Omron CX-Programmer project NewProject (CX-Programmer 9.41)

# PLC CJ1CJ2CS1ModbusSinglePort: CJ1M CPU11
I/O table (CPU CJ1M-CPU11): rack 0 slot 0 CJ1W-SCU41-V1

## Global symbols (name address type ; comment)
Clear_Error_Log W215.03 BOOL
Consecutive_Writes W217 INT
Current_Stack_Pointer W2 DWORD
EasyModbusPort1Command1 D32300 CHANNEL
EasyModbusPort1Command10 D32309 CHANNEL
EasyModbusPort1Command2 D32301 CHANNEL
EasyModbusPort1Command3 D32302 CHANNEL
EasyModbusPort1Command4 D32303 CHANNEL
EasyModbusPort1Command5 D32304 CHANNEL
EasyModbusPort1Command6 D32305 CHANNEL
EasyModbusPort1Command7 D32306 CHANNEL
EasyModbusPort1Command8 D32307 CHANNEL
EasyModbusPort1Command9 D32308 CHANNEL
EasyModbusPort1Response1 D32350 CHANNEL
EasyModbusPort1Response10 D32359 CHANNEL
EasyModbusPort1Response2 D32351 CHANNEL
EasyModbusPort1Response3 D32352 CHANNEL
EasyModbusPort1Response4 D32353 CHANNEL
EasyModbusPort1Response5 D32354 CHANNEL
EasyModbusPort1Response6 D32355 CHANNEL
EasyModbusPort1Response7 D32356 CHANNEL
EasyModbusPort1Response8 D32357 CHANNEL
EasyModbusPort1Response9 D32358 CHANNEL
Easy_Modbus_Execute A640.00 BOOL
Easy_Modbus_NG_Complete A640.02 BOOL
Easy_Modbus_OK_Complete A640.01 BOOL
EndOfListMarkerReadItem1 D5009 CHANNEL
EndOfListMarkerReadItem10 D5099 CHANNEL
EndOfListMarkerReadItem100 D5999 CHANNEL
EndOfListMarkerReadItem11 D5109 CHANNEL
EndOfListMarkerReadItem12 D5119 CHANNEL
EndOfListMarkerReadItem13 D5129 CHANNEL
EndOfListMarkerReadItem14 D5139 CHANNEL
EndOfListMarkerReadItem15 D5149 CHANNEL
EndOfListMarkerReadItem16 D5159 CHANNEL
EndOfListMarkerReadItem17 D5169 CHANNEL
EndOfListMarkerReadItem18 D5179 CHANNEL
EndOfListMarkerReadItem19 D5189 CHANNEL
EndOfListMarkerReadItem2 D5019 CHANNEL
EndOfListMarkerReadItem20 D5199 CHANNEL
EndOfListMarkerReadItem21 D5209 CHANNEL
EndOfListMarkerReadItem22 D5219 CHANNEL
EndOfListMarkerReadItem23 D5229 CHANNEL
EndOfListMarkerReadItem24 D5239 CHANNEL
EndOfListMarkerReadItem25 D5249 CHANNEL
EndOfListMarkerReadItem26 D5259 CHANNEL
EndOfListMarkerReadItem27 D5269 CHANNEL
EndOfListMarkerReadItem28 D5279 CHANNEL
EndOfListMarkerReadItem29 D5289 CHANNEL
EndOfListMarkerReadItem3 D5029 CHANNEL
EndOfListMarkerReadItem30 D5299 CHANNEL
EndOfListMarkerReadItem31 D5309 CHANNEL
EndOfListMarkerReadItem32 D5319 CHANNEL
EndOfListMarkerReadItem33 D5329 CHANNEL
EndOfListMarkerReadItem34 D5339 CHANNEL
EndOfListMarkerReadItem35 D5349 CHANNEL
EndOfListMarkerReadItem36 D5359 CHANNEL
EndOfListMarkerReadItem37 D5369 CHANNEL
EndOfListMarkerReadItem38 D5379 CHANNEL
EndOfListMarkerReadItem39 D5389 CHANNEL
EndOfListMarkerReadItem4 D5039 CHANNEL
EndOfListMarkerReadItem40 D5399 CHANNEL
EndOfListMarkerReadItem41 D5409 CHANNEL
EndOfListMarkerReadItem42 D5419 CHANNEL
EndOfListMarkerReadItem43 D5429 CHANNEL
EndOfListMarkerReadItem44 D5439 CHANNEL
EndOfListMarkerReadItem45 D5449 CHANNEL
EndOfListMarkerReadItem46 D5459 CHANNEL
EndOfListMarkerReadItem47 D5469 CHANNEL
EndOfListMarkerReadItem48 D5479 CHANNEL
EndOfListMarkerReadItem49 D5489 CHANNEL
EndOfListMarkerReadItem5 D5049 CHANNEL
EndOfListMarkerReadItem50 D5499 CHANNEL
EndOfListMarkerReadItem51 D5509 CHANNEL
EndOfListMarkerReadItem52 D5519 CHANNEL
EndOfListMarkerReadItem53 D5529 CHANNEL
EndOfListMarkerReadItem54 D5539 CHANNEL
EndOfListMarkerReadItem55 D5549 CHANNEL
EndOfListMarkerReadItem56 D5559 CHANNEL
EndOfListMarkerReadItem57 D5569 CHANNEL
EndOfListMarkerReadItem58 D5579 CHANNEL
EndOfListMarkerReadItem59 D5589 CHANNEL
EndOfListMarkerReadItem6 D5059 CHANNEL
EndOfListMarkerReadItem60 D5599 CHANNEL
EndOfListMarkerReadItem61 D5609 CHANNEL
EndOfListMarkerReadItem62 D5619 CHANNEL
EndOfListMarkerReadItem63 D5629 CHANNEL
EndOfListMarkerReadItem64 D5639 CHANNEL
EndOfListMarkerReadItem65 D5649 CHANNEL
EndOfListMarkerReadItem66 D5659 CHANNEL
EndOfListMarkerReadItem67 D5669 CHANNEL
EndOfListMarkerReadItem68 D5679 CHANNEL
EndOfListMarkerReadItem69 D5689 CHANNEL
EndOfListMarkerReadItem7 D5069 CHANNEL
EndOfListMarkerReadItem70 D5699 CHANNEL
EndOfListMarkerReadItem71 D5709 CHANNEL
EndOfListMarkerReadItem72 D5719 CHANNEL
EndOfListMarkerReadItem73 D5729 CHANNEL
EndOfListMarkerReadItem74 D5739 CHANNEL
EndOfListMarkerReadItem75 D5749 CHANNEL
EndOfListMarkerReadItem76 D5759 CHANNEL
EndOfListMarkerReadItem77 D5769 CHANNEL
EndOfListMarkerReadItem78 D5779 CHANNEL
EndOfListMarkerReadItem79 D5789 CHANNEL
EndOfListMarkerReadItem8 D5079 CHANNEL
EndOfListMarkerReadItem80 D5799 CHANNEL
EndOfListMarkerReadItem81 D5809 CHANNEL
EndOfListMarkerReadItem82 D5819 CHANNEL
EndOfListMarkerReadItem83 D5829 CHANNEL
EndOfListMarkerReadItem84 D5839 CHANNEL
EndOfListMarkerReadItem85 D5849 CHANNEL
EndOfListMarkerReadItem86 D5859 CHANNEL
EndOfListMarkerReadItem87 D5869 CHANNEL
EndOfListMarkerReadItem88 D5879 CHANNEL
EndOfListMarkerReadItem89 D5889 CHANNEL
EndOfListMarkerReadItem9 D5089 CHANNEL
EndOfListMarkerReadItem90 D5899 CHANNEL
EndOfListMarkerReadItem91 D5909 CHANNEL
EndOfListMarkerReadItem92 D5919 CHANNEL
EndOfListMarkerReadItem93 D5929 CHANNEL
EndOfListMarkerReadItem94 D5939 CHANNEL
EndOfListMarkerReadItem95 D5949 CHANNEL
EndOfListMarkerReadItem96 D5959 CHANNEL
EndOfListMarkerReadItem97 D5969 CHANNEL
EndOfListMarkerReadItem98 D5979 CHANNEL
EndOfListMarkerReadItem99 D5989 CHANNEL
EndOfListMarkerWriteItem1 D6009 CHANNEL
EndOfListMarkerWriteItem10 D6099 CHANNEL
EndOfListMarkerWriteItem100 D6999 CHANNEL
EndOfListMarkerWriteItem11 D6109 CHANNEL
EndOfListMarkerWriteItem12 D6119 CHANNEL
EndOfListMarkerWriteItem13 D6129 CHANNEL
EndOfListMarkerWriteItem14 D6139 CHANNEL
EndOfListMarkerWriteItem15 D6149 CHANNEL
EndOfListMarkerWriteItem16 D6159 CHANNEL
EndOfListMarkerWriteItem17 D6169 CHANNEL
EndOfListMarkerWriteItem18 D6179 CHANNEL
EndOfListMarkerWriteItem19 D6189 CHANNEL
EndOfListMarkerWriteItem2 D6019 CHANNEL
EndOfListMarkerWriteItem20 D6199 CHANNEL
EndOfListMarkerWriteItem21 D6209 CHANNEL
EndOfListMarkerWriteItem22 D6219 CHANNEL
EndOfListMarkerWriteItem23 D6229 CHANNEL
EndOfListMarkerWriteItem24 D6239 CHANNEL
EndOfListMarkerWriteItem25 D6249 CHANNEL
EndOfListMarkerWriteItem26 D6259 CHANNEL
EndOfListMarkerWriteItem27 D6269 CHANNEL
EndOfListMarkerWriteItem28 D6279 CHANNEL
EndOfListMarkerWriteItem29 D6289 CHANNEL
EndOfListMarkerWriteItem3 D6029 CHANNEL
EndOfListMarkerWriteItem30 D6299 CHANNEL
EndOfListMarkerWriteItem31 D6309 CHANNEL
EndOfListMarkerWriteItem32 D6319 CHANNEL
EndOfListMarkerWriteItem33 D6329 CHANNEL
EndOfListMarkerWriteItem34 D6339 CHANNEL
EndOfListMarkerWriteItem35 D6349 CHANNEL
EndOfListMarkerWriteItem36 D6359 CHANNEL
EndOfListMarkerWriteItem37 D6369 CHANNEL
EndOfListMarkerWriteItem38 D6379 CHANNEL
EndOfListMarkerWriteItem39 D6389 CHANNEL
EndOfListMarkerWriteItem4 D6039 CHANNEL
EndOfListMarkerWriteItem40 D6399 CHANNEL
EndOfListMarkerWriteItem41 D6409 CHANNEL
EndOfListMarkerWriteItem42 D6419 CHANNEL
EndOfListMarkerWriteItem43 D6429 CHANNEL
EndOfListMarkerWriteItem44 D6439 CHANNEL
EndOfListMarkerWriteItem45 D6449 CHANNEL
EndOfListMarkerWriteItem46 D6459 CHANNEL
EndOfListMarkerWriteItem47 D6469 CHANNEL
EndOfListMarkerWriteItem48 D6479 CHANNEL
EndOfListMarkerWriteItem49 D6489 CHANNEL
EndOfListMarkerWriteItem5 D6049 CHANNEL
EndOfListMarkerWriteItem50 D6499 CHANNEL
EndOfListMarkerWriteItem51 D6509 CHANNEL
EndOfListMarkerWriteItem52 D6519 CHANNEL
EndOfListMarkerWriteItem53 D6529 CHANNEL
EndOfListMarkerWriteItem54 D6539 CHANNEL
EndOfListMarkerWriteItem55 D6549 CHANNEL
EndOfListMarkerWriteItem56 D6559 CHANNEL
EndOfListMarkerWriteItem57 D6569 CHANNEL
EndOfListMarkerWriteItem58 D6579 CHANNEL
EndOfListMarkerWriteItem59 D6589 CHANNEL
EndOfListMarkerWriteItem6 D6059 CHANNEL
EndOfListMarkerWriteItem60 D6599 CHANNEL
EndOfListMarkerWriteItem61 D6609 CHANNEL
EndOfListMarkerWriteItem62 D6619 CHANNEL
EndOfListMarkerWriteItem63 D6629 CHANNEL
EndOfListMarkerWriteItem64 D6639 CHANNEL
EndOfListMarkerWriteItem65 D6649 CHANNEL
EndOfListMarkerWriteItem66 D6659 CHANNEL
EndOfListMarkerWriteItem67 D6669 CHANNEL
EndOfListMarkerWriteItem68 D6679 CHANNEL
EndOfListMarkerWriteItem69 D6689 CHANNEL
EndOfListMarkerWriteItem7 D6069 CHANNEL
EndOfListMarkerWriteItem70 D6699 CHANNEL
EndOfListMarkerWriteItem71 D6709 CHANNEL
EndOfListMarkerWriteItem72 D6719 CHANNEL
EndOfListMarkerWriteItem73 D6729 CHANNEL
EndOfListMarkerWriteItem74 D6739 CHANNEL
EndOfListMarkerWriteItem75 D6749 CHANNEL
EndOfListMarkerWriteItem76 D6759 CHANNEL
EndOfListMarkerWriteItem77 D6769 CHANNEL
EndOfListMarkerWriteItem78 D6779 CHANNEL
EndOfListMarkerWriteItem79 D6789 CHANNEL
EndOfListMarkerWriteItem8 D6079 CHANNEL
EndOfListMarkerWriteItem80 D6799 CHANNEL
EndOfListMarkerWriteItem81 D6809 CHANNEL
EndOfListMarkerWriteItem82 D6819 CHANNEL
EndOfListMarkerWriteItem83 D6829 CHANNEL
EndOfListMarkerWriteItem84 D6839 CHANNEL
EndOfListMarkerWriteItem85 D6849 CHANNEL
EndOfListMarkerWriteItem86 D6859 CHANNEL
EndOfListMarkerWriteItem87 D6869 CHANNEL
EndOfListMarkerWriteItem88 D6879 CHANNEL
EndOfListMarkerWriteItem89 D6889 CHANNEL
EndOfListMarkerWriteItem9 D6089 CHANNEL
EndOfListMarkerWriteItem90 D6899 CHANNEL
EndOfListMarkerWriteItem91 D6909 CHANNEL
EndOfListMarkerWriteItem92 D6919 CHANNEL
EndOfListMarkerWriteItem93 D6929 CHANNEL
EndOfListMarkerWriteItem94 D6939 CHANNEL
EndOfListMarkerWriteItem95 D6949 CHANNEL
EndOfListMarkerWriteItem96 D6959 CHANNEL
EndOfListMarkerWriteItem97 D6969 CHANNEL
EndOfListMarkerWriteItem98 D6979 CHANNEL
EndOfListMarkerWriteItem99 D6989 CHANNEL
FirstWordResponseDataReadItem1 D5004 CHANNEL
FirstWordResponseDataReadItem10 D5094 CHANNEL
FirstWordResponseDataReadItem100 D5994 CHANNEL
FirstWordResponseDataReadItem11 D5104 CHANNEL
FirstWordResponseDataReadItem12 D5114 CHANNEL
FirstWordResponseDataReadItem13 D5124 CHANNEL
FirstWordResponseDataReadItem14 D5134 CHANNEL
FirstWordResponseDataReadItem15 D5144 CHANNEL
FirstWordResponseDataReadItem16 D5154 CHANNEL
FirstWordResponseDataReadItem17 D5164 CHANNEL
FirstWordResponseDataReadItem18 D5174 CHANNEL
FirstWordResponseDataReadItem19 D5184 CHANNEL
FirstWordResponseDataReadItem2 D5014 CHANNEL
FirstWordResponseDataReadItem20 D5194 CHANNEL
FirstWordResponseDataReadItem21 D5204 CHANNEL
FirstWordResponseDataReadItem22 D5214 CHANNEL
FirstWordResponseDataReadItem23 D5224 CHANNEL
FirstWordResponseDataReadItem24 D5234 CHANNEL
FirstWordResponseDataReadItem25 D5244 CHANNEL
FirstWordResponseDataReadItem26 D5254 CHANNEL
FirstWordResponseDataReadItem27 D5264 CHANNEL
FirstWordResponseDataReadItem28 D5274 CHANNEL
FirstWordResponseDataReadItem29 D5284 CHANNEL
FirstWordResponseDataReadItem3 D5024 CHANNEL
FirstWordResponseDataReadItem30 D5294 CHANNEL
FirstWordResponseDataReadItem31 D5304 CHANNEL
FirstWordResponseDataReadItem32 D5314 CHANNEL
FirstWordResponseDataReadItem33 D5324 CHANNEL
FirstWordResponseDataReadItem34 D5334 CHANNEL
FirstWordResponseDataReadItem35 D5344 CHANNEL
FirstWordResponseDataReadItem36 D5354 CHANNEL
FirstWordResponseDataReadItem37 D5364 CHANNEL
FirstWordResponseDataReadItem38 D5374 CHANNEL
FirstWordResponseDataReadItem39 D5384 CHANNEL
FirstWordResponseDataReadItem4 D5034 CHANNEL
FirstWordResponseDataReadItem40 D5394 CHANNEL
FirstWordResponseDataReadItem41 D5404 CHANNEL
FirstWordResponseDataReadItem42 D5414 CHANNEL
FirstWordResponseDataReadItem43 D5424 CHANNEL
FirstWordResponseDataReadItem44 D5434 CHANNEL
FirstWordResponseDataReadItem45 D5444 CHANNEL
FirstWordResponseDataReadItem46 D5454 CHANNEL
FirstWordResponseDataReadItem47 D5464 CHANNEL
FirstWordResponseDataReadItem48 D5474 CHANNEL
FirstWordResponseDataReadItem49 D5484 CHANNEL
FirstWordResponseDataReadItem5 D5044 CHANNEL
FirstWordResponseDataReadItem50 D5494 CHANNEL
FirstWordResponseDataReadItem51 D5504 CHANNEL
FirstWordResponseDataReadItem52 D5514 CHANNEL
FirstWordResponseDataReadItem53 D5524 CHANNEL
FirstWordResponseDataReadItem54 D5534 CHANNEL
FirstWordResponseDataReadItem55 D5544 CHANNEL
FirstWordResponseDataReadItem56 D5554 CHANNEL
FirstWordResponseDataReadItem57 D5564 CHANNEL
FirstWordResponseDataReadItem58 D5574 CHANNEL
FirstWordResponseDataReadItem59 D5584 CHANNEL
FirstWordResponseDataReadItem6 D5054 CHANNEL
FirstWordResponseDataReadItem60 D5594 CHANNEL
FirstWordResponseDataReadItem61 D5604 CHANNEL
FirstWordResponseDataReadItem62 D5614 CHANNEL
FirstWordResponseDataReadItem63 D5624 CHANNEL
FirstWordResponseDataReadItem64 D5634 CHANNEL
FirstWordResponseDataReadItem65 D5644 CHANNEL
FirstWordResponseDataReadItem66 D5654 CHANNEL
FirstWordResponseDataReadItem67 D5664 CHANNEL
FirstWordResponseDataReadItem68 D5674 CHANNEL
FirstWordResponseDataReadItem69 D5684 CHANNEL
FirstWordResponseDataReadItem7 D5064 CHANNEL
FirstWordResponseDataReadItem70 D5694 CHANNEL
FirstWordResponseDataReadItem71 D5704 CHANNEL
FirstWordResponseDataReadItem72 D5714 CHANNEL
FirstWordResponseDataReadItem73 D5724 CHANNEL
FirstWordResponseDataReadItem74 D5734 CHANNEL
FirstWordResponseDataReadItem75 D5744 CHANNEL
FirstWordResponseDataReadItem76 D5754 CHANNEL
FirstWordResponseDataReadItem77 D5764 CHANNEL
FirstWordResponseDataReadItem78 D5774 CHANNEL
FirstWordResponseDataReadItem79 D5784 CHANNEL
FirstWordResponseDataReadItem8 D5074 CHANNEL
FirstWordResponseDataReadItem80 D5794 CHANNEL
FirstWordResponseDataReadItem81 D5804 CHANNEL
FirstWordResponseDataReadItem82 D5814 CHANNEL
FirstWordResponseDataReadItem83 D5824 CHANNEL
FirstWordResponseDataReadItem84 D5834 CHANNEL
FirstWordResponseDataReadItem85 D5844 CHANNEL
FirstWordResponseDataReadItem86 D5854 CHANNEL
FirstWordResponseDataReadItem87 D5864 CHANNEL
FirstWordResponseDataReadItem88 D5874 CHANNEL
FirstWordResponseDataReadItem89 D5884 CHANNEL
FirstWordResponseDataReadItem9 D5084 CHANNEL
FirstWordResponseDataReadItem90 D5894 CHANNEL
FirstWordResponseDataReadItem91 D5904 CHANNEL
FirstWordResponseDataReadItem92 D5914 CHANNEL
FirstWordResponseDataReadItem93 D5924 CHANNEL
FirstWordResponseDataReadItem94 D5934 CHANNEL
FirstWordResponseDataReadItem95 D5944 CHANNEL
FirstWordResponseDataReadItem96 D5954 CHANNEL
FirstWordResponseDataReadItem97 D5964 CHANNEL
FirstWordResponseDataReadItem98 D5974 CHANNEL
FirstWordResponseDataReadItem99 D5984 CHANNEL
FirstWordWriteDataMirrorWriteItem1 D6006 CHANNEL
FirstWordWriteDataMirrorWriteItem10 D6096 CHANNEL
FirstWordWriteDataMirrorWriteItem100 D6996 CHANNEL
FirstWordWriteDataMirrorWriteItem11 D6106 CHANNEL
FirstWordWriteDataMirrorWriteItem12 D6116 CHANNEL
FirstWordWriteDataMirrorWriteItem13 D6126 CHANNEL
FirstWordWriteDataMirrorWriteItem14 D6136 CHANNEL
FirstWordWriteDataMirrorWriteItem15 D6146 CHANNEL
FirstWordWriteDataMirrorWriteItem16 D6156 CHANNEL
FirstWordWriteDataMirrorWriteItem17 D6166 CHANNEL
FirstWordWriteDataMirrorWriteItem18 D6176 CHANNEL
FirstWordWriteDataMirrorWriteItem19 D6186 CHANNEL
FirstWordWriteDataMirrorWriteItem2 D6016 CHANNEL
FirstWordWriteDataMirrorWriteItem20 D6196 CHANNEL
FirstWordWriteDataMirrorWriteItem21 D6206 CHANNEL
FirstWordWriteDataMirrorWriteItem22 D6216 CHANNEL
FirstWordWriteDataMirrorWriteItem23 D6226 CHANNEL
FirstWordWriteDataMirrorWriteItem24 D6236 CHANNEL
FirstWordWriteDataMirrorWriteItem25 D6246 CHANNEL
FirstWordWriteDataMirrorWriteItem26 D6256 CHANNEL
FirstWordWriteDataMirrorWriteItem27 D6266 CHANNEL
FirstWordWriteDataMirrorWriteItem28 D6276 CHANNEL
FirstWordWriteDataMirrorWriteItem29 D6286 CHANNEL
FirstWordWriteDataMirrorWriteItem3 D6026 CHANNEL
FirstWordWriteDataMirrorWriteItem30 D6296 CHANNEL
FirstWordWriteDataMirrorWriteItem31 D6306 CHANNEL
FirstWordWriteDataMirrorWriteItem32 D6316 CHANNEL
FirstWordWriteDataMirrorWriteItem33 D6326 CHANNEL
FirstWordWriteDataMirrorWriteItem34 D6336 CHANNEL
FirstWordWriteDataMirrorWriteItem35 D6346 CHANNEL
FirstWordWriteDataMirrorWriteItem36 D6356 CHANNEL
FirstWordWriteDataMirrorWriteItem37 D6366 CHANNEL
FirstWordWriteDataMirrorWriteItem38 D6376 CHANNEL
FirstWordWriteDataMirrorWriteItem39 D6386 CHANNEL
FirstWordWriteDataMirrorWriteItem4 D6036 CHANNEL
FirstWordWriteDataMirrorWriteItem40 D6396 CHANNEL
FirstWordWriteDataMirrorWriteItem41 D6406 CHANNEL
FirstWordWriteDataMirrorWriteItem42 D6416 CHANNEL
FirstWordWriteDataMirrorWriteItem43 D6426 CHANNEL
FirstWordWriteDataMirrorWriteItem44 D6436 CHANNEL
FirstWordWriteDataMirrorWriteItem45 D6446 CHANNEL
FirstWordWriteDataMirrorWriteItem46 D6456 CHANNEL
FirstWordWriteDataMirrorWriteItem47 D6466 CHANNEL
FirstWordWriteDataMirrorWriteItem48 D6476 CHANNEL
FirstWordWriteDataMirrorWriteItem49 D6486 CHANNEL
FirstWordWriteDataMirrorWriteItem5 D6046 CHANNEL
FirstWordWriteDataMirrorWriteItem50 D6496 CHANNEL
FirstWordWriteDataMirrorWriteItem51 D6506 CHANNEL
FirstWordWriteDataMirrorWriteItem52 D6516 CHANNEL
FirstWordWriteDataMirrorWriteItem53 D6526 CHANNEL
FirstWordWriteDataMirrorWriteItem54 D6536 CHANNEL
FirstWordWriteDataMirrorWriteItem55 D6546 CHANNEL
FirstWordWriteDataMirrorWriteItem56 D6556 CHANNEL
FirstWordWriteDataMirrorWriteItem57 D6566 CHANNEL
FirstWordWriteDataMirrorWriteItem58 D6576 CHANNEL
FirstWordWriteDataMirrorWriteItem59 D6586 CHANNEL
FirstWordWriteDataMirrorWriteItem6 D6056 CHANNEL
FirstWordWriteDataMirrorWriteItem60 D6596 CHANNEL
FirstWordWriteDataMirrorWriteItem61 D6606 CHANNEL
FirstWordWriteDataMirrorWriteItem62 D6616 CHANNEL
FirstWordWriteDataMirrorWriteItem63 D6626 CHANNEL
FirstWordWriteDataMirrorWriteItem64 D6636 CHANNEL
FirstWordWriteDataMirrorWriteItem65 D6646 CHANNEL
FirstWordWriteDataMirrorWriteItem66 D6656 CHANNEL
FirstWordWriteDataMirrorWriteItem67 D6666 CHANNEL
FirstWordWriteDataMirrorWriteItem68 D6676 CHANNEL
FirstWordWriteDataMirrorWriteItem69 D6686 CHANNEL
FirstWordWriteDataMirrorWriteItem7 D6066 CHANNEL
FirstWordWriteDataMirrorWriteItem70 D6696 CHANNEL
FirstWordWriteDataMirrorWriteItem71 D6706 CHANNEL
FirstWordWriteDataMirrorWriteItem72 D6716 CHANNEL
FirstWordWriteDataMirrorWriteItem73 D6726 CHANNEL
FirstWordWriteDataMirrorWriteItem74 D6736 CHANNEL
FirstWordWriteDataMirrorWriteItem75 D6746 CHANNEL
FirstWordWriteDataMirrorWriteItem76 D6756 CHANNEL
FirstWordWriteDataMirrorWriteItem77 D6766 CHANNEL
FirstWordWriteDataMirrorWriteItem78 D6776 CHANNEL
FirstWordWriteDataMirrorWriteItem79 D6786 CHANNEL
FirstWordWriteDataMirrorWriteItem8 D6076 CHANNEL
FirstWordWriteDataMirrorWriteItem80 D6796 CHANNEL
FirstWordWriteDataMirrorWriteItem81 D6806 CHANNEL
FirstWordWriteDataMirrorWriteItem82 D6816 CHANNEL
FirstWordWriteDataMirrorWriteItem83 D6826 CHANNEL
FirstWordWriteDataMirrorWriteItem84 D6836 CHANNEL
FirstWordWriteDataMirrorWriteItem85 D6846 CHANNEL
FirstWordWriteDataMirrorWriteItem86 D6856 CHANNEL
FirstWordWriteDataMirrorWriteItem87 D6866 CHANNEL
FirstWordWriteDataMirrorWriteItem88 D6876 CHANNEL
FirstWordWriteDataMirrorWriteItem89 D6886 CHANNEL
FirstWordWriteDataMirrorWriteItem9 D6086 CHANNEL
FirstWordWriteDataMirrorWriteItem90 D6896 CHANNEL
FirstWordWriteDataMirrorWriteItem91 D6906 CHANNEL
FirstWordWriteDataMirrorWriteItem92 D6916 CHANNEL
FirstWordWriteDataMirrorWriteItem93 D6926 CHANNEL
FirstWordWriteDataMirrorWriteItem94 D6936 CHANNEL
FirstWordWriteDataMirrorWriteItem95 D6946 CHANNEL
FirstWordWriteDataMirrorWriteItem96 D6956 CHANNEL
FirstWordWriteDataMirrorWriteItem97 D6966 CHANNEL
FirstWordWriteDataMirrorWriteItem98 D6976 CHANNEL
FirstWordWriteDataMirrorWriteItem99 D6986 CHANNEL
FirstWordWriteDataWriteItem1 D6004 CHANNEL
FirstWordWriteDataWriteItem10 D6094 CHANNEL
FirstWordWriteDataWriteItem100 D6994 CHANNEL
FirstWordWriteDataWriteItem11 D6104 CHANNEL
FirstWordWriteDataWriteItem12 D6114 CHANNEL
FirstWordWriteDataWriteItem13 D6124 CHANNEL
FirstWordWriteDataWriteItem14 D6134 CHANNEL
FirstWordWriteDataWriteItem15 D6144 CHANNEL
FirstWordWriteDataWriteItem16 D6154 CHANNEL
FirstWordWriteDataWriteItem17 D6164 CHANNEL
FirstWordWriteDataWriteItem18 D6174 CHANNEL
FirstWordWriteDataWriteItem19 D6184 CHANNEL
FirstWordWriteDataWriteItem2 D6014 CHANNEL
FirstWordWriteDataWriteItem20 D6194 CHANNEL
FirstWordWriteDataWriteItem21 D6204 CHANNEL
FirstWordWriteDataWriteItem22 D6214 CHANNEL
FirstWordWriteDataWriteItem23 D6224 CHANNEL
FirstWordWriteDataWriteItem24 D6234 CHANNEL
FirstWordWriteDataWriteItem25 D6244 CHANNEL
FirstWordWriteDataWriteItem26 D6254 CHANNEL
FirstWordWriteDataWriteItem27 D6264 CHANNEL
FirstWordWriteDataWriteItem28 D6274 CHANNEL
FirstWordWriteDataWriteItem29 D6284 CHANNEL
FirstWordWriteDataWriteItem3 D6024 CHANNEL
FirstWordWriteDataWriteItem30 D6294 CHANNEL
FirstWordWriteDataWriteItem31 D6304 CHANNEL
FirstWordWriteDataWriteItem32 D6314 CHANNEL
FirstWordWriteDataWriteItem33 D6324 CHANNEL
FirstWordWriteDataWriteItem34 D6334 CHANNEL
FirstWordWriteDataWriteItem35 D6344 CHANNEL
FirstWordWriteDataWriteItem36 D6354 CHANNEL
FirstWordWriteDataWriteItem37 D6364 CHANNEL
FirstWordWriteDataWriteItem38 D6374 CHANNEL
FirstWordWriteDataWriteItem39 D6384 CHANNEL
FirstWordWriteDataWriteItem4 D6034 CHANNEL
FirstWordWriteDataWriteItem40 D6394 CHANNEL
FirstWordWriteDataWriteItem41 D6404 CHANNEL
FirstWordWriteDataWriteItem42 D6414 CHANNEL
FirstWordWriteDataWriteItem43 D6424 CHANNEL
FirstWordWriteDataWriteItem44 D6434 CHANNEL
FirstWordWriteDataWriteItem45 D6444 CHANNEL
FirstWordWriteDataWriteItem46 D6454 CHANNEL
FirstWordWriteDataWriteItem47 D6464 CHANNEL
FirstWordWriteDataWriteItem48 D6474 CHANNEL
FirstWordWriteDataWriteItem49 D6484 CHANNEL
FirstWordWriteDataWriteItem5 D6044 CHANNEL
FirstWordWriteDataWriteItem50 D6494 CHANNEL
FirstWordWriteDataWriteItem51 D6504 CHANNEL
FirstWordWriteDataWriteItem52 D6514 CHANNEL
FirstWordWriteDataWriteItem53 D6524 CHANNEL
FirstWordWriteDataWriteItem54 D6534 CHANNEL
FirstWordWriteDataWriteItem55 D6544 CHANNEL
FirstWordWriteDataWriteItem56 D6554 CHANNEL
FirstWordWriteDataWriteItem57 D6564 CHANNEL
FirstWordWriteDataWriteItem58 D6574 CHANNEL
FirstWordWriteDataWriteItem59 D6584 CHANNEL
FirstWordWriteDataWriteItem6 D6054 CHANNEL
FirstWordWriteDataWriteItem60 D6594 CHANNEL
FirstWordWriteDataWriteItem61 D6604 CHANNEL
FirstWordWriteDataWriteItem62 D6614 CHANNEL
FirstWordWriteDataWriteItem63 D6624 CHANNEL
FirstWordWriteDataWriteItem64 D6634 CHANNEL
FirstWordWriteDataWriteItem65 D6644 CHANNEL
FirstWordWriteDataWriteItem66 D6654 CHANNEL
FirstWordWriteDataWriteItem67 D6664 CHANNEL
FirstWordWriteDataWriteItem68 D6674 CHANNEL
FirstWordWriteDataWriteItem69 D6684 CHANNEL
FirstWordWriteDataWriteItem7 D6064 CHANNEL
FirstWordWriteDataWriteItem70 D6694 CHANNEL
FirstWordWriteDataWriteItem71 D6704 CHANNEL
FirstWordWriteDataWriteItem72 D6714 CHANNEL
FirstWordWriteDataWriteItem73 D6724 CHANNEL
FirstWordWriteDataWriteItem74 D6734 CHANNEL
FirstWordWriteDataWriteItem75 D6744 CHANNEL
FirstWordWriteDataWriteItem76 D6754 CHANNEL
FirstWordWriteDataWriteItem77 D6764 CHANNEL
FirstWordWriteDataWriteItem78 D6774 CHANNEL
FirstWordWriteDataWriteItem79 D6784 CHANNEL
FirstWordWriteDataWriteItem8 D6074 CHANNEL
FirstWordWriteDataWriteItem80 D6794 CHANNEL
FirstWordWriteDataWriteItem81 D6804 CHANNEL
FirstWordWriteDataWriteItem82 D6814 CHANNEL
FirstWordWriteDataWriteItem83 D6824 CHANNEL
FirstWordWriteDataWriteItem84 D6834 CHANNEL
FirstWordWriteDataWriteItem85 D6844 CHANNEL
FirstWordWriteDataWriteItem86 D6854 CHANNEL
FirstWordWriteDataWriteItem87 D6864 CHANNEL
FirstWordWriteDataWriteItem88 D6874 CHANNEL
FirstWordWriteDataWriteItem89 D6884 CHANNEL
FirstWordWriteDataWriteItem9 D6084 CHANNEL
FirstWordWriteDataWriteItem90 D6894 CHANNEL
FirstWordWriteDataWriteItem91 D6904 CHANNEL
FirstWordWriteDataWriteItem92 D6914 CHANNEL
FirstWordWriteDataWriteItem93 D6924 CHANNEL
FirstWordWriteDataWriteItem94 D6934 CHANNEL
FirstWordWriteDataWriteItem95 D6944 CHANNEL
FirstWordWriteDataWriteItem96 D6954 CHANNEL
FirstWordWriteDataWriteItem97 D6964 CHANNEL
FirstWordWriteDataWriteItem98 D6974 CHANNEL
FirstWordWriteDataWriteItem99 D6984 CHANNEL
LastModbusCommandReceived1 W240 CHANNEL
LastModbusCommandReceived10 W249 CHANNEL
LastModbusCommandReceived2 W241 CHANNEL
LastModbusCommandReceived3 W242 CHANNEL
LastModbusCommandReceived4 W243 CHANNEL
LastModbusCommandReceived5 W244 CHANNEL
LastModbusCommandReceived6 W245 CHANNEL
LastModbusCommandReceived7 W246 CHANNEL
LastModbusCommandReceived8 W247 CHANNEL
LastModbusCommandReceived9 W248 CHANNEL
LastModbusCommandSent1 W230 CHANNEL
LastModbusCommandSent10 W239 CHANNEL
LastModbusCommandSent2 W231 CHANNEL
LastModbusCommandSent3 W232 CHANNEL
LastModbusCommandSent4 W233 CHANNEL
LastModbusCommandSent5 W234 CHANNEL
LastModbusCommandSent6 W235 CHANNEL
LastModbusCommandSent7 W236 CHANNEL
LastModbusCommandSent8 W237 CHANNEL
LastModbusCommandSent9 W238 CHANNEL
LogAnEasyModbusError W215.00 BOOL
Logical_Port_Ready A202.07 BOOL
ModbusErrorDMAddress1 W221 CHANNEL
ModbusErrorDMAddress2 W223 CHANNEL
ModbusErrorDMAddress3 W225 CHANNEL
ModbusErrorDMAddress4 W227 CHANNEL
ModbusErrorDMAddress5 W229 CHANNEL
ModbusErrorNodeFunction1 W220 CHANNEL
ModbusErrorNodeFunction2 W222 CHANNEL
ModbusErrorNodeFunction3 W224 CHANNEL
ModbusErrorNodeFunction4 W226 CHANNEL
ModbusErrorNodeFunction5 W228 CHANNEL
ModbusFunctionCodeReadItem1 D5001 CHANNEL
ModbusFunctionCodeReadItem10 D5091 CHANNEL
ModbusFunctionCodeReadItem100 D5991 CHANNEL
ModbusFunctionCodeReadItem11 D5101 CHANNEL
ModbusFunctionCodeReadItem12 D5111 CHANNEL
ModbusFunctionCodeReadItem13 D5121 CHANNEL
ModbusFunctionCodeReadItem14 D5131 CHANNEL
ModbusFunctionCodeReadItem15 D5141 CHANNEL
ModbusFunctionCodeReadItem16 D5151 CHANNEL
ModbusFunctionCodeReadItem17 D5161 CHANNEL
ModbusFunctionCodeReadItem18 D5171 CHANNEL
ModbusFunctionCodeReadItem19 D5181 CHANNEL
ModbusFunctionCodeReadItem2 D5011 CHANNEL
ModbusFunctionCodeReadItem20 D5191 CHANNEL
ModbusFunctionCodeReadItem21 D5201 CHANNEL
ModbusFunctionCodeReadItem22 D5211 CHANNEL
ModbusFunctionCodeReadItem23 D5221 CHANNEL
ModbusFunctionCodeReadItem24 D5231 CHANNEL
ModbusFunctionCodeReadItem25 D5241 CHANNEL
ModbusFunctionCodeReadItem26 D5251 CHANNEL
ModbusFunctionCodeReadItem27 D5261 CHANNEL
ModbusFunctionCodeReadItem28 D5271 CHANNEL
ModbusFunctionCodeReadItem29 D5281 CHANNEL
ModbusFunctionCodeReadItem3 D5021 CHANNEL
ModbusFunctionCodeReadItem30 D5291 CHANNEL
ModbusFunctionCodeReadItem31 D5301 CHANNEL
ModbusFunctionCodeReadItem32 D5311 CHANNEL
ModbusFunctionCodeReadItem33 D5321 CHANNEL
ModbusFunctionCodeReadItem34 D5331 CHANNEL
ModbusFunctionCodeReadItem35 D5341 CHANNEL
ModbusFunctionCodeReadItem36 D5351 CHANNEL
ModbusFunctionCodeReadItem37 D5361 CHANNEL
ModbusFunctionCodeReadItem38 D5371 CHANNEL
ModbusFunctionCodeReadItem39 D5381 CHANNEL
ModbusFunctionCodeReadItem4 D5031 CHANNEL
ModbusFunctionCodeReadItem40 D5391 CHANNEL
ModbusFunctionCodeReadItem41 D5401 CHANNEL
ModbusFunctionCodeReadItem42 D5411 CHANNEL
ModbusFunctionCodeReadItem43 D5421 CHANNEL
ModbusFunctionCodeReadItem44 D5431 CHANNEL
ModbusFunctionCodeReadItem45 D5441 CHANNEL
ModbusFunctionCodeReadItem46 D5451 CHANNEL
ModbusFunctionCodeReadItem47 D5461 CHANNEL
ModbusFunctionCodeReadItem48 D5471 CHANNEL
ModbusFunctionCodeReadItem49 D5481 CHANNEL
ModbusFunctionCodeReadItem5 D5041 CHANNEL
ModbusFunctionCodeReadItem50 D5491 CHANNEL
ModbusFunctionCodeReadItem51 D5501 CHANNEL
ModbusFunctionCodeReadItem52 D5511 CHANNEL
ModbusFunctionCodeReadItem53 D5521 CHANNEL
ModbusFunctionCodeReadItem54 D5531 CHANNEL
ModbusFunctionCodeReadItem55 D5541 CHANNEL
ModbusFunctionCodeReadItem56 D5551 CHANNEL
ModbusFunctionCodeReadItem57 D5561 CHANNEL
ModbusFunctionCodeReadItem58 D5571 CHANNEL
ModbusFunctionCodeReadItem59 D5581 CHANNEL
ModbusFunctionCodeReadItem6 D5051 CHANNEL
ModbusFunctionCodeReadItem60 D5591 CHANNEL
ModbusFunctionCodeReadItem61 D5601 CHANNEL
ModbusFunctionCodeReadItem62 D5611 CHANNEL
ModbusFunctionCodeReadItem63 D5621 CHANNEL
ModbusFunctionCodeReadItem64 D5631 CHANNEL
ModbusFunctionCodeReadItem65 D5641 CHANNEL
ModbusFunctionCodeReadItem66 D5651 CHANNEL
ModbusFunctionCodeReadItem67 D5661 CHANNEL
ModbusFunctionCodeReadItem68 D5671 CHANNEL
ModbusFunctionCodeReadItem69 D5681 CHANNEL
ModbusFunctionCodeReadItem7 D5061 CHANNEL
ModbusFunctionCodeReadItem70 D5691 CHANNEL
ModbusFunctionCodeReadItem71 D5701 CHANNEL
ModbusFunctionCodeReadItem72 D5711 CHANNEL
ModbusFunctionCodeReadItem73 D5721 CHANNEL
ModbusFunctionCodeReadItem74 D5731 CHANNEL
ModbusFunctionCodeReadItem75 D5741 CHANNEL
ModbusFunctionCodeReadItem76 D5751 CHANNEL
ModbusFunctionCodeReadItem77 D5761 CHANNEL
ModbusFunctionCodeReadItem78 D5771 CHANNEL
ModbusFunctionCodeReadItem79 D5781 CHANNEL
ModbusFunctionCodeReadItem8 D5071 CHANNEL
ModbusFunctionCodeReadItem80 D5791 CHANNEL
ModbusFunctionCodeReadItem81 D5801 CHANNEL
ModbusFunctionCodeReadItem82 D5811 CHANNEL
ModbusFunctionCodeReadItem83 D5821 CHANNEL
ModbusFunctionCodeReadItem84 D5831 CHANNEL
ModbusFunctionCodeReadItem85 D5841 CHANNEL
ModbusFunctionCodeReadItem86 D5851 CHANNEL
ModbusFunctionCodeReadItem87 D5861 CHANNEL
ModbusFunctionCodeReadItem88 D5871 CHANNEL
ModbusFunctionCodeReadItem89 D5881 CHANNEL
ModbusFunctionCodeReadItem9 D5081 CHANNEL
ModbusFunctionCodeReadItem90 D5891 CHANNEL
ModbusFunctionCodeReadItem91 D5901 CHANNEL
ModbusFunctionCodeReadItem92 D5911 CHANNEL
ModbusFunctionCodeReadItem93 D5921 CHANNEL
ModbusFunctionCodeReadItem94 D5931 CHANNEL
ModbusFunctionCodeReadItem95 D5941 CHANNEL
ModbusFunctionCodeReadItem96 D5951 CHANNEL
ModbusFunctionCodeReadItem97 D5961 CHANNEL
ModbusFunctionCodeReadItem98 D5971 CHANNEL
ModbusFunctionCodeReadItem99 D5981 CHANNEL
ModbusFunctionCodeWriteItem1 D6001 CHANNEL
ModbusFunctionCodeWriteItem10 D6091 CHANNEL
ModbusFunctionCodeWriteItem100 D6991 CHANNEL
ModbusFunctionCodeWriteItem11 D6101 CHANNEL
ModbusFunctionCodeWriteItem12 D6111 CHANNEL
ModbusFunctionCodeWriteItem13 D6121 CHANNEL
ModbusFunctionCodeWriteItem14 D6131 CHANNEL
ModbusFunctionCodeWriteItem15 D6141 CHANNEL
ModbusFunctionCodeWriteItem16 D6151 CHANNEL
ModbusFunctionCodeWriteItem17 D6161 CHANNEL
ModbusFunctionCodeWriteItem18 D6171 CHANNEL
ModbusFunctionCodeWriteItem19 D6181 CHANNEL
ModbusFunctionCodeWriteItem2 D6011 CHANNEL
ModbusFunctionCodeWriteItem20 D6191 CHANNEL
ModbusFunctionCodeWriteItem21 D6201 CHANNEL
ModbusFunctionCodeWriteItem22 D6211 CHANNEL
ModbusFunctionCodeWriteItem23 D6221 CHANNEL
ModbusFunctionCodeWriteItem24 D6231 CHANNEL
ModbusFunctionCodeWriteItem25 D6241 CHANNEL
ModbusFunctionCodeWriteItem26 D6251 CHANNEL
ModbusFunctionCodeWriteItem27 D6261 CHANNEL
ModbusFunctionCodeWriteItem28 D6271 CHANNEL
ModbusFunctionCodeWriteItem29 D6281 CHANNEL
ModbusFunctionCodeWriteItem3 D6021 CHANNEL
ModbusFunctionCodeWriteItem30 D6291 CHANNEL
ModbusFunctionCodeWriteItem31 D6301 CHANNEL
ModbusFunctionCodeWriteItem32 D6311 CHANNEL
ModbusFunctionCodeWriteItem33 D6321 CHANNEL
ModbusFunctionCodeWriteItem34 D6331 CHANNEL
ModbusFunctionCodeWriteItem35 D6341 CHANNEL
ModbusFunctionCodeWriteItem36 D6351 CHANNEL
ModbusFunctionCodeWriteItem37 D6361 CHANNEL
ModbusFunctionCodeWriteItem38 D6371 CHANNEL
ModbusFunctionCodeWriteItem39 D6381 CHANNEL
ModbusFunctionCodeWriteItem4 D6031 CHANNEL
ModbusFunctionCodeWriteItem40 D6391 CHANNEL
ModbusFunctionCodeWriteItem41 D6401 CHANNEL
ModbusFunctionCodeWriteItem42 D6411 CHANNEL
ModbusFunctionCodeWriteItem43 D6421 CHANNEL
ModbusFunctionCodeWriteItem44 D6431 CHANNEL
ModbusFunctionCodeWriteItem45 D6441 CHANNEL
ModbusFunctionCodeWriteItem46 D6451 CHANNEL
ModbusFunctionCodeWriteItem47 D6461 CHANNEL
ModbusFunctionCodeWriteItem48 D6471 CHANNEL
ModbusFunctionCodeWriteItem49 D6481 CHANNEL
ModbusFunctionCodeWriteItem5 D6041 CHANNEL
ModbusFunctionCodeWriteItem50 D6491 CHANNEL
ModbusFunctionCodeWriteItem51 D6501 CHANNEL
ModbusFunctionCodeWriteItem52 D6511 CHANNEL
ModbusFunctionCodeWriteItem53 D6521 CHANNEL
ModbusFunctionCodeWriteItem54 D6531 CHANNEL
ModbusFunctionCodeWriteItem55 D6541 CHANNEL
ModbusFunctionCodeWriteItem56 D6551 CHANNEL
ModbusFunctionCodeWriteItem57 D6561 CHANNEL
ModbusFunctionCodeWriteItem58 D6571 CHANNEL
ModbusFunctionCodeWriteItem59 D6581 CHANNEL
ModbusFunctionCodeWriteItem6 D6051 CHANNEL
ModbusFunctionCodeWriteItem60 D6591 CHANNEL
ModbusFunctionCodeWriteItem61 D6601 CHANNEL
ModbusFunctionCodeWriteItem62 D6611 CHANNEL
ModbusFunctionCodeWriteItem63 D6621 CHANNEL
ModbusFunctionCodeWriteItem64 D6631 CHANNEL
ModbusFunctionCodeWriteItem65 D6641 CHANNEL
ModbusFunctionCodeWriteItem66 D6651 CHANNEL
ModbusFunctionCodeWriteItem67 D6661 CHANNEL
ModbusFunctionCodeWriteItem68 D6671 CHANNEL
ModbusFunctionCodeWriteItem69 D6681 CHANNEL
ModbusFunctionCodeWriteItem7 D6061 CHANNEL
ModbusFunctionCodeWriteItem70 D6691 CHANNEL
ModbusFunctionCodeWriteItem71 D6701 CHANNEL
ModbusFunctionCodeWriteItem72 D6711 CHANNEL
ModbusFunctionCodeWriteItem73 D6721 CHANNEL
ModbusFunctionCodeWriteItem74 D6731 CHANNEL
ModbusFunctionCodeWriteItem75 D6741 CHANNEL
ModbusFunctionCodeWriteItem76 D6751 CHANNEL
ModbusFunctionCodeWriteItem77 D6761 CHANNEL
ModbusFunctionCodeWriteItem78 D6771 CHANNEL
ModbusFunctionCodeWriteItem79 D6781 CHANNEL
ModbusFunctionCodeWriteItem8 D6071 CHANNEL
ModbusFunctionCodeWriteItem80 D6791 CHANNEL
ModbusFunctionCodeWriteItem81 D6801 CHANNEL
ModbusFunctionCodeWriteItem82 D6811 CHANNEL
ModbusFunctionCodeWriteItem83 D6821 CHANNEL
ModbusFunctionCodeWriteItem84 D6831 CHANNEL
ModbusFunctionCodeWriteItem85 D6841 CHANNEL
ModbusFunctionCodeWriteItem86 D6851 CHANNEL
ModbusFunctionCodeWriteItem87 D6861 CHANNEL
ModbusFunctionCodeWriteItem88 D6871 CHANNEL
ModbusFunctionCodeWriteItem89 D6881 CHANNEL
ModbusFunctionCodeWriteItem9 D6081 CHANNEL
ModbusFunctionCodeWriteItem90 D6891 CHANNEL
ModbusFunctionCodeWriteItem91 D6901 CHANNEL
ModbusFunctionCodeWriteItem92 D6911 CHANNEL
ModbusFunctionCodeWriteItem93 D6921 CHANNEL
ModbusFunctionCodeWriteItem94 D6931 CHANNEL
ModbusFunctionCodeWriteItem95 D6941 CHANNEL
ModbusFunctionCodeWriteItem96 D6951 CHANNEL
ModbusFunctionCodeWriteItem97 D6961 CHANNEL
ModbusFunctionCodeWriteItem98 D6971 CHANNEL
ModbusFunctionCodeWriteItem99 D6981 CHANNEL
ModbusNodeNumberReadItem1 D5000 CHANNEL
ModbusNodeNumberReadItem10 D5090 CHANNEL
ModbusNodeNumberReadItem100 D5990 CHANNEL
ModbusNodeNumberReadItem11 D5100 CHANNEL
ModbusNodeNumberReadItem12 D5110 CHANNEL
ModbusNodeNumberReadItem13 D5120 CHANNEL
ModbusNodeNumberReadItem14 D5130 CHANNEL
ModbusNodeNumberReadItem15 D5140 CHANNEL
ModbusNodeNumberReadItem16 D5150 CHANNEL
ModbusNodeNumberReadItem17 D5160 CHANNEL
ModbusNodeNumberReadItem18 D5170 CHANNEL
ModbusNodeNumberReadItem19 D5180 CHANNEL
ModbusNodeNumberReadItem2 D5010 CHANNEL
ModbusNodeNumberReadItem20 D5190 CHANNEL
ModbusNodeNumberReadItem21 D5200 CHANNEL
ModbusNodeNumberReadItem22 D5210 CHANNEL
ModbusNodeNumberReadItem23 D5220 CHANNEL
ModbusNodeNumberReadItem24 D5230 CHANNEL
ModbusNodeNumberReadItem25 D5240 CHANNEL
ModbusNodeNumberReadItem26 D5250 CHANNEL
ModbusNodeNumberReadItem27 D5260 CHANNEL
ModbusNodeNumberReadItem28 D5270 CHANNEL
ModbusNodeNumberReadItem29 D5280 CHANNEL
ModbusNodeNumberReadItem3 D5020 CHANNEL
ModbusNodeNumberReadItem30 D5290 CHANNEL
ModbusNodeNumberReadItem31 D5300 CHANNEL
ModbusNodeNumberReadItem32 D5310 CHANNEL
ModbusNodeNumberReadItem33 D5320 CHANNEL
ModbusNodeNumberReadItem34 D5330 CHANNEL
ModbusNodeNumberReadItem35 D5340 CHANNEL
ModbusNodeNumberReadItem36 D5350 CHANNEL
ModbusNodeNumberReadItem37 D5360 CHANNEL
ModbusNodeNumberReadItem38 D5370 CHANNEL
ModbusNodeNumberReadItem39 D5380 CHANNEL
ModbusNodeNumberReadItem4 D5030 CHANNEL
ModbusNodeNumberReadItem40 D5390 CHANNEL
ModbusNodeNumberReadItem41 D5400 CHANNEL
ModbusNodeNumberReadItem42 D5410 CHANNEL
ModbusNodeNumberReadItem43 D5420 CHANNEL
ModbusNodeNumberReadItem44 D5430 CHANNEL
ModbusNodeNumberReadItem45 D5440 CHANNEL
ModbusNodeNumberReadItem46 D5450 CHANNEL
ModbusNodeNumberReadItem47 D5460 CHANNEL
ModbusNodeNumberReadItem48 D5470 CHANNEL
ModbusNodeNumberReadItem49 D5480 CHANNEL
ModbusNodeNumberReadItem5 D5040 CHANNEL
ModbusNodeNumberReadItem50 D5490 CHANNEL
ModbusNodeNumberReadItem51 D5500 CHANNEL
ModbusNodeNumberReadItem52 D5510 CHANNEL
ModbusNodeNumberReadItem53 D5520 CHANNEL
ModbusNodeNumberReadItem54 D5530 CHANNEL
ModbusNodeNumberReadItem55 D5540 CHANNEL
ModbusNodeNumberReadItem56 D5550 CHANNEL
ModbusNodeNumberReadItem57 D5560 CHANNEL
ModbusNodeNumberReadItem58 D5570 CHANNEL
ModbusNodeNumberReadItem59 D5580 CHANNEL
ModbusNodeNumberReadItem6 D5050 CHANNEL
ModbusNodeNumberReadItem60 D5590 CHANNEL
ModbusNodeNumberReadItem61 D5600 CHANNEL
ModbusNodeNumberReadItem62 D5610 CHANNEL
ModbusNodeNumberReadItem63 D5620 CHANNEL
ModbusNodeNumberReadItem64 D5630 CHANNEL
ModbusNodeNumberReadItem65 D5640 CHANNEL
ModbusNodeNumberReadItem66 D5650 CHANNEL
ModbusNodeNumberReadItem67 D5660 CHANNEL
ModbusNodeNumberReadItem68 D5670 CHANNEL
ModbusNodeNumberReadItem69 D5680 CHANNEL
ModbusNodeNumberReadItem7 D5060 CHANNEL
ModbusNodeNumberReadItem70 D5690 CHANNEL
ModbusNodeNumberReadItem71 D5700 CHANNEL
ModbusNodeNumberReadItem72 D5710 CHANNEL
ModbusNodeNumberReadItem73 D5720 CHANNEL
ModbusNodeNumberReadItem74 D5730 CHANNEL
ModbusNodeNumberReadItem75 D5740 CHANNEL
ModbusNodeNumberReadItem76 D5750 CHANNEL
ModbusNodeNumberReadItem77 D5760 CHANNEL
ModbusNodeNumberReadItem78 D5770 CHANNEL
ModbusNodeNumberReadItem79 D5780 CHANNEL
ModbusNodeNumberReadItem8 D5070 CHANNEL
ModbusNodeNumberReadItem80 D5790 CHANNEL
ModbusNodeNumberReadItem81 D5800 CHANNEL
ModbusNodeNumberReadItem82 D5810 CHANNEL
ModbusNodeNumberReadItem83 D5820 CHANNEL
ModbusNodeNumberReadItem84 D5830 CHANNEL
ModbusNodeNumberReadItem85 D5840 CHANNEL
ModbusNodeNumberReadItem86 D5850 CHANNEL
ModbusNodeNumberReadItem87 D5860 CHANNEL
ModbusNodeNumberReadItem88 D5870 CHANNEL
ModbusNodeNumberReadItem89 D5880 CHANNEL
ModbusNodeNumberReadItem9 D5080 CHANNEL
ModbusNodeNumberReadItem90 D5890 CHANNEL
ModbusNodeNumberReadItem91 D5900 CHANNEL
ModbusNodeNumberReadItem92 D5910 CHANNEL
ModbusNodeNumberReadItem93 D5920 CHANNEL
ModbusNodeNumberReadItem94 D5930 CHANNEL
ModbusNodeNumberReadItem95 D5940 CHANNEL
ModbusNodeNumberReadItem96 D5950 CHANNEL
ModbusNodeNumberReadItem97 D5960 CHANNEL
ModbusNodeNumberReadItem98 D5970 CHANNEL
ModbusNodeNumberReadItem99 D5980 CHANNEL
ModbusNodeNumberWriteItem1 D6000 CHANNEL
ModbusNodeNumberWriteItem10 D6090 CHANNEL
ModbusNodeNumberWriteItem100 D6990 CHANNEL
ModbusNodeNumberWriteItem11 D6100 CHANNEL
ModbusNodeNumberWriteItem12 D6110 CHANNEL
ModbusNodeNumberWriteItem13 D6120 CHANNEL
ModbusNodeNumberWriteItem14 D6130 CHANNEL
ModbusNodeNumberWriteItem15 D6140 CHANNEL
ModbusNodeNumberWriteItem16 D6150 CHANNEL
ModbusNodeNumberWriteItem17 D6160 CHANNEL
ModbusNodeNumberWriteItem18 D6170 CHANNEL
ModbusNodeNumberWriteItem19 D6180 CHANNEL
ModbusNodeNumberWriteItem2 D6010 CHANNEL
ModbusNodeNumberWriteItem20 D6190 CHANNEL
ModbusNodeNumberWriteItem21 D6200 CHANNEL
ModbusNodeNumberWriteItem22 D6210 CHANNEL
ModbusNodeNumberWriteItem23 D6220 CHANNEL
ModbusNodeNumberWriteItem24 D6230 CHANNEL
ModbusNodeNumberWriteItem25 D6240 CHANNEL
ModbusNodeNumberWriteItem26 D6250 CHANNEL
ModbusNodeNumberWriteItem27 D6260 CHANNEL
ModbusNodeNumberWriteItem28 D6270 CHANNEL
ModbusNodeNumberWriteItem29 D6280 CHANNEL
ModbusNodeNumberWriteItem3 D6020 CHANNEL
ModbusNodeNumberWriteItem30 D6290 CHANNEL
ModbusNodeNumberWriteItem31 D6300 CHANNEL
ModbusNodeNumberWriteItem32 D6310 CHANNEL
ModbusNodeNumberWriteItem33 D6320 CHANNEL
ModbusNodeNumberWriteItem34 D6330 CHANNEL
ModbusNodeNumberWriteItem35 D6340 CHANNEL
ModbusNodeNumberWriteItem36 D6350 CHANNEL
ModbusNodeNumberWriteItem37 D6360 CHANNEL
ModbusNodeNumberWriteItem38 D6370 CHANNEL
ModbusNodeNumberWriteItem39 D6380 CHANNEL
ModbusNodeNumberWriteItem4 D6030 CHANNEL
ModbusNodeNumberWriteItem40 D6390 CHANNEL
ModbusNodeNumberWriteItem41 D6400 CHANNEL
ModbusNodeNumberWriteItem42 D6410 CHANNEL
ModbusNodeNumberWriteItem43 D6420 CHANNEL
ModbusNodeNumberWriteItem44 D6430 CHANNEL
ModbusNodeNumberWriteItem45 D6440 CHANNEL
ModbusNodeNumberWriteItem46 D6450 CHANNEL
ModbusNodeNumberWriteItem47 D6460 CHANNEL
ModbusNodeNumberWriteItem48 D6470 CHANNEL
ModbusNodeNumberWriteItem49 D6480 CHANNEL
ModbusNodeNumberWriteItem5 D6040 CHANNEL
ModbusNodeNumberWriteItem50 D6490 CHANNEL
ModbusNodeNumberWriteItem51 D6500 CHANNEL
ModbusNodeNumberWriteItem52 D6510 CHANNEL
ModbusNodeNumberWriteItem53 D6520 CHANNEL
ModbusNodeNumberWriteItem54 D6530 CHANNEL
ModbusNodeNumberWriteItem55 D6540 CHANNEL
ModbusNodeNumberWriteItem56 D6550 CHANNEL
ModbusNodeNumberWriteItem57 D6560 CHANNEL
ModbusNodeNumberWriteItem58 D6570 CHANNEL
ModbusNodeNumberWriteItem59 D6580 CHANNEL
ModbusNodeNumberWriteItem6 D6050 CHANNEL
ModbusNodeNumberWriteItem60 D6590 CHANNEL
ModbusNodeNumberWriteItem61 D6600 CHANNEL
ModbusNodeNumberWriteItem62 D6610 CHANNEL
ModbusNodeNumberWriteItem63 D6620 CHANNEL
ModbusNodeNumberWriteItem64 D6630 CHANNEL
ModbusNodeNumberWriteItem65 D6640 CHANNEL
ModbusNodeNumberWriteItem66 D6650 CHANNEL
ModbusNodeNumberWriteItem67 D6660 CHANNEL
ModbusNodeNumberWriteItem68 D6670 CHANNEL
ModbusNodeNumberWriteItem69 D6680 CHANNEL
ModbusNodeNumberWriteItem7 D6060 CHANNEL
ModbusNodeNumberWriteItem70 D6690 CHANNEL
ModbusNodeNumberWriteItem71 D6700 CHANNEL
ModbusNodeNumberWriteItem72 D6710 CHANNEL
ModbusNodeNumberWriteItem73 D6720 CHANNEL
ModbusNodeNumberWriteItem74 D6730 CHANNEL
ModbusNodeNumberWriteItem75 D6740 CHANNEL
ModbusNodeNumberWriteItem76 D6750 CHANNEL
ModbusNodeNumberWriteItem77 D6760 CHANNEL
ModbusNodeNumberWriteItem78 D6770 CHANNEL
ModbusNodeNumberWriteItem79 D6780 CHANNEL
ModbusNodeNumberWriteItem8 D6070 CHANNEL
ModbusNodeNumberWriteItem80 D6790 CHANNEL
ModbusNodeNumberWriteItem81 D6800 CHANNEL
ModbusNodeNumberWriteItem82 D6810 CHANNEL
ModbusNodeNumberWriteItem83 D6820 CHANNEL
ModbusNodeNumberWriteItem84 D6830 CHANNEL
ModbusNodeNumberWriteItem85 D6840 CHANNEL
ModbusNodeNumberWriteItem86 D6850 CHANNEL
ModbusNodeNumberWriteItem87 D6860 CHANNEL
ModbusNodeNumberWriteItem88 D6870 CHANNEL
ModbusNodeNumberWriteItem89 D6880 CHANNEL
ModbusNodeNumberWriteItem9 D6080 CHANNEL
ModbusNodeNumberWriteItem90 D6890 CHANNEL
ModbusNodeNumberWriteItem91 D6900 CHANNEL
ModbusNodeNumberWriteItem92 D6910 CHANNEL
ModbusNodeNumberWriteItem93 D6920 CHANNEL
ModbusNodeNumberWriteItem94 D6930 CHANNEL
ModbusNodeNumberWriteItem95 D6940 CHANNEL
ModbusNodeNumberWriteItem96 D6950 CHANNEL
ModbusNodeNumberWriteItem97 D6960 CHANNEL
ModbusNodeNumberWriteItem98 D6970 CHANNEL
ModbusNodeNumberWriteItem99 D6980 CHANNEL
NonResettingTimeoutCounter W209 CHANNEL
NotUsed1ReadItem1 D5006 CHANNEL
NotUsed1ReadItem10 D5096 CHANNEL
NotUsed1ReadItem100 D5996 CHANNEL
NotUsed1ReadItem11 D5106 CHANNEL
NotUsed1ReadItem12 D5116 CHANNEL
NotUsed1ReadItem13 D5126 CHANNEL
NotUsed1ReadItem14 D5136 CHANNEL
NotUsed1ReadItem15 D5146 CHANNEL
NotUsed1ReadItem16 D5156 CHANNEL
NotUsed1ReadItem17 D5166 CHANNEL
NotUsed1ReadItem18 D5176 CHANNEL
NotUsed1ReadItem19 D5186 CHANNEL
NotUsed1ReadItem2 D5016 CHANNEL
NotUsed1ReadItem20 D5196 CHANNEL
NotUsed1ReadItem21 D5206 CHANNEL
NotUsed1ReadItem22 D5216 CHANNEL
NotUsed1ReadItem23 D5226 CHANNEL
NotUsed1ReadItem24 D5236 CHANNEL
NotUsed1ReadItem25 D5246 CHANNEL
NotUsed1ReadItem26 D5256 CHANNEL
NotUsed1ReadItem27 D5266 CHANNEL
NotUsed1ReadItem28 D5276 CHANNEL
NotUsed1ReadItem29 D5286 CHANNEL
NotUsed1ReadItem3 D5026 CHANNEL
NotUsed1ReadItem30 D5296 CHANNEL
NotUsed1ReadItem31 D5306 CHANNEL
NotUsed1ReadItem32 D5316 CHANNEL
NotUsed1ReadItem33 D5326 CHANNEL
NotUsed1ReadItem34 D5336 CHANNEL
NotUsed1ReadItem35 D5346 CHANNEL
NotUsed1ReadItem36 D5356 CHANNEL
NotUsed1ReadItem37 D5366 CHANNEL
NotUsed1ReadItem38 D5376 CHANNEL
NotUsed1ReadItem39 D5386 CHANNEL
NotUsed1ReadItem4 D5036 CHANNEL
NotUsed1ReadItem40 D5396 CHANNEL
NotUsed1ReadItem41 D5406 CHANNEL
NotUsed1ReadItem42 D5416 CHANNEL
NotUsed1ReadItem43 D5426 CHANNEL
NotUsed1ReadItem44 D5436 CHANNEL
NotUsed1ReadItem45 D5446 CHANNEL
NotUsed1ReadItem46 D5456 CHANNEL
NotUsed1ReadItem47 D5466 CHANNEL
NotUsed1ReadItem48 D5476 CHANNEL
NotUsed1ReadItem49 D5486 CHANNEL
NotUsed1ReadItem5 D5046 CHANNEL
NotUsed1ReadItem50 D5496 CHANNEL
NotUsed1ReadItem51 D5506 CHANNEL
NotUsed1ReadItem52 D5516 CHANNEL
NotUsed1ReadItem53 D5526 CHANNEL
NotUsed1ReadItem54 D5536 CHANNEL
NotUsed1ReadItem55 D5546 CHANNEL
NotUsed1ReadItem56 D5556 CHANNEL
NotUsed1ReadItem57 D5566 CHANNEL
NotUsed1ReadItem58 D5576 CHANNEL
NotUsed1ReadItem59 D5586 CHANNEL
NotUsed1ReadItem6 D5056 CHANNEL
NotUsed1ReadItem60 D5596 CHANNEL
NotUsed1ReadItem61 D5606 CHANNEL
NotUsed1ReadItem62 D5616 CHANNEL
NotUsed1ReadItem63 D5626 CHANNEL
NotUsed1ReadItem64 D5636 CHANNEL
NotUsed1ReadItem65 D5646 CHANNEL
NotUsed1ReadItem66 D5656 CHANNEL
NotUsed1ReadItem67 D5666 CHANNEL
NotUsed1ReadItem68 D5676 CHANNEL
NotUsed1ReadItem69 D5686 CHANNEL
NotUsed1ReadItem7 D5066 CHANNEL
NotUsed1ReadItem70 D5696 CHANNEL
NotUsed1ReadItem71 D5706 CHANNEL
NotUsed1ReadItem72 D5716 CHANNEL
NotUsed1ReadItem73 D5726 CHANNEL
NotUsed1ReadItem74 D5736 CHANNEL
NotUsed1ReadItem75 D5746 CHANNEL
NotUsed1ReadItem76 D5756 CHANNEL
NotUsed1ReadItem77 D5766 CHANNEL
NotUsed1ReadItem78 D5776 CHANNEL
NotUsed1ReadItem79 D5786 CHANNEL
NotUsed1ReadItem8 D5076 CHANNEL
NotUsed1ReadItem80 D5796 CHANNEL
NotUsed1ReadItem81 D5806 CHANNEL
NotUsed1ReadItem82 D5816 CHANNEL
NotUsed1ReadItem83 D5826 CHANNEL
NotUsed1ReadItem84 D5836 CHANNEL
NotUsed1ReadItem85 D5846 CHANNEL
NotUsed1ReadItem86 D5856 CHANNEL
NotUsed1ReadItem87 D5866 CHANNEL
NotUsed1ReadItem88 D5876 CHANNEL
NotUsed1ReadItem89 D5886 CHANNEL
NotUsed1ReadItem9 D5086 CHANNEL
NotUsed1ReadItem90 D5896 CHANNEL
NotUsed1ReadItem91 D5906 CHANNEL
NotUsed1ReadItem92 D5916 CHANNEL
NotUsed1ReadItem93 D5926 CHANNEL
NotUsed1ReadItem94 D5936 CHANNEL
NotUsed1ReadItem95 D5946 CHANNEL
NotUsed1ReadItem96 D5956 CHANNEL
NotUsed1ReadItem97 D5966 CHANNEL
NotUsed1ReadItem98 D5976 CHANNEL
NotUsed1ReadItem99 D5986 CHANNEL
NotUsed2ReadItem1 D5007 CHANNEL
NotUsed2ReadItem10 D5097 CHANNEL
NotUsed2ReadItem100 D5997 CHANNEL
NotUsed2ReadItem11 D5107 CHANNEL
NotUsed2ReadItem12 D5117 CHANNEL
NotUsed2ReadItem13 D5127 CHANNEL
NotUsed2ReadItem14 D5137 CHANNEL
NotUsed2ReadItem15 D5147 CHANNEL
NotUsed2ReadItem16 D5157 CHANNEL
NotUsed2ReadItem17 D5167 CHANNEL
NotUsed2ReadItem18 D5177 CHANNEL
NotUsed2ReadItem19 D5187 CHANNEL
NotUsed2ReadItem2 D5017 CHANNEL
NotUsed2ReadItem20 D5197 CHANNEL
NotUsed2ReadItem21 D5207 CHANNEL
NotUsed2ReadItem22 D5217 CHANNEL
NotUsed2ReadItem23 D5227 CHANNEL
NotUsed2ReadItem24 D5237 CHANNEL
NotUsed2ReadItem25 D5247 CHANNEL
NotUsed2ReadItem26 D5257 CHANNEL
NotUsed2ReadItem27 D5267 CHANNEL
NotUsed2ReadItem28 D5277 CHANNEL
NotUsed2ReadItem29 D5287 CHANNEL
NotUsed2ReadItem3 D5027 CHANNEL
NotUsed2ReadItem30 D5297 CHANNEL
NotUsed2ReadItem31 D5307 CHANNEL
NotUsed2ReadItem32 D5317 CHANNEL
NotUsed2ReadItem33 D5327 CHANNEL
NotUsed2ReadItem34 D5337 CHANNEL
NotUsed2ReadItem35 D5347 CHANNEL
NotUsed2ReadItem36 D5357 CHANNEL
NotUsed2ReadItem37 D5367 CHANNEL
NotUsed2ReadItem38 D5377 CHANNEL
NotUsed2ReadItem39 D5387 CHANNEL
NotUsed2ReadItem4 D5037 CHANNEL
NotUsed2ReadItem40 D5397 CHANNEL
NotUsed2ReadItem41 D5407 CHANNEL
NotUsed2ReadItem42 D5417 CHANNEL
NotUsed2ReadItem43 D5427 CHANNEL
NotUsed2ReadItem44 D5437 CHANNEL
NotUsed2ReadItem45 D5447 CHANNEL
NotUsed2ReadItem46 D5457 CHANNEL
NotUsed2ReadItem47 D5467 CHANNEL
NotUsed2ReadItem48 D5477 CHANNEL
NotUsed2ReadItem49 D5487 CHANNEL
NotUsed2ReadItem5 D5047 CHANNEL
NotUsed2ReadItem50 D5497 CHANNEL
NotUsed2ReadItem51 D5507 CHANNEL
NotUsed2ReadItem52 D5517 CHANNEL
NotUsed2ReadItem53 D5527 CHANNEL
NotUsed2ReadItem54 D5537 CHANNEL
NotUsed2ReadItem55 D5547 CHANNEL
NotUsed2ReadItem56 D5557 CHANNEL
NotUsed2ReadItem57 D5567 CHANNEL
NotUsed2ReadItem58 D5577 CHANNEL
NotUsed2ReadItem59 D5587 CHANNEL
NotUsed2ReadItem6 D5057 CHANNEL
NotUsed2ReadItem60 D5597 CHANNEL
NotUsed2ReadItem61 D5607 CHANNEL
NotUsed2ReadItem62 D5617 CHANNEL
NotUsed2ReadItem63 D5627 CHANNEL
NotUsed2ReadItem64 D5637 CHANNEL
NotUsed2ReadItem65 D5647 CHANNEL
NotUsed2ReadItem66 D5657 CHANNEL
NotUsed2ReadItem67 D5667 CHANNEL
NotUsed2ReadItem68 D5677 CHANNEL
NotUsed2ReadItem69 D5687 CHANNEL
NotUsed2ReadItem7 D5067 CHANNEL
NotUsed2ReadItem70 D5697 CHANNEL
NotUsed2ReadItem71 D5707 CHANNEL
NotUsed2ReadItem72 D5717 CHANNEL
NotUsed2ReadItem73 D5727 CHANNEL
NotUsed2ReadItem74 D5737 CHANNEL
NotUsed2ReadItem75 D5747 CHANNEL
NotUsed2ReadItem76 D5757 CHANNEL
NotUsed2ReadItem77 D5767 CHANNEL
NotUsed2ReadItem78 D5777 CHANNEL
NotUsed2ReadItem79 D5787 CHANNEL
NotUsed2ReadItem8 D5077 CHANNEL
NotUsed2ReadItem80 D5797 CHANNEL
NotUsed2ReadItem81 D5807 CHANNEL
NotUsed2ReadItem82 D5817 CHANNEL
NotUsed2ReadItem83 D5827 CHANNEL
NotUsed2ReadItem84 D5837 CHANNEL
NotUsed2ReadItem85 D5847 CHANNEL
NotUsed2ReadItem86 D5857 CHANNEL
NotUsed2ReadItem87 D5867 CHANNEL
NotUsed2ReadItem88 D5877 CHANNEL
NotUsed2ReadItem89 D5887 CHANNEL
NotUsed2ReadItem9 D5087 CHANNEL
NotUsed2ReadItem90 D5897 CHANNEL
NotUsed2ReadItem91 D5907 CHANNEL
NotUsed2ReadItem92 D5917 CHANNEL
NotUsed2ReadItem93 D5927 CHANNEL
NotUsed2ReadItem94 D5937 CHANNEL
NotUsed2ReadItem95 D5947 CHANNEL
NotUsed2ReadItem96 D5957 CHANNEL
NotUsed2ReadItem97 D5967 CHANNEL
NotUsed2ReadItem98 D5977 CHANNEL
NotUsed2ReadItem99 D5987 CHANNEL
NumberOfItemsToReadReadItem1 D5003 CHANNEL
NumberOfItemsToReadReadItem10 D5093 CHANNEL
NumberOfItemsToReadReadItem100 D5993 CHANNEL
NumberOfItemsToReadReadItem11 D5103 CHANNEL
NumberOfItemsToReadReadItem12 D5113 CHANNEL
NumberOfItemsToReadReadItem13 D5123 CHANNEL
NumberOfItemsToReadReadItem14 D5133 CHANNEL
NumberOfItemsToReadReadItem15 D5143 CHANNEL
NumberOfItemsToReadReadItem16 D5153 CHANNEL
NumberOfItemsToReadReadItem17 D5163 CHANNEL
NumberOfItemsToReadReadItem18 D5173 CHANNEL
NumberOfItemsToReadReadItem19 D5183 CHANNEL
NumberOfItemsToReadReadItem2 D5013 CHANNEL
NumberOfItemsToReadReadItem20 D5193 CHANNEL
NumberOfItemsToReadReadItem21 D5203 CHANNEL
NumberOfItemsToReadReadItem22 D5213 CHANNEL
NumberOfItemsToReadReadItem23 D5223 CHANNEL
NumberOfItemsToReadReadItem24 D5233 CHANNEL
NumberOfItemsToReadReadItem25 D5243 CHANNEL
NumberOfItemsToReadReadItem26 D5253 CHANNEL
NumberOfItemsToReadReadItem27 D5263 CHANNEL
NumberOfItemsToReadReadItem28 D5273 CHANNEL
NumberOfItemsToReadReadItem29 D5283 CHANNEL
NumberOfItemsToReadReadItem3 D5023 CHANNEL
NumberOfItemsToReadReadItem30 D5293 CHANNEL
NumberOfItemsToReadReadItem31 D5303 CHANNEL
NumberOfItemsToReadReadItem32 D5313 CHANNEL
NumberOfItemsToReadReadItem33 D5323 CHANNEL
NumberOfItemsToReadReadItem34 D5333 CHANNEL
NumberOfItemsToReadReadItem35 D5343 CHANNEL
NumberOfItemsToReadReadItem36 D5353 CHANNEL
NumberOfItemsToReadReadItem37 D5363 CHANNEL
NumberOfItemsToReadReadItem38 D5373 CHANNEL
NumberOfItemsToReadReadItem39 D5383 CHANNEL
NumberOfItemsToReadReadItem4 D5033 CHANNEL
NumberOfItemsToReadReadItem40 D5393 CHANNEL
NumberOfItemsToReadReadItem41 D5403 CHANNEL
NumberOfItemsToReadReadItem42 D5413 CHANNEL
NumberOfItemsToReadReadItem43 D5423 CHANNEL
NumberOfItemsToReadReadItem44 D5433 CHANNEL
NumberOfItemsToReadReadItem45 D5443 CHANNEL
NumberOfItemsToReadReadItem46 D5453 CHANNEL
NumberOfItemsToReadReadItem47 D5463 CHANNEL
NumberOfItemsToReadReadItem48 D5473 CHANNEL
NumberOfItemsToReadReadItem49 D5483 CHANNEL
NumberOfItemsToReadReadItem5 D5043 CHANNEL
NumberOfItemsToReadReadItem50 D5493 CHANNEL
NumberOfItemsToReadReadItem51 D5503 CHANNEL
NumberOfItemsToReadReadItem52 D5513 CHANNEL
NumberOfItemsToReadReadItem53 D5523 CHANNEL
NumberOfItemsToReadReadItem54 D5533 CHANNEL
NumberOfItemsToReadReadItem55 D5543 CHANNEL
NumberOfItemsToReadReadItem56 D5553 CHANNEL
NumberOfItemsToReadReadItem57 D5563 CHANNEL
NumberOfItemsToReadReadItem58 D5573 CHANNEL
NumberOfItemsToReadReadItem59 D5583 CHANNEL
NumberOfItemsToReadReadItem6 D5053 CHANNEL
NumberOfItemsToReadReadItem60 D5593 CHANNEL
NumberOfItemsToReadReadItem61 D5603 CHANNEL
NumberOfItemsToReadReadItem62 D5613 CHANNEL
NumberOfItemsToReadReadItem63 D5623 CHANNEL
NumberOfItemsToReadReadItem64 D5633 CHANNEL
NumberOfItemsToReadReadItem65 D5643 CHANNEL
NumberOfItemsToReadReadItem66 D5653 CHANNEL
NumberOfItemsToReadReadItem67 D5663 CHANNEL
NumberOfItemsToReadReadItem68 D5673 CHANNEL
NumberOfItemsToReadReadItem69 D5683 CHANNEL
NumberOfItemsToReadReadItem7 D5063 CHANNEL
NumberOfItemsToReadReadItem70 D5693 CHANNEL
NumberOfItemsToReadReadItem71 D5703 CHANNEL
NumberOfItemsToReadReadItem72 D5713 CHANNEL
NumberOfItemsToReadReadItem73 D5723 CHANNEL
NumberOfItemsToReadReadItem74 D5733 CHANNEL
NumberOfItemsToReadReadItem75 D5743 CHANNEL
NumberOfItemsToReadReadItem76 D5753 CHANNEL
NumberOfItemsToReadReadItem77 D5763 CHANNEL
NumberOfItemsToReadReadItem78 D5773 CHANNEL
NumberOfItemsToReadReadItem79 D5783 CHANNEL
NumberOfItemsToReadReadItem8 D5073 CHANNEL
NumberOfItemsToReadReadItem80 D5793 CHANNEL
NumberOfItemsToReadReadItem81 D5803 CHANNEL
NumberOfItemsToReadReadItem82 D5813 CHANNEL
NumberOfItemsToReadReadItem83 D5823 CHANNEL
NumberOfItemsToReadReadItem84 D5833 CHANNEL
NumberOfItemsToReadReadItem85 D5843 CHANNEL
NumberOfItemsToReadReadItem86 D5853 CHANNEL
NumberOfItemsToReadReadItem87 D5863 CHANNEL
NumberOfItemsToReadReadItem88 D5873 CHANNEL
NumberOfItemsToReadReadItem89 D5883 CHANNEL
NumberOfItemsToReadReadItem9 D5083 CHANNEL
NumberOfItemsToReadReadItem90 D5893 CHANNEL
NumberOfItemsToReadReadItem91 D5903 CHANNEL
NumberOfItemsToReadReadItem92 D5913 CHANNEL
NumberOfItemsToReadReadItem93 D5923 CHANNEL
NumberOfItemsToReadReadItem94 D5933 CHANNEL
NumberOfItemsToReadReadItem95 D5943 CHANNEL
NumberOfItemsToReadReadItem96 D5953 CHANNEL
NumberOfItemsToReadReadItem97 D5963 CHANNEL
NumberOfItemsToReadReadItem98 D5973 CHANNEL
NumberOfItemsToReadReadItem99 D5983 CHANNEL
NumberOfItemsToWriteWriteItem1 D6003 CHANNEL
NumberOfItemsToWriteWriteItem10 D6093 CHANNEL
NumberOfItemsToWriteWriteItem100 D6993 CHANNEL
NumberOfItemsToWriteWriteItem11 D6103 CHANNEL
NumberOfItemsToWriteWriteItem12 D6113 CHANNEL
NumberOfItemsToWriteWriteItem13 D6123 CHANNEL
NumberOfItemsToWriteWriteItem14 D6133 CHANNEL
NumberOfItemsToWriteWriteItem15 D6143 CHANNEL
NumberOfItemsToWriteWriteItem16 D6153 CHANNEL
NumberOfItemsToWriteWriteItem17 D6163 CHANNEL
NumberOfItemsToWriteWriteItem18 D6173 CHANNEL
NumberOfItemsToWriteWriteItem19 D6183 CHANNEL
NumberOfItemsToWriteWriteItem2 D6013 CHANNEL
NumberOfItemsToWriteWriteItem20 D6193 CHANNEL
NumberOfItemsToWriteWriteItem21 D6203 CHANNEL
NumberOfItemsToWriteWriteItem22 D6213 CHANNEL
NumberOfItemsToWriteWriteItem23 D6223 CHANNEL
NumberOfItemsToWriteWriteItem24 D6233 CHANNEL
NumberOfItemsToWriteWriteItem25 D6243 CHANNEL
NumberOfItemsToWriteWriteItem26 D6253 CHANNEL
NumberOfItemsToWriteWriteItem27 D6263 CHANNEL
NumberOfItemsToWriteWriteItem28 D6273 CHANNEL
NumberOfItemsToWriteWriteItem29 D6283 CHANNEL
NumberOfItemsToWriteWriteItem3 D6023 CHANNEL
NumberOfItemsToWriteWriteItem30 D6293 CHANNEL
NumberOfItemsToWriteWriteItem31 D6303 CHANNEL
NumberOfItemsToWriteWriteItem32 D6313 CHANNEL
NumberOfItemsToWriteWriteItem33 D6323 CHANNEL
NumberOfItemsToWriteWriteItem34 D6333 CHANNEL
NumberOfItemsToWriteWriteItem35 D6343 CHANNEL
NumberOfItemsToWriteWriteItem36 D6353 CHANNEL
NumberOfItemsToWriteWriteItem37 D6363 CHANNEL
NumberOfItemsToWriteWriteItem38 D6373 CHANNEL
NumberOfItemsToWriteWriteItem39 D6383 CHANNEL
NumberOfItemsToWriteWriteItem4 D6033 CHANNEL
NumberOfItemsToWriteWriteItem40 D6393 CHANNEL
NumberOfItemsToWriteWriteItem41 D6403 CHANNEL
NumberOfItemsToWriteWriteItem42 D6413 CHANNEL
NumberOfItemsToWriteWriteItem43 D6423 CHANNEL
NumberOfItemsToWriteWriteItem44 D6433 CHANNEL
NumberOfItemsToWriteWriteItem45 D6443 CHANNEL
NumberOfItemsToWriteWriteItem46 D6453 CHANNEL
NumberOfItemsToWriteWriteItem47 D6463 CHANNEL
NumberOfItemsToWriteWriteItem48 D6473 CHANNEL
NumberOfItemsToWriteWriteItem49 D6483 CHANNEL
NumberOfItemsToWriteWriteItem5 D6043 CHANNEL
NumberOfItemsToWriteWriteItem50 D6493 CHANNEL
NumberOfItemsToWriteWriteItem51 D6503 CHANNEL
NumberOfItemsToWriteWriteItem52 D6513 CHANNEL
NumberOfItemsToWriteWriteItem53 D6523 CHANNEL
NumberOfItemsToWriteWriteItem54 D6533 CHANNEL
NumberOfItemsToWriteWriteItem55 D6543 CHANNEL
NumberOfItemsToWriteWriteItem56 D6553 CHANNEL
NumberOfItemsToWriteWriteItem57 D6563 CHANNEL
NumberOfItemsToWriteWriteItem58 D6573 CHANNEL
NumberOfItemsToWriteWriteItem59 D6583 CHANNEL
NumberOfItemsToWriteWriteItem6 D6053 CHANNEL
NumberOfItemsToWriteWriteItem60 D6593 CHANNEL
NumberOfItemsToWriteWriteItem61 D6603 CHANNEL
NumberOfItemsToWriteWriteItem62 D6613 CHANNEL
NumberOfItemsToWriteWriteItem63 D6623 CHANNEL
NumberOfItemsToWriteWriteItem64 D6633 CHANNEL
NumberOfItemsToWriteWriteItem65 D6643 CHANNEL
NumberOfItemsToWriteWriteItem66 D6653 CHANNEL
NumberOfItemsToWriteWriteItem67 D6663 CHANNEL
NumberOfItemsToWriteWriteItem68 D6673 CHANNEL
NumberOfItemsToWriteWriteItem69 D6683 CHANNEL
NumberOfItemsToWriteWriteItem7 D6063 CHANNEL
NumberOfItemsToWriteWriteItem70 D6693 CHANNEL
NumberOfItemsToWriteWriteItem71 D6703 CHANNEL
NumberOfItemsToWriteWriteItem72 D6713 CHANNEL
NumberOfItemsToWriteWriteItem73 D6723 CHANNEL
NumberOfItemsToWriteWriteItem74 D6733 CHANNEL
NumberOfItemsToWriteWriteItem75 D6743 CHANNEL
NumberOfItemsToWriteWriteItem76 D6753 CHANNEL
NumberOfItemsToWriteWriteItem77 D6763 CHANNEL
NumberOfItemsToWriteWriteItem78 D6773 CHANNEL
NumberOfItemsToWriteWriteItem79 D6783 CHANNEL
NumberOfItemsToWriteWriteItem8 D6073 CHANNEL
NumberOfItemsToWriteWriteItem80 D6793 CHANNEL
NumberOfItemsToWriteWriteItem81 D6803 CHANNEL
NumberOfItemsToWriteWriteItem82 D6813 CHANNEL
NumberOfItemsToWriteWriteItem83 D6823 CHANNEL
NumberOfItemsToWriteWriteItem84 D6833 CHANNEL
NumberOfItemsToWriteWriteItem85 D6843 CHANNEL
NumberOfItemsToWriteWriteItem86 D6853 CHANNEL
NumberOfItemsToWriteWriteItem87 D6863 CHANNEL
NumberOfItemsToWriteWriteItem88 D6873 CHANNEL
NumberOfItemsToWriteWriteItem89 D6883 CHANNEL
NumberOfItemsToWriteWriteItem9 D6083 CHANNEL
NumberOfItemsToWriteWriteItem90 D6893 CHANNEL
NumberOfItemsToWriteWriteItem91 D6903 CHANNEL
NumberOfItemsToWriteWriteItem92 D6913 CHANNEL
NumberOfItemsToWriteWriteItem93 D6923 CHANNEL
NumberOfItemsToWriteWriteItem94 D6933 CHANNEL
NumberOfItemsToWriteWriteItem95 D6943 CHANNEL
NumberOfItemsToWriteWriteItem96 D6953 CHANNEL
NumberOfItemsToWriteWriteItem97 D6963 CHANNEL
NumberOfItemsToWriteWriteItem98 D6973 CHANNEL
NumberOfItemsToWriteWriteItem99 D6983 CHANNEL
PMCR_Busy 1884.15 BOOL
PMCR_Complete_NG 1884.10 BOOL
PMCR_Complete_OK 1884.11 BOOL
Polling_Has_Occurred W215.02 BOOL
Port_1_Error A392.04 BOOL
Port_Needs_To_Be_Reset W205.02 BOOL  ; Waiting for Easy Modbus to finish current command
Port_Now_Resetting W205.03 BOOL
ReadValidOrInvalidReadItem1 D5008 CHANNEL
ReadValidOrInvalidReadItem10 D5098 CHANNEL
ReadValidOrInvalidReadItem100 D5998 CHANNEL
ReadValidOrInvalidReadItem11 D5108 CHANNEL
ReadValidOrInvalidReadItem12 D5118 CHANNEL
ReadValidOrInvalidReadItem13 D5128 CHANNEL
ReadValidOrInvalidReadItem14 D5138 CHANNEL
ReadValidOrInvalidReadItem15 D5148 CHANNEL
ReadValidOrInvalidReadItem16 D5158 CHANNEL
ReadValidOrInvalidReadItem17 D5168 CHANNEL
ReadValidOrInvalidReadItem18 D5178 CHANNEL
ReadValidOrInvalidReadItem19 D5188 CHANNEL
ReadValidOrInvalidReadItem2 D5018 CHANNEL
ReadValidOrInvalidReadItem20 D5198 CHANNEL
ReadValidOrInvalidReadItem21 D5208 CHANNEL
ReadValidOrInvalidReadItem22 D5218 CHANNEL
ReadValidOrInvalidReadItem23 D5228 CHANNEL
ReadValidOrInvalidReadItem24 D5238 CHANNEL
ReadValidOrInvalidReadItem25 D5248 CHANNEL
ReadValidOrInvalidReadItem26 D5258 CHANNEL
ReadValidOrInvalidReadItem27 D5268 CHANNEL
ReadValidOrInvalidReadItem28 D5278 CHANNEL
ReadValidOrInvalidReadItem29 D5288 CHANNEL
ReadValidOrInvalidReadItem3 D5028 CHANNEL
ReadValidOrInvalidReadItem30 D5298 CHANNEL
ReadValidOrInvalidReadItem31 D5308 CHANNEL
ReadValidOrInvalidReadItem32 D5318 CHANNEL
ReadValidOrInvalidReadItem33 D5328 CHANNEL
ReadValidOrInvalidReadItem34 D5338 CHANNEL
ReadValidOrInvalidReadItem35 D5348 CHANNEL
ReadValidOrInvalidReadItem36 D5358 CHANNEL
ReadValidOrInvalidReadItem37 D5368 CHANNEL
ReadValidOrInvalidReadItem38 D5378 CHANNEL
ReadValidOrInvalidReadItem39 D5388 CHANNEL
ReadValidOrInvalidReadItem4 D5038 CHANNEL
ReadValidOrInvalidReadItem40 D5398 CHANNEL
ReadValidOrInvalidReadItem41 D5408 CHANNEL
ReadValidOrInvalidReadItem42 D5418 CHANNEL
ReadValidOrInvalidReadItem43 D5428 CHANNEL
ReadValidOrInvalidReadItem44 D5438 CHANNEL
ReadValidOrInvalidReadItem45 D5448 CHANNEL
ReadValidOrInvalidReadItem46 D5458 CHANNEL
ReadValidOrInvalidReadItem47 D5468 CHANNEL
ReadValidOrInvalidReadItem48 D5478 CHANNEL
ReadValidOrInvalidReadItem49 D5488 CHANNEL
ReadValidOrInvalidReadItem5 D5048 CHANNEL
ReadValidOrInvalidReadItem50 D5498 CHANNEL
ReadValidOrInvalidReadItem51 D5508 CHANNEL
ReadValidOrInvalidReadItem52 D5518 CHANNEL
ReadValidOrInvalidReadItem53 D5528 CHANNEL
ReadValidOrInvalidReadItem54 D5538 CHANNEL
ReadValidOrInvalidReadItem55 D5548 CHANNEL
ReadValidOrInvalidReadItem56 D5558 CHANNEL
ReadValidOrInvalidReadItem57 D5568 CHANNEL
ReadValidOrInvalidReadItem58 D5578 CHANNEL
ReadValidOrInvalidReadItem59 D5588 CHANNEL
ReadValidOrInvalidReadItem6 D5058 CHANNEL
ReadValidOrInvalidReadItem60 D5598 CHANNEL
ReadValidOrInvalidReadItem61 D5608 CHANNEL
ReadValidOrInvalidReadItem62 D5618 CHANNEL
ReadValidOrInvalidReadItem63 D5628 CHANNEL
ReadValidOrInvalidReadItem64 D5638 CHANNEL
ReadValidOrInvalidReadItem65 D5648 CHANNEL
ReadValidOrInvalidReadItem66 D5658 CHANNEL
ReadValidOrInvalidReadItem67 D5668 CHANNEL
ReadValidOrInvalidReadItem68 D5678 CHANNEL
ReadValidOrInvalidReadItem69 D5688 CHANNEL
ReadValidOrInvalidReadItem7 D5068 CHANNEL
ReadValidOrInvalidReadItem70 D5698 CHANNEL
ReadValidOrInvalidReadItem71 D5708 CHANNEL
ReadValidOrInvalidReadItem72 D5718 CHANNEL
ReadValidOrInvalidReadItem73 D5728 CHANNEL
ReadValidOrInvalidReadItem74 D5738 CHANNEL
ReadValidOrInvalidReadItem75 D5748 CHANNEL
ReadValidOrInvalidReadItem76 D5758 CHANNEL
ReadValidOrInvalidReadItem77 D5768 CHANNEL
ReadValidOrInvalidReadItem78 D5778 CHANNEL
ReadValidOrInvalidReadItem79 D5788 CHANNEL
ReadValidOrInvalidReadItem8 D5078 CHANNEL
ReadValidOrInvalidReadItem80 D5798 CHANNEL
ReadValidOrInvalidReadItem81 D5808 CHANNEL
ReadValidOrInvalidReadItem82 D5818 CHANNEL
ReadValidOrInvalidReadItem83 D5828 CHANNEL
ReadValidOrInvalidReadItem84 D5838 CHANNEL
ReadValidOrInvalidReadItem85 D5848 CHANNEL
ReadValidOrInvalidReadItem86 D5858 CHANNEL
ReadValidOrInvalidReadItem87 D5868 CHANNEL
ReadValidOrInvalidReadItem88 D5878 CHANNEL
ReadValidOrInvalidReadItem89 D5888 CHANNEL
ReadValidOrInvalidReadItem9 D5088 CHANNEL
ReadValidOrInvalidReadItem90 D5898 CHANNEL
ReadValidOrInvalidReadItem91 D5908 CHANNEL
ReadValidOrInvalidReadItem92 D5918 CHANNEL
ReadValidOrInvalidReadItem93 D5928 CHANNEL
ReadValidOrInvalidReadItem94 D5938 CHANNEL
ReadValidOrInvalidReadItem95 D5948 CHANNEL
ReadValidOrInvalidReadItem96 D5958 CHANNEL
ReadValidOrInvalidReadItem97 D5968 CHANNEL
ReadValidOrInvalidReadItem98 D5978 CHANNEL
ReadValidOrInvalidReadItem99 D5988 CHANNEL
Retry_Send_Delay W205.01 BOOL
SecondWordResponseDataReadItem1 D5005 CHANNEL
SecondWordResponseDataReadItem10 D5095 CHANNEL
SecondWordResponseDataReadItem100 D5995 CHANNEL
SecondWordResponseDataReadItem11 D5105 CHANNEL
SecondWordResponseDataReadItem12 D5115 CHANNEL
SecondWordResponseDataReadItem13 D5125 CHANNEL
SecondWordResponseDataReadItem14 D5135 CHANNEL
SecondWordResponseDataReadItem15 D5145 CHANNEL
SecondWordResponseDataReadItem16 D5155 CHANNEL
SecondWordResponseDataReadItem17 D5165 CHANNEL
SecondWordResponseDataReadItem18 D5175 CHANNEL
SecondWordResponseDataReadItem19 D5185 CHANNEL
SecondWordResponseDataReadItem2 D5015 CHANNEL
SecondWordResponseDataReadItem20 D5195 CHANNEL
SecondWordResponseDataReadItem21 D5205 CHANNEL
SecondWordResponseDataReadItem22 D5215 CHANNEL
SecondWordResponseDataReadItem23 D5225 CHANNEL
SecondWordResponseDataReadItem24 D5235 CHANNEL
SecondWordResponseDataReadItem25 D5245 CHANNEL
SecondWordResponseDataReadItem26 D5255 CHANNEL
SecondWordResponseDataReadItem27 D5265 CHANNEL
SecondWordResponseDataReadItem28 D5275 CHANNEL
SecondWordResponseDataReadItem29 D5285 CHANNEL
SecondWordResponseDataReadItem3 D5025 CHANNEL
SecondWordResponseDataReadItem30 D5295 CHANNEL
SecondWordResponseDataReadItem31 D5305 CHANNEL
SecondWordResponseDataReadItem32 D5315 CHANNEL
SecondWordResponseDataReadItem33 D5325 CHANNEL
SecondWordResponseDataReadItem34 D5335 CHANNEL
SecondWordResponseDataReadItem35 D5345 CHANNEL
SecondWordResponseDataReadItem36 D5355 CHANNEL
SecondWordResponseDataReadItem37 D5365 CHANNEL
SecondWordResponseDataReadItem38 D5375 CHANNEL
SecondWordResponseDataReadItem39 D5385 CHANNEL
SecondWordResponseDataReadItem4 D5035 CHANNEL
SecondWordResponseDataReadItem40 D5395 CHANNEL
SecondWordResponseDataReadItem41 D5405 CHANNEL
SecondWordResponseDataReadItem42 D5415 CHANNEL
SecondWordResponseDataReadItem43 D5425 CHANNEL
SecondWordResponseDataReadItem44 D5435 CHANNEL
SecondWordResponseDataReadItem45 D5445 CHANNEL
SecondWordResponseDataReadItem46 D5455 CHANNEL
SecondWordResponseDataReadItem47 D5465 CHANNEL
SecondWordResponseDataReadItem48 D5475 CHANNEL
SecondWordResponseDataReadItem49 D5485 CHANNEL
SecondWordResponseDataReadItem5 D5045 CHANNEL
SecondWordResponseDataReadItem50 D5495 CHANNEL
SecondWordResponseDataReadItem51 D5505 CHANNEL
SecondWordResponseDataReadItem52 D5515 CHANNEL
SecondWordResponseDataReadItem53 D5525 CHANNEL
SecondWordResponseDataReadItem54 D5535 CHANNEL
SecondWordResponseDataReadItem55 D5545 CHANNEL
SecondWordResponseDataReadItem56 D5555 CHANNEL
SecondWordResponseDataReadItem57 D5565 CHANNEL
SecondWordResponseDataReadItem58 D5575 CHANNEL
SecondWordResponseDataReadItem59 D5585 CHANNEL
SecondWordResponseDataReadItem6 D5055 CHANNEL
SecondWordResponseDataReadItem60 D5595 CHANNEL
SecondWordResponseDataReadItem61 D5605 CHANNEL
SecondWordResponseDataReadItem62 D5615 CHANNEL
SecondWordResponseDataReadItem63 D5625 CHANNEL
SecondWordResponseDataReadItem64 D5635 CHANNEL
SecondWordResponseDataReadItem65 D5645 CHANNEL
SecondWordResponseDataReadItem66 D5655 CHANNEL
SecondWordResponseDataReadItem67 D5665 CHANNEL
SecondWordResponseDataReadItem68 D5675 CHANNEL
SecondWordResponseDataReadItem69 D5685 CHANNEL
SecondWordResponseDataReadItem7 D5065 CHANNEL
SecondWordResponseDataReadItem70 D5695 CHANNEL
SecondWordResponseDataReadItem71 D5705 CHANNEL
SecondWordResponseDataReadItem72 D5715 CHANNEL
SecondWordResponseDataReadItem73 D5725 CHANNEL
SecondWordResponseDataReadItem74 D5735 CHANNEL
SecondWordResponseDataReadItem75 D5745 CHANNEL
SecondWordResponseDataReadItem76 D5755 CHANNEL
SecondWordResponseDataReadItem77 D5765 CHANNEL
SecondWordResponseDataReadItem78 D5775 CHANNEL
SecondWordResponseDataReadItem79 D5785 CHANNEL
SecondWordResponseDataReadItem8 D5075 CHANNEL
SecondWordResponseDataReadItem80 D5795 CHANNEL
SecondWordResponseDataReadItem81 D5805 CHANNEL
SecondWordResponseDataReadItem82 D5815 CHANNEL
SecondWordResponseDataReadItem83 D5825 CHANNEL
SecondWordResponseDataReadItem84 D5835 CHANNEL
SecondWordResponseDataReadItem85 D5845 CHANNEL
SecondWordResponseDataReadItem86 D5855 CHANNEL
SecondWordResponseDataReadItem87 D5865 CHANNEL
SecondWordResponseDataReadItem88 D5875 CHANNEL
SecondWordResponseDataReadItem89 D5885 CHANNEL
SecondWordResponseDataReadItem9 D5085 CHANNEL
SecondWordResponseDataReadItem90 D5895 CHANNEL
SecondWordResponseDataReadItem91 D5905 CHANNEL
SecondWordResponseDataReadItem92 D5915 CHANNEL
SecondWordResponseDataReadItem93 D5925 CHANNEL
SecondWordResponseDataReadItem94 D5935 CHANNEL
SecondWordResponseDataReadItem95 D5945 CHANNEL
SecondWordResponseDataReadItem96 D5955 CHANNEL
SecondWordResponseDataReadItem97 D5965 CHANNEL
SecondWordResponseDataReadItem98 D5975 CHANNEL
SecondWordResponseDataReadItem99 D5985 CHANNEL
SecondWordWriteDataMirrorWriteItem1 D6007 CHANNEL
SecondWordWriteDataMirrorWriteItem10 D6097 CHANNEL
SecondWordWriteDataMirrorWriteItem100 D6997 CHANNEL
SecondWordWriteDataMirrorWriteItem11 D6107 CHANNEL
SecondWordWriteDataMirrorWriteItem12 D6117 CHANNEL
SecondWordWriteDataMirrorWriteItem13 D6127 CHANNEL
SecondWordWriteDataMirrorWriteItem14 D6137 CHANNEL
SecondWordWriteDataMirrorWriteItem15 D6147 CHANNEL
SecondWordWriteDataMirrorWriteItem16 D6157 CHANNEL
SecondWordWriteDataMirrorWriteItem17 D6167 CHANNEL
SecondWordWriteDataMirrorWriteItem18 D6177 CHANNEL
SecondWordWriteDataMirrorWriteItem19 D6187 CHANNEL
SecondWordWriteDataMirrorWriteItem2 D6017 CHANNEL
SecondWordWriteDataMirrorWriteItem20 D6197 CHANNEL
SecondWordWriteDataMirrorWriteItem21 D6207 CHANNEL
SecondWordWriteDataMirrorWriteItem22 D6217 CHANNEL
SecondWordWriteDataMirrorWriteItem23 D6227 CHANNEL
SecondWordWriteDataMirrorWriteItem24 D6237 CHANNEL
SecondWordWriteDataMirrorWriteItem25 D6247 CHANNEL
SecondWordWriteDataMirrorWriteItem26 D6257 CHANNEL
SecondWordWriteDataMirrorWriteItem27 D6267 CHANNEL
SecondWordWriteDataMirrorWriteItem28 D6277 CHANNEL
SecondWordWriteDataMirrorWriteItem29 D6287 CHANNEL
SecondWordWriteDataMirrorWriteItem3 D6027 CHANNEL
SecondWordWriteDataMirrorWriteItem30 D6297 CHANNEL
SecondWordWriteDataMirrorWriteItem31 D6307 CHANNEL
SecondWordWriteDataMirrorWriteItem32 D6317 CHANNEL
SecondWordWriteDataMirrorWriteItem33 D6327 CHANNEL
SecondWordWriteDataMirrorWriteItem34 D6337 CHANNEL
SecondWordWriteDataMirrorWriteItem35 D6347 CHANNEL
SecondWordWriteDataMirrorWriteItem36 D6357 CHANNEL
SecondWordWriteDataMirrorWriteItem37 D6367 CHANNEL
SecondWordWriteDataMirrorWriteItem38 D6377 CHANNEL
SecondWordWriteDataMirrorWriteItem39 D6387 CHANNEL
SecondWordWriteDataMirrorWriteItem4 D6037 CHANNEL
SecondWordWriteDataMirrorWriteItem40 D6397 CHANNEL
SecondWordWriteDataMirrorWriteItem41 D6407 CHANNEL
SecondWordWriteDataMirrorWriteItem42 D6417 CHANNEL
SecondWordWriteDataMirrorWriteItem43 D6427 CHANNEL
SecondWordWriteDataMirrorWriteItem44 D6437 CHANNEL
SecondWordWriteDataMirrorWriteItem45 D6447 CHANNEL
SecondWordWriteDataMirrorWriteItem46 D6457 CHANNEL
SecondWordWriteDataMirrorWriteItem47 D6467 CHANNEL
SecondWordWriteDataMirrorWriteItem48 D6477 CHANNEL
SecondWordWriteDataMirrorWriteItem49 D6487 CHANNEL
SecondWordWriteDataMirrorWriteItem5 D6047 CHANNEL
SecondWordWriteDataMirrorWriteItem50 D6497 CHANNEL
SecondWordWriteDataMirrorWriteItem51 D6507 CHANNEL
SecondWordWriteDataMirrorWriteItem52 D6517 CHANNEL
SecondWordWriteDataMirrorWriteItem53 D6527 CHANNEL
SecondWordWriteDataMirrorWriteItem54 D6537 CHANNEL
SecondWordWriteDataMirrorWriteItem55 D6547 CHANNEL
SecondWordWriteDataMirrorWriteItem56 D6557 CHANNEL
SecondWordWriteDataMirrorWriteItem57 D6567 CHANNEL
SecondWordWriteDataMirrorWriteItem58 D6577 CHANNEL
SecondWordWriteDataMirrorWriteItem59 D6587 CHANNEL
SecondWordWriteDataMirrorWriteItem6 D6057 CHANNEL
SecondWordWriteDataMirrorWriteItem60 D6597 CHANNEL
SecondWordWriteDataMirrorWriteItem61 D6607 CHANNEL
SecondWordWriteDataMirrorWriteItem62 D6617 CHANNEL
SecondWordWriteDataMirrorWriteItem63 D6627 CHANNEL
SecondWordWriteDataMirrorWriteItem64 D6637 CHANNEL
SecondWordWriteDataMirrorWriteItem65 D6647 CHANNEL
SecondWordWriteDataMirrorWriteItem66 D6657 CHANNEL
SecondWordWriteDataMirrorWriteItem67 D6667 CHANNEL
SecondWordWriteDataMirrorWriteItem68 D6677 CHANNEL
SecondWordWriteDataMirrorWriteItem69 D6687 CHANNEL
SecondWordWriteDataMirrorWriteItem7 D6067 CHANNEL
SecondWordWriteDataMirrorWriteItem70 D6697 CHANNEL
SecondWordWriteDataMirrorWriteItem71 D6707 CHANNEL
SecondWordWriteDataMirrorWriteItem72 D6717 CHANNEL
SecondWordWriteDataMirrorWriteItem73 D6727 CHANNEL
SecondWordWriteDataMirrorWriteItem74 D6737 CHANNEL
SecondWordWriteDataMirrorWriteItem75 D6747 CHANNEL
SecondWordWriteDataMirrorWriteItem76 D6757 CHANNEL
SecondWordWriteDataMirrorWriteItem77 D6767 CHANNEL
SecondWordWriteDataMirrorWriteItem78 D6777 CHANNEL
SecondWordWriteDataMirrorWriteItem79 D6787 CHANNEL
SecondWordWriteDataMirrorWriteItem8 D6077 CHANNEL
SecondWordWriteDataMirrorWriteItem80 D6797 CHANNEL
SecondWordWriteDataMirrorWriteItem81 D6807 CHANNEL
SecondWordWriteDataMirrorWriteItem82 D6817 CHANNEL
SecondWordWriteDataMirrorWriteItem83 D6827 CHANNEL
SecondWordWriteDataMirrorWriteItem84 D6837 CHANNEL
SecondWordWriteDataMirrorWriteItem85 D6847 CHANNEL
SecondWordWriteDataMirrorWriteItem86 D6857 CHANNEL
SecondWordWriteDataMirrorWriteItem87 D6867 CHANNEL
SecondWordWriteDataMirrorWriteItem88 D6877 CHANNEL
SecondWordWriteDataMirrorWriteItem89 D6887 CHANNEL
SecondWordWriteDataMirrorWriteItem9 D6087 CHANNEL
SecondWordWriteDataMirrorWriteItem90 D6897 CHANNEL
SecondWordWriteDataMirrorWriteItem91 D6907 CHANNEL
SecondWordWriteDataMirrorWriteItem92 D6917 CHANNEL
SecondWordWriteDataMirrorWriteItem93 D6927 CHANNEL
SecondWordWriteDataMirrorWriteItem94 D6937 CHANNEL
SecondWordWriteDataMirrorWriteItem95 D6947 CHANNEL
SecondWordWriteDataMirrorWriteItem96 D6957 CHANNEL
SecondWordWriteDataMirrorWriteItem97 D6967 CHANNEL
SecondWordWriteDataMirrorWriteItem98 D6977 CHANNEL
SecondWordWriteDataMirrorWriteItem99 D6987 CHANNEL
SecondWordWriteDataWriteItem1 D6005 CHANNEL
SecondWordWriteDataWriteItem10 D6095 CHANNEL
SecondWordWriteDataWriteItem100 D6995 CHANNEL
SecondWordWriteDataWriteItem11 D6105 CHANNEL
SecondWordWriteDataWriteItem12 D6115 CHANNEL
SecondWordWriteDataWriteItem13 D6125 CHANNEL
SecondWordWriteDataWriteItem14 D6135 CHANNEL
SecondWordWriteDataWriteItem15 D6145 CHANNEL
SecondWordWriteDataWriteItem16 D6155 CHANNEL
SecondWordWriteDataWriteItem17 D6165 CHANNEL
SecondWordWriteDataWriteItem18 D6175 CHANNEL
SecondWordWriteDataWriteItem19 D6185 CHANNEL
SecondWordWriteDataWriteItem2 D6015 CHANNEL
SecondWordWriteDataWriteItem20 D6195 CHANNEL
SecondWordWriteDataWriteItem21 D6205 CHANNEL
SecondWordWriteDataWriteItem22 D6215 CHANNEL
SecondWordWriteDataWriteItem23 D6225 CHANNEL
SecondWordWriteDataWriteItem24 D6235 CHANNEL
SecondWordWriteDataWriteItem25 D6245 CHANNEL
SecondWordWriteDataWriteItem26 D6255 CHANNEL
SecondWordWriteDataWriteItem27 D6265 CHANNEL
SecondWordWriteDataWriteItem28 D6275 CHANNEL
SecondWordWriteDataWriteItem29 D6285 CHANNEL
SecondWordWriteDataWriteItem3 D6025 CHANNEL
SecondWordWriteDataWriteItem30 D6295 CHANNEL
SecondWordWriteDataWriteItem31 D6305 CHANNEL
SecondWordWriteDataWriteItem32 D6315 CHANNEL
SecondWordWriteDataWriteItem33 D6325 CHANNEL
SecondWordWriteDataWriteItem34 D6335 CHANNEL
SecondWordWriteDataWriteItem35 D6345 CHANNEL
SecondWordWriteDataWriteItem36 D6355 CHANNEL
SecondWordWriteDataWriteItem37 D6365 CHANNEL
SecondWordWriteDataWriteItem38 D6375 CHANNEL
SecondWordWriteDataWriteItem39 D6385 CHANNEL
SecondWordWriteDataWriteItem4 D6035 CHANNEL
SecondWordWriteDataWriteItem40 D6395 CHANNEL
SecondWordWriteDataWriteItem41 D6405 CHANNEL
SecondWordWriteDataWriteItem42 D6415 CHANNEL
SecondWordWriteDataWriteItem43 D6425 CHANNEL
SecondWordWriteDataWriteItem44 D6435 CHANNEL
SecondWordWriteDataWriteItem45 D6445 CHANNEL
SecondWordWriteDataWriteItem46 D6455 CHANNEL
SecondWordWriteDataWriteItem47 D6465 CHANNEL
SecondWordWriteDataWriteItem48 D6475 CHANNEL
SecondWordWriteDataWriteItem49 D6485 CHANNEL
SecondWordWriteDataWriteItem5 D6045 CHANNEL
SecondWordWriteDataWriteItem50 D6495 CHANNEL
SecondWordWriteDataWriteItem51 D6505 CHANNEL
SecondWordWriteDataWriteItem52 D6515 CHANNEL
SecondWordWriteDataWriteItem53 D6525 CHANNEL
SecondWordWriteDataWriteItem54 D6535 CHANNEL
SecondWordWriteDataWriteItem55 D6545 CHANNEL
SecondWordWriteDataWriteItem56 D6555 CHANNEL
SecondWordWriteDataWriteItem57 D6565 CHANNEL
SecondWordWriteDataWriteItem58 D6575 CHANNEL
SecondWordWriteDataWriteItem59 D6585 CHANNEL
SecondWordWriteDataWriteItem6 D6055 CHANNEL
SecondWordWriteDataWriteItem60 D6595 CHANNEL
SecondWordWriteDataWriteItem61 D6605 CHANNEL
SecondWordWriteDataWriteItem62 D6615 CHANNEL
SecondWordWriteDataWriteItem63 D6625 CHANNEL
SecondWordWriteDataWriteItem64 D6635 CHANNEL
SecondWordWriteDataWriteItem65 D6645 CHANNEL
SecondWordWriteDataWriteItem66 D6655 CHANNEL
SecondWordWriteDataWriteItem67 D6665 CHANNEL
SecondWordWriteDataWriteItem68 D6675 CHANNEL
SecondWordWriteDataWriteItem69 D6685 CHANNEL
SecondWordWriteDataWriteItem7 D6065 CHANNEL
SecondWordWriteDataWriteItem70 D6695 CHANNEL
SecondWordWriteDataWriteItem71 D6705 CHANNEL
SecondWordWriteDataWriteItem72 D6715 CHANNEL
SecondWordWriteDataWriteItem73 D6725 CHANNEL
SecondWordWriteDataWriteItem74 D6735 CHANNEL
SecondWordWriteDataWriteItem75 D6745 CHANNEL
SecondWordWriteDataWriteItem76 D6755 CHANNEL
SecondWordWriteDataWriteItem77 D6765 CHANNEL
SecondWordWriteDataWriteItem78 D6775 CHANNEL
SecondWordWriteDataWriteItem79 D6785 CHANNEL
SecondWordWriteDataWriteItem8 D6075 CHANNEL
SecondWordWriteDataWriteItem80 D6795 CHANNEL
SecondWordWriteDataWriteItem81 D6805 CHANNEL
SecondWordWriteDataWriteItem82 D6815 CHANNEL
SecondWordWriteDataWriteItem83 D6825 CHANNEL
SecondWordWriteDataWriteItem84 D6835 CHANNEL
SecondWordWriteDataWriteItem85 D6845 CHANNEL
SecondWordWriteDataWriteItem86 D6855 CHANNEL
SecondWordWriteDataWriteItem87 D6865 CHANNEL
SecondWordWriteDataWriteItem88 D6875 CHANNEL
SecondWordWriteDataWriteItem89 D6885 CHANNEL
SecondWordWriteDataWriteItem9 D6085 CHANNEL
SecondWordWriteDataWriteItem90 D6895 CHANNEL
SecondWordWriteDataWriteItem91 D6905 CHANNEL
SecondWordWriteDataWriteItem92 D6915 CHANNEL
SecondWordWriteDataWriteItem93 D6925 CHANNEL
SecondWordWriteDataWriteItem94 D6935 CHANNEL
SecondWordWriteDataWriteItem95 D6945 CHANNEL
SecondWordWriteDataWriteItem96 D6955 CHANNEL
SecondWordWriteDataWriteItem97 D6965 CHANNEL
SecondWordWriteDataWriteItem98 D6975 CHANNEL
SecondWordWriteDataWriteItem99 D6985 CHANNEL
Send_PMCR W215.01 BOOL
SerialPortReset A526.00 BOOL
SerialPortResetCounter W207 INT
Stack_Empty W205.00 BOOL
Stack_Full_Diagnostic_Bit W215.04 BOOL
Stack_Start W0 DWORD
StartingModbusAddressReadItem1 D5002 CHANNEL
StartingModbusAddressReadItem10 D5092 CHANNEL
StartingModbusAddressReadItem100 D5992 CHANNEL
StartingModbusAddressReadItem11 D5102 CHANNEL
StartingModbusAddressReadItem12 D5112 CHANNEL
StartingModbusAddressReadItem13 D5122 CHANNEL
StartingModbusAddressReadItem14 D5132 CHANNEL
StartingModbusAddressReadItem15 D5142 CHANNEL
StartingModbusAddressReadItem16 D5152 CHANNEL
StartingModbusAddressReadItem17 D5162 CHANNEL
StartingModbusAddressReadItem18 D5172 CHANNEL
StartingModbusAddressReadItem19 D5182 CHANNEL
StartingModbusAddressReadItem2 D5012 CHANNEL
StartingModbusAddressReadItem20 D5192 CHANNEL
StartingModbusAddressReadItem21 D5202 CHANNEL
StartingModbusAddressReadItem22 D5212 CHANNEL
StartingModbusAddressReadItem23 D5222 CHANNEL
StartingModbusAddressReadItem24 D5232 CHANNEL
StartingModbusAddressReadItem25 D5242 CHANNEL
StartingModbusAddressReadItem26 D5252 CHANNEL
StartingModbusAddressReadItem27 D5262 CHANNEL
StartingModbusAddressReadItem28 D5272 CHANNEL
StartingModbusAddressReadItem29 D5282 CHANNEL
StartingModbusAddressReadItem3 D5022 CHANNEL
StartingModbusAddressReadItem30 D5292 CHANNEL
StartingModbusAddressReadItem31 D5302 CHANNEL
StartingModbusAddressReadItem32 D5312 CHANNEL
StartingModbusAddressReadItem33 D5322 CHANNEL
StartingModbusAddressReadItem34 D5332 CHANNEL
StartingModbusAddressReadItem35 D5342 CHANNEL
StartingModbusAddressReadItem36 D5352 CHANNEL
StartingModbusAddressReadItem37 D5362 CHANNEL
StartingModbusAddressReadItem38 D5372 CHANNEL
StartingModbusAddressReadItem39 D5382 CHANNEL
StartingModbusAddressReadItem4 D5032 CHANNEL
StartingModbusAddressReadItem40 D5392 CHANNEL
StartingModbusAddressReadItem41 D5402 CHANNEL
StartingModbusAddressReadItem42 D5412 CHANNEL
StartingModbusAddressReadItem43 D5422 CHANNEL
StartingModbusAddressReadItem44 D5432 CHANNEL
StartingModbusAddressReadItem45 D5442 CHANNEL
StartingModbusAddressReadItem46 D5452 CHANNEL
StartingModbusAddressReadItem47 D5462 CHANNEL
StartingModbusAddressReadItem48 D5472 CHANNEL
StartingModbusAddressReadItem49 D5482 CHANNEL
StartingModbusAddressReadItem5 D5042 CHANNEL
StartingModbusAddressReadItem50 D5492 CHANNEL
StartingModbusAddressReadItem51 D5502 CHANNEL
StartingModbusAddressReadItem52 D5512 CHANNEL
StartingModbusAddressReadItem53 D5522 CHANNEL
StartingModbusAddressReadItem54 D5532 CHANNEL
StartingModbusAddressReadItem55 D5542 CHANNEL
StartingModbusAddressReadItem56 D5552 CHANNEL
StartingModbusAddressReadItem57 D5562 CHANNEL
StartingModbusAddressReadItem58 D5572 CHANNEL
StartingModbusAddressReadItem59 D5582 CHANNEL
StartingModbusAddressReadItem6 D5052 CHANNEL
StartingModbusAddressReadItem60 D5592 CHANNEL
StartingModbusAddressReadItem61 D5602 CHANNEL
StartingModbusAddressReadItem62 D5612 CHANNEL
StartingModbusAddressReadItem63 D5622 CHANNEL
StartingModbusAddressReadItem64 D5632 CHANNEL
StartingModbusAddressReadItem65 D5642 CHANNEL
StartingModbusAddressReadItem66 D5652 CHANNEL
StartingModbusAddressReadItem67 D5662 CHANNEL
StartingModbusAddressReadItem68 D5672 CHANNEL
StartingModbusAddressReadItem69 D5682 CHANNEL
StartingModbusAddressReadItem7 D5062 CHANNEL
StartingModbusAddressReadItem70 D5692 CHANNEL
StartingModbusAddressReadItem71 D5702 CHANNEL
StartingModbusAddressReadItem72 D5712 CHANNEL
StartingModbusAddressReadItem73 D5722 CHANNEL
StartingModbusAddressReadItem74 D5732 CHANNEL
StartingModbusAddressReadItem75 D5742 CHANNEL
StartingModbusAddressReadItem76 D5752 CHANNEL
StartingModbusAddressReadItem77 D5762 CHANNEL
StartingModbusAddressReadItem78 D5772 CHANNEL
StartingModbusAddressReadItem79 D5782 CHANNEL
StartingModbusAddressReadItem8 D5072 CHANNEL
StartingModbusAddressReadItem80 D5792 CHANNEL
StartingModbusAddressReadItem81 D5802 CHANNEL
StartingModbusAddressReadItem82 D5812 CHANNEL
StartingModbusAddressReadItem83 D5822 CHANNEL
StartingModbusAddressReadItem84 D5832 CHANNEL
StartingModbusAddressReadItem85 D5842 CHANNEL
StartingModbusAddressReadItem86 D5852 CHANNEL
StartingModbusAddressReadItem87 D5862 CHANNEL
StartingModbusAddressReadItem88 D5872 CHANNEL
StartingModbusAddressReadItem89 D5882 CHANNEL
StartingModbusAddressReadItem9 D5082 CHANNEL
StartingModbusAddressReadItem90 D5892 CHANNEL
StartingModbusAddressReadItem91 D5902 CHANNEL
StartingModbusAddressReadItem92 D5912 CHANNEL
StartingModbusAddressReadItem93 D5922 CHANNEL
StartingModbusAddressReadItem94 D5932 CHANNEL
StartingModbusAddressReadItem95 D5942 CHANNEL
StartingModbusAddressReadItem96 D5952 CHANNEL
StartingModbusAddressReadItem97 D5962 CHANNEL
StartingModbusAddressReadItem98 D5972 CHANNEL
StartingModbusAddressReadItem99 D5982 CHANNEL
StartingModbusAddressWriteItem1 D6002 CHANNEL
StartingModbusAddressWriteItem10 D6092 CHANNEL
StartingModbusAddressWriteItem100 D6992 CHANNEL
StartingModbusAddressWriteItem11 D6102 CHANNEL
StartingModbusAddressWriteItem12 D6112 CHANNEL
StartingModbusAddressWriteItem13 D6122 CHANNEL
StartingModbusAddressWriteItem14 D6132 CHANNEL
StartingModbusAddressWriteItem15 D6142 CHANNEL
StartingModbusAddressWriteItem16 D6152 CHANNEL
StartingModbusAddressWriteItem17 D6162 CHANNEL
StartingModbusAddressWriteItem18 D6172 CHANNEL
StartingModbusAddressWriteItem19 D6182 CHANNEL
StartingModbusAddressWriteItem2 D6012 CHANNEL
StartingModbusAddressWriteItem20 D6192 CHANNEL
StartingModbusAddressWriteItem21 D6202 CHANNEL
StartingModbusAddressWriteItem22 D6212 CHANNEL
StartingModbusAddressWriteItem23 D6222 CHANNEL
StartingModbusAddressWriteItem24 D6232 CHANNEL
StartingModbusAddressWriteItem25 D6242 CHANNEL
StartingModbusAddressWriteItem26 D6252 CHANNEL
StartingModbusAddressWriteItem27 D6262 CHANNEL
StartingModbusAddressWriteItem28 D6272 CHANNEL
StartingModbusAddressWriteItem29 D6282 CHANNEL
StartingModbusAddressWriteItem3 D6022 CHANNEL
StartingModbusAddressWriteItem30 D6292 CHANNEL
StartingModbusAddressWriteItem31 D6302 CHANNEL
StartingModbusAddressWriteItem32 D6312 CHANNEL
StartingModbusAddressWriteItem33 D6322 CHANNEL
StartingModbusAddressWriteItem34 D6332 CHANNEL
StartingModbusAddressWriteItem35 D6342 CHANNEL
StartingModbusAddressWriteItem36 D6352 CHANNEL
StartingModbusAddressWriteItem37 D6362 CHANNEL
StartingModbusAddressWriteItem38 D6372 CHANNEL
StartingModbusAddressWriteItem39 D6382 CHANNEL
StartingModbusAddressWriteItem4 D6032 CHANNEL
StartingModbusAddressWriteItem40 D6392 CHANNEL
StartingModbusAddressWriteItem41 D6402 CHANNEL
StartingModbusAddressWriteItem42 D6412 CHANNEL
StartingModbusAddressWriteItem43 D6422 CHANNEL
StartingModbusAddressWriteItem44 D6432 CHANNEL
StartingModbusAddressWriteItem45 D6442 CHANNEL
StartingModbusAddressWriteItem46 D6452 CHANNEL
StartingModbusAddressWriteItem47 D6462 CHANNEL
StartingModbusAddressWriteItem48 D6472 CHANNEL
StartingModbusAddressWriteItem49 D6482 CHANNEL
StartingModbusAddressWriteItem5 D6042 CHANNEL
StartingModbusAddressWriteItem50 D6492 CHANNEL
StartingModbusAddressWriteItem51 D6502 CHANNEL
StartingModbusAddressWriteItem52 D6512 CHANNEL
StartingModbusAddressWriteItem53 D6522 CHANNEL
StartingModbusAddressWriteItem54 D6532 CHANNEL
StartingModbusAddressWriteItem55 D6542 CHANNEL
StartingModbusAddressWriteItem56 D6552 CHANNEL
StartingModbusAddressWriteItem57 D6562 CHANNEL
StartingModbusAddressWriteItem58 D6572 CHANNEL
StartingModbusAddressWriteItem59 D6582 CHANNEL
StartingModbusAddressWriteItem6 D6052 CHANNEL
StartingModbusAddressWriteItem60 D6592 CHANNEL
StartingModbusAddressWriteItem61 D6602 CHANNEL
StartingModbusAddressWriteItem62 D6612 CHANNEL
StartingModbusAddressWriteItem63 D6622 CHANNEL
StartingModbusAddressWriteItem64 D6632 CHANNEL
StartingModbusAddressWriteItem65 D6642 CHANNEL
StartingModbusAddressWriteItem66 D6652 CHANNEL
StartingModbusAddressWriteItem67 D6662 CHANNEL
StartingModbusAddressWriteItem68 D6672 CHANNEL
StartingModbusAddressWriteItem69 D6682 CHANNEL
StartingModbusAddressWriteItem7 D6062 CHANNEL
StartingModbusAddressWriteItem70 D6692 CHANNEL
StartingModbusAddressWriteItem71 D6702 CHANNEL
StartingModbusAddressWriteItem72 D6712 CHANNEL
StartingModbusAddressWriteItem73 D6722 CHANNEL
StartingModbusAddressWriteItem74 D6732 CHANNEL
StartingModbusAddressWriteItem75 D6742 CHANNEL
StartingModbusAddressWriteItem76 D6752 CHANNEL
StartingModbusAddressWriteItem77 D6762 CHANNEL
StartingModbusAddressWriteItem78 D6772 CHANNEL
StartingModbusAddressWriteItem79 D6782 CHANNEL
StartingModbusAddressWriteItem8 D6072 CHANNEL
StartingModbusAddressWriteItem80 D6792 CHANNEL
StartingModbusAddressWriteItem81 D6802 CHANNEL
StartingModbusAddressWriteItem82 D6812 CHANNEL
StartingModbusAddressWriteItem83 D6822 CHANNEL
StartingModbusAddressWriteItem84 D6832 CHANNEL
StartingModbusAddressWriteItem85 D6842 CHANNEL
StartingModbusAddressWriteItem86 D6852 CHANNEL
StartingModbusAddressWriteItem87 D6862 CHANNEL
StartingModbusAddressWriteItem88 D6872 CHANNEL
StartingModbusAddressWriteItem89 D6882 CHANNEL
StartingModbusAddressWriteItem9 D6082 CHANNEL
StartingModbusAddressWriteItem90 D6892 CHANNEL
StartingModbusAddressWriteItem91 D6902 CHANNEL
StartingModbusAddressWriteItem92 D6912 CHANNEL
StartingModbusAddressWriteItem93 D6922 CHANNEL
StartingModbusAddressWriteItem94 D6932 CHANNEL
StartingModbusAddressWriteItem95 D6942 CHANNEL
StartingModbusAddressWriteItem96 D6952 CHANNEL
StartingModbusAddressWriteItem97 D6962 CHANNEL
StartingModbusAddressWriteItem98 D6972 CHANNEL
StartingModbusAddressWriteItem99 D6982 CHANNEL
TemporaryCommDataBytes W212 CHANNEL
TemporaryFIFOArea W211 CHANNEL
TemporaryStartingDMErrorLocation W218 DWORD
Temporary_Pointer_For_Stack_Push W210 DWORD
TimeoutRetryCounter W208 CHANNEL
Top_Of_Stack W202 DWORD
WriteValidOrInvalidWriteItem1 D6008 CHANNEL
WriteValidOrInvalidWriteItem10 D6098 CHANNEL
WriteValidOrInvalidWriteItem100 D6998 CHANNEL
WriteValidOrInvalidWriteItem11 D6108 CHANNEL
WriteValidOrInvalidWriteItem12 D6118 CHANNEL
WriteValidOrInvalidWriteItem13 D6128 CHANNEL
WriteValidOrInvalidWriteItem14 D6138 CHANNEL
WriteValidOrInvalidWriteItem15 D6148 CHANNEL
WriteValidOrInvalidWriteItem16 D6158 CHANNEL
WriteValidOrInvalidWriteItem17 D6168 CHANNEL
WriteValidOrInvalidWriteItem18 D6178 CHANNEL
WriteValidOrInvalidWriteItem19 D6188 CHANNEL
WriteValidOrInvalidWriteItem2 D6018 CHANNEL
WriteValidOrInvalidWriteItem20 D6198 CHANNEL
WriteValidOrInvalidWriteItem21 D6208 CHANNEL
WriteValidOrInvalidWriteItem22 D6218 CHANNEL
WriteValidOrInvalidWriteItem23 D6228 CHANNEL
WriteValidOrInvalidWriteItem24 D6238 CHANNEL
WriteValidOrInvalidWriteItem25 D6248 CHANNEL
WriteValidOrInvalidWriteItem26 D6258 CHANNEL
WriteValidOrInvalidWriteItem27 D6268 CHANNEL
WriteValidOrInvalidWriteItem28 D6278 CHANNEL
WriteValidOrInvalidWriteItem29 D6288 CHANNEL
WriteValidOrInvalidWriteItem3 D6028 CHANNEL
WriteValidOrInvalidWriteItem30 D6298 CHANNEL
WriteValidOrInvalidWriteItem31 D6308 CHANNEL
WriteValidOrInvalidWriteItem32 D6318 CHANNEL
WriteValidOrInvalidWriteItem33 D6328 CHANNEL
WriteValidOrInvalidWriteItem34 D6338 CHANNEL
WriteValidOrInvalidWriteItem35 D6348 CHANNEL
WriteValidOrInvalidWriteItem36 D6358 CHANNEL
WriteValidOrInvalidWriteItem37 D6368 CHANNEL
WriteValidOrInvalidWriteItem38 D6378 CHANNEL
WriteValidOrInvalidWriteItem39 D6388 CHANNEL
WriteValidOrInvalidWriteItem4 D6038 CHANNEL
WriteValidOrInvalidWriteItem40 D6398 CHANNEL
WriteValidOrInvalidWriteItem41 D6408 CHANNEL
WriteValidOrInvalidWriteItem42 D6418 CHANNEL
WriteValidOrInvalidWriteItem43 D6428 CHANNEL
WriteValidOrInvalidWriteItem44 D6438 CHANNEL
WriteValidOrInvalidWriteItem45 D6448 CHANNEL
WriteValidOrInvalidWriteItem46 D6458 CHANNEL
WriteValidOrInvalidWriteItem47 D6468 CHANNEL
WriteValidOrInvalidWriteItem48 D6478 CHANNEL
WriteValidOrInvalidWriteItem49 D6488 CHANNEL
WriteValidOrInvalidWriteItem5 D6048 CHANNEL
WriteValidOrInvalidWriteItem50 D6498 CHANNEL
WriteValidOrInvalidWriteItem51 D6508 CHANNEL
WriteValidOrInvalidWriteItem52 D6518 CHANNEL
WriteValidOrInvalidWriteItem53 D6528 CHANNEL
WriteValidOrInvalidWriteItem54 D6538 CHANNEL
WriteValidOrInvalidWriteItem55 D6548 CHANNEL
WriteValidOrInvalidWriteItem56 D6558 CHANNEL
WriteValidOrInvalidWriteItem57 D6568 CHANNEL
WriteValidOrInvalidWriteItem58 D6578 CHANNEL
WriteValidOrInvalidWriteItem59 D6588 CHANNEL
WriteValidOrInvalidWriteItem6 D6058 CHANNEL
WriteValidOrInvalidWriteItem60 D6598 CHANNEL
WriteValidOrInvalidWriteItem61 D6608 CHANNEL
WriteValidOrInvalidWriteItem62 D6618 CHANNEL
WriteValidOrInvalidWriteItem63 D6628 CHANNEL
WriteValidOrInvalidWriteItem64 D6638 CHANNEL
WriteValidOrInvalidWriteItem65 D6648 CHANNEL
WriteValidOrInvalidWriteItem66 D6658 CHANNEL
WriteValidOrInvalidWriteItem67 D6668 CHANNEL
WriteValidOrInvalidWriteItem68 D6678 CHANNEL
WriteValidOrInvalidWriteItem69 D6688 CHANNEL
WriteValidOrInvalidWriteItem7 D6068 CHANNEL
WriteValidOrInvalidWriteItem70 D6698 CHANNEL
WriteValidOrInvalidWriteItem71 D6708 CHANNEL
WriteValidOrInvalidWriteItem72 D6718 CHANNEL
WriteValidOrInvalidWriteItem73 D6728 CHANNEL
WriteValidOrInvalidWriteItem74 D6738 CHANNEL
WriteValidOrInvalidWriteItem75 D6748 CHANNEL
WriteValidOrInvalidWriteItem76 D6758 CHANNEL
WriteValidOrInvalidWriteItem77 D6768 CHANNEL
WriteValidOrInvalidWriteItem78 D6778 CHANNEL
WriteValidOrInvalidWriteItem79 D6788 CHANNEL
WriteValidOrInvalidWriteItem8 D6078 CHANNEL
WriteValidOrInvalidWriteItem80 D6798 CHANNEL
WriteValidOrInvalidWriteItem81 D6808 CHANNEL
WriteValidOrInvalidWriteItem82 D6818 CHANNEL
WriteValidOrInvalidWriteItem83 D6828 CHANNEL
WriteValidOrInvalidWriteItem84 D6838 CHANNEL
WriteValidOrInvalidWriteItem85 D6848 CHANNEL
WriteValidOrInvalidWriteItem86 D6858 CHANNEL
WriteValidOrInvalidWriteItem87 D6868 CHANNEL
WriteValidOrInvalidWriteItem88 D6878 CHANNEL
WriteValidOrInvalidWriteItem89 D6888 CHANNEL
WriteValidOrInvalidWriteItem9 D6088 CHANNEL
WriteValidOrInvalidWriteItem90 D6898 CHANNEL
WriteValidOrInvalidWriteItem91 D6908 CHANNEL
WriteValidOrInvalidWriteItem92 D6918 CHANNEL
WriteValidOrInvalidWriteItem93 D6928 CHANNEL
WriteValidOrInvalidWriteItem94 D6938 CHANNEL
WriteValidOrInvalidWriteItem95 D6948 CHANNEL
WriteValidOrInvalidWriteItem96 D6958 CHANNEL
WriteValidOrInvalidWriteItem97 D6968 CHANNEL
WriteValidOrInvalidWriteItem98 D6978 CHANNEL
WriteValidOrInvalidWriteItem99 D6988 CHANNEL

## Program Port1 (cyclic task 10)

### Section Initilization

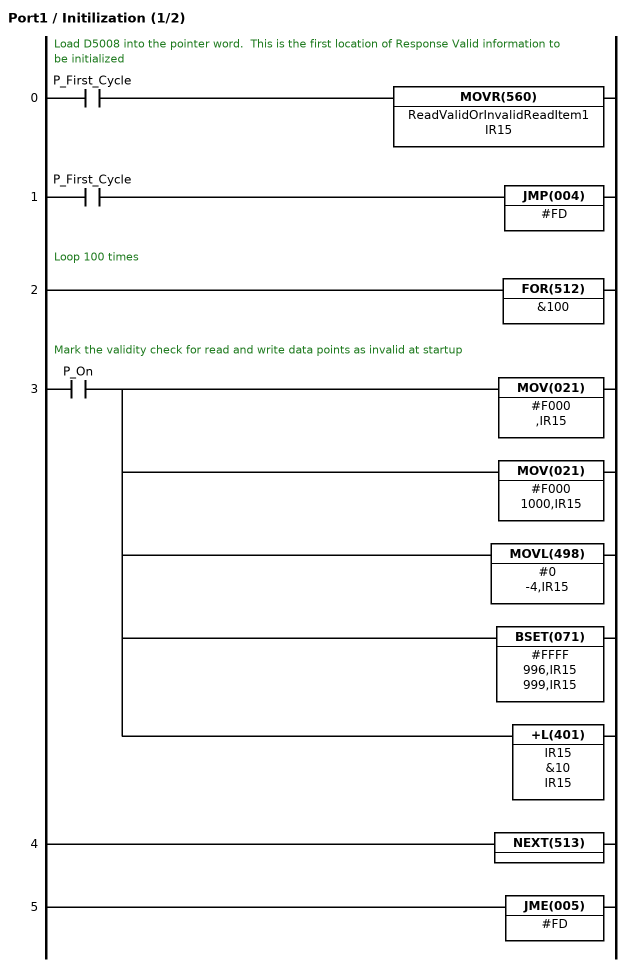
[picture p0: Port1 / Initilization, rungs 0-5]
; rung 0: Load D5008 into the pointer word.  This is the first location of Response Valid information to be initialized
LD P_First_Cycle
MOVR(560) ReadValidOrInvalidReadItem1 IR15
; rung 1
LD P_First_Cycle
JMP(004) #FD
; rung 2: Loop 100 times
FOR(512) &100
; rung 3: Mark the validity check for read and write data points as invalid at startup
LD P_On
MOV(021) #F000 ,IR15  // Mark each Read Validity check as invalid
MOV(021) #F000 1000,IR15  // Mark each Write Validity check as invalid
MOVL(498) #0 -4,IR15  // Clear the 'Read Data' so that it is not stale
BSET(071) #FFFF 996,IR15 999,IR15  // Set the Write Data and 'Last Write Data' to FFFF.  This allows Zero to be accepted as new data on startup.
+L(401) IR15 &10 IR15  // Pointer increment
; rung 4
NEXT(513)
; rung 5
JME(005) #FD

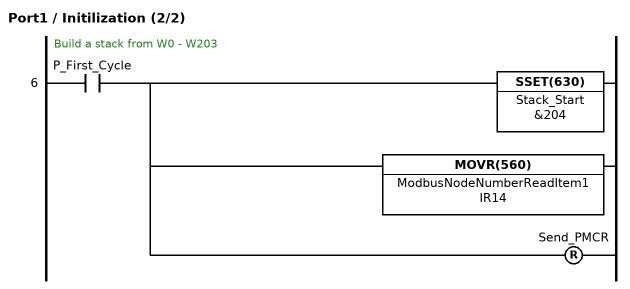
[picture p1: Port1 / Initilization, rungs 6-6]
; rung 6: Build a stack from W0 - W203
LD P_First_Cycle
SSET(630) Stack_Start &204
MOVR(560) ModbusNodeNumberReadItem1 IR14  // Load DM5000 into IR 14.  This is the pointer for walking through the list of items to poll
RSET Send_PMCR  // Turn off the Easy Modbus bit in case it was left on

### Section PortError

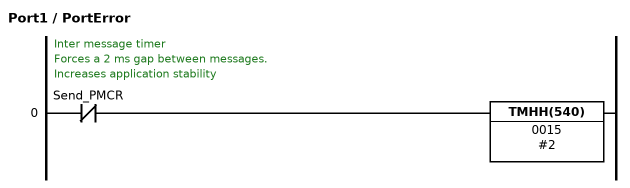
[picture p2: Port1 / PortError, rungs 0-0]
; rung 0: Inter message timer / Forces a 2 ms gap between messages. / Increases application stability
LDNOT Send_PMCR
TMHH(540) 0015 #2

### Section Stack_Population

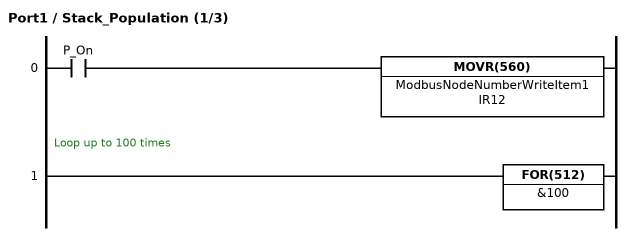
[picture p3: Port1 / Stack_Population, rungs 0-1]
; rung 0
LD P_On
MOVR(560) ModbusNodeNumberWriteItem1 IR12
; rung 1: Loop up to 100 times
FOR(512) &100

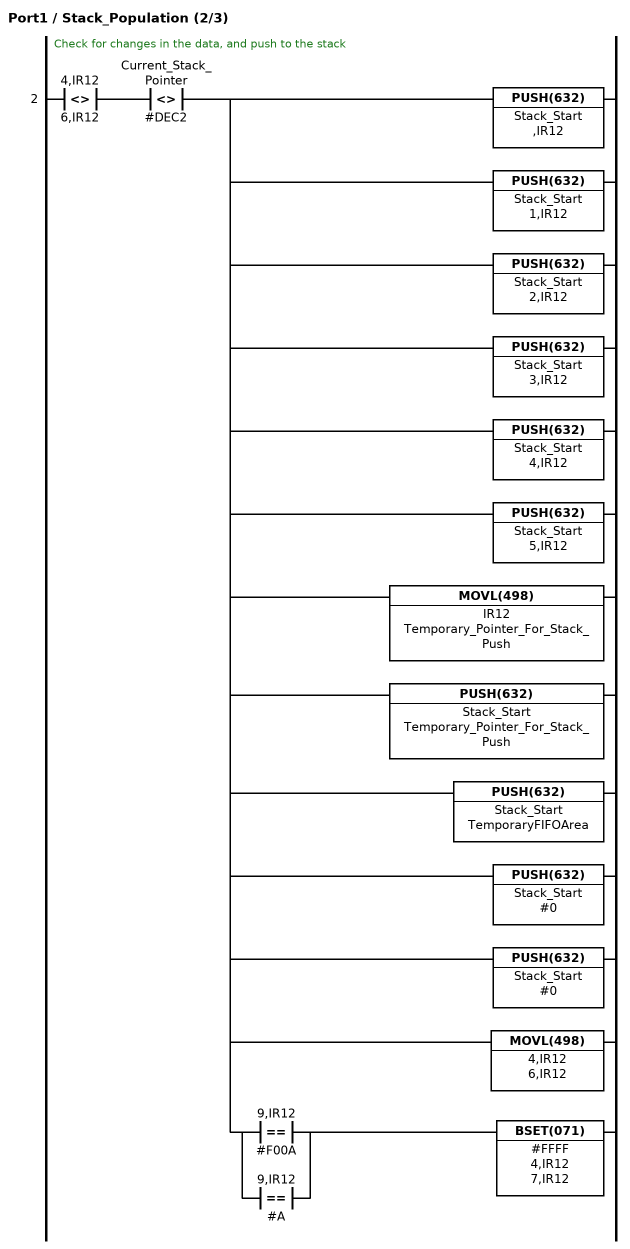
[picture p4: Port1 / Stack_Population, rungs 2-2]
; rung 2: Check for changes in the data, and push to the stack
LD<>L(306) 4,IR12 6,IR12
AND<>L(306) Current_Stack_Pointer #DEC2  // If the stack pointer is not at the top.  This prevents data loss if the stack is full
PUSH(632) Stack_Start ,IR12  // Push the Node Number
PUSH(632) Stack_Start 1,IR12  // Push the Function code
PUSH(632) Stack_Start 2,IR12  // Push the Start Address
PUSH(632) Stack_Start 3,IR12  // Push the Number of Points to Write
PUSH(632) Stack_Start 4,IR12  // Push the first word of data
PUSH(632) Stack_Start 5,IR12  // Push the second word of data
MOVL(498) IR12 Temporary_Pointer_For_Stack_Push  // Copy the pointer out to a temporary area so it can be pushed onto a stack
PUSH(632) Stack_Start Temporary_Pointer_For_Stack_Push  // Push the low address of the return address
PUSH(632) Stack_Start TemporaryFIFOArea  // Push the High address of the return address
PUSH(632) Stack_Start #0  // Pad with 0 for consistancy
PUSH(632) Stack_Start #0  // Pad with 0 for consistancy
MOVL(498) 4,IR12 6,IR12  // Copy this data to the 'last data written'
LD=(300) 9,IR12 #F00A  // End of List with auto clearing option
OR=(300) 9,IR12 #A  // Auto Clearing Option
ANDLD
BSET(071) #FFFF 4,IR12 7,IR12  // Write the data and 'last data written' to FFFF

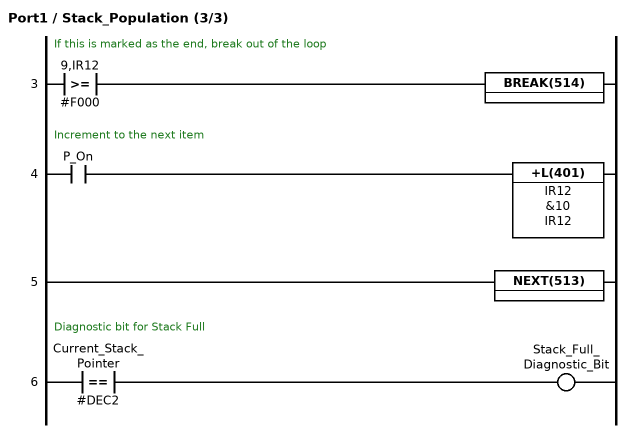
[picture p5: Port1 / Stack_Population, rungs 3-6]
; rung 3: If this is marked as the end, break out of the loop
LD>=(325) 9,IR12 #F000
BREAK(514)
; rung 4: Increment to the next item
LD P_On
+L(401) IR12 &10 IR12
; rung 5
NEXT(513)
; rung 6: Diagnostic bit for Stack Full
LD=L(301) Current_Stack_Pointer #DEC2  // If the stack pointer is not at the top.  This prevents data loss if the stack is full
OUT Stack_Full_Diagnostic_Bit

### Section Stack_Empty_Check

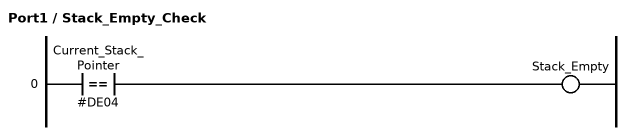
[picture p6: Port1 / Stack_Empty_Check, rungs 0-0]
; rung 0
LD=L(301) Current_Stack_Pointer #DE04  // If the stack pointer is at W4, then the stack is empty
OUT Stack_Empty

### Section Write

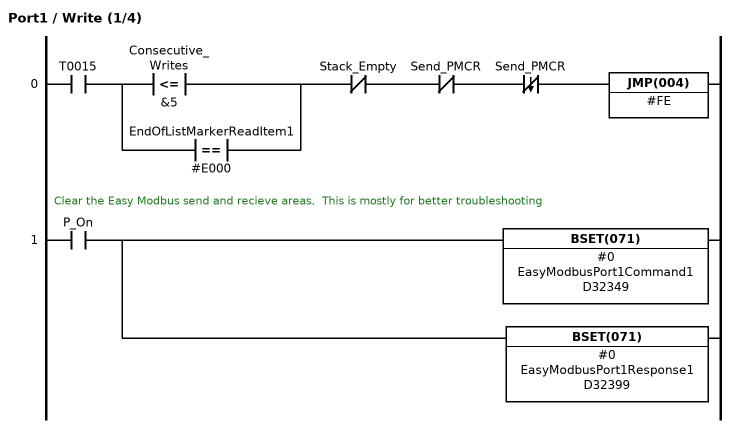
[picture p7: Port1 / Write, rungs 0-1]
; rung 0
LD T0015
LD<=(315) Consecutive_Writes &5  // If 5 or fewer consecutve writes have occurred
OR=(300) EndOfListMarkerReadItem1 #E000  // or if there are no read items in this application
ANDLD
ANDNOT Stack_Empty
ANDNOT Send_PMCR
%ANDNOT Send_PMCR
JMP(004) #FE
; rung 1: Clear the Easy Modbus send and recieve areas.  This is mostly for better troubleshooting
LD P_On
BSET(071) #0 EasyModbusPort1Command1 D32349
BSET(071) #0 EasyModbusPort1Response1 D32399

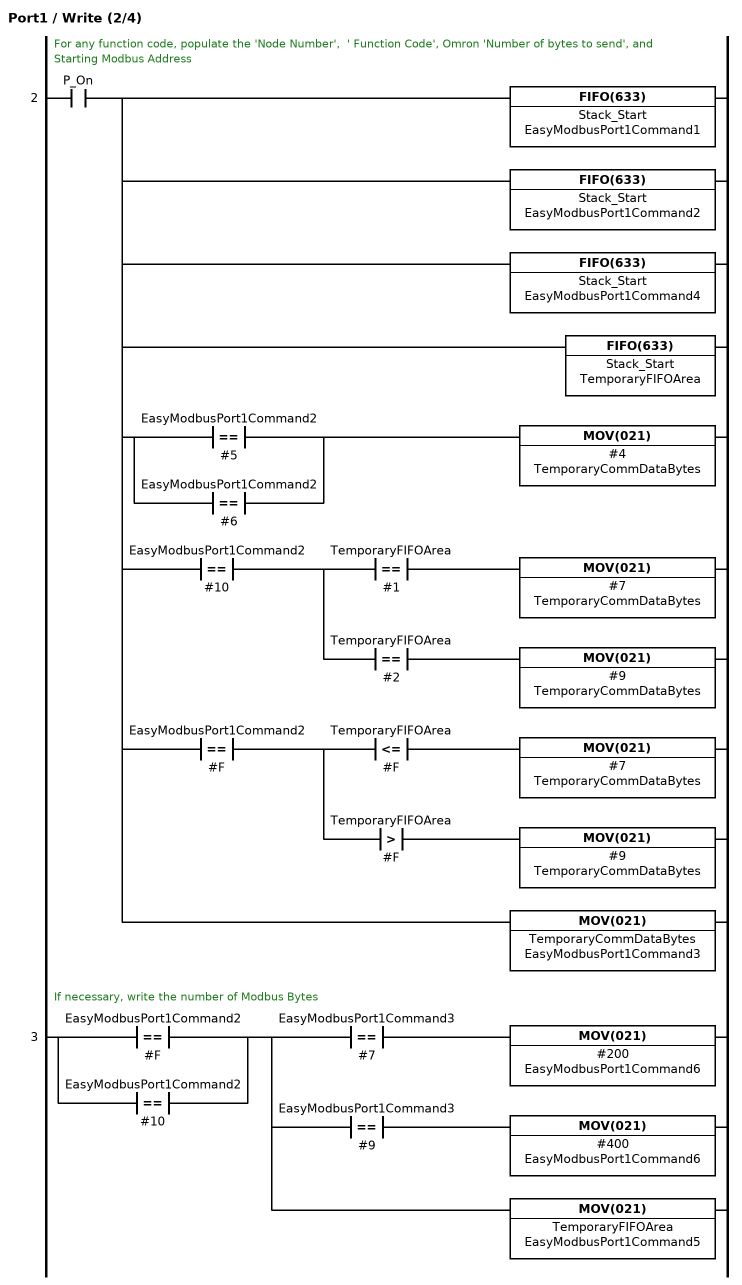
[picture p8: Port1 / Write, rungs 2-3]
; rung 2: For any function code, populate the 'Node Number',  ' Function Code', Omron 'Number of bytes to send', and Starting Modbus Address
LD P_On
OUT TR0
FIFO(633) Stack_Start EasyModbusPort1Command1  // FIFO the Node Number
FIFO(633) Stack_Start EasyModbusPort1Command2  // FIFO the Function Code
FIFO(633) Stack_Start EasyModbusPort1Command4  // FIFO the Starting Address
FIFO(633) Stack_Start TemporaryFIFOArea  // FIFO the Number of Items to Write
LD=(300) EasyModbusPort1Command2 #5  // If the function code is a 5
OR=(300) EasyModbusPort1Command2 #6  // or if the function code is a 6
ANDLD
MOV(021) #4 TemporaryCommDataBytes  // Move 2 BYTES of Data for the Omron Easy Modbus Function
LD TR0
AND=(300) EasyModbusPort1Command2 #10  // If the function code is a 10
OUT TR1
AND=(300) TemporaryFIFOArea #1
MOV(021) #7 TemporaryCommDataBytes
LD TR1
AND=(300) TemporaryFIFOArea #2
MOV(021) #9 TemporaryCommDataBytes
LD TR0
AND=(300) EasyModbusPort1Command2 #F  // If the function code is a 10
OUT TR1
AND<=(315) TemporaryFIFOArea #F  // If the number of COILS to be written is less than or equal to 16 (0F) then this would be 1 word of data
MOV(021) #7 TemporaryCommDataBytes
LD TR1
AND>(320) TemporaryFIFOArea #F  // If the number of COILS to be written is more than 16 (0F), then this is 2 words of data.  Up to 32 (20 HEX) coils are supported
MOV(021) #9 TemporaryCommDataBytes
LD TR0
MOV(021) TemporaryCommDataBytes EasyModbusPort1Command3  // Move the 'Omron Number of COMM Bytes'
; rung 3: If necessary, write the number of Modbus Bytes
LD=(300) EasyModbusPort1Command2 #F  // If the function code is 0F
OR=(300) EasyModbusPort1Command2 #10  // If the function code is 10
OUT TR0
AND=(300) EasyModbusPort1Command3 #7  // If the Omron Byte Count = 3, then this is 1 register
MOV(021) #200 EasyModbusPort1Command6  // Then 2 Bytes of Modbus data are to be sent
LD TR0
AND=(300) EasyModbusPort1Command3 #9  // If the Omron Byte Count = 3, then this is 1 register
MOV(021) #400 EasyModbusPort1Command6  // Then 4 Bytes of Modbus data are to be sent
LD TR0
MOV(021) TemporaryFIFOArea EasyModbusPort1Command5  // Write the number of Modbus Registers or Coils to Write

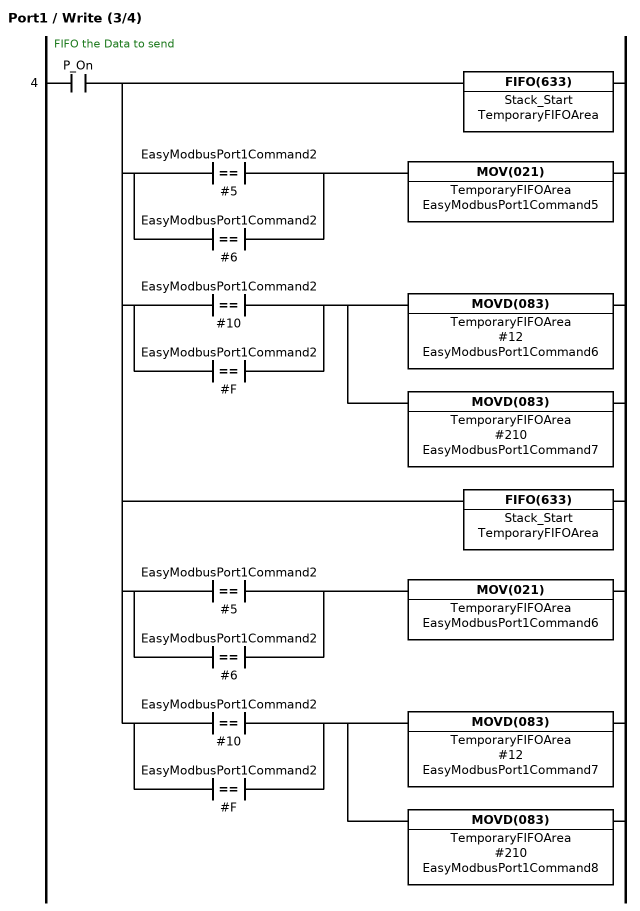
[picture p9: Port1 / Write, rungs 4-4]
; rung 4: FIFO the Data to send
LD P_On
OUT TR0
FIFO(633) Stack_Start TemporaryFIFOArea  // FIFO the First Data Word
LD=(300) EasyModbusPort1Command2 #5  // If the function code is a 5
OR=(300) EasyModbusPort1Command2 #6  // or if the function code is a 6
ANDLD
MOV(021) TemporaryFIFOArea EasyModbusPort1Command5  // Move the First Word of Data
LD TR0
LD=(300) EasyModbusPort1Command2 #10  // If the function code is a 10
OR=(300) EasyModbusPort1Command2 #F  // If the function code is a 10
ANDLD
MOVD(083) TemporaryFIFOArea #12 EasyModbusPort1Command6
MOVD(083) TemporaryFIFOArea #210 EasyModbusPort1Command7
LD TR0
FIFO(633) Stack_Start TemporaryFIFOArea  // FIFO the First Data Word
LD=(300) EasyModbusPort1Command2 #5  // If the function code is a 5
OR=(300) EasyModbusPort1Command2 #6  // or if the function code is a 6
ANDLD
MOV(021) TemporaryFIFOArea EasyModbusPort1Command6  // Move the First Word of Data
LD TR0
LD=(300) EasyModbusPort1Command2 #10  // If the function code is a 10
OR=(300) EasyModbusPort1Command2 #F  // If the function code is a 10
ANDLD
MOVD(083) TemporaryFIFOArea #12 EasyModbusPort1Command7
MOVD(083) TemporaryFIFOArea #210 EasyModbusPort1Command8

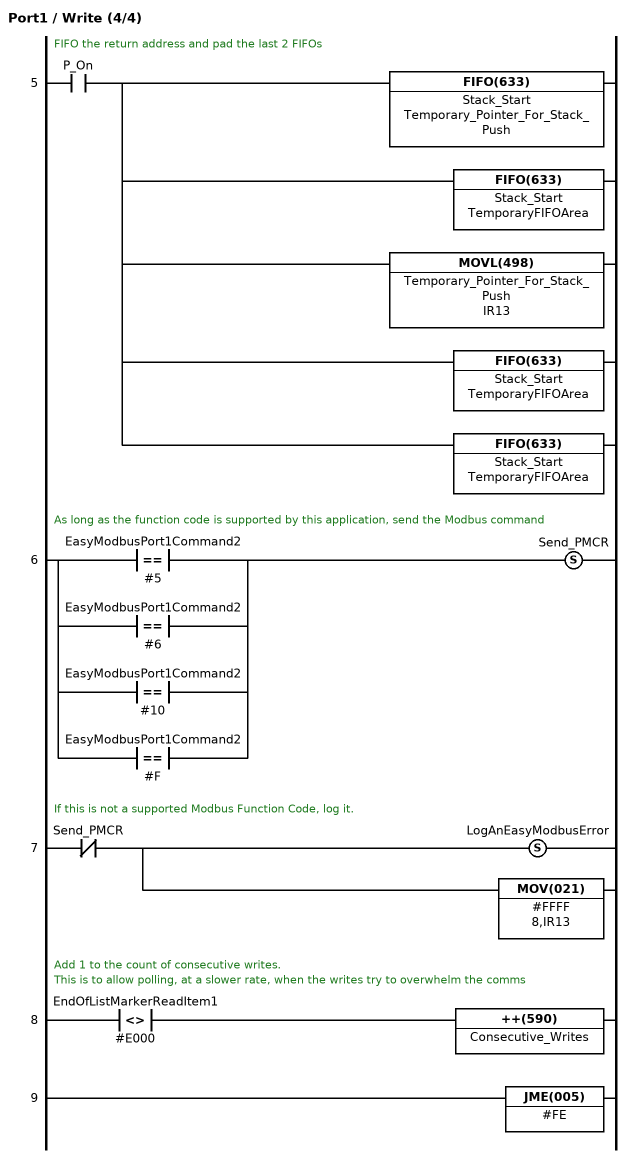
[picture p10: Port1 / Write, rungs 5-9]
; rung 5: FIFO the return address and pad the last 2 FIFOs
LD P_On
FIFO(633) Stack_Start Temporary_Pointer_For_Stack_Push
FIFO(633) Stack_Start TemporaryFIFOArea
MOVL(498) Temporary_Pointer_For_Stack_Push IR13  // Create the Return Address
FIFO(633) Stack_Start TemporaryFIFOArea  // FIFO for stack consistency
FIFO(633) Stack_Start TemporaryFIFOArea  // FIFO for stack consistency
; rung 6: As long as the function code is supported by this application, send the Modbus command
LD=(300) EasyModbusPort1Command2 #5  // If the function code is a 5
OR=(300) EasyModbusPort1Command2 #6  // or if the function code is a 6
OR=(300) EasyModbusPort1Command2 #10  // If the function code is a 10
OR=(300) EasyModbusPort1Command2 #F  // If the function code is a 10
SET Send_PMCR
; rung 7: If this is not a supported Modbus Function Code, log it.
LDNOT Send_PMCR
SET LogAnEasyModbusError
MOV(021) #FFFF 8,IR13  // Mark the Response OK with an FFFF for BAD DATA
; rung 8: Add 1 to the count of consecutive writes. / This is to allow polling, at a slower rate, when the writes try to overwhelm the comms
LD<>(305) EndOfListMarkerReadItem1 #E000  // If there are read items in this application
++(590) Consecutive_Writes
; rung 9
JME(005) #FE

### Section Polling

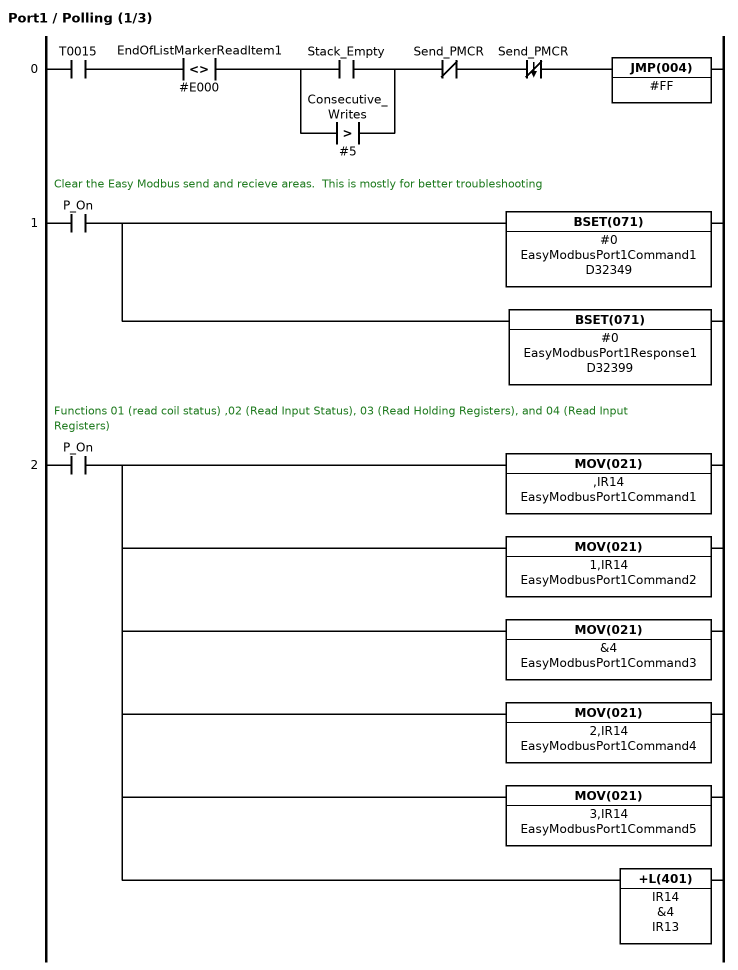
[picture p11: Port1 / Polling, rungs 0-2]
; rung 0
LD T0015
AND<>(305) EndOfListMarkerReadItem1 #E000  // If there are Read Items in this application
LD Stack_Empty  // If the stack is empty
OR>(320) Consecutive_Writes #5  // or waiting to perform a read after 5 consecutive writes
ANDLD
ANDNOT Send_PMCR
%ANDNOT Send_PMCR
JMP(004) #FF  // Run the code to send a request
; rung 1: Clear the Easy Modbus send and recieve areas.  This is mostly for better troubleshooting
LD P_On
BSET(071) #0 EasyModbusPort1Command1 D32349
BSET(071) #0 EasyModbusPort1Response1 D32399
; rung 2: Functions 01 (read coil status) ,02 (Read Input Status), 03 (Read Holding Registers), and 04 (Read Input Registers)
LD P_On
MOV(021) ,IR14 EasyModbusPort1Command1  // Move the node number
MOV(021) 1,IR14 EasyModbusPort1Command2  // Move the Function Code
MOV(021) &4 EasyModbusPort1Command3  // Set the number of BYTES of data FOR OMRON FUNCTION
MOV(021) 2,IR14 EasyModbusPort1Command4  // Move the starting address
MOV(021) 3,IR14 EasyModbusPort1Command5  // Move the number of pieces of data to read (either bits or words, depending on the Modbus function).
+L(401) IR14 &4 IR13  // Store the address where the response should be stored in IR13

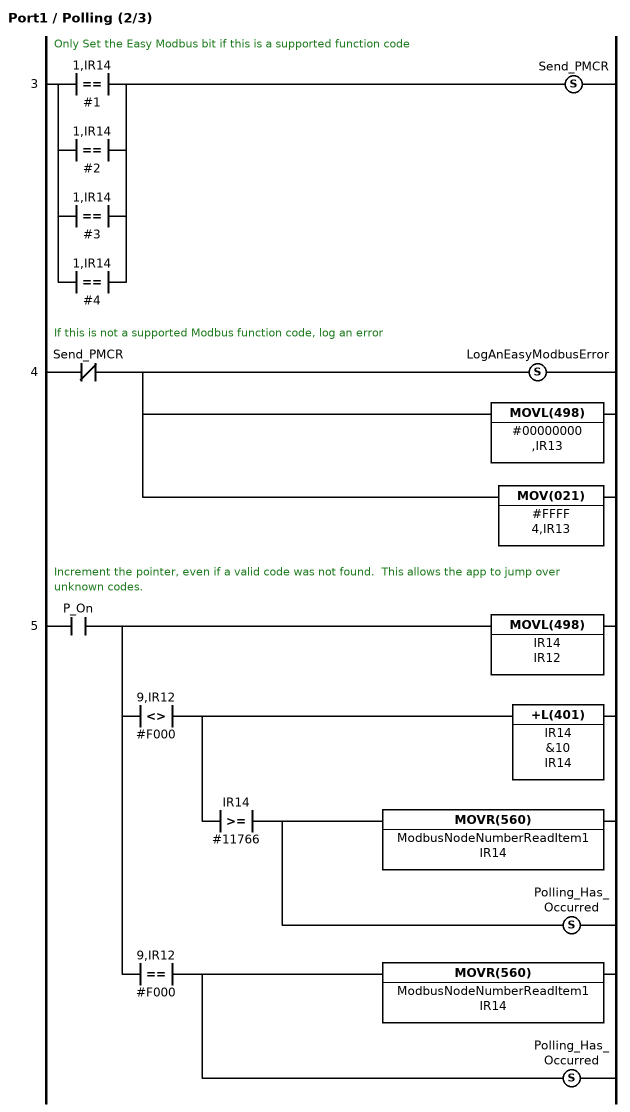
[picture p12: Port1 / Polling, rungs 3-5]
; rung 3: Only Set the Easy Modbus bit if this is a supported function code
LD=(300) 1,IR14 #1  // If the Modbus code to be sent is a 1 (Read Coil Status)
OR=(300) 1,IR14 #2  // If the Modbus code to be sent is a 2 (Read Input Status)
OR=(300) 1,IR14 #3  // If the Modbus code to be sent is a 3 (Read Holding Registers)
OR=(300) 1,IR14 #4  // If the Modbus code to be sent is a 04 (read Input Registers)
SET Send_PMCR
; rung 4: If this is not a supported Modbus function code, log an error
LDNOT Send_PMCR
SET LogAnEasyModbusError
MOVL(498) #00000000 ,IR13  // Write 0000 as the data
MOV(021) #FFFF 4,IR13  // Mark the Response OK with an FFFF for BAD DATA
; rung 5: Increment the pointer, even if a valid code was not found.  This allows the app to jump over unknown codes.
LD P_On
OUT TR0
MOVL(498) IR14 IR12  // Capture the value of the pointer to prevent flip / flop in the same scan
AND<>(305) 9,IR12 #F000  // If the end of polling has been reached
+L(401) IR14 &10 IR14  // Add 10 channels to the pointer
AND>=L(326) IR14 #11766  // Of if the pointer reaches D5990
MOVR(560) ModbusNodeNumberReadItem1 IR14  // Load DM5000 into IR 14.  This is the pointer for walking through the list of items to poll
SET Polling_Has_Occurred  // For Poll Cycle Timing
LD TR0
AND=(300) 9,IR12 #F000  // If the end of polling has been reached
MOVR(560) ModbusNodeNumberReadItem1 IR14  // Load DM5000 into IR 14.  This is the pointer for walking through the list of items to poll
SET Polling_Has_Occurred  // For Poll Cycle Timing

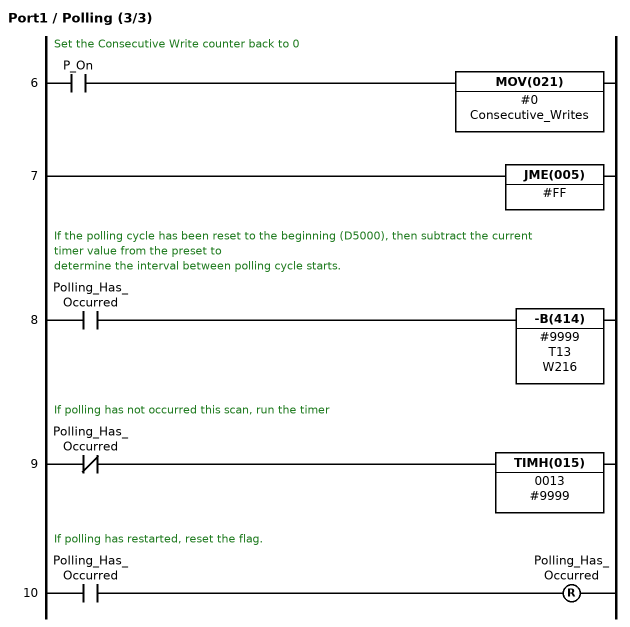
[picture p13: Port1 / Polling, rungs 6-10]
; rung 6: Set the Consecutive Write counter back to 0
LD P_On
MOV(021) #0 Consecutive_Writes
; rung 7
JME(005) #FF
; rung 8: If the polling cycle has been reset to the beginning (D5000), then subtract the current timer value from the preset to / determine the interval between polling cycle starts.
LD Polling_Has_Occurred
-B(414) #9999 T13 W216  // post the interval between starting polling cycles in W216 as xx.xx seconds
; rung 9: If polling has not occurred this scan, run the timer
LDNOT Polling_Has_Occurred
TIMH(015) 0013 #9999
; rung 10: If polling has restarted, reset the flag.
LD Polling_Has_Occurred
RSET Polling_Has_Occurred

### Section Responses

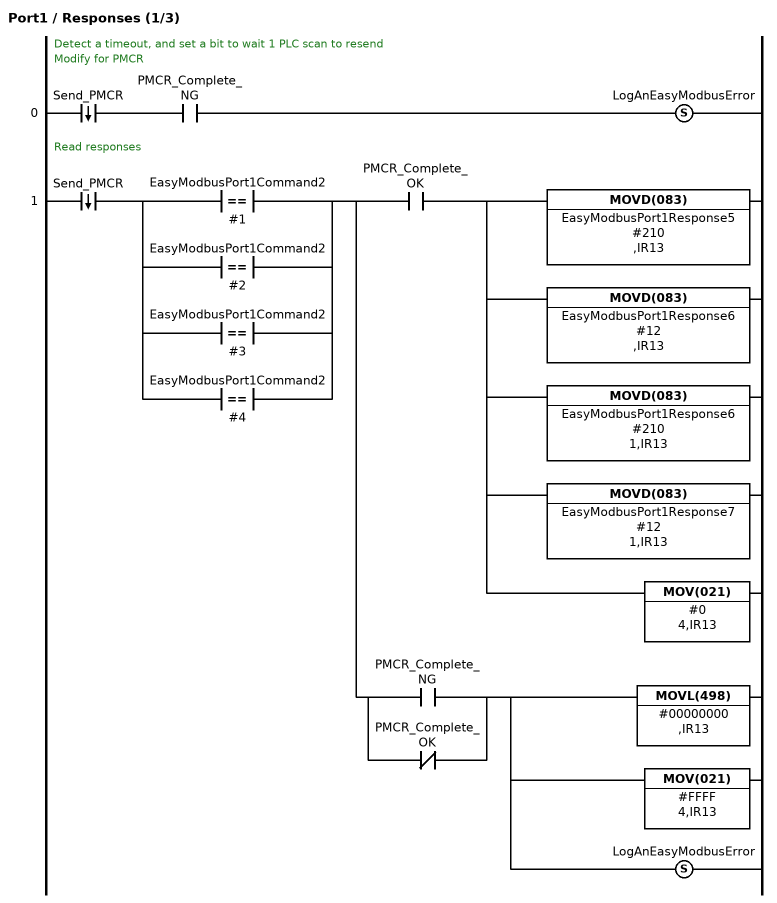
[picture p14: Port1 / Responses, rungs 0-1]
; rung 0: Detect a timeout, and set a bit to wait 1 PLC scan to resend / Modify for PMCR
%LD Send_PMCR
AND PMCR_Complete_NG
SET LogAnEasyModbusError  // Add this node and function code to the error list
; rung 1: Read responses
%LD Send_PMCR
LD=(300) EasyModbusPort1Command2 #1  // If the Modbus code that was sent was a 1 (Read Coil Status)
OR=(300) EasyModbusPort1Command2 #2  // If the Modbus code that was sent was a 2 (Read Input Status)
OR=(300) EasyModbusPort1Command2 #3  // If the Modbus code that was sent was a 3 (Read Holding Registers)
OR=(300) EasyModbusPort1Command2 #4  // If the Modbus code that was sent was a 04 (read Input Registers)
ANDLD
OUT TR0
AND PMCR_Complete_OK
MOVD(083) EasyModbusPort1Response5 #210 ,IR13
MOVD(083) EasyModbusPort1Response6 #12 ,IR13
MOVD(083) EasyModbusPort1Response6 #210 1,IR13
MOVD(083) EasyModbusPort1Response7 #12 1,IR13
MOV(021) #0 4,IR13  // Mark the Response OK with a 0 for OK DATA
LD TR0
LD PMCR_Complete_NG
ORNOT PMCR_Complete_OK  // Added for PMCR version in case PMCR did not start correctly
ANDLD
MOVL(498) #00000000 ,IR13  // Write 00000000 as the data across both response registeres
MOV(021) #FFFF 4,IR13  // Mark the Response OK with an FFFF for BAD DATA
SET LogAnEasyModbusError  // Add this node and function code to the error list

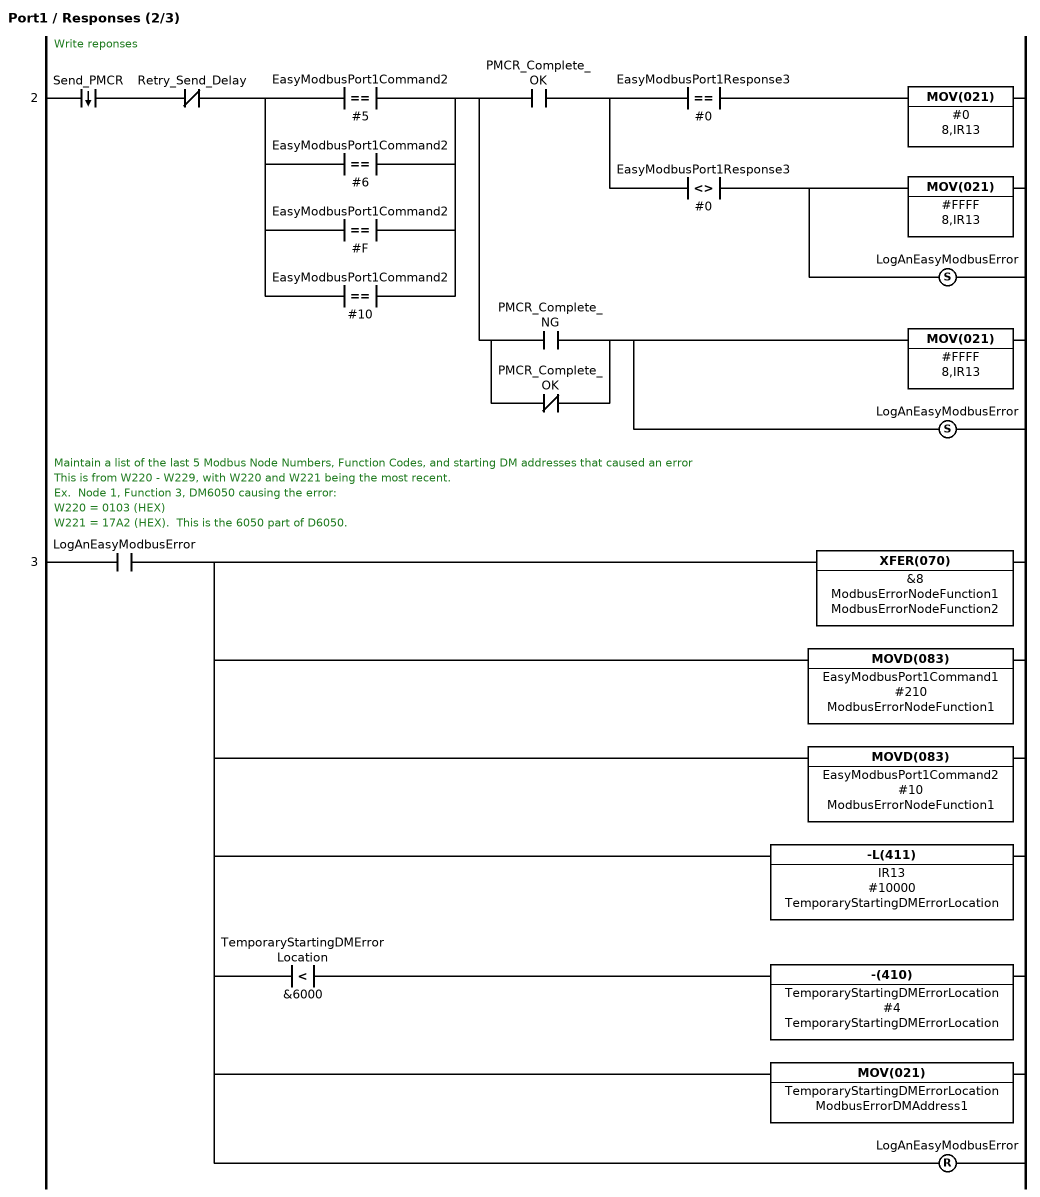
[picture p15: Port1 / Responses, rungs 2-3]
; rung 2: Write reponses
%LD Send_PMCR
ANDNOT Retry_Send_Delay
LD=(300) EasyModbusPort1Command2 #5  // If the Modbus code that was sent was a 5 (Read Coil Status)
OR=(300) EasyModbusPort1Command2 #6  // If the Modbus code that was sent was a 6 (Read Input Status)
OR=(300) EasyModbusPort1Command2 #F  // If the Modbus code that was sent was a F(Read Holding Registers)
OR=(300) EasyModbusPort1Command2 #10  // If the Modbus code that was sent was a 10
ANDLD
OUT TR0
AND PMCR_Complete_OK
OUT TR1
AND=(300) EasyModbusPort1Response3 #0  // And the Modbus  Error Code was 0
MOV(021) #0 8,IR13  // Mark the Response OK with a 0 for OK DATA
LD TR1
AND<>(305) EasyModbusPort1Response3 #0  // And the Modbus  Error Code was NOT 0
MOV(021) #FFFF 8,IR13  // Mark the Response OK with an FFFF for BAD DATA
SET LogAnEasyModbusError  // Add this node and function code to the error list
LD TR0
LD PMCR_Complete_NG
ORNOT PMCR_Complete_OK  // Added for PMCR version in case PMCR did not start correctly
ANDLD
MOV(021) #FFFF 8,IR13  // Mark the Response OK with an FFFF for BAD DATA
SET LogAnEasyModbusError  // Add this node and function code to the error list
; rung 3: Maintain a list of the last 5 Modbus Node Numbers, Function Codes, and starting DM addresses that caused an error / This is from W220 - W229, with W220 and W221 being the most recent. / Ex.  Node 1, Function 3, DM6050 causing the error: / W220 = 0103 (HEX) / W221 = 17A2 (HEX).  This is the 6050 part of D6050.
LD LogAnEasyModbusError
OUT TR0
XFER(070) &8 ModbusErrorNodeFunction1 ModbusErrorNodeFunction2  // Shift the last 9 records
MOVD(083) EasyModbusPort1Command1 #210 ModbusErrorNodeFunction1  // Capture the Modbus Node Number
MOVD(083) EasyModbusPort1Command2 #10 ModbusErrorNodeFunction1  // Capture the Modbus Function Code
-L(411) IR13 #10000 TemporaryStartingDMErrorLocation
AND<(310) TemporaryStartingDMErrorLocation &6000
-(410) TemporaryStartingDMErrorLocation #4 TemporaryStartingDMErrorLocation  // Subtract 4 to compensate for the offset difference between the receive area for a Write command vs a Read command
LD TR0
MOV(021) TemporaryStartingDMErrorLocation ModbusErrorDMAddress1
RSET LogAnEasyModbusError

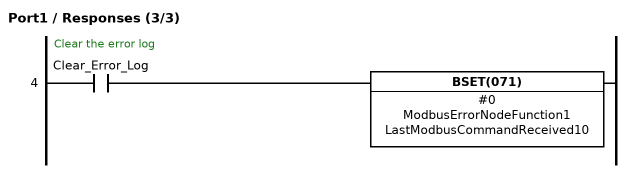
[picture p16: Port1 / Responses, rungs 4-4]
; rung 4: Clear the error log
LD Clear_Error_Log
BSET(071) #0 ModbusErrorNodeFunction1 LastModbusCommandReceived10

### Section PMCR

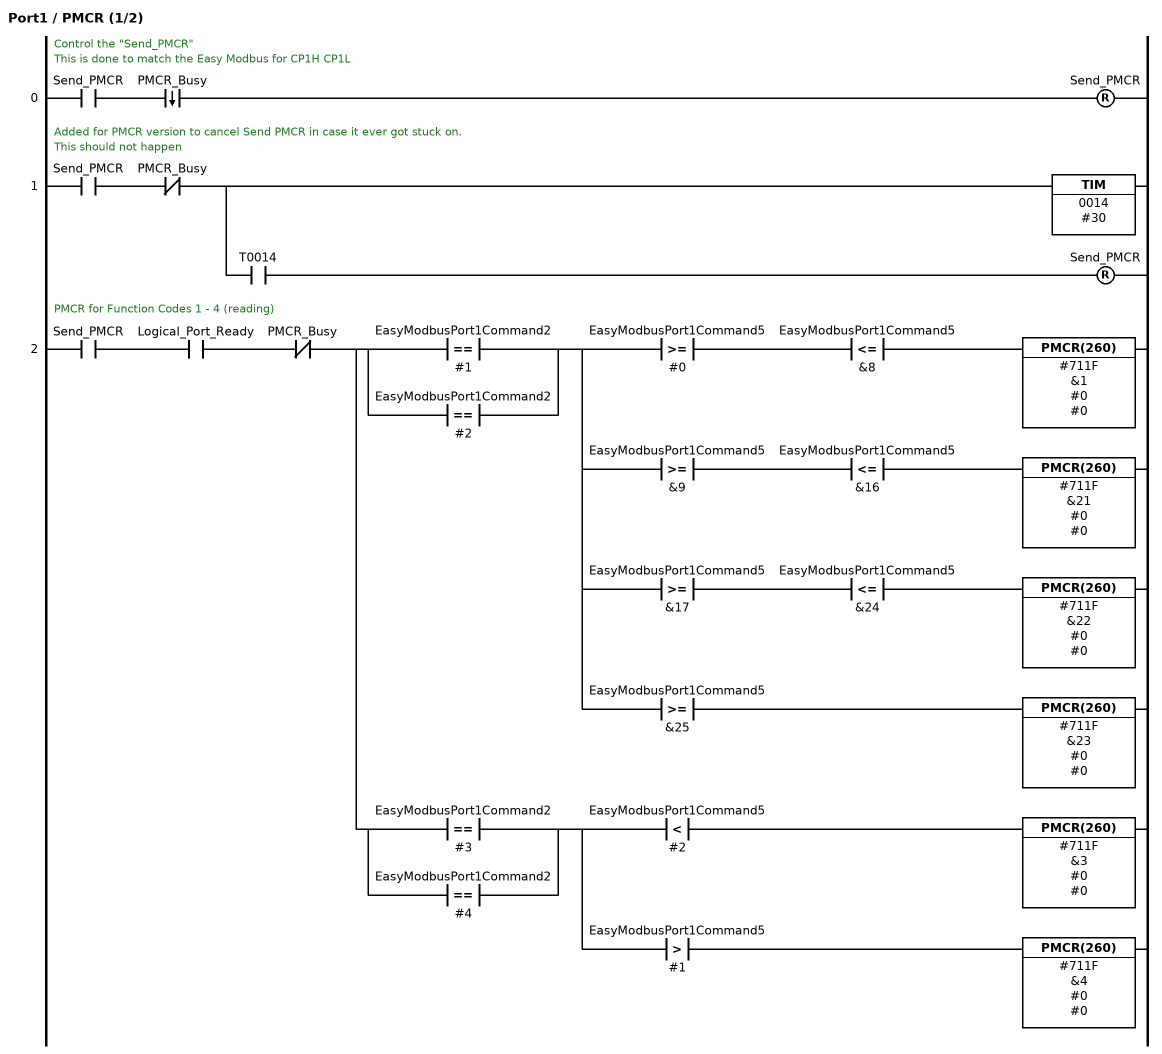
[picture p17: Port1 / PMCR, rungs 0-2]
; rung 0: Control the "Send_PMCR" / This is done to match the Easy Modbus for CP1H CP1L
LD Send_PMCR
%AND PMCR_Busy  // when the PMCR finishes
RSET Send_PMCR
; rung 1: Added for PMCR version to cancel Send PMCR in case it ever got stuck on. / This should not happen
LD Send_PMCR  // If the PMCR Send is on
ANDNOT PMCR_Busy  // but the port has not been busy for 3 seconds
TIM 0014 #30
AND T0014
RSET Send_PMCR  // reset the PMCR Busy
; rung 2: PMCR for Function Codes 1 - 4 (reading)
LD Send_PMCR
AND Logical_Port_Ready
ANDNOT PMCR_Busy
OUT TR0
LD=(300) EasyModbusPort1Command2 #1
OR=(300) EasyModbusPort1Command2 #2
ANDLD
OUT TR1
AND>=(325) EasyModbusPort1Command5 #0  // If equal to or greater than 0 (0 would actually return an error)
AND<=(315) EasyModbusPort1Command5 &8  // If less than or equal to 8
PMCR(260) #711F &1 #0 #0
LD TR1
AND>=(325) EasyModbusPort1Command5 &9  // If equal to or greater than 9
AND<=(315) EasyModbusPort1Command5 &16  // If less than or equal to 16
PMCR(260) #711F &21 #0 #0
LD TR1
AND>=(325) EasyModbusPort1Command5 &17  // If equal to or greater than 17
AND<=(315) EasyModbusPort1Command5 &24  // less than or equal to 24
PMCR(260) #711F &22 #0 #0
LD TR1
AND>=(325) EasyModbusPort1Command5 &25  // If equal to or greater than 25
PMCR(260) #711F &23 #0 #0
LD TR0
LD=(300) EasyModbusPort1Command2 #3
OR=(300) EasyModbusPort1Command2 #4
ANDLD
OUT TR0
AND<(310) EasyModbusPort1Command5 #2  // If less than 2 words are to be read (0 would cause PMCR error)
PMCR(260) #711F &3 #0 #0
LD TR0
AND>(320) EasyModbusPort1Command5 #1  // If more than 1 register is to be read (more than 2 would cause PMCR error)
PMCR(260) #711F &4 #0 #0

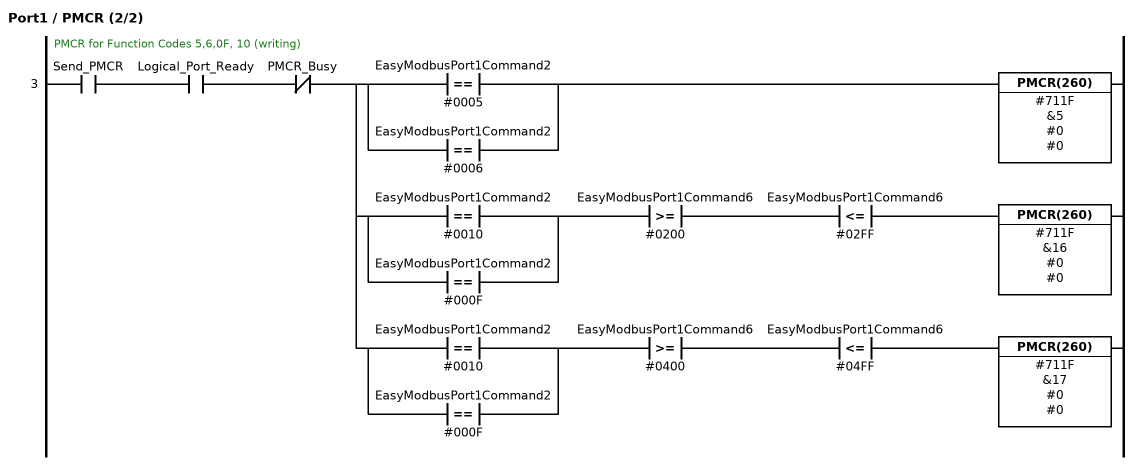
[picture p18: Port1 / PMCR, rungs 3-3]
; rung 3: PMCR for Function Codes 5,6,0F, 10 (writing)
LD Send_PMCR
AND Logical_Port_Ready
ANDNOT PMCR_Busy
OUT TR0
LD=(300) EasyModbusPort1Command2 #0005
OR=(300) EasyModbusPort1Command2 #0006
ANDLD
PMCR(260) #711F &5 #0 #0
LD TR0
LD=(300) EasyModbusPort1Command2 #0010
OR=(300) EasyModbusPort1Command2 #000F
ANDLD
AND>=(325) EasyModbusPort1Command6 #0200  // Checking for #02 in high byte
AND<=(315) EasyModbusPort1Command6 #02FF  // Checking for #02 in high byte
PMCR(260) #711F &16 #0 #0
LD TR0
LD=(300) EasyModbusPort1Command2 #0010
OR=(300) EasyModbusPort1Command2 #000F
ANDLD
AND>=(325) EasyModbusPort1Command6 #0400  // Checking for #04 in high byte
AND<=(315) EasyModbusPort1Command6 #04FF  // Checking for #04 in high byte
PMCR(260) #711F &17 #0 #0

### Section END
; rung 0
END(001)

# PLC CP1HCP1LModbusSinglePort: CP1L L

## Global symbols (name address type ; comment)
Clear_Error_Log W215.03 BOOL
Consecutive_Writes W217 INT
Current_Stack_Pointer W2 DWORD
EasyModbusPort1Command1 D32300 CHANNEL
EasyModbusPort1Command10 D32309 CHANNEL
EasyModbusPort1Command2 D32301 CHANNEL
EasyModbusPort1Command3 D32302 CHANNEL
EasyModbusPort1Command4 D32303 CHANNEL
EasyModbusPort1Command5 D32304 CHANNEL
EasyModbusPort1Command6 D32305 CHANNEL
EasyModbusPort1Command7 D32306 CHANNEL
EasyModbusPort1Command8 D32307 CHANNEL
EasyModbusPort1Command9 D32308 CHANNEL
EasyModbusPort1Response1 D32350 CHANNEL
EasyModbusPort1Response10 D32359 CHANNEL
EasyModbusPort1Response2 D32351 CHANNEL
EasyModbusPort1Response3 D32352 CHANNEL
EasyModbusPort1Response4 D32353 CHANNEL
EasyModbusPort1Response5 D32354 CHANNEL
EasyModbusPort1Response6 D32355 CHANNEL
EasyModbusPort1Response7 D32356 CHANNEL
EasyModbusPort1Response8 D32357 CHANNEL
EasyModbusPort1Response9 D32358 CHANNEL
Easy_Modbus_Execute A640.00 BOOL
Easy_Modbus_NG_Complete A640.02 BOOL
Easy_Modbus_OK_Complete A640.01 BOOL
EndOfListMarkerReadItem1 D5009 CHANNEL
EndOfListMarkerReadItem10 D5099 CHANNEL
EndOfListMarkerReadItem100 D5999 CHANNEL
EndOfListMarkerReadItem11 D5109 CHANNEL
EndOfListMarkerReadItem12 D5119 CHANNEL
EndOfListMarkerReadItem13 D5129 CHANNEL
EndOfListMarkerReadItem14 D5139 CHANNEL
EndOfListMarkerReadItem15 D5149 CHANNEL
EndOfListMarkerReadItem16 D5159 CHANNEL
EndOfListMarkerReadItem17 D5169 CHANNEL
EndOfListMarkerReadItem18 D5179 CHANNEL
EndOfListMarkerReadItem19 D5189 CHANNEL
EndOfListMarkerReadItem2 D5019 CHANNEL
EndOfListMarkerReadItem20 D5199 CHANNEL
EndOfListMarkerReadItem21 D5209 CHANNEL
EndOfListMarkerReadItem22 D5219 CHANNEL
EndOfListMarkerReadItem23 D5229 CHANNEL
EndOfListMarkerReadItem24 D5239 CHANNEL
EndOfListMarkerReadItem25 D5249 CHANNEL
EndOfListMarkerReadItem26 D5259 CHANNEL
EndOfListMarkerReadItem27 D5269 CHANNEL
EndOfListMarkerReadItem28 D5279 CHANNEL
EndOfListMarkerReadItem29 D5289 CHANNEL
EndOfListMarkerReadItem3 D5029 CHANNEL
EndOfListMarkerReadItem30 D5299 CHANNEL
EndOfListMarkerReadItem31 D5309 CHANNEL
EndOfListMarkerReadItem32 D5319 CHANNEL
EndOfListMarkerReadItem33 D5329 CHANNEL
EndOfListMarkerReadItem34 D5339 CHANNEL
EndOfListMarkerReadItem35 D5349 CHANNEL
EndOfListMarkerReadItem36 D5359 CHANNEL
EndOfListMarkerReadItem37 D5369 CHANNEL
EndOfListMarkerReadItem38 D5379 CHANNEL
EndOfListMarkerReadItem39 D5389 CHANNEL
EndOfListMarkerReadItem4 D5039 CHANNEL
EndOfListMarkerReadItem40 D5399 CHANNEL
EndOfListMarkerReadItem41 D5409 CHANNEL
EndOfListMarkerReadItem42 D5419 CHANNEL
EndOfListMarkerReadItem43 D5429 CHANNEL
EndOfListMarkerReadItem44 D5439 CHANNEL
EndOfListMarkerReadItem45 D5449 CHANNEL
EndOfListMarkerReadItem46 D5459 CHANNEL
EndOfListMarkerReadItem47 D5469 CHANNEL
EndOfListMarkerReadItem48 D5479 CHANNEL
EndOfListMarkerReadItem49 D5489 CHANNEL
EndOfListMarkerReadItem5 D5049 CHANNEL
EndOfListMarkerReadItem50 D5499 CHANNEL
EndOfListMarkerReadItem51 D5509 CHANNEL
EndOfListMarkerReadItem52 D5519 CHANNEL
EndOfListMarkerReadItem53 D5529 CHANNEL
EndOfListMarkerReadItem54 D5539 CHANNEL
EndOfListMarkerReadItem55 D5549 CHANNEL
EndOfListMarkerReadItem56 D5559 CHANNEL
EndOfListMarkerReadItem57 D5569 CHANNEL
EndOfListMarkerReadItem58 D5579 CHANNEL
EndOfListMarkerReadItem59 D5589 CHANNEL
EndOfListMarkerReadItem6 D5059 CHANNEL
EndOfListMarkerReadItem60 D5599 CHANNEL
EndOfListMarkerReadItem61 D5609 CHANNEL
EndOfListMarkerReadItem62 D5619 CHANNEL
EndOfListMarkerReadItem63 D5629 CHANNEL
EndOfListMarkerReadItem64 D5639 CHANNEL
EndOfListMarkerReadItem65 D5649 CHANNEL
EndOfListMarkerReadItem66 D5659 CHANNEL
EndOfListMarkerReadItem67 D5669 CHANNEL
EndOfListMarkerReadItem68 D5679 CHANNEL
EndOfListMarkerReadItem69 D5689 CHANNEL
EndOfListMarkerReadItem7 D5069 CHANNEL
EndOfListMarkerReadItem70 D5699 CHANNEL
EndOfListMarkerReadItem71 D5709 CHANNEL
EndOfListMarkerReadItem72 D5719 CHANNEL
EndOfListMarkerReadItem73 D5729 CHANNEL
EndOfListMarkerReadItem74 D5739 CHANNEL
EndOfListMarkerReadItem75 D5749 CHANNEL
EndOfListMarkerReadItem76 D5759 CHANNEL
EndOfListMarkerReadItem77 D5769 CHANNEL
EndOfListMarkerReadItem78 D5779 CHANNEL
EndOfListMarkerReadItem79 D5789 CHANNEL
EndOfListMarkerReadItem8 D5079 CHANNEL
EndOfListMarkerReadItem80 D5799 CHANNEL
EndOfListMarkerReadItem81 D5809 CHANNEL
EndOfListMarkerReadItem82 D5819 CHANNEL
EndOfListMarkerReadItem83 D5829 CHANNEL
EndOfListMarkerReadItem84 D5839 CHANNEL
EndOfListMarkerReadItem85 D5849 CHANNEL
EndOfListMarkerReadItem86 D5859 CHANNEL
EndOfListMarkerReadItem87 D5869 CHANNEL
EndOfListMarkerReadItem88 D5879 CHANNEL
EndOfListMarkerReadItem89 D5889 CHANNEL
EndOfListMarkerReadItem9 D5089 CHANNEL
EndOfListMarkerReadItem90 D5899 CHANNEL
EndOfListMarkerReadItem91 D5909 CHANNEL
EndOfListMarkerReadItem92 D5919 CHANNEL
EndOfListMarkerReadItem93 D5929 CHANNEL
EndOfListMarkerReadItem94 D5939 CHANNEL
EndOfListMarkerReadItem95 D5949 CHANNEL
EndOfListMarkerReadItem96 D5959 CHANNEL
EndOfListMarkerReadItem97 D5969 CHANNEL
EndOfListMarkerReadItem98 D5979 CHANNEL
EndOfListMarkerReadItem99 D5989 CHANNEL
EndOfListMarkerWriteItem1 D6009 CHANNEL
EndOfListMarkerWriteItem10 D6099 CHANNEL
EndOfListMarkerWriteItem100 D6999 CHANNEL
EndOfListMarkerWriteItem11 D6109 CHANNEL
EndOfListMarkerWriteItem12 D6119 CHANNEL
EndOfListMarkerWriteItem13 D6129 CHANNEL
EndOfListMarkerWriteItem14 D6139 CHANNEL
EndOfListMarkerWriteItem15 D6149 CHANNEL
EndOfListMarkerWriteItem16 D6159 CHANNEL
EndOfListMarkerWriteItem17 D6169 CHANNEL
EndOfListMarkerWriteItem18 D6179 CHANNEL
EndOfListMarkerWriteItem19 D6189 CHANNEL
EndOfListMarkerWriteItem2 D6019 CHANNEL
EndOfListMarkerWriteItem20 D6199 CHANNEL
EndOfListMarkerWriteItem21 D6209 CHANNEL
EndOfListMarkerWriteItem22 D6219 CHANNEL
EndOfListMarkerWriteItem23 D6229 CHANNEL
EndOfListMarkerWriteItem24 D6239 CHANNEL
EndOfListMarkerWriteItem25 D6249 CHANNEL
EndOfListMarkerWriteItem26 D6259 CHANNEL
EndOfListMarkerWriteItem27 D6269 CHANNEL
EndOfListMarkerWriteItem28 D6279 CHANNEL
EndOfListMarkerWriteItem29 D6289 CHANNEL
EndOfListMarkerWriteItem3 D6029 CHANNEL
EndOfListMarkerWriteItem30 D6299 CHANNEL
EndOfListMarkerWriteItem31 D6309 CHANNEL
EndOfListMarkerWriteItem32 D6319 CHANNEL
EndOfListMarkerWriteItem33 D6329 CHANNEL
EndOfListMarkerWriteItem34 D6339 CHANNEL
EndOfListMarkerWriteItem35 D6349 CHANNEL
EndOfListMarkerWriteItem36 D6359 CHANNEL
EndOfListMarkerWriteItem37 D6369 CHANNEL
EndOfListMarkerWriteItem38 D6379 CHANNEL
EndOfListMarkerWriteItem39 D6389 CHANNEL
EndOfListMarkerWriteItem4 D6039 CHANNEL
EndOfListMarkerWriteItem40 D6399 CHANNEL
EndOfListMarkerWriteItem41 D6409 CHANNEL
EndOfListMarkerWriteItem42 D6419 CHANNEL
EndOfListMarkerWriteItem43 D6429 CHANNEL
EndOfListMarkerWriteItem44 D6439 CHANNEL
EndOfListMarkerWriteItem45 D6449 CHANNEL
EndOfListMarkerWriteItem46 D6459 CHANNEL
EndOfListMarkerWriteItem47 D6469 CHANNEL
EndOfListMarkerWriteItem48 D6479 CHANNEL
EndOfListMarkerWriteItem49 D6489 CHANNEL
EndOfListMarkerWriteItem5 D6049 CHANNEL
EndOfListMarkerWriteItem50 D6499 CHANNEL
EndOfListMarkerWriteItem51 D6509 CHANNEL
EndOfListMarkerWriteItem52 D6519 CHANNEL
EndOfListMarkerWriteItem53 D6529 CHANNEL
EndOfListMarkerWriteItem54 D6539 CHANNEL
EndOfListMarkerWriteItem55 D6549 CHANNEL
EndOfListMarkerWriteItem56 D6559 CHANNEL
EndOfListMarkerWriteItem57 D6569 CHANNEL
EndOfListMarkerWriteItem58 D6579 CHANNEL
EndOfListMarkerWriteItem59 D6589 CHANNEL
EndOfListMarkerWriteItem6 D6059 CHANNEL
EndOfListMarkerWriteItem60 D6599 CHANNEL
EndOfListMarkerWriteItem61 D6609 CHANNEL
EndOfListMarkerWriteItem62 D6619 CHANNEL
EndOfListMarkerWriteItem63 D6629 CHANNEL
EndOfListMarkerWriteItem64 D6639 CHANNEL
EndOfListMarkerWriteItem65 D6649 CHANNEL
EndOfListMarkerWriteItem66 D6659 CHANNEL
EndOfListMarkerWriteItem67 D6669 CHANNEL
EndOfListMarkerWriteItem68 D6679 CHANNEL
EndOfListMarkerWriteItem69 D6689 CHANNEL
EndOfListMarkerWriteItem7 D6069 CHANNEL
EndOfListMarkerWriteItem70 D6699 CHANNEL
EndOfListMarkerWriteItem71 D6709 CHANNEL
EndOfListMarkerWriteItem72 D6719 CHANNEL
EndOfListMarkerWriteItem73 D6729 CHANNEL
EndOfListMarkerWriteItem74 D6739 CHANNEL
EndOfListMarkerWriteItem75 D6749 CHANNEL
EndOfListMarkerWriteItem76 D6759 CHANNEL
EndOfListMarkerWriteItem77 D6769 CHANNEL
EndOfListMarkerWriteItem78 D6779 CHANNEL
EndOfListMarkerWriteItem79 D6789 CHANNEL
EndOfListMarkerWriteItem8 D6079 CHANNEL
EndOfListMarkerWriteItem80 D6799 CHANNEL
EndOfListMarkerWriteItem81 D6809 CHANNEL
EndOfListMarkerWriteItem82 D6819 CHANNEL
EndOfListMarkerWriteItem83 D6829 CHANNEL
EndOfListMarkerWriteItem84 D6839 CHANNEL
EndOfListMarkerWriteItem85 D6849 CHANNEL
EndOfListMarkerWriteItem86 D6859 CHANNEL
EndOfListMarkerWriteItem87 D6869 CHANNEL
EndOfListMarkerWriteItem88 D6879 CHANNEL
EndOfListMarkerWriteItem89 D6889 CHANNEL
EndOfListMarkerWriteItem9 D6089 CHANNEL
EndOfListMarkerWriteItem90 D6899 CHANNEL
EndOfListMarkerWriteItem91 D6909 CHANNEL
EndOfListMarkerWriteItem92 D6919 CHANNEL
EndOfListMarkerWriteItem93 D6929 CHANNEL
EndOfListMarkerWriteItem94 D6939 CHANNEL
EndOfListMarkerWriteItem95 D6949 CHANNEL
EndOfListMarkerWriteItem96 D6959 CHANNEL
EndOfListMarkerWriteItem97 D6969 CHANNEL
EndOfListMarkerWriteItem98 D6979 CHANNEL
EndOfListMarkerWriteItem99 D6989 CHANNEL
FirstWordResponseDataReadItem1 D5004 CHANNEL
FirstWordResponseDataReadItem10 D5094 CHANNEL
FirstWordResponseDataReadItem100 D5994 CHANNEL
FirstWordResponseDataReadItem11 D5104 CHANNEL
FirstWordResponseDataReadItem12 D5114 CHANNEL
FirstWordResponseDataReadItem13 D5124 CHANNEL
FirstWordResponseDataReadItem14 D5134 CHANNEL
FirstWordResponseDataReadItem15 D5144 CHANNEL
FirstWordResponseDataReadItem16 D5154 CHANNEL
FirstWordResponseDataReadItem17 D5164 CHANNEL
FirstWordResponseDataReadItem18 D5174 CHANNEL
FirstWordResponseDataReadItem19 D5184 CHANNEL
FirstWordResponseDataReadItem2 D5014 CHANNEL
FirstWordResponseDataReadItem20 D5194 CHANNEL
FirstWordResponseDataReadItem21 D5204 CHANNEL
FirstWordResponseDataReadItem22 D5214 CHANNEL
FirstWordResponseDataReadItem23 D5224 CHANNEL
FirstWordResponseDataReadItem24 D5234 CHANNEL
FirstWordResponseDataReadItem25 D5244 CHANNEL
FirstWordResponseDataReadItem26 D5254 CHANNEL
FirstWordResponseDataReadItem27 D5264 CHANNEL
FirstWordResponseDataReadItem28 D5274 CHANNEL
FirstWordResponseDataReadItem29 D5284 CHANNEL
FirstWordResponseDataReadItem3 D5024 CHANNEL
FirstWordResponseDataReadItem30 D5294 CHANNEL
FirstWordResponseDataReadItem31 D5304 CHANNEL
FirstWordResponseDataReadItem32 D5314 CHANNEL
FirstWordResponseDataReadItem33 D5324 CHANNEL
FirstWordResponseDataReadItem34 D5334 CHANNEL
FirstWordResponseDataReadItem35 D5344 CHANNEL
FirstWordResponseDataReadItem36 D5354 CHANNEL
FirstWordResponseDataReadItem37 D5364 CHANNEL
FirstWordResponseDataReadItem38 D5374 CHANNEL
FirstWordResponseDataReadItem39 D5384 CHANNEL
FirstWordResponseDataReadItem4 D5034 CHANNEL
FirstWordResponseDataReadItem40 D5394 CHANNEL
FirstWordResponseDataReadItem41 D5404 CHANNEL
FirstWordResponseDataReadItem42 D5414 CHANNEL
FirstWordResponseDataReadItem43 D5424 CHANNEL
FirstWordResponseDataReadItem44 D5434 CHANNEL
FirstWordResponseDataReadItem45 D5444 CHANNEL
FirstWordResponseDataReadItem46 D5454 CHANNEL
FirstWordResponseDataReadItem47 D5464 CHANNEL
FirstWordResponseDataReadItem48 D5474 CHANNEL
FirstWordResponseDataReadItem49 D5484 CHANNEL
FirstWordResponseDataReadItem5 D5044 CHANNEL
FirstWordResponseDataReadItem50 D5494 CHANNEL
FirstWordResponseDataReadItem51 D5504 CHANNEL
FirstWordResponseDataReadItem52 D5514 CHANNEL
FirstWordResponseDataReadItem53 D5524 CHANNEL
FirstWordResponseDataReadItem54 D5534 CHANNEL
FirstWordResponseDataReadItem55 D5544 CHANNEL
FirstWordResponseDataReadItem56 D5554 CHANNEL
FirstWordResponseDataReadItem57 D5564 CHANNEL
FirstWordResponseDataReadItem58 D5574 CHANNEL
FirstWordResponseDataReadItem59 D5584 CHANNEL
FirstWordResponseDataReadItem6 D5054 CHANNEL
FirstWordResponseDataReadItem60 D5594 CHANNEL
FirstWordResponseDataReadItem61 D5604 CHANNEL
FirstWordResponseDataReadItem62 D5614 CHANNEL
FirstWordResponseDataReadItem63 D5624 CHANNEL
FirstWordResponseDataReadItem64 D5634 CHANNEL
FirstWordResponseDataReadItem65 D5644 CHANNEL
FirstWordResponseDataReadItem66 D5654 CHANNEL
FirstWordResponseDataReadItem67 D5664 CHANNEL
FirstWordResponseDataReadItem68 D5674 CHANNEL
FirstWordResponseDataReadItem69 D5684 CHANNEL
FirstWordResponseDataReadItem7 D5064 CHANNEL
FirstWordResponseDataReadItem70 D5694 CHANNEL
FirstWordResponseDataReadItem71 D5704 CHANNEL
FirstWordResponseDataReadItem72 D5714 CHANNEL
FirstWordResponseDataReadItem73 D5724 CHANNEL
FirstWordResponseDataReadItem74 D5734 CHANNEL
FirstWordResponseDataReadItem75 D5744 CHANNEL
FirstWordResponseDataReadItem76 D5754 CHANNEL
FirstWordResponseDataReadItem77 D5764 CHANNEL
FirstWordResponseDataReadItem78 D5774 CHANNEL
FirstWordResponseDataReadItem79 D5784 CHANNEL
FirstWordResponseDataReadItem8 D5074 CHANNEL
FirstWordResponseDataReadItem80 D5794 CHANNEL
FirstWordResponseDataReadItem81 D5804 CHANNEL
FirstWordResponseDataReadItem82 D5814 CHANNEL
FirstWordResponseDataReadItem83 D5824 CHANNEL
FirstWordResponseDataReadItem84 D5834 CHANNEL
FirstWordResponseDataReadItem85 D5844 CHANNEL
FirstWordResponseDataReadItem86 D5854 CHANNEL
FirstWordResponseDataReadItem87 D5864 CHANNEL
FirstWordResponseDataReadItem88 D5874 CHANNEL
FirstWordResponseDataReadItem89 D5884 CHANNEL
FirstWordResponseDataReadItem9 D5084 CHANNEL
FirstWordResponseDataReadItem90 D5894 CHANNEL
FirstWordResponseDataReadItem91 D5904 CHANNEL
FirstWordResponseDataReadItem92 D5914 CHANNEL
FirstWordResponseDataReadItem93 D5924 CHANNEL
FirstWordResponseDataReadItem94 D5934 CHANNEL
FirstWordResponseDataReadItem95 D5944 CHANNEL
FirstWordResponseDataReadItem96 D5954 CHANNEL
FirstWordResponseDataReadItem97 D5964 CHANNEL
FirstWordResponseDataReadItem98 D5974 CHANNEL
FirstWordResponseDataReadItem99 D5984 CHANNEL
FirstWordWriteDataMirrorWriteItem1 D6006 CHANNEL
FirstWordWriteDataMirrorWriteItem10 D6096 CHANNEL
FirstWordWriteDataMirrorWriteItem100 D6996 CHANNEL
FirstWordWriteDataMirrorWriteItem11 D6106 CHANNEL
FirstWordWriteDataMirrorWriteItem12 D6116 CHANNEL
FirstWordWriteDataMirrorWriteItem13 D6126 CHANNEL
FirstWordWriteDataMirrorWriteItem14 D6136 CHANNEL
FirstWordWriteDataMirrorWriteItem15 D6146 CHANNEL
FirstWordWriteDataMirrorWriteItem16 D6156 CHANNEL
FirstWordWriteDataMirrorWriteItem17 D6166 CHANNEL
FirstWordWriteDataMirrorWriteItem18 D6176 CHANNEL
FirstWordWriteDataMirrorWriteItem19 D6186 CHANNEL
FirstWordWriteDataMirrorWriteItem2 D6016 CHANNEL
FirstWordWriteDataMirrorWriteItem20 D6196 CHANNEL
FirstWordWriteDataMirrorWriteItem21 D6206 CHANNEL
FirstWordWriteDataMirrorWriteItem22 D6216 CHANNEL
FirstWordWriteDataMirrorWriteItem23 D6226 CHANNEL
FirstWordWriteDataMirrorWriteItem24 D6236 CHANNEL
FirstWordWriteDataMirrorWriteItem25 D6246 CHANNEL
FirstWordWriteDataMirrorWriteItem26 D6256 CHANNEL
FirstWordWriteDataMirrorWriteItem27 D6266 CHANNEL
FirstWordWriteDataMirrorWriteItem28 D6276 CHANNEL
FirstWordWriteDataMirrorWriteItem29 D6286 CHANNEL
FirstWordWriteDataMirrorWriteItem3 D6026 CHANNEL
FirstWordWriteDataMirrorWriteItem30 D6296 CHANNEL
FirstWordWriteDataMirrorWriteItem31 D6306 CHANNEL
FirstWordWriteDataMirrorWriteItem32 D6316 CHANNEL
FirstWordWriteDataMirrorWriteItem33 D6326 CHANNEL
FirstWordWriteDataMirrorWriteItem34 D6336 CHANNEL
FirstWordWriteDataMirrorWriteItem35 D6346 CHANNEL
FirstWordWriteDataMirrorWriteItem36 D6356 CHANNEL
FirstWordWriteDataMirrorWriteItem37 D6366 CHANNEL
FirstWordWriteDataMirrorWriteItem38 D6376 CHANNEL
FirstWordWriteDataMirrorWriteItem39 D6386 CHANNEL
FirstWordWriteDataMirrorWriteItem4 D6036 CHANNEL
FirstWordWriteDataMirrorWriteItem40 D6396 CHANNEL
FirstWordWriteDataMirrorWriteItem41 D6406 CHANNEL
FirstWordWriteDataMirrorWriteItem42 D6416 CHANNEL
FirstWordWriteDataMirrorWriteItem43 D6426 CHANNEL
FirstWordWriteDataMirrorWriteItem44 D6436 CHANNEL
FirstWordWriteDataMirrorWriteItem45 D6446 CHANNEL
FirstWordWriteDataMirrorWriteItem46 D6456 CHANNEL
FirstWordWriteDataMirrorWriteItem47 D6466 CHANNEL
FirstWordWriteDataMirrorWriteItem48 D6476 CHANNEL
FirstWordWriteDataMirrorWriteItem49 D6486 CHANNEL
FirstWordWriteDataMirrorWriteItem5 D6046 CHANNEL
FirstWordWriteDataMirrorWriteItem50 D6496 CHANNEL
FirstWordWriteDataMirrorWriteItem51 D6506 CHANNEL
FirstWordWriteDataMirrorWriteItem52 D6516 CHANNEL
FirstWordWriteDataMirrorWriteItem53 D6526 CHANNEL
FirstWordWriteDataMirrorWriteItem54 D6536 CHANNEL
FirstWordWriteDataMirrorWriteItem55 D6546 CHANNEL
FirstWordWriteDataMirrorWriteItem56 D6556 CHANNEL
FirstWordWriteDataMirrorWriteItem57 D6566 CHANNEL
FirstWordWriteDataMirrorWriteItem58 D6576 CHANNEL
FirstWordWriteDataMirrorWriteItem59 D6586 CHANNEL
FirstWordWriteDataMirrorWriteItem6 D6056 CHANNEL
FirstWordWriteDataMirrorWriteItem60 D6596 CHANNEL
FirstWordWriteDataMirrorWriteItem61 D6606 CHANNEL
FirstWordWriteDataMirrorWriteItem62 D6616 CHANNEL
FirstWordWriteDataMirrorWriteItem63 D6626 CHANNEL
FirstWordWriteDataMirrorWriteItem64 D6636 CHANNEL
FirstWordWriteDataMirrorWriteItem65 D6646 CHANNEL
FirstWordWriteDataMirrorWriteItem66 D6656 CHANNEL
FirstWordWriteDataMirrorWriteItem67 D6666 CHANNEL
FirstWordWriteDataMirrorWriteItem68 D6676 CHANNEL
FirstWordWriteDataMirrorWriteItem69 D6686 CHANNEL
FirstWordWriteDataMirrorWriteItem7 D6066 CHANNEL
FirstWordWriteDataMirrorWriteItem70 D6696 CHANNEL
FirstWordWriteDataMirrorWriteItem71 D6706 CHANNEL
FirstWordWriteDataMirrorWriteItem72 D6716 CHANNEL
FirstWordWriteDataMirrorWriteItem73 D6726 CHANNEL
FirstWordWriteDataMirrorWriteItem74 D6736 CHANNEL
FirstWordWriteDataMirrorWriteItem75 D6746 CHANNEL
FirstWordWriteDataMirrorWriteItem76 D6756 CHANNEL
FirstWordWriteDataMirrorWriteItem77 D6766 CHANNEL
FirstWordWriteDataMirrorWriteItem78 D6776 CHANNEL
FirstWordWriteDataMirrorWriteItem79 D6786 CHANNEL
FirstWordWriteDataMirrorWriteItem8 D6076 CHANNEL
FirstWordWriteDataMirrorWriteItem80 D6796 CHANNEL
FirstWordWriteDataMirrorWriteItem81 D6806 CHANNEL
FirstWordWriteDataMirrorWriteItem82 D6816 CHANNEL
FirstWordWriteDataMirrorWriteItem83 D6826 CHANNEL
FirstWordWriteDataMirrorWriteItem84 D6836 CHANNEL
FirstWordWriteDataMirrorWriteItem85 D6846 CHANNEL
FirstWordWriteDataMirrorWriteItem86 D6856 CHANNEL
FirstWordWriteDataMirrorWriteItem87 D6866 CHANNEL
FirstWordWriteDataMirrorWriteItem88 D6876 CHANNEL
FirstWordWriteDataMirrorWriteItem89 D6886 CHANNEL
FirstWordWriteDataMirrorWriteItem9 D6086 CHANNEL
FirstWordWriteDataMirrorWriteItem90 D6896 CHANNEL
FirstWordWriteDataMirrorWriteItem91 D6906 CHANNEL
FirstWordWriteDataMirrorWriteItem92 D6916 CHANNEL
FirstWordWriteDataMirrorWriteItem93 D6926 CHANNEL
FirstWordWriteDataMirrorWriteItem94 D6936 CHANNEL
FirstWordWriteDataMirrorWriteItem95 D6946 CHANNEL
FirstWordWriteDataMirrorWriteItem96 D6956 CHANNEL
FirstWordWriteDataMirrorWriteItem97 D6966 CHANNEL
FirstWordWriteDataMirrorWriteItem98 D6976 CHANNEL
FirstWordWriteDataMirrorWriteItem99 D6986 CHANNEL
FirstWordWriteDataWriteItem1 D6004 CHANNEL
FirstWordWriteDataWriteItem10 D6094 CHANNEL
FirstWordWriteDataWriteItem100 D6994 CHANNEL
FirstWordWriteDataWriteItem11 D6104 CHANNEL
FirstWordWriteDataWriteItem12 D6114 CHANNEL
FirstWordWriteDataWriteItem13 D6124 CHANNEL
FirstWordWriteDataWriteItem14 D6134 CHANNEL
FirstWordWriteDataWriteItem15 D6144 CHANNEL
FirstWordWriteDataWriteItem16 D6154 CHANNEL
FirstWordWriteDataWriteItem17 D6164 CHANNEL
FirstWordWriteDataWriteItem18 D6174 CHANNEL
FirstWordWriteDataWriteItem19 D6184 CHANNEL
FirstWordWriteDataWriteItem2 D6014 CHANNEL
FirstWordWriteDataWriteItem20 D6194 CHANNEL
FirstWordWriteDataWriteItem21 D6204 CHANNEL
FirstWordWriteDataWriteItem22 D6214 CHANNEL
FirstWordWriteDataWriteItem23 D6224 CHANNEL
FirstWordWriteDataWriteItem24 D6234 CHANNEL
FirstWordWriteDataWriteItem25 D6244 CHANNEL
FirstWordWriteDataWriteItem26 D6254 CHANNEL
FirstWordWriteDataWriteItem27 D6264 CHANNEL
FirstWordWriteDataWriteItem28 D6274 CHANNEL
FirstWordWriteDataWriteItem29 D6284 CHANNEL
FirstWordWriteDataWriteItem3 D6024 CHANNEL
FirstWordWriteDataWriteItem30 D6294 CHANNEL
FirstWordWriteDataWriteItem31 D6304 CHANNEL
FirstWordWriteDataWriteItem32 D6314 CHANNEL
FirstWordWriteDataWriteItem33 D6324 CHANNEL
FirstWordWriteDataWriteItem34 D6334 CHANNEL
FirstWordWriteDataWriteItem35 D6344 CHANNEL
FirstWordWriteDataWriteItem36 D6354 CHANNEL
FirstWordWriteDataWriteItem37 D6364 CHANNEL
FirstWordWriteDataWriteItem38 D6374 CHANNEL
FirstWordWriteDataWriteItem39 D6384 CHANNEL
FirstWordWriteDataWriteItem4 D6034 CHANNEL
FirstWordWriteDataWriteItem40 D6394 CHANNEL
FirstWordWriteDataWriteItem41 D6404 CHANNEL
FirstWordWriteDataWriteItem42 D6414 CHANNEL
FirstWordWriteDataWriteItem43 D6424 CHANNEL
FirstWordWriteDataWriteItem44 D6434 CHANNEL
FirstWordWriteDataWriteItem45 D6444 CHANNEL
FirstWordWriteDataWriteItem46 D6454 CHANNEL
FirstWordWriteDataWriteItem47 D6464 CHANNEL
FirstWordWriteDataWriteItem48 D6474 CHANNEL
FirstWordWriteDataWriteItem49 D6484 CHANNEL
FirstWordWriteDataWriteItem5 D6044 CHANNEL
FirstWordWriteDataWriteItem50 D6494 CHANNEL
FirstWordWriteDataWriteItem51 D6504 CHANNEL
FirstWordWriteDataWriteItem52 D6514 CHANNEL
FirstWordWriteDataWriteItem53 D6524 CHANNEL
FirstWordWriteDataWriteItem54 D6534 CHANNEL
FirstWordWriteDataWriteItem55 D6544 CHANNEL
FirstWordWriteDataWriteItem56 D6554 CHANNEL
FirstWordWriteDataWriteItem57 D6564 CHANNEL
FirstWordWriteDataWriteItem58 D6574 CHANNEL
FirstWordWriteDataWriteItem59 D6584 CHANNEL
FirstWordWriteDataWriteItem6 D6054 CHANNEL
FirstWordWriteDataWriteItem60 D6594 CHANNEL
FirstWordWriteDataWriteItem61 D6604 CHANNEL
FirstWordWriteDataWriteItem62 D6614 CHANNEL
FirstWordWriteDataWriteItem63 D6624 CHANNEL
FirstWordWriteDataWriteItem64 D6634 CHANNEL
FirstWordWriteDataWriteItem65 D6644 CHANNEL
FirstWordWriteDataWriteItem66 D6654 CHANNEL
FirstWordWriteDataWriteItem67 D6664 CHANNEL
FirstWordWriteDataWriteItem68 D6674 CHANNEL
FirstWordWriteDataWriteItem69 D6684 CHANNEL
FirstWordWriteDataWriteItem7 D6064 CHANNEL
FirstWordWriteDataWriteItem70 D6694 CHANNEL
FirstWordWriteDataWriteItem71 D6704 CHANNEL
FirstWordWriteDataWriteItem72 D6714 CHANNEL
FirstWordWriteDataWriteItem73 D6724 CHANNEL
FirstWordWriteDataWriteItem74 D6734 CHANNEL
FirstWordWriteDataWriteItem75 D6744 CHANNEL
FirstWordWriteDataWriteItem76 D6754 CHANNEL
FirstWordWriteDataWriteItem77 D6764 CHANNEL
FirstWordWriteDataWriteItem78 D6774 CHANNEL
FirstWordWriteDataWriteItem79 D6784 CHANNEL
FirstWordWriteDataWriteItem8 D6074 CHANNEL
FirstWordWriteDataWriteItem80 D6794 CHANNEL
FirstWordWriteDataWriteItem81 D6804 CHANNEL
FirstWordWriteDataWriteItem82 D6814 CHANNEL
FirstWordWriteDataWriteItem83 D6824 CHANNEL
FirstWordWriteDataWriteItem84 D6834 CHANNEL
FirstWordWriteDataWriteItem85 D6844 CHANNEL
FirstWordWriteDataWriteItem86 D6854 CHANNEL
FirstWordWriteDataWriteItem87 D6864 CHANNEL
FirstWordWriteDataWriteItem88 D6874 CHANNEL
FirstWordWriteDataWriteItem89 D6884 CHANNEL
FirstWordWriteDataWriteItem9 D6084 CHANNEL
FirstWordWriteDataWriteItem90 D6894 CHANNEL
FirstWordWriteDataWriteItem91 D6904 CHANNEL
FirstWordWriteDataWriteItem92 D6914 CHANNEL
FirstWordWriteDataWriteItem93 D6924 CHANNEL
FirstWordWriteDataWriteItem94 D6934 CHANNEL
FirstWordWriteDataWriteItem95 D6944 CHANNEL
FirstWordWriteDataWriteItem96 D6954 CHANNEL
FirstWordWriteDataWriteItem97 D6964 CHANNEL
FirstWordWriteDataWriteItem98 D6974 CHANNEL
FirstWordWriteDataWriteItem99 D6984 CHANNEL
LastModbusCommandReceived1 W240 CHANNEL
LastModbusCommandReceived10 W249 CHANNEL
LastModbusCommandReceived2 W241 CHANNEL
LastModbusCommandReceived3 W242 CHANNEL
LastModbusCommandReceived4 W243 CHANNEL
LastModbusCommandReceived5 W244 CHANNEL
LastModbusCommandReceived6 W245 CHANNEL
LastModbusCommandReceived7 W246 CHANNEL
LastModbusCommandReceived8 W247 CHANNEL
LastModbusCommandReceived9 W248 CHANNEL
LastModbusCommandSent1 W230 CHANNEL
LastModbusCommandSent10 W239 CHANNEL
LastModbusCommandSent2 W231 CHANNEL
LastModbusCommandSent3 W232 CHANNEL
LastModbusCommandSent4 W233 CHANNEL
LastModbusCommandSent5 W234 CHANNEL
LastModbusCommandSent6 W235 CHANNEL
LastModbusCommandSent7 W236 CHANNEL
LastModbusCommandSent8 W237 CHANNEL
LastModbusCommandSent9 W238 CHANNEL
LogAnEasyModbusError W215.00 BOOL
ModbusErrorDMAddress1 W221 CHANNEL
ModbusErrorDMAddress2 W223 CHANNEL
ModbusErrorDMAddress3 W225 CHANNEL
ModbusErrorDMAddress4 W227 CHANNEL
ModbusErrorDMAddress5 W229 CHANNEL
ModbusErrorNodeFunction1 W220 CHANNEL
ModbusErrorNodeFunction2 W222 CHANNEL
ModbusErrorNodeFunction3 W224 CHANNEL
ModbusErrorNodeFunction4 W226 CHANNEL
ModbusErrorNodeFunction5 W228 CHANNEL
ModbusFunctionCodeReadItem1 D5001 CHANNEL
ModbusFunctionCodeReadItem10 D5091 CHANNEL
ModbusFunctionCodeReadItem100 D5991 CHANNEL
ModbusFunctionCodeReadItem11 D5101 CHANNEL
ModbusFunctionCodeReadItem12 D5111 CHANNEL
ModbusFunctionCodeReadItem13 D5121 CHANNEL
ModbusFunctionCodeReadItem14 D5131 CHANNEL
ModbusFunctionCodeReadItem15 D5141 CHANNEL
ModbusFunctionCodeReadItem16 D5151 CHANNEL
ModbusFunctionCodeReadItem17 D5161 CHANNEL
ModbusFunctionCodeReadItem18 D5171 CHANNEL
ModbusFunctionCodeReadItem19 D5181 CHANNEL
ModbusFunctionCodeReadItem2 D5011 CHANNEL
ModbusFunctionCodeReadItem20 D5191 CHANNEL
ModbusFunctionCodeReadItem21 D5201 CHANNEL
ModbusFunctionCodeReadItem22 D5211 CHANNEL
ModbusFunctionCodeReadItem23 D5221 CHANNEL
ModbusFunctionCodeReadItem24 D5231 CHANNEL
ModbusFunctionCodeReadItem25 D5241 CHANNEL
ModbusFunctionCodeReadItem26 D5251 CHANNEL
ModbusFunctionCodeReadItem27 D5261 CHANNEL
ModbusFunctionCodeReadItem28 D5271 CHANNEL
ModbusFunctionCodeReadItem29 D5281 CHANNEL
ModbusFunctionCodeReadItem3 D5021 CHANNEL
ModbusFunctionCodeReadItem30 D5291 CHANNEL
ModbusFunctionCodeReadItem31 D5301 CHANNEL
ModbusFunctionCodeReadItem32 D5311 CHANNEL
ModbusFunctionCodeReadItem33 D5321 CHANNEL
ModbusFunctionCodeReadItem34 D5331 CHANNEL
ModbusFunctionCodeReadItem35 D5341 CHANNEL
ModbusFunctionCodeReadItem36 D5351 CHANNEL
ModbusFunctionCodeReadItem37 D5361 CHANNEL
ModbusFunctionCodeReadItem38 D5371 CHANNEL
ModbusFunctionCodeReadItem39 D5381 CHANNEL
ModbusFunctionCodeReadItem4 D5031 CHANNEL
ModbusFunctionCodeReadItem40 D5391 CHANNEL
ModbusFunctionCodeReadItem41 D5401 CHANNEL
ModbusFunctionCodeReadItem42 D5411 CHANNEL
ModbusFunctionCodeReadItem43 D5421 CHANNEL
ModbusFunctionCodeReadItem44 D5431 CHANNEL
ModbusFunctionCodeReadItem45 D5441 CHANNEL
ModbusFunctionCodeReadItem46 D5451 CHANNEL
ModbusFunctionCodeReadItem47 D5461 CHANNEL
ModbusFunctionCodeReadItem48 D5471 CHANNEL
ModbusFunctionCodeReadItem49 D5481 CHANNEL
ModbusFunctionCodeReadItem5 D5041 CHANNEL
ModbusFunctionCodeReadItem50 D5491 CHANNEL
ModbusFunctionCodeReadItem51 D5501 CHANNEL
ModbusFunctionCodeReadItem52 D5511 CHANNEL
ModbusFunctionCodeReadItem53 D5521 CHANNEL
ModbusFunctionCodeReadItem54 D5531 CHANNEL
ModbusFunctionCodeReadItem55 D5541 CHANNEL
ModbusFunctionCodeReadItem56 D5551 CHANNEL
ModbusFunctionCodeReadItem57 D5561 CHANNEL
ModbusFunctionCodeReadItem58 D5571 CHANNEL
ModbusFunctionCodeReadItem59 D5581 CHANNEL
ModbusFunctionCodeReadItem6 D5051 CHANNEL
ModbusFunctionCodeReadItem60 D5591 CHANNEL
ModbusFunctionCodeReadItem61 D5601 CHANNEL
ModbusFunctionCodeReadItem62 D5611 CHANNEL
ModbusFunctionCodeReadItem63 D5621 CHANNEL
ModbusFunctionCodeReadItem64 D5631 CHANNEL
ModbusFunctionCodeReadItem65 D5641 CHANNEL
ModbusFunctionCodeReadItem66 D5651 CHANNEL
ModbusFunctionCodeReadItem67 D5661 CHANNEL
ModbusFunctionCodeReadItem68 D5671 CHANNEL
ModbusFunctionCodeReadItem69 D5681 CHANNEL
ModbusFunctionCodeReadItem7 D5061 CHANNEL
ModbusFunctionCodeReadItem70 D5691 CHANNEL
ModbusFunctionCodeReadItem71 D5701 CHANNEL
ModbusFunctionCodeReadItem72 D5711 CHANNEL
ModbusFunctionCodeReadItem73 D5721 CHANNEL
ModbusFunctionCodeReadItem74 D5731 CHANNEL
ModbusFunctionCodeReadItem75 D5741 CHANNEL
ModbusFunctionCodeReadItem76 D5751 CHANNEL
ModbusFunctionCodeReadItem77 D5761 CHANNEL
ModbusFunctionCodeReadItem78 D5771 CHANNEL
ModbusFunctionCodeReadItem79 D5781 CHANNEL
ModbusFunctionCodeReadItem8 D5071 CHANNEL
ModbusFunctionCodeReadItem80 D5791 CHANNEL
ModbusFunctionCodeReadItem81 D5801 CHANNEL
ModbusFunctionCodeReadItem82 D5811 CHANNEL
ModbusFunctionCodeReadItem83 D5821 CHANNEL
ModbusFunctionCodeReadItem84 D5831 CHANNEL
ModbusFunctionCodeReadItem85 D5841 CHANNEL
ModbusFunctionCodeReadItem86 D5851 CHANNEL
ModbusFunctionCodeReadItem87 D5861 CHANNEL
ModbusFunctionCodeReadItem88 D5871 CHANNEL
ModbusFunctionCodeReadItem89 D5881 CHANNEL
ModbusFunctionCodeReadItem9 D5081 CHANNEL
ModbusFunctionCodeReadItem90 D5891 CHANNEL
ModbusFunctionCodeReadItem91 D5901 CHANNEL
ModbusFunctionCodeReadItem92 D5911 CHANNEL
ModbusFunctionCodeReadItem93 D5921 CHANNEL
ModbusFunctionCodeReadItem94 D5931 CHANNEL
ModbusFunctionCodeReadItem95 D5941 CHANNEL
ModbusFunctionCodeReadItem96 D5951 CHANNEL
ModbusFunctionCodeReadItem97 D5961 CHANNEL
ModbusFunctionCodeReadItem98 D5971 CHANNEL
ModbusFunctionCodeReadItem99 D5981 CHANNEL
ModbusFunctionCodeWriteItem1 D6001 CHANNEL
ModbusFunctionCodeWriteItem10 D6091 CHANNEL
ModbusFunctionCodeWriteItem100 D6991 CHANNEL
ModbusFunctionCodeWriteItem11 D6101 CHANNEL
ModbusFunctionCodeWriteItem12 D6111 CHANNEL
ModbusFunctionCodeWriteItem13 D6121 CHANNEL
ModbusFunctionCodeWriteItem14 D6131 CHANNEL
ModbusFunctionCodeWriteItem15 D6141 CHANNEL
ModbusFunctionCodeWriteItem16 D6151 CHANNEL
ModbusFunctionCodeWriteItem17 D6161 CHANNEL
ModbusFunctionCodeWriteItem18 D6171 CHANNEL
ModbusFunctionCodeWriteItem19 D6181 CHANNEL
ModbusFunctionCodeWriteItem2 D6011 CHANNEL
ModbusFunctionCodeWriteItem20 D6191 CHANNEL
ModbusFunctionCodeWriteItem21 D6201 CHANNEL
ModbusFunctionCodeWriteItem22 D6211 CHANNEL
ModbusFunctionCodeWriteItem23 D6221 CHANNEL
ModbusFunctionCodeWriteItem24 D6231 CHANNEL
ModbusFunctionCodeWriteItem25 D6241 CHANNEL
ModbusFunctionCodeWriteItem26 D6251 CHANNEL
ModbusFunctionCodeWriteItem27 D6261 CHANNEL
ModbusFunctionCodeWriteItem28 D6271 CHANNEL
ModbusFunctionCodeWriteItem29 D6281 CHANNEL
ModbusFunctionCodeWriteItem3 D6021 CHANNEL
ModbusFunctionCodeWriteItem30 D6291 CHANNEL
ModbusFunctionCodeWriteItem31 D6301 CHANNEL
ModbusFunctionCodeWriteItem32 D6311 CHANNEL
ModbusFunctionCodeWriteItem33 D6321 CHANNEL
ModbusFunctionCodeWriteItem34 D6331 CHANNEL
ModbusFunctionCodeWriteItem35 D6341 CHANNEL
ModbusFunctionCodeWriteItem36 D6351 CHANNEL
ModbusFunctionCodeWriteItem37 D6361 CHANNEL
ModbusFunctionCodeWriteItem38 D6371 CHANNEL
ModbusFunctionCodeWriteItem39 D6381 CHANNEL
ModbusFunctionCodeWriteItem4 D6031 CHANNEL
ModbusFunctionCodeWriteItem40 D6391 CHANNEL
ModbusFunctionCodeWriteItem41 D6401 CHANNEL
ModbusFunctionCodeWriteItem42 D6411 CHANNEL
ModbusFunctionCodeWriteItem43 D6421 CHANNEL
ModbusFunctionCodeWriteItem44 D6431 CHANNEL
ModbusFunctionCodeWriteItem45 D6441 CHANNEL
ModbusFunctionCodeWriteItem46 D6451 CHANNEL
ModbusFunctionCodeWriteItem47 D6461 CHANNEL
ModbusFunctionCodeWriteItem48 D6471 CHANNEL
ModbusFunctionCodeWriteItem49 D6481 CHANNEL
ModbusFunctionCodeWriteItem5 D6041 CHANNEL
ModbusFunctionCodeWriteItem50 D6491 CHANNEL
ModbusFunctionCodeWriteItem51 D6501 CHANNEL
ModbusFunctionCodeWriteItem52 D6511 CHANNEL
ModbusFunctionCodeWriteItem53 D6521 CHANNEL
ModbusFunctionCodeWriteItem54 D6531 CHANNEL
ModbusFunctionCodeWriteItem55 D6541 CHANNEL
ModbusFunctionCodeWriteItem56 D6551 CHANNEL
ModbusFunctionCodeWriteItem57 D6561 CHANNEL
ModbusFunctionCodeWriteItem58 D6571 CHANNEL
ModbusFunctionCodeWriteItem59 D6581 CHANNEL
ModbusFunctionCodeWriteItem6 D6051 CHANNEL
ModbusFunctionCodeWriteItem60 D6591 CHANNEL
ModbusFunctionCodeWriteItem61 D6601 CHANNEL
ModbusFunctionCodeWriteItem62 D6611 CHANNEL
ModbusFunctionCodeWriteItem63 D6621 CHANNEL
ModbusFunctionCodeWriteItem64 D6631 CHANNEL
ModbusFunctionCodeWriteItem65 D6641 CHANNEL
ModbusFunctionCodeWriteItem66 D6651 CHANNEL
ModbusFunctionCodeWriteItem67 D6661 CHANNEL
ModbusFunctionCodeWriteItem68 D6671 CHANNEL
ModbusFunctionCodeWriteItem69 D6681 CHANNEL
ModbusFunctionCodeWriteItem7 D6061 CHANNEL
ModbusFunctionCodeWriteItem70 D6691 CHANNEL
ModbusFunctionCodeWriteItem71 D6701 CHANNEL
ModbusFunctionCodeWriteItem72 D6711 CHANNEL
ModbusFunctionCodeWriteItem73 D6721 CHANNEL
ModbusFunctionCodeWriteItem74 D6731 CHANNEL
ModbusFunctionCodeWriteItem75 D6741 CHANNEL
ModbusFunctionCodeWriteItem76 D6751 CHANNEL
ModbusFunctionCodeWriteItem77 D6761 CHANNEL
ModbusFunctionCodeWriteItem78 D6771 CHANNEL
ModbusFunctionCodeWriteItem79 D6781 CHANNEL
ModbusFunctionCodeWriteItem8 D6071 CHANNEL
ModbusFunctionCodeWriteItem80 D6791 CHANNEL
ModbusFunctionCodeWriteItem81 D6801 CHANNEL
ModbusFunctionCodeWriteItem82 D6811 CHANNEL
ModbusFunctionCodeWriteItem83 D6821 CHANNEL
ModbusFunctionCodeWriteItem84 D6831 CHANNEL
ModbusFunctionCodeWriteItem85 D6841 CHANNEL
ModbusFunctionCodeWriteItem86 D6851 CHANNEL
ModbusFunctionCodeWriteItem87 D6861 CHANNEL
ModbusFunctionCodeWriteItem88 D6871 CHANNEL
ModbusFunctionCodeWriteItem89 D6881 CHANNEL
ModbusFunctionCodeWriteItem9 D6081 CHANNEL
ModbusFunctionCodeWriteItem90 D6891 CHANNEL
ModbusFunctionCodeWriteItem91 D6901 CHANNEL
ModbusFunctionCodeWriteItem92 D6911 CHANNEL
ModbusFunctionCodeWriteItem93 D6921 CHANNEL
ModbusFunctionCodeWriteItem94 D6931 CHANNEL
ModbusFunctionCodeWriteItem95 D6941 CHANNEL
ModbusFunctionCodeWriteItem96 D6951 CHANNEL
ModbusFunctionCodeWriteItem97 D6961 CHANNEL
ModbusFunctionCodeWriteItem98 D6971 CHANNEL
ModbusFunctionCodeWriteItem99 D6981 CHANNEL
ModbusNodeNumberReadItem1 D5000 CHANNEL
ModbusNodeNumberReadItem10 D5090 CHANNEL
ModbusNodeNumberReadItem100 D5990 CHANNEL
ModbusNodeNumberReadItem11 D5100 CHANNEL
ModbusNodeNumberReadItem12 D5110 CHANNEL
ModbusNodeNumberReadItem13 D5120 CHANNEL
ModbusNodeNumberReadItem14 D5130 CHANNEL
ModbusNodeNumberReadItem15 D5140 CHANNEL
ModbusNodeNumberReadItem16 D5150 CHANNEL
ModbusNodeNumberReadItem17 D5160 CHANNEL
ModbusNodeNumberReadItem18 D5170 CHANNEL
ModbusNodeNumberReadItem19 D5180 CHANNEL
ModbusNodeNumberReadItem2 D5010 CHANNEL
ModbusNodeNumberReadItem20 D5190 CHANNEL
ModbusNodeNumberReadItem21 D5200 CHANNEL
ModbusNodeNumberReadItem22 D5210 CHANNEL
ModbusNodeNumberReadItem23 D5220 CHANNEL
ModbusNodeNumberReadItem24 D5230 CHANNEL
ModbusNodeNumberReadItem25 D5240 CHANNEL
ModbusNodeNumberReadItem26 D5250 CHANNEL
ModbusNodeNumberReadItem27 D5260 CHANNEL
ModbusNodeNumberReadItem28 D5270 CHANNEL
ModbusNodeNumberReadItem29 D5280 CHANNEL
ModbusNodeNumberReadItem3 D5020 CHANNEL
ModbusNodeNumberReadItem30 D5290 CHANNEL
ModbusNodeNumberReadItem31 D5300 CHANNEL
ModbusNodeNumberReadItem32 D5310 CHANNEL
ModbusNodeNumberReadItem33 D5320 CHANNEL
ModbusNodeNumberReadItem34 D5330 CHANNEL
ModbusNodeNumberReadItem35 D5340 CHANNEL
ModbusNodeNumberReadItem36 D5350 CHANNEL
ModbusNodeNumberReadItem37 D5360 CHANNEL
ModbusNodeNumberReadItem38 D5370 CHANNEL
ModbusNodeNumberReadItem39 D5380 CHANNEL
ModbusNodeNumberReadItem4 D5030 CHANNEL
ModbusNodeNumberReadItem40 D5390 CHANNEL
ModbusNodeNumberReadItem41 D5400 CHANNEL
ModbusNodeNumberReadItem42 D5410 CHANNEL
ModbusNodeNumberReadItem43 D5420 CHANNEL
ModbusNodeNumberReadItem44 D5430 CHANNEL
ModbusNodeNumberReadItem45 D5440 CHANNEL
ModbusNodeNumberReadItem46 D5450 CHANNEL
ModbusNodeNumberReadItem47 D5460 CHANNEL
ModbusNodeNumberReadItem48 D5470 CHANNEL
ModbusNodeNumberReadItem49 D5480 CHANNEL
ModbusNodeNumberReadItem5 D5040 CHANNEL
ModbusNodeNumberReadItem50 D5490 CHANNEL
ModbusNodeNumberReadItem51 D5500 CHANNEL
ModbusNodeNumberReadItem52 D5510 CHANNEL
ModbusNodeNumberReadItem53 D5520 CHANNEL
ModbusNodeNumberReadItem54 D5530 CHANNEL
ModbusNodeNumberReadItem55 D5540 CHANNEL
ModbusNodeNumberReadItem56 D5550 CHANNEL
ModbusNodeNumberReadItem57 D5560 CHANNEL
ModbusNodeNumberReadItem58 D5570 CHANNEL
ModbusNodeNumberReadItem59 D5580 CHANNEL
ModbusNodeNumberReadItem6 D5050 CHANNEL
ModbusNodeNumberReadItem60 D5590 CHANNEL
ModbusNodeNumberReadItem61 D5600 CHANNEL
ModbusNodeNumberReadItem62 D5610 CHANNEL
ModbusNodeNumberReadItem63 D5620 CHANNEL
ModbusNodeNumberReadItem64 D5630 CHANNEL
ModbusNodeNumberReadItem65 D5640 CHANNEL
ModbusNodeNumberReadItem66 D5650 CHANNEL
ModbusNodeNumberReadItem67 D5660 CHANNEL
ModbusNodeNumberReadItem68 D5670 CHANNEL
ModbusNodeNumberReadItem69 D5680 CHANNEL
ModbusNodeNumberReadItem7 D5060 CHANNEL
ModbusNodeNumberReadItem70 D5690 CHANNEL
ModbusNodeNumberReadItem71 D5700 CHANNEL
ModbusNodeNumberReadItem72 D5710 CHANNEL
ModbusNodeNumberReadItem73 D5720 CHANNEL
ModbusNodeNumberReadItem74 D5730 CHANNEL
ModbusNodeNumberReadItem75 D5740 CHANNEL
ModbusNodeNumberReadItem76 D5750 CHANNEL
ModbusNodeNumberReadItem77 D5760 CHANNEL
ModbusNodeNumberReadItem78 D5770 CHANNEL
ModbusNodeNumberReadItem79 D5780 CHANNEL
ModbusNodeNumberReadItem8 D5070 CHANNEL
ModbusNodeNumberReadItem80 D5790 CHANNEL
ModbusNodeNumberReadItem81 D5800 CHANNEL
ModbusNodeNumberReadItem82 D5810 CHANNEL
ModbusNodeNumberReadItem83 D5820 CHANNEL
ModbusNodeNumberReadItem84 D5830 CHANNEL
ModbusNodeNumberReadItem85 D5840 CHANNEL
ModbusNodeNumberReadItem86 D5850 CHANNEL
ModbusNodeNumberReadItem87 D5860 CHANNEL
ModbusNodeNumberReadItem88 D5870 CHANNEL
ModbusNodeNumberReadItem89 D5880 CHANNEL
ModbusNodeNumberReadItem9 D5080 CHANNEL
ModbusNodeNumberReadItem90 D5890 CHANNEL
ModbusNodeNumberReadItem91 D5900 CHANNEL
ModbusNodeNumberReadItem92 D5910 CHANNEL
ModbusNodeNumberReadItem93 D5920 CHANNEL
ModbusNodeNumberReadItem94 D5930 CHANNEL
ModbusNodeNumberReadItem95 D5940 CHANNEL
ModbusNodeNumberReadItem96 D5950 CHANNEL
ModbusNodeNumberReadItem97 D5960 CHANNEL
ModbusNodeNumberReadItem98 D5970 CHANNEL
ModbusNodeNumberReadItem99 D5980 CHANNEL
ModbusNodeNumberWriteItem1 D6000 CHANNEL
ModbusNodeNumberWriteItem10 D6090 CHANNEL
ModbusNodeNumberWriteItem100 D6990 CHANNEL
ModbusNodeNumberWriteItem11 D6100 CHANNEL
ModbusNodeNumberWriteItem12 D6110 CHANNEL
ModbusNodeNumberWriteItem13 D6120 CHANNEL
ModbusNodeNumberWriteItem14 D6130 CHANNEL
ModbusNodeNumberWriteItem15 D6140 CHANNEL
ModbusNodeNumberWriteItem16 D6150 CHANNEL
ModbusNodeNumberWriteItem17 D6160 CHANNEL
ModbusNodeNumberWriteItem18 D6170 CHANNEL
ModbusNodeNumberWriteItem19 D6180 CHANNEL
ModbusNodeNumberWriteItem2 D6010 CHANNEL
ModbusNodeNumberWriteItem20 D6190 CHANNEL
ModbusNodeNumberWriteItem21 D6200 CHANNEL
ModbusNodeNumberWriteItem22 D6210 CHANNEL
ModbusNodeNumberWriteItem23 D6220 CHANNEL
ModbusNodeNumberWriteItem24 D6230 CHANNEL
ModbusNodeNumberWriteItem25 D6240 CHANNEL
ModbusNodeNumberWriteItem26 D6250 CHANNEL
ModbusNodeNumberWriteItem27 D6260 CHANNEL
ModbusNodeNumberWriteItem28 D6270 CHANNEL
ModbusNodeNumberWriteItem29 D6280 CHANNEL
ModbusNodeNumberWriteItem3 D6020 CHANNEL
ModbusNodeNumberWriteItem30 D6290 CHANNEL
ModbusNodeNumberWriteItem31 D6300 CHANNEL
ModbusNodeNumberWriteItem32 D6310 CHANNEL
ModbusNodeNumberWriteItem33 D6320 CHANNEL
ModbusNodeNumberWriteItem34 D6330 CHANNEL
ModbusNodeNumberWriteItem35 D6340 CHANNEL
ModbusNodeNumberWriteItem36 D6350 CHANNEL
ModbusNodeNumberWriteItem37 D6360 CHANNEL
ModbusNodeNumberWriteItem38 D6370 CHANNEL
ModbusNodeNumberWriteItem39 D6380 CHANNEL
ModbusNodeNumberWriteItem4 D6030 CHANNEL
ModbusNodeNumberWriteItem40 D6390 CHANNEL
ModbusNodeNumberWriteItem41 D6400 CHANNEL
ModbusNodeNumberWriteItem42 D6410 CHANNEL
ModbusNodeNumberWriteItem43 D6420 CHANNEL
ModbusNodeNumberWriteItem44 D6430 CHANNEL
ModbusNodeNumberWriteItem45 D6440 CHANNEL
ModbusNodeNumberWriteItem46 D6450 CHANNEL
ModbusNodeNumberWriteItem47 D6460 CHANNEL
ModbusNodeNumberWriteItem48 D6470 CHANNEL
ModbusNodeNumberWriteItem49 D6480 CHANNEL
ModbusNodeNumberWriteItem5 D6040 CHANNEL
ModbusNodeNumberWriteItem50 D6490 CHANNEL
ModbusNodeNumberWriteItem51 D6500 CHANNEL
ModbusNodeNumberWriteItem52 D6510 CHANNEL
ModbusNodeNumberWriteItem53 D6520 CHANNEL
ModbusNodeNumberWriteItem54 D6530 CHANNEL
ModbusNodeNumberWriteItem55 D6540 CHANNEL
ModbusNodeNumberWriteItem56 D6550 CHANNEL
ModbusNodeNumberWriteItem57 D6560 CHANNEL
ModbusNodeNumberWriteItem58 D6570 CHANNEL
ModbusNodeNumberWriteItem59 D6580 CHANNEL
ModbusNodeNumberWriteItem6 D6050 CHANNEL
ModbusNodeNumberWriteItem60 D6590 CHANNEL
ModbusNodeNumberWriteItem61 D6600 CHANNEL
ModbusNodeNumberWriteItem62 D6610 CHANNEL
ModbusNodeNumberWriteItem63 D6620 CHANNEL
ModbusNodeNumberWriteItem64 D6630 CHANNEL
ModbusNodeNumberWriteItem65 D6640 CHANNEL
ModbusNodeNumberWriteItem66 D6650 CHANNEL
ModbusNodeNumberWriteItem67 D6660 CHANNEL
ModbusNodeNumberWriteItem68 D6670 CHANNEL
ModbusNodeNumberWriteItem69 D6680 CHANNEL
ModbusNodeNumberWriteItem7 D6060 CHANNEL
ModbusNodeNumberWriteItem70 D6690 CHANNEL
ModbusNodeNumberWriteItem71 D6700 CHANNEL
ModbusNodeNumberWriteItem72 D6710 CHANNEL
ModbusNodeNumberWriteItem73 D6720 CHANNEL
ModbusNodeNumberWriteItem74 D6730 CHANNEL
ModbusNodeNumberWriteItem75 D6740 CHANNEL
ModbusNodeNumberWriteItem76 D6750 CHANNEL
ModbusNodeNumberWriteItem77 D6760 CHANNEL
ModbusNodeNumberWriteItem78 D6770 CHANNEL
ModbusNodeNumberWriteItem79 D6780 CHANNEL
ModbusNodeNumberWriteItem8 D6070 CHANNEL
ModbusNodeNumberWriteItem80 D6790 CHANNEL
ModbusNodeNumberWriteItem81 D6800 CHANNEL
ModbusNodeNumberWriteItem82 D6810 CHANNEL
ModbusNodeNumberWriteItem83 D6820 CHANNEL
ModbusNodeNumberWriteItem84 D6830 CHANNEL
ModbusNodeNumberWriteItem85 D6840 CHANNEL
ModbusNodeNumberWriteItem86 D6850 CHANNEL
ModbusNodeNumberWriteItem87 D6860 CHANNEL
ModbusNodeNumberWriteItem88 D6870 CHANNEL
ModbusNodeNumberWriteItem89 D6880 CHANNEL
ModbusNodeNumberWriteItem9 D6080 CHANNEL
ModbusNodeNumberWriteItem90 D6890 CHANNEL
ModbusNodeNumberWriteItem91 D6900 CHANNEL
ModbusNodeNumberWriteItem92 D6910 CHANNEL
ModbusNodeNumberWriteItem93 D6920 CHANNEL
ModbusNodeNumberWriteItem94 D6930 CHANNEL
ModbusNodeNumberWriteItem95 D6940 CHANNEL
ModbusNodeNumberWriteItem96 D6950 CHANNEL
ModbusNodeNumberWriteItem97 D6960 CHANNEL
ModbusNodeNumberWriteItem98 D6970 CHANNEL
ModbusNodeNumberWriteItem99 D6980 CHANNEL
NonResettingTimeoutCounter W209 CHANNEL
NotUsed1ReadItem1 D5006 CHANNEL
NotUsed1ReadItem10 D5096 CHANNEL
NotUsed1ReadItem100 D5996 CHANNEL
NotUsed1ReadItem11 D5106 CHANNEL
NotUsed1ReadItem12 D5116 CHANNEL
NotUsed1ReadItem13 D5126 CHANNEL
NotUsed1ReadItem14 D5136 CHANNEL
NotUsed1ReadItem15 D5146 CHANNEL
NotUsed1ReadItem16 D5156 CHANNEL
NotUsed1ReadItem17 D5166 CHANNEL
NotUsed1ReadItem18 D5176 CHANNEL
NotUsed1ReadItem19 D5186 CHANNEL
NotUsed1ReadItem2 D5016 CHANNEL
NotUsed1ReadItem20 D5196 CHANNEL
NotUsed1ReadItem21 D5206 CHANNEL
NotUsed1ReadItem22 D5216 CHANNEL
NotUsed1ReadItem23 D5226 CHANNEL
NotUsed1ReadItem24 D5236 CHANNEL
NotUsed1ReadItem25 D5246 CHANNEL
NotUsed1ReadItem26 D5256 CHANNEL
NotUsed1ReadItem27 D5266 CHANNEL
NotUsed1ReadItem28 D5276 CHANNEL
NotUsed1ReadItem29 D5286 CHANNEL
NotUsed1ReadItem3 D5026 CHANNEL
NotUsed1ReadItem30 D5296 CHANNEL
NotUsed1ReadItem31 D5306 CHANNEL
NotUsed1ReadItem32 D5316 CHANNEL
NotUsed1ReadItem33 D5326 CHANNEL
NotUsed1ReadItem34 D5336 CHANNEL
NotUsed1ReadItem35 D5346 CHANNEL
NotUsed1ReadItem36 D5356 CHANNEL
NotUsed1ReadItem37 D5366 CHANNEL
NotUsed1ReadItem38 D5376 CHANNEL
NotUsed1ReadItem39 D5386 CHANNEL
NotUsed1ReadItem4 D5036 CHANNEL
NotUsed1ReadItem40 D5396 CHANNEL
NotUsed1ReadItem41 D5406 CHANNEL
NotUsed1ReadItem42 D5416 CHANNEL
NotUsed1ReadItem43 D5426 CHANNEL
NotUsed1ReadItem44 D5436 CHANNEL
NotUsed1ReadItem45 D5446 CHANNEL
NotUsed1ReadItem46 D5456 CHANNEL
NotUsed1ReadItem47 D5466 CHANNEL
NotUsed1ReadItem48 D5476 CHANNEL
NotUsed1ReadItem49 D5486 CHANNEL
NotUsed1ReadItem5 D5046 CHANNEL
NotUsed1ReadItem50 D5496 CHANNEL
NotUsed1ReadItem51 D5506 CHANNEL
NotUsed1ReadItem52 D5516 CHANNEL
NotUsed1ReadItem53 D5526 CHANNEL
NotUsed1ReadItem54 D5536 CHANNEL
NotUsed1ReadItem55 D5546 CHANNEL
NotUsed1ReadItem56 D5556 CHANNEL
NotUsed1ReadItem57 D5566 CHANNEL
NotUsed1ReadItem58 D5576 CHANNEL
NotUsed1ReadItem59 D5586 CHANNEL
NotUsed1ReadItem6 D5056 CHANNEL
NotUsed1ReadItem60 D5596 CHANNEL
NotUsed1ReadItem61 D5606 CHANNEL
NotUsed1ReadItem62 D5616 CHANNEL
NotUsed1ReadItem63 D5626 CHANNEL
NotUsed1ReadItem64 D5636 CHANNEL
NotUsed1ReadItem65 D5646 CHANNEL
NotUsed1ReadItem66 D5656 CHANNEL
NotUsed1ReadItem67 D5666 CHANNEL
NotUsed1ReadItem68 D5676 CHANNEL
NotUsed1ReadItem69 D5686 CHANNEL
NotUsed1ReadItem7 D5066 CHANNEL
NotUsed1ReadItem70 D5696 CHANNEL
NotUsed1ReadItem71 D5706 CHANNEL
NotUsed1ReadItem72 D5716 CHANNEL
NotUsed1ReadItem73 D5726 CHANNEL
NotUsed1ReadItem74 D5736 CHANNEL
NotUsed1ReadItem75 D5746 CHANNEL
NotUsed1ReadItem76 D5756 CHANNEL
NotUsed1ReadItem77 D5766 CHANNEL
NotUsed1ReadItem78 D5776 CHANNEL
NotUsed1ReadItem79 D5786 CHANNEL
NotUsed1ReadItem8 D5076 CHANNEL
NotUsed1ReadItem80 D5796 CHANNEL
NotUsed1ReadItem81 D5806 CHANNEL
NotUsed1ReadItem82 D5816 CHANNEL
NotUsed1ReadItem83 D5826 CHANNEL
NotUsed1ReadItem84 D5836 CHANNEL
NotUsed1ReadItem85 D5846 CHANNEL
NotUsed1ReadItem86 D5856 CHANNEL
NotUsed1ReadItem87 D5866 CHANNEL
NotUsed1ReadItem88 D5876 CHANNEL
NotUsed1ReadItem89 D5886 CHANNEL
NotUsed1ReadItem9 D5086 CHANNEL
NotUsed1ReadItem90 D5896 CHANNEL
NotUsed1ReadItem91 D5906 CHANNEL
NotUsed1ReadItem92 D5916 CHANNEL
NotUsed1ReadItem93 D5926 CHANNEL
NotUsed1ReadItem94 D5936 CHANNEL
NotUsed1ReadItem95 D5946 CHANNEL
NotUsed1ReadItem96 D5956 CHANNEL
NotUsed1ReadItem97 D5966 CHANNEL
NotUsed1ReadItem98 D5976 CHANNEL
NotUsed1ReadItem99 D5986 CHANNEL
NotUsed2ReadItem1 D5007 CHANNEL
NotUsed2ReadItem10 D5097 CHANNEL
NotUsed2ReadItem100 D5997 CHANNEL
NotUsed2ReadItem11 D5107 CHANNEL
NotUsed2ReadItem12 D5117 CHANNEL
NotUsed2ReadItem13 D5127 CHANNEL
NotUsed2ReadItem14 D5137 CHANNEL
NotUsed2ReadItem15 D5147 CHANNEL
NotUsed2ReadItem16 D5157 CHANNEL
NotUsed2ReadItem17 D5167 CHANNEL
NotUsed2ReadItem18 D5177 CHANNEL
NotUsed2ReadItem19 D5187 CHANNEL
NotUsed2ReadItem2 D5017 CHANNEL
NotUsed2ReadItem20 D5197 CHANNEL
NotUsed2ReadItem21 D5207 CHANNEL
NotUsed2ReadItem22 D5217 CHANNEL
NotUsed2ReadItem23 D5227 CHANNEL
NotUsed2ReadItem24 D5237 CHANNEL
NotUsed2ReadItem25 D5247 CHANNEL
NotUsed2ReadItem26 D5257 CHANNEL
NotUsed2ReadItem27 D5267 CHANNEL
NotUsed2ReadItem28 D5277 CHANNEL
NotUsed2ReadItem29 D5287 CHANNEL
NotUsed2ReadItem3 D5027 CHANNEL
NotUsed2ReadItem30 D5297 CHANNEL
NotUsed2ReadItem31 D5307 CHANNEL
NotUsed2ReadItem32 D5317 CHANNEL
NotUsed2ReadItem33 D5327 CHANNEL
NotUsed2ReadItem34 D5337 CHANNEL
NotUsed2ReadItem35 D5347 CHANNEL
NotUsed2ReadItem36 D5357 CHANNEL
NotUsed2ReadItem37 D5367 CHANNEL
NotUsed2ReadItem38 D5377 CHANNEL
NotUsed2ReadItem39 D5387 CHANNEL
NotUsed2ReadItem4 D5037 CHANNEL
NotUsed2ReadItem40 D5397 CHANNEL
NotUsed2ReadItem41 D5407 CHANNEL
NotUsed2ReadItem42 D5417 CHANNEL
NotUsed2ReadItem43 D5427 CHANNEL
NotUsed2ReadItem44 D5437 CHANNEL
NotUsed2ReadItem45 D5447 CHANNEL
NotUsed2ReadItem46 D5457 CHANNEL
NotUsed2ReadItem47 D5467 CHANNEL
NotUsed2ReadItem48 D5477 CHANNEL
NotUsed2ReadItem49 D5487 CHANNEL
NotUsed2ReadItem5 D5047 CHANNEL
NotUsed2ReadItem50 D5497 CHANNEL
NotUsed2ReadItem51 D5507 CHANNEL
NotUsed2ReadItem52 D5517 CHANNEL
NotUsed2ReadItem53 D5527 CHANNEL
NotUsed2ReadItem54 D5537 CHANNEL
NotUsed2ReadItem55 D5547 CHANNEL
NotUsed2ReadItem56 D5557 CHANNEL
NotUsed2ReadItem57 D5567 CHANNEL
NotUsed2ReadItem58 D5577 CHANNEL
NotUsed2ReadItem59 D5587 CHANNEL
NotUsed2ReadItem6 D5057 CHANNEL
NotUsed2ReadItem60 D5597 CHANNEL
NotUsed2ReadItem61 D5607 CHANNEL
NotUsed2ReadItem62 D5617 CHANNEL
NotUsed2ReadItem63 D5627 CHANNEL
NotUsed2ReadItem64 D5637 CHANNEL
NotUsed2ReadItem65 D5647 CHANNEL
NotUsed2ReadItem66 D5657 CHANNEL
NotUsed2ReadItem67 D5667 CHANNEL
NotUsed2ReadItem68 D5677 CHANNEL
NotUsed2ReadItem69 D5687 CHANNEL
NotUsed2ReadItem7 D5067 CHANNEL
NotUsed2ReadItem70 D5697 CHANNEL
NotUsed2ReadItem71 D5707 CHANNEL
NotUsed2ReadItem72 D5717 CHANNEL
NotUsed2ReadItem73 D5727 CHANNEL
NotUsed2ReadItem74 D5737 CHANNEL
NotUsed2ReadItem75 D5747 CHANNEL
NotUsed2ReadItem76 D5757 CHANNEL
NotUsed2ReadItem77 D5767 CHANNEL
NotUsed2ReadItem78 D5777 CHANNEL
NotUsed2ReadItem79 D5787 CHANNEL
NotUsed2ReadItem8 D5077 CHANNEL
NotUsed2ReadItem80 D5797 CHANNEL
NotUsed2ReadItem81 D5807 CHANNEL
NotUsed2ReadItem82 D5817 CHANNEL
NotUsed2ReadItem83 D5827 CHANNEL
NotUsed2ReadItem84 D5837 CHANNEL
NotUsed2ReadItem85 D5847 CHANNEL
NotUsed2ReadItem86 D5857 CHANNEL
NotUsed2ReadItem87 D5867 CHANNEL
NotUsed2ReadItem88 D5877 CHANNEL
NotUsed2ReadItem89 D5887 CHANNEL
NotUsed2ReadItem9 D5087 CHANNEL
NotUsed2ReadItem90 D5897 CHANNEL
NotUsed2ReadItem91 D5907 CHANNEL
NotUsed2ReadItem92 D5917 CHANNEL
NotUsed2ReadItem93 D5927 CHANNEL
NotUsed2ReadItem94 D5937 CHANNEL
NotUsed2ReadItem95 D5947 CHANNEL
NotUsed2ReadItem96 D5957 CHANNEL
NotUsed2ReadItem97 D5967 CHANNEL
NotUsed2ReadItem98 D5977 CHANNEL
NotUsed2ReadItem99 D5987 CHANNEL
NumberOfItemsToReadReadItem1 D5003 CHANNEL
NumberOfItemsToReadReadItem10 D5093 CHANNEL
NumberOfItemsToReadReadItem100 D5993 CHANNEL
NumberOfItemsToReadReadItem11 D5103 CHANNEL
NumberOfItemsToReadReadItem12 D5113 CHANNEL
NumberOfItemsToReadReadItem13 D5123 CHANNEL
NumberOfItemsToReadReadItem14 D5133 CHANNEL
NumberOfItemsToReadReadItem15 D5143 CHANNEL
NumberOfItemsToReadReadItem16 D5153 CHANNEL
NumberOfItemsToReadReadItem17 D5163 CHANNEL
NumberOfItemsToReadReadItem18 D5173 CHANNEL
NumberOfItemsToReadReadItem19 D5183 CHANNEL
NumberOfItemsToReadReadItem2 D5013 CHANNEL
NumberOfItemsToReadReadItem20 D5193 CHANNEL
NumberOfItemsToReadReadItem21 D5203 CHANNEL
NumberOfItemsToReadReadItem22 D5213 CHANNEL
NumberOfItemsToReadReadItem23 D5223 CHANNEL
NumberOfItemsToReadReadItem24 D5233 CHANNEL
NumberOfItemsToReadReadItem25 D5243 CHANNEL
NumberOfItemsToReadReadItem26 D5253 CHANNEL
NumberOfItemsToReadReadItem27 D5263 CHANNEL
NumberOfItemsToReadReadItem28 D5273 CHANNEL
NumberOfItemsToReadReadItem29 D5283 CHANNEL
NumberOfItemsToReadReadItem3 D5023 CHANNEL
NumberOfItemsToReadReadItem30 D5293 CHANNEL
NumberOfItemsToReadReadItem31 D5303 CHANNEL
NumberOfItemsToReadReadItem32 D5313 CHANNEL
NumberOfItemsToReadReadItem33 D5323 CHANNEL
NumberOfItemsToReadReadItem34 D5333 CHANNEL
NumberOfItemsToReadReadItem35 D5343 CHANNEL
NumberOfItemsToReadReadItem36 D5353 CHANNEL
NumberOfItemsToReadReadItem37 D5363 CHANNEL
NumberOfItemsToReadReadItem38 D5373 CHANNEL
NumberOfItemsToReadReadItem39 D5383 CHANNEL
NumberOfItemsToReadReadItem4 D5033 CHANNEL
NumberOfItemsToReadReadItem40 D5393 CHANNEL
NumberOfItemsToReadReadItem41 D5403 CHANNEL
NumberOfItemsToReadReadItem42 D5413 CHANNEL
NumberOfItemsToReadReadItem43 D5423 CHANNEL
NumberOfItemsToReadReadItem44 D5433 CHANNEL
NumberOfItemsToReadReadItem45 D5443 CHANNEL
NumberOfItemsToReadReadItem46 D5453 CHANNEL
NumberOfItemsToReadReadItem47 D5463 CHANNEL
NumberOfItemsToReadReadItem48 D5473 CHANNEL
NumberOfItemsToReadReadItem49 D5483 CHANNEL
NumberOfItemsToReadReadItem5 D5043 CHANNEL
NumberOfItemsToReadReadItem50 D5493 CHANNEL
NumberOfItemsToReadReadItem51 D5503 CHANNEL
NumberOfItemsToReadReadItem52 D5513 CHANNEL
NumberOfItemsToReadReadItem53 D5523 CHANNEL
NumberOfItemsToReadReadItem54 D5533 CHANNEL
NumberOfItemsToReadReadItem55 D5543 CHANNEL
NumberOfItemsToReadReadItem56 D5553 CHANNEL
NumberOfItemsToReadReadItem57 D5563 CHANNEL
NumberOfItemsToReadReadItem58 D5573 CHANNEL
NumberOfItemsToReadReadItem59 D5583 CHANNEL
NumberOfItemsToReadReadItem6 D5053 CHANNEL
NumberOfItemsToReadReadItem60 D5593 CHANNEL
NumberOfItemsToReadReadItem61 D5603 CHANNEL
NumberOfItemsToReadReadItem62 D5613 CHANNEL
NumberOfItemsToReadReadItem63 D5623 CHANNEL
NumberOfItemsToReadReadItem64 D5633 CHANNEL
NumberOfItemsToReadReadItem65 D5643 CHANNEL
NumberOfItemsToReadReadItem66 D5653 CHANNEL
NumberOfItemsToReadReadItem67 D5663 CHANNEL
NumberOfItemsToReadReadItem68 D5673 CHANNEL
NumberOfItemsToReadReadItem69 D5683 CHANNEL
NumberOfItemsToReadReadItem7 D5063 CHANNEL
NumberOfItemsToReadReadItem70 D5693 CHANNEL
NumberOfItemsToReadReadItem71 D5703 CHANNEL
NumberOfItemsToReadReadItem72 D5713 CHANNEL
NumberOfItemsToReadReadItem73 D5723 CHANNEL
NumberOfItemsToReadReadItem74 D5733 CHANNEL
NumberOfItemsToReadReadItem75 D5743 CHANNEL
NumberOfItemsToReadReadItem76 D5753 CHANNEL
NumberOfItemsToReadReadItem77 D5763 CHANNEL
NumberOfItemsToReadReadItem78 D5773 CHANNEL
NumberOfItemsToReadReadItem79 D5783 CHANNEL
NumberOfItemsToReadReadItem8 D5073 CHANNEL
NumberOfItemsToReadReadItem80 D5793 CHANNEL
NumberOfItemsToReadReadItem81 D5803 CHANNEL
NumberOfItemsToReadReadItem82 D5813 CHANNEL
NumberOfItemsToReadReadItem83 D5823 CHANNEL
NumberOfItemsToReadReadItem84 D5833 CHANNEL
NumberOfItemsToReadReadItem85 D5843 CHANNEL
NumberOfItemsToReadReadItem86 D5853 CHANNEL
NumberOfItemsToReadReadItem87 D5863 CHANNEL
NumberOfItemsToReadReadItem88 D5873 CHANNEL
NumberOfItemsToReadReadItem89 D5883 CHANNEL
NumberOfItemsToReadReadItem9 D5083 CHANNEL
NumberOfItemsToReadReadItem90 D5893 CHANNEL
NumberOfItemsToReadReadItem91 D5903 CHANNEL
NumberOfItemsToReadReadItem92 D5913 CHANNEL
NumberOfItemsToReadReadItem93 D5923 CHANNEL
NumberOfItemsToReadReadItem94 D5933 CHANNEL
NumberOfItemsToReadReadItem95 D5943 CHANNEL
NumberOfItemsToReadReadItem96 D5953 CHANNEL
NumberOfItemsToReadReadItem97 D5963 CHANNEL
NumberOfItemsToReadReadItem98 D5973 CHANNEL
NumberOfItemsToReadReadItem99 D5983 CHANNEL
NumberOfItemsToWriteWriteItem1 D6003 CHANNEL
NumberOfItemsToWriteWriteItem10 D6093 CHANNEL
NumberOfItemsToWriteWriteItem100 D6993 CHANNEL
NumberOfItemsToWriteWriteItem11 D6103 CHANNEL
NumberOfItemsToWriteWriteItem12 D6113 CHANNEL
NumberOfItemsToWriteWriteItem13 D6123 CHANNEL
NumberOfItemsToWriteWriteItem14 D6133 CHANNEL
NumberOfItemsToWriteWriteItem15 D6143 CHANNEL
NumberOfItemsToWriteWriteItem16 D6153 CHANNEL
NumberOfItemsToWriteWriteItem17 D6163 CHANNEL
NumberOfItemsToWriteWriteItem18 D6173 CHANNEL
NumberOfItemsToWriteWriteItem19 D6183 CHANNEL
NumberOfItemsToWriteWriteItem2 D6013 CHANNEL
NumberOfItemsToWriteWriteItem20 D6193 CHANNEL
NumberOfItemsToWriteWriteItem21 D6203 CHANNEL
NumberOfItemsToWriteWriteItem22 D6213 CHANNEL
NumberOfItemsToWriteWriteItem23 D6223 CHANNEL
NumberOfItemsToWriteWriteItem24 D6233 CHANNEL
NumberOfItemsToWriteWriteItem25 D6243 CHANNEL
NumberOfItemsToWriteWriteItem26 D6253 CHANNEL
NumberOfItemsToWriteWriteItem27 D6263 CHANNEL
NumberOfItemsToWriteWriteItem28 D6273 CHANNEL
NumberOfItemsToWriteWriteItem29 D6283 CHANNEL
NumberOfItemsToWriteWriteItem3 D6023 CHANNEL
NumberOfItemsToWriteWriteItem30 D6293 CHANNEL
NumberOfItemsToWriteWriteItem31 D6303 CHANNEL
NumberOfItemsToWriteWriteItem32 D6313 CHANNEL
NumberOfItemsToWriteWriteItem33 D6323 CHANNEL
NumberOfItemsToWriteWriteItem34 D6333 CHANNEL
NumberOfItemsToWriteWriteItem35 D6343 CHANNEL
NumberOfItemsToWriteWriteItem36 D6353 CHANNEL
NumberOfItemsToWriteWriteItem37 D6363 CHANNEL
NumberOfItemsToWriteWriteItem38 D6373 CHANNEL
NumberOfItemsToWriteWriteItem39 D6383 CHANNEL
NumberOfItemsToWriteWriteItem4 D6033 CHANNEL
NumberOfItemsToWriteWriteItem40 D6393 CHANNEL
NumberOfItemsToWriteWriteItem41 D6403 CHANNEL
NumberOfItemsToWriteWriteItem42 D6413 CHANNEL
NumberOfItemsToWriteWriteItem43 D6423 CHANNEL
NumberOfItemsToWriteWriteItem44 D6433 CHANNEL
NumberOfItemsToWriteWriteItem45 D6443 CHANNEL
NumberOfItemsToWriteWriteItem46 D6453 CHANNEL
NumberOfItemsToWriteWriteItem47 D6463 CHANNEL
NumberOfItemsToWriteWriteItem48 D6473 CHANNEL
NumberOfItemsToWriteWriteItem49 D6483 CHANNEL
NumberOfItemsToWriteWriteItem5 D6043 CHANNEL
NumberOfItemsToWriteWriteItem50 D6493 CHANNEL
NumberOfItemsToWriteWriteItem51 D6503 CHANNEL
NumberOfItemsToWriteWriteItem52 D6513 CHANNEL
NumberOfItemsToWriteWriteItem53 D6523 CHANNEL
NumberOfItemsToWriteWriteItem54 D6533 CHANNEL
NumberOfItemsToWriteWriteItem55 D6543 CHANNEL
NumberOfItemsToWriteWriteItem56 D6553 CHANNEL
NumberOfItemsToWriteWriteItem57 D6563 CHANNEL
NumberOfItemsToWriteWriteItem58 D6573 CHANNEL
NumberOfItemsToWriteWriteItem59 D6583 CHANNEL
NumberOfItemsToWriteWriteItem6 D6053 CHANNEL
NumberOfItemsToWriteWriteItem60 D6593 CHANNEL
NumberOfItemsToWriteWriteItem61 D6603 CHANNEL
NumberOfItemsToWriteWriteItem62 D6613 CHANNEL
NumberOfItemsToWriteWriteItem63 D6623 CHANNEL
NumberOfItemsToWriteWriteItem64 D6633 CHANNEL
NumberOfItemsToWriteWriteItem65 D6643 CHANNEL
NumberOfItemsToWriteWriteItem66 D6653 CHANNEL
NumberOfItemsToWriteWriteItem67 D6663 CHANNEL
NumberOfItemsToWriteWriteItem68 D6673 CHANNEL
NumberOfItemsToWriteWriteItem69 D6683 CHANNEL
NumberOfItemsToWriteWriteItem7 D6063 CHANNEL
NumberOfItemsToWriteWriteItem70 D6693 CHANNEL
NumberOfItemsToWriteWriteItem71 D6703 CHANNEL
NumberOfItemsToWriteWriteItem72 D6713 CHANNEL
NumberOfItemsToWriteWriteItem73 D6723 CHANNEL
NumberOfItemsToWriteWriteItem74 D6733 CHANNEL
NumberOfItemsToWriteWriteItem75 D6743 CHANNEL
NumberOfItemsToWriteWriteItem76 D6753 CHANNEL
NumberOfItemsToWriteWriteItem77 D6763 CHANNEL
NumberOfItemsToWriteWriteItem78 D6773 CHANNEL
NumberOfItemsToWriteWriteItem79 D6783 CHANNEL
NumberOfItemsToWriteWriteItem8 D6073 CHANNEL
NumberOfItemsToWriteWriteItem80 D6793 CHANNEL
NumberOfItemsToWriteWriteItem81 D6803 CHANNEL
NumberOfItemsToWriteWriteItem82 D6813 CHANNEL
NumberOfItemsToWriteWriteItem83 D6823 CHANNEL
NumberOfItemsToWriteWriteItem84 D6833 CHANNEL
NumberOfItemsToWriteWriteItem85 D6843 CHANNEL
NumberOfItemsToWriteWriteItem86 D6853 CHANNEL
NumberOfItemsToWriteWriteItem87 D6863 CHANNEL
NumberOfItemsToWriteWriteItem88 D6873 CHANNEL
NumberOfItemsToWriteWriteItem89 D6883 CHANNEL
NumberOfItemsToWriteWriteItem9 D6083 CHANNEL
NumberOfItemsToWriteWriteItem90 D6893 CHANNEL
NumberOfItemsToWriteWriteItem91 D6903 CHANNEL
NumberOfItemsToWriteWriteItem92 D6913 CHANNEL
NumberOfItemsToWriteWriteItem93 D6923 CHANNEL
NumberOfItemsToWriteWriteItem94 D6933 CHANNEL
NumberOfItemsToWriteWriteItem95 D6943 CHANNEL
NumberOfItemsToWriteWriteItem96 D6953 CHANNEL
NumberOfItemsToWriteWriteItem97 D6963 CHANNEL
NumberOfItemsToWriteWriteItem98 D6973 CHANNEL
NumberOfItemsToWriteWriteItem99 D6983 CHANNEL
Polling_Has_Occurred W215.02 BOOL
Port_1_Error A392.04 BOOL
Port_Needs_To_Be_Reset W205.02 BOOL  ; Waiting for Easy Modbus to finish current command
Port_Now_Resetting W205.03 BOOL
ReadValidOrInvalidReadItem1 D5008 CHANNEL
ReadValidOrInvalidReadItem10 D5098 CHANNEL
ReadValidOrInvalidReadItem100 D5998 CHANNEL
ReadValidOrInvalidReadItem11 D5108 CHANNEL
ReadValidOrInvalidReadItem12 D5118 CHANNEL
ReadValidOrInvalidReadItem13 D5128 CHANNEL
ReadValidOrInvalidReadItem14 D5138 CHANNEL
ReadValidOrInvalidReadItem15 D5148 CHANNEL
ReadValidOrInvalidReadItem16 D5158 CHANNEL
ReadValidOrInvalidReadItem17 D5168 CHANNEL
ReadValidOrInvalidReadItem18 D5178 CHANNEL
ReadValidOrInvalidReadItem19 D5188 CHANNEL
ReadValidOrInvalidReadItem2 D5018 CHANNEL
ReadValidOrInvalidReadItem20 D5198 CHANNEL
ReadValidOrInvalidReadItem21 D5208 CHANNEL
ReadValidOrInvalidReadItem22 D5218 CHANNEL
ReadValidOrInvalidReadItem23 D5228 CHANNEL
ReadValidOrInvalidReadItem24 D5238 CHANNEL
ReadValidOrInvalidReadItem25 D5248 CHANNEL
ReadValidOrInvalidReadItem26 D5258 CHANNEL
ReadValidOrInvalidReadItem27 D5268 CHANNEL
ReadValidOrInvalidReadItem28 D5278 CHANNEL
ReadValidOrInvalidReadItem29 D5288 CHANNEL
ReadValidOrInvalidReadItem3 D5028 CHANNEL
ReadValidOrInvalidReadItem30 D5298 CHANNEL
ReadValidOrInvalidReadItem31 D5308 CHANNEL
ReadValidOrInvalidReadItem32 D5318 CHANNEL
ReadValidOrInvalidReadItem33 D5328 CHANNEL
ReadValidOrInvalidReadItem34 D5338 CHANNEL
ReadValidOrInvalidReadItem35 D5348 CHANNEL
ReadValidOrInvalidReadItem36 D5358 CHANNEL
ReadValidOrInvalidReadItem37 D5368 CHANNEL
ReadValidOrInvalidReadItem38 D5378 CHANNEL
ReadValidOrInvalidReadItem39 D5388 CHANNEL
ReadValidOrInvalidReadItem4 D5038 CHANNEL
ReadValidOrInvalidReadItem40 D5398 CHANNEL
ReadValidOrInvalidReadItem41 D5408 CHANNEL
ReadValidOrInvalidReadItem42 D5418 CHANNEL
ReadValidOrInvalidReadItem43 D5428 CHANNEL
ReadValidOrInvalidReadItem44 D5438 CHANNEL
ReadValidOrInvalidReadItem45 D5448 CHANNEL
ReadValidOrInvalidReadItem46 D5458 CHANNEL
ReadValidOrInvalidReadItem47 D5468 CHANNEL
ReadValidOrInvalidReadItem48 D5478 CHANNEL
ReadValidOrInvalidReadItem49 D5488 CHANNEL
ReadValidOrInvalidReadItem5 D5048 CHANNEL
ReadValidOrInvalidReadItem50 D5498 CHANNEL
ReadValidOrInvalidReadItem51 D5508 CHANNEL
ReadValidOrInvalidReadItem52 D5518 CHANNEL
ReadValidOrInvalidReadItem53 D5528 CHANNEL
ReadValidOrInvalidReadItem54 D5538 CHANNEL
ReadValidOrInvalidReadItem55 D5548 CHANNEL
ReadValidOrInvalidReadItem56 D5558 CHANNEL
ReadValidOrInvalidReadItem57 D5568 CHANNEL
ReadValidOrInvalidReadItem58 D5578 CHANNEL
ReadValidOrInvalidReadItem59 D5588 CHANNEL
ReadValidOrInvalidReadItem6 D5058 CHANNEL
ReadValidOrInvalidReadItem60 D5598 CHANNEL
ReadValidOrInvalidReadItem61 D5608 CHANNEL
ReadValidOrInvalidReadItem62 D5618 CHANNEL
ReadValidOrInvalidReadItem63 D5628 CHANNEL
ReadValidOrInvalidReadItem64 D5638 CHANNEL
ReadValidOrInvalidReadItem65 D5648 CHANNEL
ReadValidOrInvalidReadItem66 D5658 CHANNEL
ReadValidOrInvalidReadItem67 D5668 CHANNEL
ReadValidOrInvalidReadItem68 D5678 CHANNEL
ReadValidOrInvalidReadItem69 D5688 CHANNEL
ReadValidOrInvalidReadItem7 D5068 CHANNEL
ReadValidOrInvalidReadItem70 D5698 CHANNEL
ReadValidOrInvalidReadItem71 D5708 CHANNEL
ReadValidOrInvalidReadItem72 D5718 CHANNEL
ReadValidOrInvalidReadItem73 D5728 CHANNEL
ReadValidOrInvalidReadItem74 D5738 CHANNEL
ReadValidOrInvalidReadItem75 D5748 CHANNEL
ReadValidOrInvalidReadItem76 D5758 CHANNEL
ReadValidOrInvalidReadItem77 D5768 CHANNEL
ReadValidOrInvalidReadItem78 D5778 CHANNEL
ReadValidOrInvalidReadItem79 D5788 CHANNEL
ReadValidOrInvalidReadItem8 D5078 CHANNEL
ReadValidOrInvalidReadItem80 D5798 CHANNEL
ReadValidOrInvalidReadItem81 D5808 CHANNEL
ReadValidOrInvalidReadItem82 D5818 CHANNEL
ReadValidOrInvalidReadItem83 D5828 CHANNEL
ReadValidOrInvalidReadItem84 D5838 CHANNEL
ReadValidOrInvalidReadItem85 D5848 CHANNEL
ReadValidOrInvalidReadItem86 D5858 CHANNEL
ReadValidOrInvalidReadItem87 D5868 CHANNEL
ReadValidOrInvalidReadItem88 D5878 CHANNEL
ReadValidOrInvalidReadItem89 D5888 CHANNEL
ReadValidOrInvalidReadItem9 D5088 CHANNEL
ReadValidOrInvalidReadItem90 D5898 CHANNEL
ReadValidOrInvalidReadItem91 D5908 CHANNEL
ReadValidOrInvalidReadItem92 D5918 CHANNEL
ReadValidOrInvalidReadItem93 D5928 CHANNEL
ReadValidOrInvalidReadItem94 D5938 CHANNEL
ReadValidOrInvalidReadItem95 D5948 CHANNEL
ReadValidOrInvalidReadItem96 D5958 CHANNEL
ReadValidOrInvalidReadItem97 D5968 CHANNEL
ReadValidOrInvalidReadItem98 D5978 CHANNEL
ReadValidOrInvalidReadItem99 D5988 CHANNEL
Retry_Send_Delay W205.01 BOOL
SecondWordResponseDataReadItem1 D5005 CHANNEL
SecondWordResponseDataReadItem10 D5095 CHANNEL
SecondWordResponseDataReadItem100 D5995 CHANNEL
SecondWordResponseDataReadItem11 D5105 CHANNEL
SecondWordResponseDataReadItem12 D5115 CHANNEL
SecondWordResponseDataReadItem13 D5125 CHANNEL
SecondWordResponseDataReadItem14 D5135 CHANNEL
SecondWordResponseDataReadItem15 D5145 CHANNEL
SecondWordResponseDataReadItem16 D5155 CHANNEL
SecondWordResponseDataReadItem17 D5165 CHANNEL
SecondWordResponseDataReadItem18 D5175 CHANNEL
SecondWordResponseDataReadItem19 D5185 CHANNEL
SecondWordResponseDataReadItem2 D5015 CHANNEL
SecondWordResponseDataReadItem20 D5195 CHANNEL
SecondWordResponseDataReadItem21 D5205 CHANNEL
SecondWordResponseDataReadItem22 D5215 CHANNEL
SecondWordResponseDataReadItem23 D5225 CHANNEL
SecondWordResponseDataReadItem24 D5235 CHANNEL
SecondWordResponseDataReadItem25 D5245 CHANNEL
SecondWordResponseDataReadItem26 D5255 CHANNEL
SecondWordResponseDataReadItem27 D5265 CHANNEL
SecondWordResponseDataReadItem28 D5275 CHANNEL
SecondWordResponseDataReadItem29 D5285 CHANNEL
SecondWordResponseDataReadItem3 D5025 CHANNEL
SecondWordResponseDataReadItem30 D5295 CHANNEL
SecondWordResponseDataReadItem31 D5305 CHANNEL
SecondWordResponseDataReadItem32 D5315 CHANNEL
SecondWordResponseDataReadItem33 D5325 CHANNEL
SecondWordResponseDataReadItem34 D5335 CHANNEL
SecondWordResponseDataReadItem35 D5345 CHANNEL
SecondWordResponseDataReadItem36 D5355 CHANNEL
SecondWordResponseDataReadItem37 D5365 CHANNEL
SecondWordResponseDataReadItem38 D5375 CHANNEL
SecondWordResponseDataReadItem39 D5385 CHANNEL
SecondWordResponseDataReadItem4 D5035 CHANNEL
SecondWordResponseDataReadItem40 D5395 CHANNEL
SecondWordResponseDataReadItem41 D5405 CHANNEL
SecondWordResponseDataReadItem42 D5415 CHANNEL
SecondWordResponseDataReadItem43 D5425 CHANNEL
SecondWordResponseDataReadItem44 D5435 CHANNEL
SecondWordResponseDataReadItem45 D5445 CHANNEL
SecondWordResponseDataReadItem46 D5455 CHANNEL
SecondWordResponseDataReadItem47 D5465 CHANNEL
SecondWordResponseDataReadItem48 D5475 CHANNEL
SecondWordResponseDataReadItem49 D5485 CHANNEL
SecondWordResponseDataReadItem5 D5045 CHANNEL
SecondWordResponseDataReadItem50 D5495 CHANNEL
SecondWordResponseDataReadItem51 D5505 CHANNEL
SecondWordResponseDataReadItem52 D5515 CHANNEL
SecondWordResponseDataReadItem53 D5525 CHANNEL
SecondWordResponseDataReadItem54 D5535 CHANNEL
SecondWordResponseDataReadItem55 D5545 CHANNEL
SecondWordResponseDataReadItem56 D5555 CHANNEL
SecondWordResponseDataReadItem57 D5565 CHANNEL
SecondWordResponseDataReadItem58 D5575 CHANNEL
SecondWordResponseDataReadItem59 D5585 CHANNEL
SecondWordResponseDataReadItem6 D5055 CHANNEL
SecondWordResponseDataReadItem60 D5595 CHANNEL
SecondWordResponseDataReadItem61 D5605 CHANNEL
SecondWordResponseDataReadItem62 D5615 CHANNEL
SecondWordResponseDataReadItem63 D5625 CHANNEL
SecondWordResponseDataReadItem64 D5635 CHANNEL
SecondWordResponseDataReadItem65 D5645 CHANNEL
SecondWordResponseDataReadItem66 D5655 CHANNEL
SecondWordResponseDataReadItem67 D5665 CHANNEL
SecondWordResponseDataReadItem68 D5675 CHANNEL
SecondWordResponseDataReadItem69 D5685 CHANNEL
SecondWordResponseDataReadItem7 D5065 CHANNEL
SecondWordResponseDataReadItem70 D5695 CHANNEL
SecondWordResponseDataReadItem71 D5705 CHANNEL
SecondWordResponseDataReadItem72 D5715 CHANNEL
SecondWordResponseDataReadItem73 D5725 CHANNEL
SecondWordResponseDataReadItem74 D5735 CHANNEL
SecondWordResponseDataReadItem75 D5745 CHANNEL
SecondWordResponseDataReadItem76 D5755 CHANNEL
SecondWordResponseDataReadItem77 D5765 CHANNEL
SecondWordResponseDataReadItem78 D5775 CHANNEL
SecondWordResponseDataReadItem79 D5785 CHANNEL
SecondWordResponseDataReadItem8 D5075 CHANNEL
SecondWordResponseDataReadItem80 D5795 CHANNEL
SecondWordResponseDataReadItem81 D5805 CHANNEL
SecondWordResponseDataReadItem82 D5815 CHANNEL
SecondWordResponseDataReadItem83 D5825 CHANNEL
SecondWordResponseDataReadItem84 D5835 CHANNEL
SecondWordResponseDataReadItem85 D5845 CHANNEL
SecondWordResponseDataReadItem86 D5855 CHANNEL
SecondWordResponseDataReadItem87 D5865 CHANNEL
SecondWordResponseDataReadItem88 D5875 CHANNEL
SecondWordResponseDataReadItem89 D5885 CHANNEL
SecondWordResponseDataReadItem9 D5085 CHANNEL
SecondWordResponseDataReadItem90 D5895 CHANNEL
SecondWordResponseDataReadItem91 D5905 CHANNEL
SecondWordResponseDataReadItem92 D5915 CHANNEL
SecondWordResponseDataReadItem93 D5925 CHANNEL
SecondWordResponseDataReadItem94 D5935 CHANNEL
SecondWordResponseDataReadItem95 D5945 CHANNEL
SecondWordResponseDataReadItem96 D5955 CHANNEL
SecondWordResponseDataReadItem97 D5965 CHANNEL
SecondWordResponseDataReadItem98 D5975 CHANNEL
SecondWordResponseDataReadItem99 D5985 CHANNEL
SecondWordWriteDataMirrorWriteItem1 D6007 CHANNEL
SecondWordWriteDataMirrorWriteItem10 D6097 CHANNEL
SecondWordWriteDataMirrorWriteItem100 D6997 CHANNEL
SecondWordWriteDataMirrorWriteItem11 D6107 CHANNEL
SecondWordWriteDataMirrorWriteItem12 D6117 CHANNEL
SecondWordWriteDataMirrorWriteItem13 D6127 CHANNEL
SecondWordWriteDataMirrorWriteItem14 D6137 CHANNEL
SecondWordWriteDataMirrorWriteItem15 D6147 CHANNEL
SecondWordWriteDataMirrorWriteItem16 D6157 CHANNEL
SecondWordWriteDataMirrorWriteItem17 D6167 CHANNEL
SecondWordWriteDataMirrorWriteItem18 D6177 CHANNEL
SecondWordWriteDataMirrorWriteItem19 D6187 CHANNEL
SecondWordWriteDataMirrorWriteItem2 D6017 CHANNEL
SecondWordWriteDataMirrorWriteItem20 D6197 CHANNEL
SecondWordWriteDataMirrorWriteItem21 D6207 CHANNEL
SecondWordWriteDataMirrorWriteItem22 D6217 CHANNEL
SecondWordWriteDataMirrorWriteItem23 D6227 CHANNEL
SecondWordWriteDataMirrorWriteItem24 D6237 CHANNEL
SecondWordWriteDataMirrorWriteItem25 D6247 CHANNEL
SecondWordWriteDataMirrorWriteItem26 D6257 CHANNEL
SecondWordWriteDataMirrorWriteItem27 D6267 CHANNEL
SecondWordWriteDataMirrorWriteItem28 D6277 CHANNEL
SecondWordWriteDataMirrorWriteItem29 D6287 CHANNEL
SecondWordWriteDataMirrorWriteItem3 D6027 CHANNEL
SecondWordWriteDataMirrorWriteItem30 D6297 CHANNEL
SecondWordWriteDataMirrorWriteItem31 D6307 CHANNEL
SecondWordWriteDataMirrorWriteItem32 D6317 CHANNEL
SecondWordWriteDataMirrorWriteItem33 D6327 CHANNEL
SecondWordWriteDataMirrorWriteItem34 D6337 CHANNEL
SecondWordWriteDataMirrorWriteItem35 D6347 CHANNEL
SecondWordWriteDataMirrorWriteItem36 D6357 CHANNEL
SecondWordWriteDataMirrorWriteItem37 D6367 CHANNEL
SecondWordWriteDataMirrorWriteItem38 D6377 CHANNEL
SecondWordWriteDataMirrorWriteItem39 D6387 CHANNEL
SecondWordWriteDataMirrorWriteItem4 D6037 CHANNEL
SecondWordWriteDataMirrorWriteItem40 D6397 CHANNEL
SecondWordWriteDataMirrorWriteItem41 D6407 CHANNEL
SecondWordWriteDataMirrorWriteItem42 D6417 CHANNEL
SecondWordWriteDataMirrorWriteItem43 D6427 CHANNEL
SecondWordWriteDataMirrorWriteItem44 D6437 CHANNEL
SecondWordWriteDataMirrorWriteItem45 D6447 CHANNEL
SecondWordWriteDataMirrorWriteItem46 D6457 CHANNEL
SecondWordWriteDataMirrorWriteItem47 D6467 CHANNEL
SecondWordWriteDataMirrorWriteItem48 D6477 CHANNEL
SecondWordWriteDataMirrorWriteItem49 D6487 CHANNEL
SecondWordWriteDataMirrorWriteItem5 D6047 CHANNEL
SecondWordWriteDataMirrorWriteItem50 D6497 CHANNEL
SecondWordWriteDataMirrorWriteItem51 D6507 CHANNEL
SecondWordWriteDataMirrorWriteItem52 D6517 CHANNEL
SecondWordWriteDataMirrorWriteItem53 D6527 CHANNEL
SecondWordWriteDataMirrorWriteItem54 D6537 CHANNEL
SecondWordWriteDataMirrorWriteItem55 D6547 CHANNEL
SecondWordWriteDataMirrorWriteItem56 D6557 CHANNEL
SecondWordWriteDataMirrorWriteItem57 D6567 CHANNEL
SecondWordWriteDataMirrorWriteItem58 D6577 CHANNEL
SecondWordWriteDataMirrorWriteItem59 D6587 CHANNEL
SecondWordWriteDataMirrorWriteItem6 D6057 CHANNEL
SecondWordWriteDataMirrorWriteItem60 D6597 CHANNEL
SecondWordWriteDataMirrorWriteItem61 D6607 CHANNEL
SecondWordWriteDataMirrorWriteItem62 D6617 CHANNEL
SecondWordWriteDataMirrorWriteItem63 D6627 CHANNEL
SecondWordWriteDataMirrorWriteItem64 D6637 CHANNEL
SecondWordWriteDataMirrorWriteItem65 D6647 CHANNEL
SecondWordWriteDataMirrorWriteItem66 D6657 CHANNEL
SecondWordWriteDataMirrorWriteItem67 D6667 CHANNEL
SecondWordWriteDataMirrorWriteItem68 D6677 CHANNEL
SecondWordWriteDataMirrorWriteItem69 D6687 CHANNEL
SecondWordWriteDataMirrorWriteItem7 D6067 CHANNEL
SecondWordWriteDataMirrorWriteItem70 D6697 CHANNEL
SecondWordWriteDataMirrorWriteItem71 D6707 CHANNEL
SecondWordWriteDataMirrorWriteItem72 D6717 CHANNEL
SecondWordWriteDataMirrorWriteItem73 D6727 CHANNEL
SecondWordWriteDataMirrorWriteItem74 D6737 CHANNEL
SecondWordWriteDataMirrorWriteItem75 D6747 CHANNEL
SecondWordWriteDataMirrorWriteItem76 D6757 CHANNEL
SecondWordWriteDataMirrorWriteItem77 D6767 CHANNEL
SecondWordWriteDataMirrorWriteItem78 D6777 CHANNEL
SecondWordWriteDataMirrorWriteItem79 D6787 CHANNEL
SecondWordWriteDataMirrorWriteItem8 D6077 CHANNEL
SecondWordWriteDataMirrorWriteItem80 D6797 CHANNEL
SecondWordWriteDataMirrorWriteItem81 D6807 CHANNEL
SecondWordWriteDataMirrorWriteItem82 D6817 CHANNEL
SecondWordWriteDataMirrorWriteItem83 D6827 CHANNEL
SecondWordWriteDataMirrorWriteItem84 D6837 CHANNEL
SecondWordWriteDataMirrorWriteItem85 D6847 CHANNEL
SecondWordWriteDataMirrorWriteItem86 D6857 CHANNEL
SecondWordWriteDataMirrorWriteItem87 D6867 CHANNEL
SecondWordWriteDataMirrorWriteItem88 D6877 CHANNEL
SecondWordWriteDataMirrorWriteItem89 D6887 CHANNEL
SecondWordWriteDataMirrorWriteItem9 D6087 CHANNEL
SecondWordWriteDataMirrorWriteItem90 D6897 CHANNEL
SecondWordWriteDataMirrorWriteItem91 D6907 CHANNEL
SecondWordWriteDataMirrorWriteItem92 D6917 CHANNEL
SecondWordWriteDataMirrorWriteItem93 D6927 CHANNEL
SecondWordWriteDataMirrorWriteItem94 D6937 CHANNEL
SecondWordWriteDataMirrorWriteItem95 D6947 CHANNEL
SecondWordWriteDataMirrorWriteItem96 D6957 CHANNEL
SecondWordWriteDataMirrorWriteItem97 D6967 CHANNEL
SecondWordWriteDataMirrorWriteItem98 D6977 CHANNEL
SecondWordWriteDataMirrorWriteItem99 D6987 CHANNEL
SecondWordWriteDataWriteItem1 D6005 CHANNEL
SecondWordWriteDataWriteItem10 D6095 CHANNEL
SecondWordWriteDataWriteItem100 D6995 CHANNEL
SecondWordWriteDataWriteItem11 D6105 CHANNEL
SecondWordWriteDataWriteItem12 D6115 CHANNEL
SecondWordWriteDataWriteItem13 D6125 CHANNEL
SecondWordWriteDataWriteItem14 D6135 CHANNEL
SecondWordWriteDataWriteItem15 D6145 CHANNEL
SecondWordWriteDataWriteItem16 D6155 CHANNEL
SecondWordWriteDataWriteItem17 D6165 CHANNEL
SecondWordWriteDataWriteItem18 D6175 CHANNEL
SecondWordWriteDataWriteItem19 D6185 CHANNEL
SecondWordWriteDataWriteItem2 D6015 CHANNEL
SecondWordWriteDataWriteItem20 D6195 CHANNEL
SecondWordWriteDataWriteItem21 D6205 CHANNEL
SecondWordWriteDataWriteItem22 D6215 CHANNEL
SecondWordWriteDataWriteItem23 D6225 CHANNEL
SecondWordWriteDataWriteItem24 D6235 CHANNEL
SecondWordWriteDataWriteItem25 D6245 CHANNEL
SecondWordWriteDataWriteItem26 D6255 CHANNEL
SecondWordWriteDataWriteItem27 D6265 CHANNEL
SecondWordWriteDataWriteItem28 D6275 CHANNEL
SecondWordWriteDataWriteItem29 D6285 CHANNEL
SecondWordWriteDataWriteItem3 D6025 CHANNEL
SecondWordWriteDataWriteItem30 D6295 CHANNEL
SecondWordWriteDataWriteItem31 D6305 CHANNEL
SecondWordWriteDataWriteItem32 D6315 CHANNEL
SecondWordWriteDataWriteItem33 D6325 CHANNEL
SecondWordWriteDataWriteItem34 D6335 CHANNEL
SecondWordWriteDataWriteItem35 D6345 CHANNEL
SecondWordWriteDataWriteItem36 D6355 CHANNEL
SecondWordWriteDataWriteItem37 D6365 CHANNEL
SecondWordWriteDataWriteItem38 D6375 CHANNEL
SecondWordWriteDataWriteItem39 D6385 CHANNEL
SecondWordWriteDataWriteItem4 D6035 CHANNEL
SecondWordWriteDataWriteItem40 D6395 CHANNEL
SecondWordWriteDataWriteItem41 D6405 CHANNEL
SecondWordWriteDataWriteItem42 D6415 CHANNEL
SecondWordWriteDataWriteItem43 D6425 CHANNEL
SecondWordWriteDataWriteItem44 D6435 CHANNEL
SecondWordWriteDataWriteItem45 D6445 CHANNEL
SecondWordWriteDataWriteItem46 D6455 CHANNEL
SecondWordWriteDataWriteItem47 D6465 CHANNEL
SecondWordWriteDataWriteItem48 D6475 CHANNEL
SecondWordWriteDataWriteItem49 D6485 CHANNEL
SecondWordWriteDataWriteItem5 D6045 CHANNEL
SecondWordWriteDataWriteItem50 D6495 CHANNEL
SecondWordWriteDataWriteItem51 D6505 CHANNEL
SecondWordWriteDataWriteItem52 D6515 CHANNEL
SecondWordWriteDataWriteItem53 D6525 CHANNEL
SecondWordWriteDataWriteItem54 D6535 CHANNEL
SecondWordWriteDataWriteItem55 D6545 CHANNEL
SecondWordWriteDataWriteItem56 D6555 CHANNEL
SecondWordWriteDataWriteItem57 D6565 CHANNEL
SecondWordWriteDataWriteItem58 D6575 CHANNEL
SecondWordWriteDataWriteItem59 D6585 CHANNEL
SecondWordWriteDataWriteItem6 D6055 CHANNEL
SecondWordWriteDataWriteItem60 D6595 CHANNEL
SecondWordWriteDataWriteItem61 D6605 CHANNEL
SecondWordWriteDataWriteItem62 D6615 CHANNEL
SecondWordWriteDataWriteItem63 D6625 CHANNEL
SecondWordWriteDataWriteItem64 D6635 CHANNEL
SecondWordWriteDataWriteItem65 D6645 CHANNEL
SecondWordWriteDataWriteItem66 D6655 CHANNEL
SecondWordWriteDataWriteItem67 D6665 CHANNEL
SecondWordWriteDataWriteItem68 D6675 CHANNEL
SecondWordWriteDataWriteItem69 D6685 CHANNEL
SecondWordWriteDataWriteItem7 D6065 CHANNEL
SecondWordWriteDataWriteItem70 D6695 CHANNEL
SecondWordWriteDataWriteItem71 D6705 CHANNEL
SecondWordWriteDataWriteItem72 D6715 CHANNEL
SecondWordWriteDataWriteItem73 D6725 CHANNEL
SecondWordWriteDataWriteItem74 D6735 CHANNEL
SecondWordWriteDataWriteItem75 D6745 CHANNEL
SecondWordWriteDataWriteItem76 D6755 CHANNEL
SecondWordWriteDataWriteItem77 D6765 CHANNEL
SecondWordWriteDataWriteItem78 D6775 CHANNEL
SecondWordWriteDataWriteItem79 D6785 CHANNEL
SecondWordWriteDataWriteItem8 D6075 CHANNEL
SecondWordWriteDataWriteItem80 D6795 CHANNEL
SecondWordWriteDataWriteItem81 D6805 CHANNEL
SecondWordWriteDataWriteItem82 D6815 CHANNEL
SecondWordWriteDataWriteItem83 D6825 CHANNEL
SecondWordWriteDataWriteItem84 D6835 CHANNEL
SecondWordWriteDataWriteItem85 D6845 CHANNEL
SecondWordWriteDataWriteItem86 D6855 CHANNEL
SecondWordWriteDataWriteItem87 D6865 CHANNEL
SecondWordWriteDataWriteItem88 D6875 CHANNEL
SecondWordWriteDataWriteItem89 D6885 CHANNEL
SecondWordWriteDataWriteItem9 D6085 CHANNEL
SecondWordWriteDataWriteItem90 D6895 CHANNEL
SecondWordWriteDataWriteItem91 D6905 CHANNEL
SecondWordWriteDataWriteItem92 D6915 CHANNEL
SecondWordWriteDataWriteItem93 D6925 CHANNEL
SecondWordWriteDataWriteItem94 D6935 CHANNEL
SecondWordWriteDataWriteItem95 D6945 CHANNEL
SecondWordWriteDataWriteItem96 D6955 CHANNEL
SecondWordWriteDataWriteItem97 D6965 CHANNEL
SecondWordWriteDataWriteItem98 D6975 CHANNEL
SecondWordWriteDataWriteItem99 D6985 CHANNEL
SerialPortReset A526.00 BOOL
SerialPortResetCounter W207 INT
Stack_Empty W205.00 BOOL
Stack_Full_Diagnostic_Bit W215.04 BOOL
Stack_Start W0 DWORD
StartingModbusAddressReadItem1 D5002 CHANNEL
StartingModbusAddressReadItem10 D5092 CHANNEL
StartingModbusAddressReadItem100 D5992 CHANNEL
StartingModbusAddressReadItem11 D5102 CHANNEL
StartingModbusAddressReadItem12 D5112 CHANNEL
StartingModbusAddressReadItem13 D5122 CHANNEL
StartingModbusAddressReadItem14 D5132 CHANNEL
StartingModbusAddressReadItem15 D5142 CHANNEL
StartingModbusAddressReadItem16 D5152 CHANNEL
StartingModbusAddressReadItem17 D5162 CHANNEL
StartingModbusAddressReadItem18 D5172 CHANNEL
StartingModbusAddressReadItem19 D5182 CHANNEL
StartingModbusAddressReadItem2 D5012 CHANNEL
StartingModbusAddressReadItem20 D5192 CHANNEL
StartingModbusAddressReadItem21 D5202 CHANNEL
StartingModbusAddressReadItem22 D5212 CHANNEL
StartingModbusAddressReadItem23 D5222 CHANNEL
StartingModbusAddressReadItem24 D5232 CHANNEL
StartingModbusAddressReadItem25 D5242 CHANNEL
StartingModbusAddressReadItem26 D5252 CHANNEL
StartingModbusAddressReadItem27 D5262 CHANNEL
StartingModbusAddressReadItem28 D5272 CHANNEL
StartingModbusAddressReadItem29 D5282 CHANNEL
StartingModbusAddressReadItem3 D5022 CHANNEL
StartingModbusAddressReadItem30 D5292 CHANNEL
StartingModbusAddressReadItem31 D5302 CHANNEL
StartingModbusAddressReadItem32 D5312 CHANNEL
StartingModbusAddressReadItem33 D5322 CHANNEL
StartingModbusAddressReadItem34 D5332 CHANNEL
StartingModbusAddressReadItem35 D5342 CHANNEL
StartingModbusAddressReadItem36 D5352 CHANNEL
StartingModbusAddressReadItem37 D5362 CHANNEL
StartingModbusAddressReadItem38 D5372 CHANNEL
StartingModbusAddressReadItem39 D5382 CHANNEL
StartingModbusAddressReadItem4 D5032 CHANNEL
StartingModbusAddressReadItem40 D5392 CHANNEL
StartingModbusAddressReadItem41 D5402 CHANNEL
StartingModbusAddressReadItem42 D5412 CHANNEL
StartingModbusAddressReadItem43 D5422 CHANNEL
StartingModbusAddressReadItem44 D5432 CHANNEL
StartingModbusAddressReadItem45 D5442 CHANNEL
StartingModbusAddressReadItem46 D5452 CHANNEL
StartingModbusAddressReadItem47 D5462 CHANNEL
StartingModbusAddressReadItem48 D5472 CHANNEL
StartingModbusAddressReadItem49 D5482 CHANNEL
StartingModbusAddressReadItem5 D5042 CHANNEL
StartingModbusAddressReadItem50 D5492 CHANNEL
StartingModbusAddressReadItem51 D5502 CHANNEL
StartingModbusAddressReadItem52 D5512 CHANNEL
StartingModbusAddressReadItem53 D5522 CHANNEL
StartingModbusAddressReadItem54 D5532 CHANNEL
StartingModbusAddressReadItem55 D5542 CHANNEL
StartingModbusAddressReadItem56 D5552 CHANNEL
StartingModbusAddressReadItem57 D5562 CHANNEL
StartingModbusAddressReadItem58 D5572 CHANNEL
StartingModbusAddressReadItem59 D5582 CHANNEL
StartingModbusAddressReadItem6 D5052 CHANNEL
StartingModbusAddressReadItem60 D5592 CHANNEL
StartingModbusAddressReadItem61 D5602 CHANNEL
StartingModbusAddressReadItem62 D5612 CHANNEL
StartingModbusAddressReadItem63 D5622 CHANNEL
StartingModbusAddressReadItem64 D5632 CHANNEL
StartingModbusAddressReadItem65 D5642 CHANNEL
StartingModbusAddressReadItem66 D5652 CHANNEL
StartingModbusAddressReadItem67 D5662 CHANNEL
StartingModbusAddressReadItem68 D5672 CHANNEL
StartingModbusAddressReadItem69 D5682 CHANNEL
StartingModbusAddressReadItem7 D5062 CHANNEL
StartingModbusAddressReadItem70 D5692 CHANNEL
StartingModbusAddressReadItem71 D5702 CHANNEL
StartingModbusAddressReadItem72 D5712 CHANNEL
StartingModbusAddressReadItem73 D5722 CHANNEL
StartingModbusAddressReadItem74 D5732 CHANNEL
StartingModbusAddressReadItem75 D5742 CHANNEL
StartingModbusAddressReadItem76 D5752 CHANNEL
StartingModbusAddressReadItem77 D5762 CHANNEL
StartingModbusAddressReadItem78 D5772 CHANNEL
StartingModbusAddressReadItem79 D5782 CHANNEL
StartingModbusAddressReadItem8 D5072 CHANNEL
StartingModbusAddressReadItem80 D5792 CHANNEL
StartingModbusAddressReadItem81 D5802 CHANNEL
StartingModbusAddressReadItem82 D5812 CHANNEL
StartingModbusAddressReadItem83 D5822 CHANNEL
StartingModbusAddressReadItem84 D5832 CHANNEL
StartingModbusAddressReadItem85 D5842 CHANNEL
StartingModbusAddressReadItem86 D5852 CHANNEL
StartingModbusAddressReadItem87 D5862 CHANNEL
StartingModbusAddressReadItem88 D5872 CHANNEL
StartingModbusAddressReadItem89 D5882 CHANNEL
StartingModbusAddressReadItem9 D5082 CHANNEL
StartingModbusAddressReadItem90 D5892 CHANNEL
StartingModbusAddressReadItem91 D5902 CHANNEL
StartingModbusAddressReadItem92 D5912 CHANNEL
StartingModbusAddressReadItem93 D5922 CHANNEL
StartingModbusAddressReadItem94 D5932 CHANNEL
StartingModbusAddressReadItem95 D5942 CHANNEL
StartingModbusAddressReadItem96 D5952 CHANNEL
StartingModbusAddressReadItem97 D5962 CHANNEL
StartingModbusAddressReadItem98 D5972 CHANNEL
StartingModbusAddressReadItem99 D5982 CHANNEL
StartingModbusAddressWriteItem1 D6002 CHANNEL
StartingModbusAddressWriteItem10 D6092 CHANNEL
StartingModbusAddressWriteItem100 D6992 CHANNEL
StartingModbusAddressWriteItem11 D6102 CHANNEL
StartingModbusAddressWriteItem12 D6112 CHANNEL
StartingModbusAddressWriteItem13 D6122 CHANNEL
StartingModbusAddressWriteItem14 D6132 CHANNEL
StartingModbusAddressWriteItem15 D6142 CHANNEL
StartingModbusAddressWriteItem16 D6152 CHANNEL
StartingModbusAddressWriteItem17 D6162 CHANNEL
StartingModbusAddressWriteItem18 D6172 CHANNEL
StartingModbusAddressWriteItem19 D6182 CHANNEL
StartingModbusAddressWriteItem2 D6012 CHANNEL
StartingModbusAddressWriteItem20 D6192 CHANNEL
StartingModbusAddressWriteItem21 D6202 CHANNEL
StartingModbusAddressWriteItem22 D6212 CHANNEL
StartingModbusAddressWriteItem23 D6222 CHANNEL
StartingModbusAddressWriteItem24 D6232 CHANNEL
StartingModbusAddressWriteItem25 D6242 CHANNEL
StartingModbusAddressWriteItem26 D6252 CHANNEL
StartingModbusAddressWriteItem27 D6262 CHANNEL
StartingModbusAddressWriteItem28 D6272 CHANNEL
StartingModbusAddressWriteItem29 D6282 CHANNEL
StartingModbusAddressWriteItem3 D6022 CHANNEL
StartingModbusAddressWriteItem30 D6292 CHANNEL
StartingModbusAddressWriteItem31 D6302 CHANNEL
StartingModbusAddressWriteItem32 D6312 CHANNEL
StartingModbusAddressWriteItem33 D6322 CHANNEL
StartingModbusAddressWriteItem34 D6332 CHANNEL
StartingModbusAddressWriteItem35 D6342 CHANNEL
StartingModbusAddressWriteItem36 D6352 CHANNEL
StartingModbusAddressWriteItem37 D6362 CHANNEL
StartingModbusAddressWriteItem38 D6372 CHANNEL
StartingModbusAddressWriteItem39 D6382 CHANNEL
StartingModbusAddressWriteItem4 D6032 CHANNEL
StartingModbusAddressWriteItem40 D6392 CHANNEL
StartingModbusAddressWriteItem41 D6402 CHANNEL
StartingModbusAddressWriteItem42 D6412 CHANNEL
StartingModbusAddressWriteItem43 D6422 CHANNEL
StartingModbusAddressWriteItem44 D6432 CHANNEL
StartingModbusAddressWriteItem45 D6442 CHANNEL
StartingModbusAddressWriteItem46 D6452 CHANNEL
StartingModbusAddressWriteItem47 D6462 CHANNEL
StartingModbusAddressWriteItem48 D6472 CHANNEL
StartingModbusAddressWriteItem49 D6482 CHANNEL
StartingModbusAddressWriteItem5 D6042 CHANNEL
StartingModbusAddressWriteItem50 D6492 CHANNEL
StartingModbusAddressWriteItem51 D6502 CHANNEL
StartingModbusAddressWriteItem52 D6512 CHANNEL
StartingModbusAddressWriteItem53 D6522 CHANNEL
StartingModbusAddressWriteItem54 D6532 CHANNEL
StartingModbusAddressWriteItem55 D6542 CHANNEL
StartingModbusAddressWriteItem56 D6552 CHANNEL
StartingModbusAddressWriteItem57 D6562 CHANNEL
StartingModbusAddressWriteItem58 D6572 CHANNEL
StartingModbusAddressWriteItem59 D6582 CHANNEL
StartingModbusAddressWriteItem6 D6052 CHANNEL
StartingModbusAddressWriteItem60 D6592 CHANNEL
StartingModbusAddressWriteItem61 D6602 CHANNEL
StartingModbusAddressWriteItem62 D6612 CHANNEL
StartingModbusAddressWriteItem63 D6622 CHANNEL
StartingModbusAddressWriteItem64 D6632 CHANNEL
StartingModbusAddressWriteItem65 D6642 CHANNEL
StartingModbusAddressWriteItem66 D6652 CHANNEL
StartingModbusAddressWriteItem67 D6662 CHANNEL
StartingModbusAddressWriteItem68 D6672 CHANNEL
StartingModbusAddressWriteItem69 D6682 CHANNEL
StartingModbusAddressWriteItem7 D6062 CHANNEL
StartingModbusAddressWriteItem70 D6692 CHANNEL
StartingModbusAddressWriteItem71 D6702 CHANNEL
StartingModbusAddressWriteItem72 D6712 CHANNEL
StartingModbusAddressWriteItem73 D6722 CHANNEL
StartingModbusAddressWriteItem74 D6732 CHANNEL
StartingModbusAddressWriteItem75 D6742 CHANNEL
StartingModbusAddressWriteItem76 D6752 CHANNEL
StartingModbusAddressWriteItem77 D6762 CHANNEL
StartingModbusAddressWriteItem78 D6772 CHANNEL
StartingModbusAddressWriteItem79 D6782 CHANNEL
StartingModbusAddressWriteItem8 D6072 CHANNEL
StartingModbusAddressWriteItem80 D6792 CHANNEL
StartingModbusAddressWriteItem81 D6802 CHANNEL
StartingModbusAddressWriteItem82 D6812 CHANNEL
StartingModbusAddressWriteItem83 D6822 CHANNEL
StartingModbusAddressWriteItem84 D6832 CHANNEL
StartingModbusAddressWriteItem85 D6842 CHANNEL
StartingModbusAddressWriteItem86 D6852 CHANNEL
StartingModbusAddressWriteItem87 D6862 CHANNEL
StartingModbusAddressWriteItem88 D6872 CHANNEL
StartingModbusAddressWriteItem89 D6882 CHANNEL
StartingModbusAddressWriteItem9 D6082 CHANNEL
StartingModbusAddressWriteItem90 D6892 CHANNEL
StartingModbusAddressWriteItem91 D6902 CHANNEL
StartingModbusAddressWriteItem92 D6912 CHANNEL
StartingModbusAddressWriteItem93 D6922 CHANNEL
StartingModbusAddressWriteItem94 D6932 CHANNEL
StartingModbusAddressWriteItem95 D6942 CHANNEL
StartingModbusAddressWriteItem96 D6952 CHANNEL
StartingModbusAddressWriteItem97 D6962 CHANNEL
StartingModbusAddressWriteItem98 D6972 CHANNEL
StartingModbusAddressWriteItem99 D6982 CHANNEL
TemporaryCommDataBytes W212 CHANNEL
TemporaryFIFOArea W211 CHANNEL
TemporaryStartingDMErrorLocation W218 DWORD
Temporary_Pointer_For_Stack_Push W210 DWORD
TimeoutRetryCounter W208 CHANNEL
Top_Of_Stack W202 DWORD
WriteValidOrInvalidWriteItem1 D6008 CHANNEL
WriteValidOrInvalidWriteItem10 D6098 CHANNEL
WriteValidOrInvalidWriteItem100 D6998 CHANNEL
WriteValidOrInvalidWriteItem11 D6108 CHANNEL
WriteValidOrInvalidWriteItem12 D6118 CHANNEL
WriteValidOrInvalidWriteItem13 D6128 CHANNEL
WriteValidOrInvalidWriteItem14 D6138 CHANNEL
WriteValidOrInvalidWriteItem15 D6148 CHANNEL
WriteValidOrInvalidWriteItem16 D6158 CHANNEL
WriteValidOrInvalidWriteItem17 D6168 CHANNEL
WriteValidOrInvalidWriteItem18 D6178 CHANNEL
WriteValidOrInvalidWriteItem19 D6188 CHANNEL
WriteValidOrInvalidWriteItem2 D6018 CHANNEL
WriteValidOrInvalidWriteItem20 D6198 CHANNEL
WriteValidOrInvalidWriteItem21 D6208 CHANNEL
WriteValidOrInvalidWriteItem22 D6218 CHANNEL
WriteValidOrInvalidWriteItem23 D6228 CHANNEL
WriteValidOrInvalidWriteItem24 D6238 CHANNEL
WriteValidOrInvalidWriteItem25 D6248 CHANNEL
WriteValidOrInvalidWriteItem26 D6258 CHANNEL
WriteValidOrInvalidWriteItem27 D6268 CHANNEL
WriteValidOrInvalidWriteItem28 D6278 CHANNEL
WriteValidOrInvalidWriteItem29 D6288 CHANNEL
WriteValidOrInvalidWriteItem3 D6028 CHANNEL
WriteValidOrInvalidWriteItem30 D6298 CHANNEL
WriteValidOrInvalidWriteItem31 D6308 CHANNEL
WriteValidOrInvalidWriteItem32 D6318 CHANNEL
WriteValidOrInvalidWriteItem33 D6328 CHANNEL
WriteValidOrInvalidWriteItem34 D6338 CHANNEL
WriteValidOrInvalidWriteItem35 D6348 CHANNEL
WriteValidOrInvalidWriteItem36 D6358 CHANNEL
WriteValidOrInvalidWriteItem37 D6368 CHANNEL
WriteValidOrInvalidWriteItem38 D6378 CHANNEL
WriteValidOrInvalidWriteItem39 D6388 CHANNEL
WriteValidOrInvalidWriteItem4 D6038 CHANNEL
WriteValidOrInvalidWriteItem40 D6398 CHANNEL
WriteValidOrInvalidWriteItem41 D6408 CHANNEL
WriteValidOrInvalidWriteItem42 D6418 CHANNEL
WriteValidOrInvalidWriteItem43 D6428 CHANNEL
WriteValidOrInvalidWriteItem44 D6438 CHANNEL
WriteValidOrInvalidWriteItem45 D6448 CHANNEL
WriteValidOrInvalidWriteItem46 D6458 CHANNEL
WriteValidOrInvalidWriteItem47 D6468 CHANNEL
WriteValidOrInvalidWriteItem48 D6478 CHANNEL
WriteValidOrInvalidWriteItem49 D6488 CHANNEL
WriteValidOrInvalidWriteItem5 D6048 CHANNEL
WriteValidOrInvalidWriteItem50 D6498 CHANNEL
WriteValidOrInvalidWriteItem51 D6508 CHANNEL
WriteValidOrInvalidWriteItem52 D6518 CHANNEL
WriteValidOrInvalidWriteItem53 D6528 CHANNEL
WriteValidOrInvalidWriteItem54 D6538 CHANNEL
WriteValidOrInvalidWriteItem55 D6548 CHANNEL
WriteValidOrInvalidWriteItem56 D6558 CHANNEL
WriteValidOrInvalidWriteItem57 D6568 CHANNEL
WriteValidOrInvalidWriteItem58 D6578 CHANNEL
WriteValidOrInvalidWriteItem59 D6588 CHANNEL
WriteValidOrInvalidWriteItem6 D6058 CHANNEL
WriteValidOrInvalidWriteItem60 D6598 CHANNEL
WriteValidOrInvalidWriteItem61 D6608 CHANNEL
WriteValidOrInvalidWriteItem62 D6618 CHANNEL
WriteValidOrInvalidWriteItem63 D6628 CHANNEL
WriteValidOrInvalidWriteItem64 D6638 CHANNEL
WriteValidOrInvalidWriteItem65 D6648 CHANNEL
WriteValidOrInvalidWriteItem66 D6658 CHANNEL
WriteValidOrInvalidWriteItem67 D6668 CHANNEL
WriteValidOrInvalidWriteItem68 D6678 CHANNEL
WriteValidOrInvalidWriteItem69 D6688 CHANNEL
WriteValidOrInvalidWriteItem7 D6068 CHANNEL
WriteValidOrInvalidWriteItem70 D6698 CHANNEL
WriteValidOrInvalidWriteItem71 D6708 CHANNEL
WriteValidOrInvalidWriteItem72 D6718 CHANNEL
WriteValidOrInvalidWriteItem73 D6728 CHANNEL
WriteValidOrInvalidWriteItem74 D6738 CHANNEL
WriteValidOrInvalidWriteItem75 D6748 CHANNEL
WriteValidOrInvalidWriteItem76 D6758 CHANNEL
WriteValidOrInvalidWriteItem77 D6768 CHANNEL
WriteValidOrInvalidWriteItem78 D6778 CHANNEL
WriteValidOrInvalidWriteItem79 D6788 CHANNEL
WriteValidOrInvalidWriteItem8 D6078 CHANNEL
WriteValidOrInvalidWriteItem80 D6798 CHANNEL
WriteValidOrInvalidWriteItem81 D6808 CHANNEL
WriteValidOrInvalidWriteItem82 D6818 CHANNEL
WriteValidOrInvalidWriteItem83 D6828 CHANNEL
WriteValidOrInvalidWriteItem84 D6838 CHANNEL
WriteValidOrInvalidWriteItem85 D6848 CHANNEL
WriteValidOrInvalidWriteItem86 D6858 CHANNEL
WriteValidOrInvalidWriteItem87 D6868 CHANNEL
WriteValidOrInvalidWriteItem88 D6878 CHANNEL
WriteValidOrInvalidWriteItem89 D6888 CHANNEL
WriteValidOrInvalidWriteItem9 D6088 CHANNEL
WriteValidOrInvalidWriteItem90 D6898 CHANNEL
WriteValidOrInvalidWriteItem91 D6908 CHANNEL
WriteValidOrInvalidWriteItem92 D6918 CHANNEL
WriteValidOrInvalidWriteItem93 D6928 CHANNEL
WriteValidOrInvalidWriteItem94 D6938 CHANNEL
WriteValidOrInvalidWriteItem95 D6948 CHANNEL
WriteValidOrInvalidWriteItem96 D6958 CHANNEL
WriteValidOrInvalidWriteItem97 D6968 CHANNEL
WriteValidOrInvalidWriteItem98 D6978 CHANNEL
WriteValidOrInvalidWriteItem99 D6988 CHANNEL

## Program NewProgram1 (cyclic task 10)

### Section Initilization

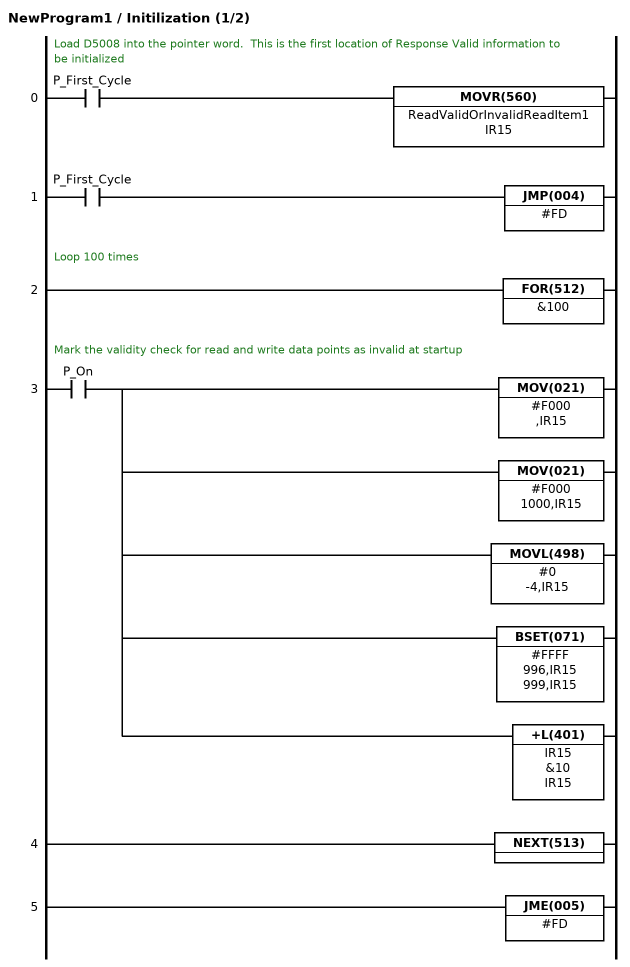
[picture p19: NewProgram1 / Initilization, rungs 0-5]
; rung 0: Load D5008 into the pointer word.  This is the first location of Response Valid information to be initialized
LD P_First_Cycle
MOVR(560) ReadValidOrInvalidReadItem1 IR15
; rung 1
LD P_First_Cycle
JMP(004) #FD
; rung 2: Loop 100 times
FOR(512) &100
; rung 3: Mark the validity check for read and write data points as invalid at startup
LD P_On
MOV(021) #F000 ,IR15  // Mark each Read Validity check as invalid
MOV(021) #F000 1000,IR15  // Mark each Write Validity check as invalid
MOVL(498) #0 -4,IR15  // Clear the 'Read Data' so that it is not stale
BSET(071) #FFFF 996,IR15 999,IR15  // Set the Write Data and 'Last Write Data' to FFFF.  This allows Zero to be accepted as new data on startup.
+L(401) IR15 &10 IR15  // Pointer increment
; rung 4
NEXT(513)
; rung 5
JME(005) #FD

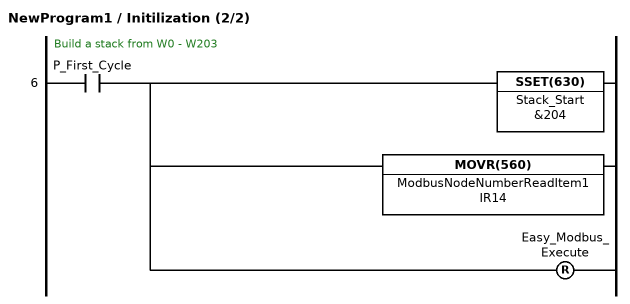
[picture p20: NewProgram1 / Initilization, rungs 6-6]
; rung 6: Build a stack from W0 - W203
LD P_First_Cycle
SSET(630) Stack_Start &204
MOVR(560) ModbusNodeNumberReadItem1 IR14  // Load DM5000 into IR 14.  This is the pointer for walking through the list of items to poll
RSET Easy_Modbus_Execute  // Turn off the Easy Modbus bit in case it was left on

### Section PortError

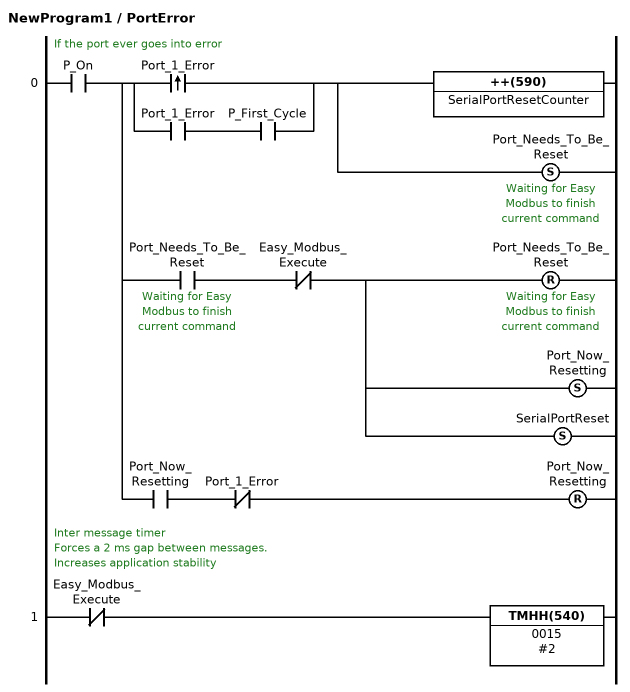
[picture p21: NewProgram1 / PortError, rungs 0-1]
; rung 0: If the port ever goes into error
LD P_On
OUT TR0
@LD Port_1_Error  // When an error occurs on the serial port
LD Port_1_Error  // Or there is an error when the PLC starts up
AND P_First_Cycle
ORLD
ANDLD
++(590) SerialPortResetCounter
SET Port_Needs_To_Be_Reset  ; Waiting for Easy Modbus to finish current command  // Hold Everything back
LD TR0
AND Port_Needs_To_Be_Reset  ; Waiting for Easy Modbus to finish current command
ANDNOT Easy_Modbus_Execute
RSET Port_Needs_To_Be_Reset  ; Waiting for Easy Modbus to finish current command
SET Port_Now_Resetting
SET SerialPortReset
LD TR0
AND Port_Now_Resetting  // If the port is resetting
ANDNOT Port_1_Error  // and there is no longer an error
RSET Port_Now_Resetting  // Then the reset process is complete
; rung 1: Inter message timer / Forces a 2 ms gap between messages. / Increases application stability
LDNOT Easy_Modbus_Execute
TMHH(540) 0015 #2

### Section Stack_Population

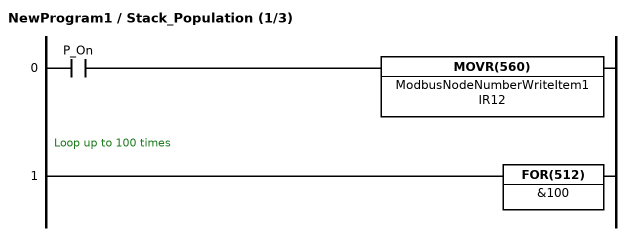
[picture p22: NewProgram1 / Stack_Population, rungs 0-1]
; rung 0
LD P_On
MOVR(560) ModbusNodeNumberWriteItem1 IR12
; rung 1: Loop up to 100 times
FOR(512) &100

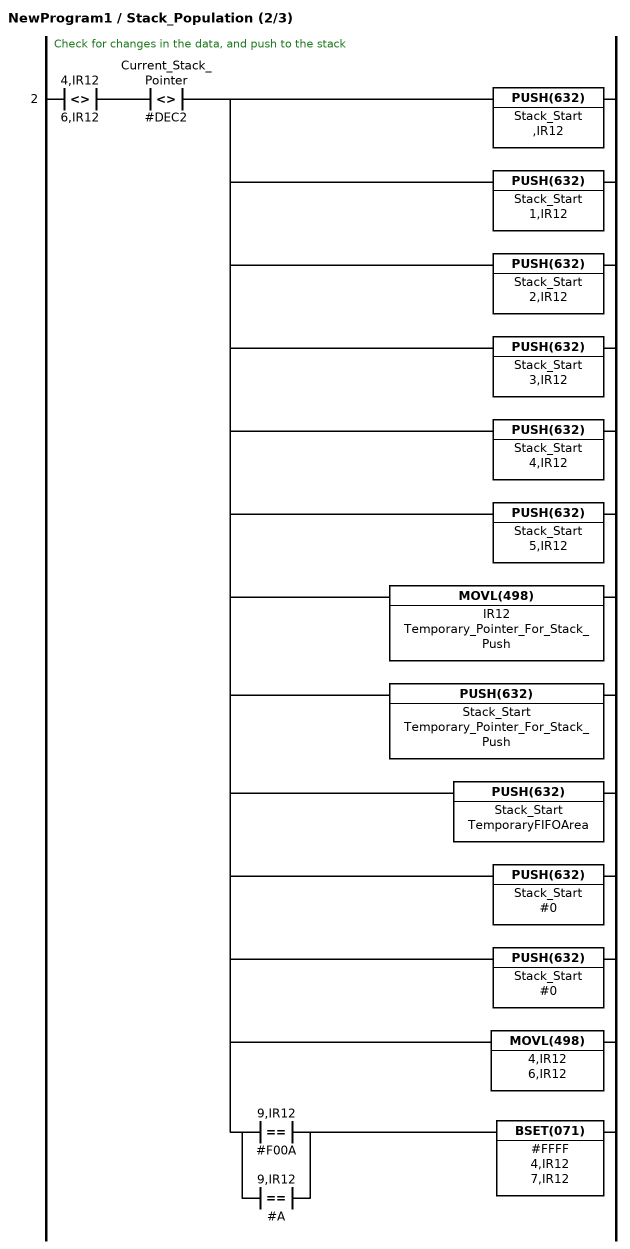
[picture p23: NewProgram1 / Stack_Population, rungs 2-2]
; rung 2: Check for changes in the data, and push to the stack
LD<>L(306) 4,IR12 6,IR12
AND<>L(306) Current_Stack_Pointer #DEC2  // If the stack pointer is not at the top.  This prevents data loss if the stack is full
PUSH(632) Stack_Start ,IR12  // Push the Node Number
PUSH(632) Stack_Start 1,IR12  // Push the Function code
PUSH(632) Stack_Start 2,IR12  // Push the Start Address
PUSH(632) Stack_Start 3,IR12  // Push the Number of Points to Write
PUSH(632) Stack_Start 4,IR12  // Push the first word of data
PUSH(632) Stack_Start 5,IR12  // Push the second word of data
MOVL(498) IR12 Temporary_Pointer_For_Stack_Push  // Copy the pointer out to a temporary area so it can be pushed onto a stack
PUSH(632) Stack_Start Temporary_Pointer_For_Stack_Push  // Push the low address of the return address
PUSH(632) Stack_Start TemporaryFIFOArea  // Push the High address of the return address
PUSH(632) Stack_Start #0  // Pad with 0 for consistancy
PUSH(632) Stack_Start #0  // Pad with 0 for consistancy
MOVL(498) 4,IR12 6,IR12  // Copy this data to the 'last data written'
LD=(300) 9,IR12 #F00A  // End of List with auto clearing option
OR=(300) 9,IR12 #A  // Auto Clearing Option
ANDLD
BSET(071) #FFFF 4,IR12 7,IR12  // Write the data and 'last data written' to FFFF

; rung 3: If this is marked as the end, break out of the loop
LD>=(325) 9,IR12 #F000
BREAK(514)
; rung 4: Increment to the next item
LD P_On
+L(401) IR12 &10 IR12
; rung 5
NEXT(513)
; rung 6: Diagnostic bit for Stack Full
LD=L(301) Current_Stack_Pointer #DEC2  // If the stack pointer is not at the top.  This prevents data loss if the stack is full
OUT Stack_Full_Diagnostic_Bit

### Section Stack_Empty_Check

; rung 0
LD=L(301) Current_Stack_Pointer #DE04  // If the stack pointer is at W4, then the stack is empty
OUT Stack_Empty

### Section Write

; rung 0
LD T0015
LD<=(315) Consecutive_Writes &5  // If 5 or fewer consecutve writes have occurred
OR=(300) EndOfListMarkerReadItem1 #E000  // or if there are no read items in this application
ANDLD
ANDNOT Stack_Empty
ANDNOT Easy_Modbus_Execute
%ANDNOT Easy_Modbus_Execute
ANDNOT Retry_Send_Delay  // And there is not a retry waiting to be sent
ANDNOT Port_Needs_To_Be_Reset  ; Waiting for Easy Modbus to finish current command  // If Port 1 is not recovering from an error
ANDNOT Port_Now_Resetting  // if the port is not resetting
JMP(004) #FE
; rung 1: Clear the Easy Modbus send and recieve areas.  This is mostly for better troubleshooting
LD P_On
BSET(071) #0 EasyModbusPort1Command1 D32349
BSET(071) #0 EasyModbusPort1Response1 D32399

; rung 2: For any function code, populate the 'Node Number',  ' Function Code', Omron 'Number of bytes to send', and Starting Modbus Address
LD P_On
OUT TR0
FIFO(633) Stack_Start EasyModbusPort1Command1  // FIFO the Node Number
FIFO(633) Stack_Start EasyModbusPort1Command2  // FIFO the Function Code
FIFO(633) Stack_Start EasyModbusPort1Command4  // FIFO the Starting Address
FIFO(633) Stack_Start TemporaryFIFOArea  // FIFO the Number of Items to Write
LD=(300) EasyModbusPort1Command2 #5  // If the function code is a 5
OR=(300) EasyModbusPort1Command2 #6  // or if the function code is a 6
ANDLD
MOV(021) #4 TemporaryCommDataBytes  // Move 2 BYTES of Data for the Omron Easy Modbus Function
LD TR0
AND=(300) EasyModbusPort1Command2 #10  // If the function code is a 10
OUT TR1
AND=(300) TemporaryFIFOArea #1
MOV(021) #7 TemporaryCommDataBytes
LD TR1
AND=(300) TemporaryFIFOArea #2
MOV(021) #9 TemporaryCommDataBytes
LD TR0
AND=(300) EasyModbusPort1Command2 #F  // If the function code is a 10
OUT TR1
AND<=(315) TemporaryFIFOArea #F  // If the number of COILS to be written is less than or equal to 16 (0F) then this would be 1 word of data
MOV(021) #7 TemporaryCommDataBytes
LD TR1
AND>(320) TemporaryFIFOArea #F  // If the number of COILS to be written is more than 16 (0F), then this is 2 words of data.  Up to 32 (20 HEX) coils are supported
MOV(021) #9 TemporaryCommDataBytes
LD TR0
MOV(021) TemporaryCommDataBytes EasyModbusPort1Command3  // Move the 'Omron Number of COMM Bytes'
; rung 3: If necessary, write the number of Modbus Bytes
LD=(300) EasyModbusPort1Command2 #F  // If the function code is 0F
OR=(300) EasyModbusPort1Command2 #10  // If the function code is 10
OUT TR0
AND=(300) EasyModbusPort1Command3 #7  // If the Omron Byte Count = 3, then this is 1 register
MOV(021) #200 EasyModbusPort1Command6  // Then 2 Bytes of Modbus data are to be sent
LD TR0
AND=(300) EasyModbusPort1Command3 #9  // If the Omron Byte Count = 3, then this is 1 register
MOV(021) #400 EasyModbusPort1Command6  // Then 4 Bytes of Modbus data are to be sent
LD TR0
MOV(021) TemporaryFIFOArea EasyModbusPort1Command5  // Write the number of Modbus Registers or Coils to Write

; rung 4: FIFO the Data to send
LD P_On
OUT TR0
FIFO(633) Stack_Start TemporaryFIFOArea  // FIFO the First Data Word
LD=(300) EasyModbusPort1Command2 #5  // If the function code is a 5
OR=(300) EasyModbusPort1Command2 #6  // or if the function code is a 6
ANDLD
MOV(021) TemporaryFIFOArea EasyModbusPort1Command5  // Move the First Word of Data
LD TR0
LD=(300) EasyModbusPort1Command2 #10  // If the function code is a 10
OR=(300) EasyModbusPort1Command2 #F  // If the function code is a 10
ANDLD
MOVD(083) TemporaryFIFOArea #12 EasyModbusPort1Command6
MOVD(083) TemporaryFIFOArea #210 EasyModbusPort1Command7
LD TR0
FIFO(633) Stack_Start TemporaryFIFOArea  // FIFO the First Data Word
LD=(300) EasyModbusPort1Command2 #5  // If the function code is a 5
OR=(300) EasyModbusPort1Command2 #6  // or if the function code is a 6
ANDLD
MOV(021) TemporaryFIFOArea EasyModbusPort1Command6  // Move the First Word of Data
LD TR0
LD=(300) EasyModbusPort1Command2 #10  // If the function code is a 10
OR=(300) EasyModbusPort1Command2 #F  // If the function code is a 10
ANDLD
MOVD(083) TemporaryFIFOArea #12 EasyModbusPort1Command7
MOVD(083) TemporaryFIFOArea #210 EasyModbusPort1Command8

; rung 5: FIFO the return address and pad the last 2 FIFOs
LD P_On
FIFO(633) Stack_Start Temporary_Pointer_For_Stack_Push
FIFO(633) Stack_Start TemporaryFIFOArea
MOVL(498) Temporary_Pointer_For_Stack_Push IR13  // Create the Return Address
FIFO(633) Stack_Start TemporaryFIFOArea  // FIFO for stack consistency
FIFO(633) Stack_Start TemporaryFIFOArea  // FIFO for stack consistency
; rung 6: As long as the function code is supported by this application, send the Modbus command
LD=(300) EasyModbusPort1Command2 #5  // If the function code is a 5
OR=(300) EasyModbusPort1Command2 #6  // or if the function code is a 6
OR=(300) EasyModbusPort1Command2 #10  // If the function code is a 10
OR=(300) EasyModbusPort1Command2 #F  // If the function code is a 10
SET Easy_Modbus_Execute
; rung 7: If this is not a supported Modbus Function Code, log it.
LDNOT Easy_Modbus_Execute
SET LogAnEasyModbusError
MOV(021) #FFFF 8,IR13  // Mark the Response OK with an FFFF for BAD DATA
; rung 8: Add 1 to the count of consecutive writes. / This is to allow polling, at a slower rate, when the writes try to overwhelm the comms
LD<>(305) EndOfListMarkerReadItem1 #E000  // If there are read items in this application
++(590) Consecutive_Writes

; rung 9
JME(005) #FE

### Section Polling

; rung 0
LD T0015
AND<>(305) EndOfListMarkerReadItem1 #E000  // If there are Read Items in this application
LD Stack_Empty  // If the stack is empty
OR>(320) Consecutive_Writes #5  // or waiting to perform a read after 5 consecutive writes
ANDLD
ANDNOT Easy_Modbus_Execute
%ANDNOT Easy_Modbus_Execute
ANDNOT Retry_Send_Delay  // And there is not a retry waiting to be sent
ANDNOT Port_Needs_To_Be_Reset  ; Waiting for Easy Modbus to finish current command  // If Port 1 is not recovering from an error
ANDNOT Port_Now_Resetting  // if the port is not resetting
JMP(004) #FF  // Run the code to send a request
; rung 1: Clear the Easy Modbus send and recieve areas.  This is mostly for better troubleshooting
LD P_On
BSET(071) #0 EasyModbusPort1Command1 D32349
BSET(071) #0 EasyModbusPort1Response1 D32399
; rung 2: Functions 01 (read coil status) ,02 (Read Input Status), 03 (Read Holding Registers), and 04 (Read Input Registers)
LD P_On
MOV(021) ,IR14 EasyModbusPort1Command1  // Move the node number
MOV(021) 1,IR14 EasyModbusPort1Command2  // Move the Function Code
MOV(021) &4 EasyModbusPort1Command3  // Set the number of BYTES of data FOR OMRON FUNCTION
MOV(021) 2,IR14 EasyModbusPort1Command4  // Move the starting address
MOV(021) 3,IR14 EasyModbusPort1Command5  // Move the number of pieces of data to read (either bits or words, depending on the Modbus function).
+L(401) IR14 &4 IR13  // Store the address where the response should be stored in IR13

; rung 3: Only Set the Easy Modbus bit if this is a supported function code
LD=(300) 1,IR14 #1  // If the Modbus code to be sent is a 1 (Read Coil Status)
OR=(300) 1,IR14 #2  // If the Modbus code to be sent is a 2 (Read Input Status)
OR=(300) 1,IR14 #3  // If the Modbus code to be sent is a 3 (Read Holding Registers)
OR=(300) 1,IR14 #4  // If the Modbus code to be sent is a 04 (read Input Registers)
SET Easy_Modbus_Execute
; rung 4: If this is not a supported Modbus function code, log an error
LDNOT Easy_Modbus_Execute
SET LogAnEasyModbusError
MOVL(498) #0 ,IR13  // Write 0000 as the data
MOV(021) #FFFF 4,IR13  // Mark the Response OK with an FFFF for BAD DATA
; rung 5: Increment the pointer, even if a valid code was not found.  This allows the app to jump over unknown codes.
LD P_On
OUT TR0
MOVL(498) IR14 IR12  // Capture the value of the pointer to prevent flip / flop in the same scan
AND<>(305) 9,IR12 #F000  // If the end of polling has been reached
+L(401) IR14 &10 IR14  // Add 10 channels to the pointer
AND>=L(326) IR14 #11766  // Of if the pointer reaches D5990
MOVR(560) ModbusNodeNumberReadItem1 IR14  // Load DM5000 into IR 14.  This is the pointer for walking through the list of items to poll
SET Polling_Has_Occurred  // For Poll Cycle Timing
LD TR0
AND=(300) 9,IR12 #F000  // If the end of polling has been reached
MOVR(560) ModbusNodeNumberReadItem1 IR14  // Load DM5000 into IR 14.  This is the pointer for walking through the list of items to poll
SET Polling_Has_Occurred  // For Poll Cycle Timing

; rung 6: Set the Consecutive Write counter back to 0
LD P_On
MOV(021) #0 Consecutive_Writes
; rung 7
JME(005) #FF
; rung 8: If the polling cycle has been reset to the beginning (D5000), then subtract the current timer value from the preset to / determine the interval between polling cycle starts.
LD Polling_Has_Occurred
-B(414) #9999 T13 W216  // post the interval between starting polling cycles in W216 as xx.xx seconds
; rung 9: If polling has not occurred this scan, run the timer
LDNOT Polling_Has_Occurred
TIMH(015) 0013 #9999
; rung 10: If polling has restarted, reset the flag.
LD Polling_Has_Occurred
RSET Polling_Has_Occurred

### Section Responses

; rung 0: Resend the same command after a 1 scan delay
LDNOT Easy_Modbus_Execute
AND Retry_Send_Delay
ANDNOT Port_Needs_To_Be_Reset  ; Waiting for Easy Modbus to finish current command  // If Port 1 is not recovering from an error
ANDNOT Port_Now_Resetting  // if the port is not resetting
SET Easy_Modbus_Execute
RSET Retry_Send_Delay
; rung 1: Detect a timeout, and set a bit to wait 1 PLC scan to resend
%LD Easy_Modbus_Execute
OUT TR0
AND=(300) EasyModbusPort1Response3 #80  // IF the response was a timeout
OUT TR1
++(590) NonResettingTimeoutCounter
++(590) TimeoutRetryCounter
AND<(310) TimeoutRetryCounter #3
SET Retry_Send_Delay  // Retry
LD TR1
AND>=(325) TimeoutRetryCounter #3
MOV(021) #0 TimeoutRetryCounter  // Reset the timeout retry counter
SET LogAnEasyModbusError  // Add this node and function code to the error list
LD TR0
AND<>(305) EasyModbusPort1Response3 #80  // IF the response was not timeout
MOV(021) #0 TimeoutRetryCounter  // Reset the timeout retry counter

; rung 2: Read responses
%LD Easy_Modbus_Execute
ANDNOT Retry_Send_Delay
LD=(300) EasyModbusPort1Command2 #1  // If the Modbus code that was sent was a 1 (Read Coil Status)
OR=(300) EasyModbusPort1Command2 #2  // If the Modbus code that was sent was a 2 (Read Input Status)
OR=(300) EasyModbusPort1Command2 #3  // If the Modbus code that was sent was a 3 (Read Holding Registers)
OR=(300) EasyModbusPort1Command2 #4  // If the Modbus code that was sent was a 04 (read Input Registers)
ANDLD
OUT TR0
AND Easy_Modbus_OK_Complete
OUT TR1
AND=(300) EasyModbusPort1Response3 #0  // And the Modbus  Error Code was 0
MOVD(083) EasyModbusPort1Response5 #210 ,IR13
MOVD(083) EasyModbusPort1Response6 #12 ,IR13
MOVD(083) EasyModbusPort1Response6 #210 1,IR13
MOVD(083) EasyModbusPort1Response7 #12 1,IR13
MOV(021) #0 4,IR13  // Mark the Response OK with a 0 for OK DATA
LD TR1
AND<>(305) EasyModbusPort1Response3 #0  // And the Modbus  Error Code was NOT 0
MOVL(498) #0 ,IR13  // Write 00000000 as the data across both response registeres
MOV(021) #FFFF 4,IR13  // Mark the Response OK with an FFFF for BAD DATA
SET LogAnEasyModbusError  // Add this node and function code to the error list
LD TR0
AND Easy_Modbus_NG_Complete
MOVL(498) #0 ,IR13  // Write 00000000 as the data across both response registeres
MOV(021) #FFFF 4,IR13  // Mark the Response OK with an FFFF for BAD DATA
SET LogAnEasyModbusError  // Add this node and function code to the error list

; rung 3: Write reponses
%LD Easy_Modbus_Execute
ANDNOT Retry_Send_Delay
LD=(300) EasyModbusPort1Command2 #5  // If the Modbus code that was sent was a 5 (Read Coil Status)
OR=(300) EasyModbusPort1Command2 #6  // If the Modbus code that was sent was a 6 (Read Input Status)
OR=(300) EasyModbusPort1Command2 #F  // If the Modbus code that was sent was a F(Read Holding Registers)
OR=(300) EasyModbusPort1Command2 #10  // If the Modbus code that was sent was a 10
ANDLD
OUT TR0
AND Easy_Modbus_OK_Complete
OUT TR1
AND=(300) EasyModbusPort1Response3 #0  // And the Modbus  Error Code was 0
MOV(021) #0 8,IR13  // Mark the Response OK with a 0 for OK DATA
LD TR1
AND<>(305) EasyModbusPort1Response3 #0  // And the Modbus  Error Code was NOT 0
MOV(021) #FFFF 8,IR13  // Mark the Response OK with an FFFF for BAD DATA
SET LogAnEasyModbusError  // Add this node and function code to the error list
LD TR0
AND Easy_Modbus_NG_Complete
MOV(021) #FFFF 8,IR13  // Mark the Response OK with an FFFF for BAD DATA
SET LogAnEasyModbusError  // Add this node and function code to the error list

; rung 4: Maintain a list of the last 5 Modbus Node Numbers, Function Codes, and starting DM addresses that caused an error / This is from W220 - W229, with W220 and W221 being the most recent. / Ex.  Node 1, Function 3, DM6050 causing the error: / W220 = 0103 (HEX) / W221 = 17A2 (HEX).  This is the 6050 part of D6050.
LD LogAnEasyModbusError
OUT TR0
XFER(070) &8 ModbusErrorNodeFunction1 ModbusErrorNodeFunction2  // Shift the last 9 records
MOVD(083) EasyModbusPort1Command1 #210 ModbusErrorNodeFunction1  // Capture the Modbus Node Number
MOVD(083) EasyModbusPort1Command2 #10 ModbusErrorNodeFunction1  // Capture the Modbus Function Code
-L(411) IR13 #10000 TemporaryStartingDMErrorLocation
AND<(310) TemporaryStartingDMErrorLocation &6000
-(410) TemporaryStartingDMErrorLocation #4 TemporaryStartingDMErrorLocation  // Subtract 4 to compensate for the offset difference between the receive area for a Write command vs a Read command
LD TR0
MOV(021) TemporaryStartingDMErrorLocation ModbusErrorDMAddress1
XFER(070) &10 EasyModbusPort1Command1 LastModbusCommandSent1  // Capture the last Modbus command that was sent
XFER(070) &10 EasyModbusPort1Response1 LastModbusCommandReceived1  // Capture the last Modbus command that was Recieved
RSET LogAnEasyModbusError
; rung 5: Clear the error log
LD Clear_Error_Log
BSET(071) #0 ModbusErrorNodeFunction1 LastModbusCommandReceived10

### Section END
; rung 0
END(001)

# PLC CJ1CJ2CS1ModbusDualPorts: CJ2H CPU64-EIP
I/O table (CPU CJ2H-CPU64-EIP): rack 0 slot 0 CJ1W-SCU21-V1; rack 0 slot 11 CJ2B-EIP21

## Global symbols (name address type ; comment)
Clear_Error_Log W215.03 BOOL
Consecutive_Writes W217 INT
Current_Stack_Pointer W2 DWORD
EasyModbusPort1Command1 D32300 CHANNEL
EasyModbusPort1Command10 D32309 CHANNEL
EasyModbusPort1Command2 D32301 CHANNEL
EasyModbusPort1Command3 D32302 CHANNEL
EasyModbusPort1Command4 D32303 CHANNEL
EasyModbusPort1Command5 D32304 CHANNEL
EasyModbusPort1Command6 D32305 CHANNEL
EasyModbusPort1Command7 D32306 CHANNEL
EasyModbusPort1Command8 D32307 CHANNEL
EasyModbusPort1Command9 D32308 CHANNEL
EasyModbusPort1Response1 D32350 CHANNEL
EasyModbusPort1Response10 D32359 CHANNEL
EasyModbusPort1Response2 D32351 CHANNEL
EasyModbusPort1Response3 D32352 CHANNEL
EasyModbusPort1Response4 D32353 CHANNEL
EasyModbusPort1Response5 D32354 CHANNEL
EasyModbusPort1Response6 D32355 CHANNEL
EasyModbusPort1Response7 D32356 CHANNEL
EasyModbusPort1Response8 D32357 CHANNEL
EasyModbusPort1Response9 D32358 CHANNEL
Easy_Modbus_Execute A640.00 BOOL
Easy_Modbus_NG_Complete A640.02 BOOL
Easy_Modbus_OK_Complete A640.01 BOOL
EndOfListMarkerReadItem1 D5009 CHANNEL
EndOfListMarkerReadItem10 D5099 CHANNEL
EndOfListMarkerReadItem100 D5999 CHANNEL
EndOfListMarkerReadItem11 D5109 CHANNEL
EndOfListMarkerReadItem12 D5119 CHANNEL
EndOfListMarkerReadItem13 D5129 CHANNEL
EndOfListMarkerReadItem14 D5139 CHANNEL
EndOfListMarkerReadItem15 D5149 CHANNEL
EndOfListMarkerReadItem16 D5159 CHANNEL
EndOfListMarkerReadItem17 D5169 CHANNEL
EndOfListMarkerReadItem18 D5179 CHANNEL
EndOfListMarkerReadItem19 D5189 CHANNEL
EndOfListMarkerReadItem2 D5019 CHANNEL
EndOfListMarkerReadItem20 D5199 CHANNEL
EndOfListMarkerReadItem21 D5209 CHANNEL
EndOfListMarkerReadItem22 D5219 CHANNEL
EndOfListMarkerReadItem23 D5229 CHANNEL
EndOfListMarkerReadItem24 D5239 CHANNEL
EndOfListMarkerReadItem25 D5249 CHANNEL
EndOfListMarkerReadItem26 D5259 CHANNEL
EndOfListMarkerReadItem27 D5269 CHANNEL
EndOfListMarkerReadItem28 D5279 CHANNEL
EndOfListMarkerReadItem29 D5289 CHANNEL
EndOfListMarkerReadItem3 D5029 CHANNEL
EndOfListMarkerReadItem30 D5299 CHANNEL
EndOfListMarkerReadItem31 D5309 CHANNEL
EndOfListMarkerReadItem32 D5319 CHANNEL
EndOfListMarkerReadItem33 D5329 CHANNEL
EndOfListMarkerReadItem34 D5339 CHANNEL
EndOfListMarkerReadItem35 D5349 CHANNEL
EndOfListMarkerReadItem36 D5359 CHANNEL
EndOfListMarkerReadItem37 D5369 CHANNEL
EndOfListMarkerReadItem38 D5379 CHANNEL
EndOfListMarkerReadItem39 D5389 CHANNEL
EndOfListMarkerReadItem4 D5039 CHANNEL
EndOfListMarkerReadItem40 D5399 CHANNEL
EndOfListMarkerReadItem41 D5409 CHANNEL
EndOfListMarkerReadItem42 D5419 CHANNEL
EndOfListMarkerReadItem43 D5429 CHANNEL
EndOfListMarkerReadItem44 D5439 CHANNEL
EndOfListMarkerReadItem45 D5449 CHANNEL
EndOfListMarkerReadItem46 D5459 CHANNEL
EndOfListMarkerReadItem47 D5469 CHANNEL
EndOfListMarkerReadItem48 D5479 CHANNEL
EndOfListMarkerReadItem49 D5489 CHANNEL
EndOfListMarkerReadItem5 D5049 CHANNEL
EndOfListMarkerReadItem50 D5499 CHANNEL
EndOfListMarkerReadItem51 D5509 CHANNEL
EndOfListMarkerReadItem52 D5519 CHANNEL
EndOfListMarkerReadItem53 D5529 CHANNEL
EndOfListMarkerReadItem54 D5539 CHANNEL
EndOfListMarkerReadItem55 D5549 CHANNEL
EndOfListMarkerReadItem56 D5559 CHANNEL
EndOfListMarkerReadItem57 D5569 CHANNEL
EndOfListMarkerReadItem58 D5579 CHANNEL
EndOfListMarkerReadItem59 D5589 CHANNEL
EndOfListMarkerReadItem6 D5059 CHANNEL
EndOfListMarkerReadItem60 D5599 CHANNEL
EndOfListMarkerReadItem61 D5609 CHANNEL
EndOfListMarkerReadItem62 D5619 CHANNEL
EndOfListMarkerReadItem63 D5629 CHANNEL
EndOfListMarkerReadItem64 D5639 CHANNEL
EndOfListMarkerReadItem65 D5649 CHANNEL
EndOfListMarkerReadItem66 D5659 CHANNEL
EndOfListMarkerReadItem67 D5669 CHANNEL
EndOfListMarkerReadItem68 D5679 CHANNEL
EndOfListMarkerReadItem69 D5689 CHANNEL
EndOfListMarkerReadItem7 D5069 CHANNEL
EndOfListMarkerReadItem70 D5699 CHANNEL
EndOfListMarkerReadItem71 D5709 CHANNEL
EndOfListMarkerReadItem72 D5719 CHANNEL
EndOfListMarkerReadItem73 D5729 CHANNEL
EndOfListMarkerReadItem74 D5739 CHANNEL
EndOfListMarkerReadItem75 D5749 CHANNEL
EndOfListMarkerReadItem76 D5759 CHANNEL
EndOfListMarkerReadItem77 D5769 CHANNEL
EndOfListMarkerReadItem78 D5779 CHANNEL
EndOfListMarkerReadItem79 D5789 CHANNEL
EndOfListMarkerReadItem8 D5079 CHANNEL
EndOfListMarkerReadItem80 D5799 CHANNEL
EndOfListMarkerReadItem81 D5809 CHANNEL
EndOfListMarkerReadItem82 D5819 CHANNEL
EndOfListMarkerReadItem83 D5829 CHANNEL
EndOfListMarkerReadItem84 D5839 CHANNEL
EndOfListMarkerReadItem85 D5849 CHANNEL
EndOfListMarkerReadItem86 D5859 CHANNEL
EndOfListMarkerReadItem87 D5869 CHANNEL
EndOfListMarkerReadItem88 D5879 CHANNEL
EndOfListMarkerReadItem89 D5889 CHANNEL
EndOfListMarkerReadItem9 D5089 CHANNEL
EndOfListMarkerReadItem90 D5899 CHANNEL
EndOfListMarkerReadItem91 D5909 CHANNEL
EndOfListMarkerReadItem92 D5919 CHANNEL
EndOfListMarkerReadItem93 D5929 CHANNEL
EndOfListMarkerReadItem94 D5939 CHANNEL
EndOfListMarkerReadItem95 D5949 CHANNEL
EndOfListMarkerReadItem96 D5959 CHANNEL
EndOfListMarkerReadItem97 D5969 CHANNEL
EndOfListMarkerReadItem98 D5979 CHANNEL
EndOfListMarkerReadItem99 D5989 CHANNEL
EndOfListMarkerWriteItem1 D6009 CHANNEL
EndOfListMarkerWriteItem10 D6099 CHANNEL
EndOfListMarkerWriteItem100 D6999 CHANNEL
EndOfListMarkerWriteItem11 D6109 CHANNEL
EndOfListMarkerWriteItem12 D6119 CHANNEL
EndOfListMarkerWriteItem13 D6129 CHANNEL
EndOfListMarkerWriteItem14 D6139 CHANNEL
EndOfListMarkerWriteItem15 D6149 CHANNEL
EndOfListMarkerWriteItem16 D6159 CHANNEL
EndOfListMarkerWriteItem17 D6169 CHANNEL
EndOfListMarkerWriteItem18 D6179 CHANNEL
EndOfListMarkerWriteItem19 D6189 CHANNEL
EndOfListMarkerWriteItem2 D6019 CHANNEL
EndOfListMarkerWriteItem20 D6199 CHANNEL
EndOfListMarkerWriteItem21 D6209 CHANNEL
EndOfListMarkerWriteItem22 D6219 CHANNEL
EndOfListMarkerWriteItem23 D6229 CHANNEL
EndOfListMarkerWriteItem24 D6239 CHANNEL
EndOfListMarkerWriteItem25 D6249 CHANNEL
EndOfListMarkerWriteItem26 D6259 CHANNEL
EndOfListMarkerWriteItem27 D6269 CHANNEL
EndOfListMarkerWriteItem28 D6279 CHANNEL
EndOfListMarkerWriteItem29 D6289 CHANNEL
EndOfListMarkerWriteItem3 D6029 CHANNEL
EndOfListMarkerWriteItem30 D6299 CHANNEL
EndOfListMarkerWriteItem31 D6309 CHANNEL
EndOfListMarkerWriteItem32 D6319 CHANNEL
EndOfListMarkerWriteItem33 D6329 CHANNEL
EndOfListMarkerWriteItem34 D6339 CHANNEL
EndOfListMarkerWriteItem35 D6349 CHANNEL
EndOfListMarkerWriteItem36 D6359 CHANNEL
EndOfListMarkerWriteItem37 D6369 CHANNEL
EndOfListMarkerWriteItem38 D6379 CHANNEL
EndOfListMarkerWriteItem39 D6389 CHANNEL
EndOfListMarkerWriteItem4 D6039 CHANNEL
EndOfListMarkerWriteItem40 D6399 CHANNEL
EndOfListMarkerWriteItem41 D6409 CHANNEL
EndOfListMarkerWriteItem42 D6419 CHANNEL
EndOfListMarkerWriteItem43 D6429 CHANNEL
EndOfListMarkerWriteItem44 D6439 CHANNEL
EndOfListMarkerWriteItem45 D6449 CHANNEL
EndOfListMarkerWriteItem46 D6459 CHANNEL
EndOfListMarkerWriteItem47 D6469 CHANNEL
EndOfListMarkerWriteItem48 D6479 CHANNEL
EndOfListMarkerWriteItem49 D6489 CHANNEL
EndOfListMarkerWriteItem5 D6049 CHANNEL
EndOfListMarkerWriteItem50 D6499 CHANNEL
EndOfListMarkerWriteItem51 D6509 CHANNEL
EndOfListMarkerWriteItem52 D6519 CHANNEL
EndOfListMarkerWriteItem53 D6529 CHANNEL
EndOfListMarkerWriteItem54 D6539 CHANNEL
EndOfListMarkerWriteItem55 D6549 CHANNEL
EndOfListMarkerWriteItem56 D6559 CHANNEL
EndOfListMarkerWriteItem57 D6569 CHANNEL
EndOfListMarkerWriteItem58 D6579 CHANNEL
EndOfListMarkerWriteItem59 D6589 CHANNEL
EndOfListMarkerWriteItem6 D6059 CHANNEL
EndOfListMarkerWriteItem60 D6599 CHANNEL
EndOfListMarkerWriteItem61 D6609 CHANNEL
EndOfListMarkerWriteItem62 D6619 CHANNEL
EndOfListMarkerWriteItem63 D6629 CHANNEL
EndOfListMarkerWriteItem64 D6639 CHANNEL
EndOfListMarkerWriteItem65 D6649 CHANNEL
EndOfListMarkerWriteItem66 D6659 CHANNEL
EndOfListMarkerWriteItem67 D6669 CHANNEL
EndOfListMarkerWriteItem68 D6679 CHANNEL
EndOfListMarkerWriteItem69 D6689 CHANNEL
EndOfListMarkerWriteItem7 D6069 CHANNEL
EndOfListMarkerWriteItem70 D6699 CHANNEL
EndOfListMarkerWriteItem71 D6709 CHANNEL
EndOfListMarkerWriteItem72 D6719 CHANNEL
EndOfListMarkerWriteItem73 D6729 CHANNEL
EndOfListMarkerWriteItem74 D6739 CHANNEL
EndOfListMarkerWriteItem75 D6749 CHANNEL
EndOfListMarkerWriteItem76 D6759 CHANNEL
EndOfListMarkerWriteItem77 D6769 CHANNEL
EndOfListMarkerWriteItem78 D6779 CHANNEL
EndOfListMarkerWriteItem79 D6789 CHANNEL
EndOfListMarkerWriteItem8 D6079 CHANNEL
EndOfListMarkerWriteItem80 D6799 CHANNEL
EndOfListMarkerWriteItem81 D6809 CHANNEL
EndOfListMarkerWriteItem82 D6819 CHANNEL
EndOfListMarkerWriteItem83 D6829 CHANNEL
EndOfListMarkerWriteItem84 D6839 CHANNEL
EndOfListMarkerWriteItem85 D6849 CHANNEL
EndOfListMarkerWriteItem86 D6859 CHANNEL
EndOfListMarkerWriteItem87 D6869 CHANNEL
EndOfListMarkerWriteItem88 D6879 CHANNEL
EndOfListMarkerWriteItem89 D6889 CHANNEL
EndOfListMarkerWriteItem9 D6089 CHANNEL
EndOfListMarkerWriteItem90 D6899 CHANNEL
EndOfListMarkerWriteItem91 D6909 CHANNEL
EndOfListMarkerWriteItem92 D6919 CHANNEL
EndOfListMarkerWriteItem93 D6929 CHANNEL
EndOfListMarkerWriteItem94 D6939 CHANNEL
EndOfListMarkerWriteItem95 D6949 CHANNEL
EndOfListMarkerWriteItem96 D6959 CHANNEL
EndOfListMarkerWriteItem97 D6969 CHANNEL
EndOfListMarkerWriteItem98 D6979 CHANNEL
EndOfListMarkerWriteItem99 D6989 CHANNEL
FirstWordResponseDataReadItem1 D5004 CHANNEL
FirstWordResponseDataReadItem10 D5094 CHANNEL
FirstWordResponseDataReadItem100 D5994 CHANNEL
FirstWordResponseDataReadItem11 D5104 CHANNEL
FirstWordResponseDataReadItem12 D5114 CHANNEL
FirstWordResponseDataReadItem13 D5124 CHANNEL
FirstWordResponseDataReadItem14 D5134 CHANNEL
FirstWordResponseDataReadItem15 D5144 CHANNEL
FirstWordResponseDataReadItem16 D5154 CHANNEL
FirstWordResponseDataReadItem17 D5164 CHANNEL
FirstWordResponseDataReadItem18 D5174 CHANNEL
FirstWordResponseDataReadItem19 D5184 CHANNEL
FirstWordResponseDataReadItem2 D5014 CHANNEL
FirstWordResponseDataReadItem20 D5194 CHANNEL
FirstWordResponseDataReadItem21 D5204 CHANNEL
FirstWordResponseDataReadItem22 D5214 CHANNEL
FirstWordResponseDataReadItem23 D5224 CHANNEL
FirstWordResponseDataReadItem24 D5234 CHANNEL
FirstWordResponseDataReadItem25 D5244 CHANNEL
FirstWordResponseDataReadItem26 D5254 CHANNEL
FirstWordResponseDataReadItem27 D5264 CHANNEL
FirstWordResponseDataReadItem28 D5274 CHANNEL
FirstWordResponseDataReadItem29 D5284 CHANNEL
FirstWordResponseDataReadItem3 D5024 CHANNEL
FirstWordResponseDataReadItem30 D5294 CHANNEL
FirstWordResponseDataReadItem31 D5304 CHANNEL
FirstWordResponseDataReadItem32 D5314 CHANNEL
FirstWordResponseDataReadItem33 D5324 CHANNEL
FirstWordResponseDataReadItem34 D5334 CHANNEL
FirstWordResponseDataReadItem35 D5344 CHANNEL
FirstWordResponseDataReadItem36 D5354 CHANNEL
FirstWordResponseDataReadItem37 D5364 CHANNEL
FirstWordResponseDataReadItem38 D5374 CHANNEL
FirstWordResponseDataReadItem39 D5384 CHANNEL
FirstWordResponseDataReadItem4 D5034 CHANNEL
FirstWordResponseDataReadItem40 D5394 CHANNEL
FirstWordResponseDataReadItem41 D5404 CHANNEL
FirstWordResponseDataReadItem42 D5414 CHANNEL
FirstWordResponseDataReadItem43 D5424 CHANNEL
FirstWordResponseDataReadItem44 D5434 CHANNEL
FirstWordResponseDataReadItem45 D5444 CHANNEL
FirstWordResponseDataReadItem46 D5454 CHANNEL
FirstWordResponseDataReadItem47 D5464 CHANNEL
FirstWordResponseDataReadItem48 D5474 CHANNEL
FirstWordResponseDataReadItem49 D5484 CHANNEL
FirstWordResponseDataReadItem5 D5044 CHANNEL
FirstWordResponseDataReadItem50 D5494 CHANNEL
FirstWordResponseDataReadItem51 D5504 CHANNEL
FirstWordResponseDataReadItem52 D5514 CHANNEL
FirstWordResponseDataReadItem53 D5524 CHANNEL
FirstWordResponseDataReadItem54 D5534 CHANNEL
FirstWordResponseDataReadItem55 D5544 CHANNEL
FirstWordResponseDataReadItem56 D5554 CHANNEL
FirstWordResponseDataReadItem57 D5564 CHANNEL
FirstWordResponseDataReadItem58 D5574 CHANNEL
FirstWordResponseDataReadItem59 D5584 CHANNEL
FirstWordResponseDataReadItem6 D5054 CHANNEL
FirstWordResponseDataReadItem60 D5594 CHANNEL
FirstWordResponseDataReadItem61 D5604 CHANNEL
FirstWordResponseDataReadItem62 D5614 CHANNEL
FirstWordResponseDataReadItem63 D5624 CHANNEL
FirstWordResponseDataReadItem64 D5634 CHANNEL
FirstWordResponseDataReadItem65 D5644 CHANNEL
FirstWordResponseDataReadItem66 D5654 CHANNEL
FirstWordResponseDataReadItem67 D5664 CHANNEL
FirstWordResponseDataReadItem68 D5674 CHANNEL
FirstWordResponseDataReadItem69 D5684 CHANNEL
FirstWordResponseDataReadItem7 D5064 CHANNEL
FirstWordResponseDataReadItem70 D5694 CHANNEL
FirstWordResponseDataReadItem71 D5704 CHANNEL
FirstWordResponseDataReadItem72 D5714 CHANNEL
FirstWordResponseDataReadItem73 D5724 CHANNEL
FirstWordResponseDataReadItem74 D5734 CHANNEL
FirstWordResponseDataReadItem75 D5744 CHANNEL
FirstWordResponseDataReadItem76 D5754 CHANNEL
FirstWordResponseDataReadItem77 D5764 CHANNEL
FirstWordResponseDataReadItem78 D5774 CHANNEL
FirstWordResponseDataReadItem79 D5784 CHANNEL
FirstWordResponseDataReadItem8 D5074 CHANNEL
FirstWordResponseDataReadItem80 D5794 CHANNEL
FirstWordResponseDataReadItem81 D5804 CHANNEL
FirstWordResponseDataReadItem82 D5814 CHANNEL
FirstWordResponseDataReadItem83 D5824 CHANNEL
FirstWordResponseDataReadItem84 D5834 CHANNEL
FirstWordResponseDataReadItem85 D5844 CHANNEL
FirstWordResponseDataReadItem86 D5854 CHANNEL
FirstWordResponseDataReadItem87 D5864 CHANNEL
FirstWordResponseDataReadItem88 D5874 CHANNEL
FirstWordResponseDataReadItem89 D5884 CHANNEL
FirstWordResponseDataReadItem9 D5084 CHANNEL
FirstWordResponseDataReadItem90 D5894 CHANNEL
FirstWordResponseDataReadItem91 D5904 CHANNEL
FirstWordResponseDataReadItem92 D5914 CHANNEL
FirstWordResponseDataReadItem93 D5924 CHANNEL
FirstWordResponseDataReadItem94 D5934 CHANNEL
FirstWordResponseDataReadItem95 D5944 CHANNEL
FirstWordResponseDataReadItem96 D5954 CHANNEL
FirstWordResponseDataReadItem97 D5964 CHANNEL
FirstWordResponseDataReadItem98 D5974 CHANNEL
FirstWordResponseDataReadItem99 D5984 CHANNEL
FirstWordWriteDataMirrorWriteItem1 D6006 CHANNEL
FirstWordWriteDataMirrorWriteItem10 D6096 CHANNEL
FirstWordWriteDataMirrorWriteItem100 D6996 CHANNEL
FirstWordWriteDataMirrorWriteItem11 D6106 CHANNEL
FirstWordWriteDataMirrorWriteItem12 D6116 CHANNEL
FirstWordWriteDataMirrorWriteItem13 D6126 CHANNEL
FirstWordWriteDataMirrorWriteItem14 D6136 CHANNEL
FirstWordWriteDataMirrorWriteItem15 D6146 CHANNEL
FirstWordWriteDataMirrorWriteItem16 D6156 CHANNEL
FirstWordWriteDataMirrorWriteItem17 D6166 CHANNEL
FirstWordWriteDataMirrorWriteItem18 D6176 CHANNEL
FirstWordWriteDataMirrorWriteItem19 D6186 CHANNEL
FirstWordWriteDataMirrorWriteItem2 D6016 CHANNEL
FirstWordWriteDataMirrorWriteItem20 D6196 CHANNEL
FirstWordWriteDataMirrorWriteItem21 D6206 CHANNEL
FirstWordWriteDataMirrorWriteItem22 D6216 CHANNEL
FirstWordWriteDataMirrorWriteItem23 D6226 CHANNEL
FirstWordWriteDataMirrorWriteItem24 D6236 CHANNEL
FirstWordWriteDataMirrorWriteItem25 D6246 CHANNEL
FirstWordWriteDataMirrorWriteItem26 D6256 CHANNEL
FirstWordWriteDataMirrorWriteItem27 D6266 CHANNEL
FirstWordWriteDataMirrorWriteItem28 D6276 CHANNEL
FirstWordWriteDataMirrorWriteItem29 D6286 CHANNEL
FirstWordWriteDataMirrorWriteItem3 D6026 CHANNEL
FirstWordWriteDataMirrorWriteItem30 D6296 CHANNEL
FirstWordWriteDataMirrorWriteItem31 D6306 CHANNEL
FirstWordWriteDataMirrorWriteItem32 D6316 CHANNEL
FirstWordWriteDataMirrorWriteItem33 D6326 CHANNEL
FirstWordWriteDataMirrorWriteItem34 D6336 CHANNEL
FirstWordWriteDataMirrorWriteItem35 D6346 CHANNEL
FirstWordWriteDataMirrorWriteItem36 D6356 CHANNEL
FirstWordWriteDataMirrorWriteItem37 D6366 CHANNEL
FirstWordWriteDataMirrorWriteItem38 D6376 CHANNEL
FirstWordWriteDataMirrorWriteItem39 D6386 CHANNEL
FirstWordWriteDataMirrorWriteItem4 D6036 CHANNEL
FirstWordWriteDataMirrorWriteItem40 D6396 CHANNEL
FirstWordWriteDataMirrorWriteItem41 D6406 CHANNEL
FirstWordWriteDataMirrorWriteItem42 D6416 CHANNEL
FirstWordWriteDataMirrorWriteItem43 D6426 CHANNEL
FirstWordWriteDataMirrorWriteItem44 D6436 CHANNEL
FirstWordWriteDataMirrorWriteItem45 D6446 CHANNEL
FirstWordWriteDataMirrorWriteItem46 D6456 CHANNEL
FirstWordWriteDataMirrorWriteItem47 D6466 CHANNEL
FirstWordWriteDataMirrorWriteItem48 D6476 CHANNEL
FirstWordWriteDataMirrorWriteItem49 D6486 CHANNEL
FirstWordWriteDataMirrorWriteItem5 D6046 CHANNEL
FirstWordWriteDataMirrorWriteItem50 D6496 CHANNEL
FirstWordWriteDataMirrorWriteItem51 D6506 CHANNEL
FirstWordWriteDataMirrorWriteItem52 D6516 CHANNEL
FirstWordWriteDataMirrorWriteItem53 D6526 CHANNEL
FirstWordWriteDataMirrorWriteItem54 D6536 CHANNEL
FirstWordWriteDataMirrorWriteItem55 D6546 CHANNEL
FirstWordWriteDataMirrorWriteItem56 D6556 CHANNEL
FirstWordWriteDataMirrorWriteItem57 D6566 CHANNEL
FirstWordWriteDataMirrorWriteItem58 D6576 CHANNEL
FirstWordWriteDataMirrorWriteItem59 D6586 CHANNEL
FirstWordWriteDataMirrorWriteItem6 D6056 CHANNEL
FirstWordWriteDataMirrorWriteItem60 D6596 CHANNEL
FirstWordWriteDataMirrorWriteItem61 D6606 CHANNEL
FirstWordWriteDataMirrorWriteItem62 D6616 CHANNEL
FirstWordWriteDataMirrorWriteItem63 D6626 CHANNEL
FirstWordWriteDataMirrorWriteItem64 D6636 CHANNEL
FirstWordWriteDataMirrorWriteItem65 D6646 CHANNEL
FirstWordWriteDataMirrorWriteItem66 D6656 CHANNEL
FirstWordWriteDataMirrorWriteItem67 D6666 CHANNEL
FirstWordWriteDataMirrorWriteItem68 D6676 CHANNEL
FirstWordWriteDataMirrorWriteItem69 D6686 CHANNEL
FirstWordWriteDataMirrorWriteItem7 D6066 CHANNEL
FirstWordWriteDataMirrorWriteItem70 D6696 CHANNEL
FirstWordWriteDataMirrorWriteItem71 D6706 CHANNEL
FirstWordWriteDataMirrorWriteItem72 D6716 CHANNEL
FirstWordWriteDataMirrorWriteItem73 D6726 CHANNEL
FirstWordWriteDataMirrorWriteItem74 D6736 CHANNEL
FirstWordWriteDataMirrorWriteItem75 D6746 CHANNEL
FirstWordWriteDataMirrorWriteItem76 D6756 CHANNEL
FirstWordWriteDataMirrorWriteItem77 D6766 CHANNEL
FirstWordWriteDataMirrorWriteItem78 D6776 CHANNEL
FirstWordWriteDataMirrorWriteItem79 D6786 CHANNEL
FirstWordWriteDataMirrorWriteItem8 D6076 CHANNEL
FirstWordWriteDataMirrorWriteItem80 D6796 CHANNEL
FirstWordWriteDataMirrorWriteItem81 D6806 CHANNEL
FirstWordWriteDataMirrorWriteItem82 D6816 CHANNEL
FirstWordWriteDataMirrorWriteItem83 D6826 CHANNEL
FirstWordWriteDataMirrorWriteItem84 D6836 CHANNEL
FirstWordWriteDataMirrorWriteItem85 D6846 CHANNEL
FirstWordWriteDataMirrorWriteItem86 D6856 CHANNEL
FirstWordWriteDataMirrorWriteItem87 D6866 CHANNEL
FirstWordWriteDataMirrorWriteItem88 D6876 CHANNEL
FirstWordWriteDataMirrorWriteItem89 D6886 CHANNEL
FirstWordWriteDataMirrorWriteItem9 D6086 CHANNEL
FirstWordWriteDataMirrorWriteItem90 D6896 CHANNEL
FirstWordWriteDataMirrorWriteItem91 D6906 CHANNEL
FirstWordWriteDataMirrorWriteItem92 D6916 CHANNEL
FirstWordWriteDataMirrorWriteItem93 D6926 CHANNEL
FirstWordWriteDataMirrorWriteItem94 D6936 CHANNEL
FirstWordWriteDataMirrorWriteItem95 D6946 CHANNEL
FirstWordWriteDataMirrorWriteItem96 D6956 CHANNEL
FirstWordWriteDataMirrorWriteItem97 D6966 CHANNEL
FirstWordWriteDataMirrorWriteItem98 D6976 CHANNEL
FirstWordWriteDataMirrorWriteItem99 D6986 CHANNEL
FirstWordWriteDataWriteItem1 D6004 CHANNEL
FirstWordWriteDataWriteItem10 D6094 CHANNEL
FirstWordWriteDataWriteItem100 D6994 CHANNEL
FirstWordWriteDataWriteItem11 D6104 CHANNEL
FirstWordWriteDataWriteItem12 D6114 CHANNEL
FirstWordWriteDataWriteItem13 D6124 CHANNEL
FirstWordWriteDataWriteItem14 D6134 CHANNEL
FirstWordWriteDataWriteItem15 D6144 CHANNEL
FirstWordWriteDataWriteItem16 D6154 CHANNEL
FirstWordWriteDataWriteItem17 D6164 CHANNEL
FirstWordWriteDataWriteItem18 D6174 CHANNEL
FirstWordWriteDataWriteItem19 D6184 CHANNEL
FirstWordWriteDataWriteItem2 D6014 CHANNEL
FirstWordWriteDataWriteItem20 D6194 CHANNEL
FirstWordWriteDataWriteItem21 D6204 CHANNEL
FirstWordWriteDataWriteItem22 D6214 CHANNEL
FirstWordWriteDataWriteItem23 D6224 CHANNEL
FirstWordWriteDataWriteItem24 D6234 CHANNEL
FirstWordWriteDataWriteItem25 D6244 CHANNEL
FirstWordWriteDataWriteItem26 D6254 CHANNEL
FirstWordWriteDataWriteItem27 D6264 CHANNEL
FirstWordWriteDataWriteItem28 D6274 CHANNEL
FirstWordWriteDataWriteItem29 D6284 CHANNEL
FirstWordWriteDataWriteItem3 D6024 CHANNEL
FirstWordWriteDataWriteItem30 D6294 CHANNEL
FirstWordWriteDataWriteItem31 D6304 CHANNEL
FirstWordWriteDataWriteItem32 D6314 CHANNEL
FirstWordWriteDataWriteItem33 D6324 CHANNEL
FirstWordWriteDataWriteItem34 D6334 CHANNEL
FirstWordWriteDataWriteItem35 D6344 CHANNEL
FirstWordWriteDataWriteItem36 D6354 CHANNEL
FirstWordWriteDataWriteItem37 D6364 CHANNEL
FirstWordWriteDataWriteItem38 D6374 CHANNEL
FirstWordWriteDataWriteItem39 D6384 CHANNEL
FirstWordWriteDataWriteItem4 D6034 CHANNEL
FirstWordWriteDataWriteItem40 D6394 CHANNEL
FirstWordWriteDataWriteItem41 D6404 CHANNEL
FirstWordWriteDataWriteItem42 D6414 CHANNEL
FirstWordWriteDataWriteItem43 D6424 CHANNEL
FirstWordWriteDataWriteItem44 D6434 CHANNEL
FirstWordWriteDataWriteItem45 D6444 CHANNEL
FirstWordWriteDataWriteItem46 D6454 CHANNEL
FirstWordWriteDataWriteItem47 D6464 CHANNEL
FirstWordWriteDataWriteItem48 D6474 CHANNEL
FirstWordWriteDataWriteItem49 D6484 CHANNEL
FirstWordWriteDataWriteItem5 D6044 CHANNEL
FirstWordWriteDataWriteItem50 D6494 CHANNEL
FirstWordWriteDataWriteItem51 D6504 CHANNEL
FirstWordWriteDataWriteItem52 D6514 CHANNEL
FirstWordWriteDataWriteItem53 D6524 CHANNEL
FirstWordWriteDataWriteItem54 D6534 CHANNEL
FirstWordWriteDataWriteItem55 D6544 CHANNEL
FirstWordWriteDataWriteItem56 D6554 CHANNEL
FirstWordWriteDataWriteItem57 D6564 CHANNEL
FirstWordWriteDataWriteItem58 D6574 CHANNEL
FirstWordWriteDataWriteItem59 D6584 CHANNEL
FirstWordWriteDataWriteItem6 D6054 CHANNEL
FirstWordWriteDataWriteItem60 D6594 CHANNEL
FirstWordWriteDataWriteItem61 D6604 CHANNEL
FirstWordWriteDataWriteItem62 D6614 CHANNEL
FirstWordWriteDataWriteItem63 D6624 CHANNEL
FirstWordWriteDataWriteItem64 D6634 CHANNEL
FirstWordWriteDataWriteItem65 D6644 CHANNEL
FirstWordWriteDataWriteItem66 D6654 CHANNEL
FirstWordWriteDataWriteItem67 D6664 CHANNEL
FirstWordWriteDataWriteItem68 D6674 CHANNEL
FirstWordWriteDataWriteItem69 D6684 CHANNEL
FirstWordWriteDataWriteItem7 D6064 CHANNEL
FirstWordWriteDataWriteItem70 D6694 CHANNEL
FirstWordWriteDataWriteItem71 D6704 CHANNEL
FirstWordWriteDataWriteItem72 D6714 CHANNEL
FirstWordWriteDataWriteItem73 D6724 CHANNEL
FirstWordWriteDataWriteItem74 D6734 CHANNEL
FirstWordWriteDataWriteItem75 D6744 CHANNEL
FirstWordWriteDataWriteItem76 D6754 CHANNEL
FirstWordWriteDataWriteItem77 D6764 CHANNEL
FirstWordWriteDataWriteItem78 D6774 CHANNEL
FirstWordWriteDataWriteItem79 D6784 CHANNEL
FirstWordWriteDataWriteItem8 D6074 CHANNEL
FirstWordWriteDataWriteItem80 D6794 CHANNEL
FirstWordWriteDataWriteItem81 D6804 CHANNEL
FirstWordWriteDataWriteItem82 D6814 CHANNEL
FirstWordWriteDataWriteItem83 D6824 CHANNEL
FirstWordWriteDataWriteItem84 D6834 CHANNEL
FirstWordWriteDataWriteItem85 D6844 CHANNEL
FirstWordWriteDataWriteItem86 D6854 CHANNEL
FirstWordWriteDataWriteItem87 D6864 CHANNEL
FirstWordWriteDataWriteItem88 D6874 CHANNEL
FirstWordWriteDataWriteItem89 D6884 CHANNEL
FirstWordWriteDataWriteItem9 D6084 CHANNEL
FirstWordWriteDataWriteItem90 D6894 CHANNEL
FirstWordWriteDataWriteItem91 D6904 CHANNEL
FirstWordWriteDataWriteItem92 D6914 CHANNEL
FirstWordWriteDataWriteItem93 D6924 CHANNEL
FirstWordWriteDataWriteItem94 D6934 CHANNEL
FirstWordWriteDataWriteItem95 D6944 CHANNEL
FirstWordWriteDataWriteItem96 D6954 CHANNEL
FirstWordWriteDataWriteItem97 D6964 CHANNEL
FirstWordWriteDataWriteItem98 D6974 CHANNEL
FirstWordWriteDataWriteItem99 D6984 CHANNEL
LastModbusCommandReceived1 W240 CHANNEL
LastModbusCommandReceived10 W249 CHANNEL
LastModbusCommandReceived2 W241 CHANNEL
LastModbusCommandReceived3 W242 CHANNEL
LastModbusCommandReceived4 W243 CHANNEL
LastModbusCommandReceived5 W244 CHANNEL
LastModbusCommandReceived6 W245 CHANNEL
LastModbusCommandReceived7 W246 CHANNEL
LastModbusCommandReceived8 W247 CHANNEL
LastModbusCommandReceived9 W248 CHANNEL
LastModbusCommandSent1 W230 CHANNEL
LastModbusCommandSent10 W239 CHANNEL
LastModbusCommandSent2 W231 CHANNEL
LastModbusCommandSent3 W232 CHANNEL
LastModbusCommandSent4 W233 CHANNEL
LastModbusCommandSent5 W234 CHANNEL
LastModbusCommandSent6 W235 CHANNEL
LastModbusCommandSent7 W236 CHANNEL
LastModbusCommandSent8 W237 CHANNEL
LastModbusCommandSent9 W238 CHANNEL
LogAnEasyModbusError W215.00 BOOL
Logical_Port_Ready A202.07 BOOL
ModbusErrorDMAddress1 W221 CHANNEL
ModbusErrorDMAddress2 W223 CHANNEL
ModbusErrorDMAddress3 W225 CHANNEL
ModbusErrorDMAddress4 W227 CHANNEL
ModbusErrorDMAddress5 W229 CHANNEL
ModbusErrorNodeFunction1 W220 CHANNEL
ModbusErrorNodeFunction2 W222 CHANNEL
ModbusErrorNodeFunction3 W224 CHANNEL
ModbusErrorNodeFunction4 W226 CHANNEL
ModbusErrorNodeFunction5 W228 CHANNEL
ModbusFunctionCodeReadItem1 D5001 CHANNEL
ModbusFunctionCodeReadItem10 D5091 CHANNEL
ModbusFunctionCodeReadItem100 D5991 CHANNEL
ModbusFunctionCodeReadItem11 D5101 CHANNEL
ModbusFunctionCodeReadItem12 D5111 CHANNEL
ModbusFunctionCodeReadItem13 D5121 CHANNEL
ModbusFunctionCodeReadItem14 D5131 CHANNEL
ModbusFunctionCodeReadItem15 D5141 CHANNEL
ModbusFunctionCodeReadItem16 D5151 CHANNEL
ModbusFunctionCodeReadItem17 D5161 CHANNEL
ModbusFunctionCodeReadItem18 D5171 CHANNEL
ModbusFunctionCodeReadItem19 D5181 CHANNEL
ModbusFunctionCodeReadItem2 D5011 CHANNEL
ModbusFunctionCodeReadItem20 D5191 CHANNEL
ModbusFunctionCodeReadItem21 D5201 CHANNEL
ModbusFunctionCodeReadItem22 D5211 CHANNEL
ModbusFunctionCodeReadItem23 D5221 CHANNEL
ModbusFunctionCodeReadItem24 D5231 CHANNEL
ModbusFunctionCodeReadItem25 D5241 CHANNEL
ModbusFunctionCodeReadItem26 D5251 CHANNEL
ModbusFunctionCodeReadItem27 D5261 CHANNEL
ModbusFunctionCodeReadItem28 D5271 CHANNEL
ModbusFunctionCodeReadItem29 D5281 CHANNEL
ModbusFunctionCodeReadItem3 D5021 CHANNEL
ModbusFunctionCodeReadItem30 D5291 CHANNEL
ModbusFunctionCodeReadItem31 D5301 CHANNEL
ModbusFunctionCodeReadItem32 D5311 CHANNEL
ModbusFunctionCodeReadItem33 D5321 CHANNEL
ModbusFunctionCodeReadItem34 D5331 CHANNEL
ModbusFunctionCodeReadItem35 D5341 CHANNEL
ModbusFunctionCodeReadItem36 D5351 CHANNEL
ModbusFunctionCodeReadItem37 D5361 CHANNEL
ModbusFunctionCodeReadItem38 D5371 CHANNEL
ModbusFunctionCodeReadItem39 D5381 CHANNEL
ModbusFunctionCodeReadItem4 D5031 CHANNEL
ModbusFunctionCodeReadItem40 D5391 CHANNEL
ModbusFunctionCodeReadItem41 D5401 CHANNEL
ModbusFunctionCodeReadItem42 D5411 CHANNEL
ModbusFunctionCodeReadItem43 D5421 CHANNEL
ModbusFunctionCodeReadItem44 D5431 CHANNEL
ModbusFunctionCodeReadItem45 D5441 CHANNEL
ModbusFunctionCodeReadItem46 D5451 CHANNEL
ModbusFunctionCodeReadItem47 D5461 CHANNEL
ModbusFunctionCodeReadItem48 D5471 CHANNEL
ModbusFunctionCodeReadItem49 D5481 CHANNEL
ModbusFunctionCodeReadItem5 D5041 CHANNEL
ModbusFunctionCodeReadItem50 D5491 CHANNEL
ModbusFunctionCodeReadItem51 D5501 CHANNEL
ModbusFunctionCodeReadItem52 D5511 CHANNEL
ModbusFunctionCodeReadItem53 D5521 CHANNEL
ModbusFunctionCodeReadItem54 D5531 CHANNEL
ModbusFunctionCodeReadItem55 D5541 CHANNEL
ModbusFunctionCodeReadItem56 D5551 CHANNEL
ModbusFunctionCodeReadItem57 D5561 CHANNEL
ModbusFunctionCodeReadItem58 D5571 CHANNEL
ModbusFunctionCodeReadItem59 D5581 CHANNEL
ModbusFunctionCodeReadItem6 D5051 CHANNEL
ModbusFunctionCodeReadItem60 D5591 CHANNEL
ModbusFunctionCodeReadItem61 D5601 CHANNEL
ModbusFunctionCodeReadItem62 D5611 CHANNEL
ModbusFunctionCodeReadItem63 D5621 CHANNEL
ModbusFunctionCodeReadItem64 D5631 CHANNEL
ModbusFunctionCodeReadItem65 D5641 CHANNEL
ModbusFunctionCodeReadItem66 D5651 CHANNEL
ModbusFunctionCodeReadItem67 D5661 CHANNEL
ModbusFunctionCodeReadItem68 D5671 CHANNEL
ModbusFunctionCodeReadItem69 D5681 CHANNEL
ModbusFunctionCodeReadItem7 D5061 CHANNEL
ModbusFunctionCodeReadItem70 D5691 CHANNEL
ModbusFunctionCodeReadItem71 D5701 CHANNEL
ModbusFunctionCodeReadItem72 D5711 CHANNEL
ModbusFunctionCodeReadItem73 D5721 CHANNEL
ModbusFunctionCodeReadItem74 D5731 CHANNEL
ModbusFunctionCodeReadItem75 D5741 CHANNEL
ModbusFunctionCodeReadItem76 D5751 CHANNEL
ModbusFunctionCodeReadItem77 D5761 CHANNEL
ModbusFunctionCodeReadItem78 D5771 CHANNEL
ModbusFunctionCodeReadItem79 D5781 CHANNEL
ModbusFunctionCodeReadItem8 D5071 CHANNEL
ModbusFunctionCodeReadItem80 D5791 CHANNEL
ModbusFunctionCodeReadItem81 D5801 CHANNEL
ModbusFunctionCodeReadItem82 D5811 CHANNEL
ModbusFunctionCodeReadItem83 D5821 CHANNEL
ModbusFunctionCodeReadItem84 D5831 CHANNEL
ModbusFunctionCodeReadItem85 D5841 CHANNEL
ModbusFunctionCodeReadItem86 D5851 CHANNEL
ModbusFunctionCodeReadItem87 D5861 CHANNEL
ModbusFunctionCodeReadItem88 D5871 CHANNEL
ModbusFunctionCodeReadItem89 D5881 CHANNEL
ModbusFunctionCodeReadItem9 D5081 CHANNEL
ModbusFunctionCodeReadItem90 D5891 CHANNEL
ModbusFunctionCodeReadItem91 D5901 CHANNEL
ModbusFunctionCodeReadItem92 D5911 CHANNEL
ModbusFunctionCodeReadItem93 D5921 CHANNEL
ModbusFunctionCodeReadItem94 D5931 CHANNEL
ModbusFunctionCodeReadItem95 D5941 CHANNEL
ModbusFunctionCodeReadItem96 D5951 CHANNEL
ModbusFunctionCodeReadItem97 D5961 CHANNEL
ModbusFunctionCodeReadItem98 D5971 CHANNEL
ModbusFunctionCodeReadItem99 D5981 CHANNEL
ModbusFunctionCodeWriteItem1 D6001 CHANNEL
ModbusFunctionCodeWriteItem10 D6091 CHANNEL
ModbusFunctionCodeWriteItem100 D6991 CHANNEL
ModbusFunctionCodeWriteItem11 D6101 CHANNEL
ModbusFunctionCodeWriteItem12 D6111 CHANNEL
ModbusFunctionCodeWriteItem13 D6121 CHANNEL
ModbusFunctionCodeWriteItem14 D6131 CHANNEL
ModbusFunctionCodeWriteItem15 D6141 CHANNEL
ModbusFunctionCodeWriteItem16 D6151 CHANNEL
ModbusFunctionCodeWriteItem17 D6161 CHANNEL
ModbusFunctionCodeWriteItem18 D6171 CHANNEL
ModbusFunctionCodeWriteItem19 D6181 CHANNEL
ModbusFunctionCodeWriteItem2 D6011 CHANNEL
ModbusFunctionCodeWriteItem20 D6191 CHANNEL
ModbusFunctionCodeWriteItem21 D6201 CHANNEL
ModbusFunctionCodeWriteItem22 D6211 CHANNEL
ModbusFunctionCodeWriteItem23 D6221 CHANNEL
ModbusFunctionCodeWriteItem24 D6231 CHANNEL
ModbusFunctionCodeWriteItem25 D6241 CHANNEL
ModbusFunctionCodeWriteItem26 D6251 CHANNEL
ModbusFunctionCodeWriteItem27 D6261 CHANNEL
ModbusFunctionCodeWriteItem28 D6271 CHANNEL
ModbusFunctionCodeWriteItem29 D6281 CHANNEL
ModbusFunctionCodeWriteItem3 D6021 CHANNEL
ModbusFunctionCodeWriteItem30 D6291 CHANNEL
ModbusFunctionCodeWriteItem31 D6301 CHANNEL
ModbusFunctionCodeWriteItem32 D6311 CHANNEL
ModbusFunctionCodeWriteItem33 D6321 CHANNEL
ModbusFunctionCodeWriteItem34 D6331 CHANNEL
ModbusFunctionCodeWriteItem35 D6341 CHANNEL
ModbusFunctionCodeWriteItem36 D6351 CHANNEL
ModbusFunctionCodeWriteItem37 D6361 CHANNEL
ModbusFunctionCodeWriteItem38 D6371 CHANNEL
ModbusFunctionCodeWriteItem39 D6381 CHANNEL
ModbusFunctionCodeWriteItem4 D6031 CHANNEL
ModbusFunctionCodeWriteItem40 D6391 CHANNEL
ModbusFunctionCodeWriteItem41 D6401 CHANNEL
ModbusFunctionCodeWriteItem42 D6411 CHANNEL
ModbusFunctionCodeWriteItem43 D6421 CHANNEL
ModbusFunctionCodeWriteItem44 D6431 CHANNEL
ModbusFunctionCodeWriteItem45 D6441 CHANNEL
ModbusFunctionCodeWriteItem46 D6451 CHANNEL
ModbusFunctionCodeWriteItem47 D6461 CHANNEL
ModbusFunctionCodeWriteItem48 D6471 CHANNEL
ModbusFunctionCodeWriteItem49 D6481 CHANNEL
ModbusFunctionCodeWriteItem5 D6041 CHANNEL
ModbusFunctionCodeWriteItem50 D6491 CHANNEL
ModbusFunctionCodeWriteItem51 D6501 CHANNEL
ModbusFunctionCodeWriteItem52 D6511 CHANNEL
ModbusFunctionCodeWriteItem53 D6521 CHANNEL
ModbusFunctionCodeWriteItem54 D6531 CHANNEL
ModbusFunctionCodeWriteItem55 D6541 CHANNEL
ModbusFunctionCodeWriteItem56 D6551 CHANNEL
ModbusFunctionCodeWriteItem57 D6561 CHANNEL
ModbusFunctionCodeWriteItem58 D6571 CHANNEL
ModbusFunctionCodeWriteItem59 D6581 CHANNEL
ModbusFunctionCodeWriteItem6 D6051 CHANNEL
ModbusFunctionCodeWriteItem60 D6591 CHANNEL
ModbusFunctionCodeWriteItem61 D6601 CHANNEL
ModbusFunctionCodeWriteItem62 D6611 CHANNEL
ModbusFunctionCodeWriteItem63 D6621 CHANNEL
ModbusFunctionCodeWriteItem64 D6631 CHANNEL
ModbusFunctionCodeWriteItem65 D6641 CHANNEL
ModbusFunctionCodeWriteItem66 D6651 CHANNEL
ModbusFunctionCodeWriteItem67 D6661 CHANNEL
ModbusFunctionCodeWriteItem68 D6671 CHANNEL
ModbusFunctionCodeWriteItem69 D6681 CHANNEL
ModbusFunctionCodeWriteItem7 D6061 CHANNEL
ModbusFunctionCodeWriteItem70 D6691 CHANNEL
ModbusFunctionCodeWriteItem71 D6701 CHANNEL
ModbusFunctionCodeWriteItem72 D6711 CHANNEL
ModbusFunctionCodeWriteItem73 D6721 CHANNEL
ModbusFunctionCodeWriteItem74 D6731 CHANNEL
ModbusFunctionCodeWriteItem75 D6741 CHANNEL
ModbusFunctionCodeWriteItem76 D6751 CHANNEL
ModbusFunctionCodeWriteItem77 D6761 CHANNEL
ModbusFunctionCodeWriteItem78 D6771 CHANNEL
ModbusFunctionCodeWriteItem79 D6781 CHANNEL
ModbusFunctionCodeWriteItem8 D6071 CHANNEL
ModbusFunctionCodeWriteItem80 D6791 CHANNEL
ModbusFunctionCodeWriteItem81 D6801 CHANNEL
ModbusFunctionCodeWriteItem82 D6811 CHANNEL
ModbusFunctionCodeWriteItem83 D6821 CHANNEL
ModbusFunctionCodeWriteItem84 D6831 CHANNEL
ModbusFunctionCodeWriteItem85 D6841 CHANNEL
ModbusFunctionCodeWriteItem86 D6851 CHANNEL
ModbusFunctionCodeWriteItem87 D6861 CHANNEL
ModbusFunctionCodeWriteItem88 D6871 CHANNEL
ModbusFunctionCodeWriteItem89 D6881 CHANNEL
ModbusFunctionCodeWriteItem9 D6081 CHANNEL
ModbusFunctionCodeWriteItem90 D6891 CHANNEL
ModbusFunctionCodeWriteItem91 D6901 CHANNEL
ModbusFunctionCodeWriteItem92 D6911 CHANNEL
ModbusFunctionCodeWriteItem93 D6921 CHANNEL
ModbusFunctionCodeWriteItem94 D6931 CHANNEL
ModbusFunctionCodeWriteItem95 D6941 CHANNEL
ModbusFunctionCodeWriteItem96 D6951 CHANNEL
ModbusFunctionCodeWriteItem97 D6961 CHANNEL
ModbusFunctionCodeWriteItem98 D6971 CHANNEL
ModbusFunctionCodeWriteItem99 D6981 CHANNEL
ModbusNodeNumberReadItem1 D5000 CHANNEL
ModbusNodeNumberReadItem10 D5090 CHANNEL
ModbusNodeNumberReadItem100 D5990 CHANNEL
ModbusNodeNumberReadItem11 D5100 CHANNEL
ModbusNodeNumberReadItem12 D5110 CHANNEL
ModbusNodeNumberReadItem13 D5120 CHANNEL
ModbusNodeNumberReadItem14 D5130 CHANNEL
ModbusNodeNumberReadItem15 D5140 CHANNEL
ModbusNodeNumberReadItem16 D5150 CHANNEL
ModbusNodeNumberReadItem17 D5160 CHANNEL
ModbusNodeNumberReadItem18 D5170 CHANNEL
ModbusNodeNumberReadItem19 D5180 CHANNEL
ModbusNodeNumberReadItem2 D5010 CHANNEL
ModbusNodeNumberReadItem20 D5190 CHANNEL
ModbusNodeNumberReadItem21 D5200 CHANNEL
ModbusNodeNumberReadItem22 D5210 CHANNEL
ModbusNodeNumberReadItem23 D5220 CHANNEL
ModbusNodeNumberReadItem24 D5230 CHANNEL
ModbusNodeNumberReadItem25 D5240 CHANNEL
ModbusNodeNumberReadItem26 D5250 CHANNEL
ModbusNodeNumberReadItem27 D5260 CHANNEL
ModbusNodeNumberReadItem28 D5270 CHANNEL
ModbusNodeNumberReadItem29 D5280 CHANNEL
ModbusNodeNumberReadItem3 D5020 CHANNEL
ModbusNodeNumberReadItem30 D5290 CHANNEL
ModbusNodeNumberReadItem31 D5300 CHANNEL
ModbusNodeNumberReadItem32 D5310 CHANNEL
ModbusNodeNumberReadItem33 D5320 CHANNEL
ModbusNodeNumberReadItem34 D5330 CHANNEL
ModbusNodeNumberReadItem35 D5340 CHANNEL
ModbusNodeNumberReadItem36 D5350 CHANNEL
ModbusNodeNumberReadItem37 D5360 CHANNEL
ModbusNodeNumberReadItem38 D5370 CHANNEL
ModbusNodeNumberReadItem39 D5380 CHANNEL
ModbusNodeNumberReadItem4 D5030 CHANNEL
ModbusNodeNumberReadItem40 D5390 CHANNEL
ModbusNodeNumberReadItem41 D5400 CHANNEL
ModbusNodeNumberReadItem42 D5410 CHANNEL
ModbusNodeNumberReadItem43 D5420 CHANNEL
ModbusNodeNumberReadItem44 D5430 CHANNEL
ModbusNodeNumberReadItem45 D5440 CHANNEL
ModbusNodeNumberReadItem46 D5450 CHANNEL
ModbusNodeNumberReadItem47 D5460 CHANNEL
ModbusNodeNumberReadItem48 D5470 CHANNEL
ModbusNodeNumberReadItem49 D5480 CHANNEL
ModbusNodeNumberReadItem5 D5040 CHANNEL
ModbusNodeNumberReadItem50 D5490 CHANNEL
ModbusNodeNumberReadItem51 D5500 CHANNEL
ModbusNodeNumberReadItem52 D5510 CHANNEL
ModbusNodeNumberReadItem53 D5520 CHANNEL
ModbusNodeNumberReadItem54 D5530 CHANNEL
ModbusNodeNumberReadItem55 D5540 CHANNEL
ModbusNodeNumberReadItem56 D5550 CHANNEL
ModbusNodeNumberReadItem57 D5560 CHANNEL
ModbusNodeNumberReadItem58 D5570 CHANNEL
ModbusNodeNumberReadItem59 D5580 CHANNEL
ModbusNodeNumberReadItem6 D5050 CHANNEL
ModbusNodeNumberReadItem60 D5590 CHANNEL
ModbusNodeNumberReadItem61 D5600 CHANNEL
ModbusNodeNumberReadItem62 D5610 CHANNEL
ModbusNodeNumberReadItem63 D5620 CHANNEL
ModbusNodeNumberReadItem64 D5630 CHANNEL
ModbusNodeNumberReadItem65 D5640 CHANNEL
ModbusNodeNumberReadItem66 D5650 CHANNEL
ModbusNodeNumberReadItem67 D5660 CHANNEL
ModbusNodeNumberReadItem68 D5670 CHANNEL
ModbusNodeNumberReadItem69 D5680 CHANNEL
ModbusNodeNumberReadItem7 D5060 CHANNEL
ModbusNodeNumberReadItem70 D5690 CHANNEL
ModbusNodeNumberReadItem71 D5700 CHANNEL
ModbusNodeNumberReadItem72 D5710 CHANNEL
ModbusNodeNumberReadItem73 D5720 CHANNEL
ModbusNodeNumberReadItem74 D5730 CHANNEL
ModbusNodeNumberReadItem75 D5740 CHANNEL
ModbusNodeNumberReadItem76 D5750 CHANNEL
ModbusNodeNumberReadItem77 D5760 CHANNEL
ModbusNodeNumberReadItem78 D5770 CHANNEL
ModbusNodeNumberReadItem79 D5780 CHANNEL
ModbusNodeNumberReadItem8 D5070 CHANNEL
ModbusNodeNumberReadItem80 D5790 CHANNEL
ModbusNodeNumberReadItem81 D5800 CHANNEL
ModbusNodeNumberReadItem82 D5810 CHANNEL
ModbusNodeNumberReadItem83 D5820 CHANNEL
ModbusNodeNumberReadItem84 D5830 CHANNEL
ModbusNodeNumberReadItem85 D5840 CHANNEL
ModbusNodeNumberReadItem86 D5850 CHANNEL
ModbusNodeNumberReadItem87 D5860 CHANNEL
ModbusNodeNumberReadItem88 D5870 CHANNEL
ModbusNodeNumberReadItem89 D5880 CHANNEL
ModbusNodeNumberReadItem9 D5080 CHANNEL
ModbusNodeNumberReadItem90 D5890 CHANNEL
ModbusNodeNumberReadItem91 D5900 CHANNEL
ModbusNodeNumberReadItem92 D5910 CHANNEL
ModbusNodeNumberReadItem93 D5920 CHANNEL
ModbusNodeNumberReadItem94 D5930 CHANNEL
ModbusNodeNumberReadItem95 D5940 CHANNEL
ModbusNodeNumberReadItem96 D5950 CHANNEL
ModbusNodeNumberReadItem97 D5960 CHANNEL
ModbusNodeNumberReadItem98 D5970 CHANNEL
ModbusNodeNumberReadItem99 D5980 CHANNEL
ModbusNodeNumberWriteItem1 D6000 CHANNEL
ModbusNodeNumberWriteItem10 D6090 CHANNEL
ModbusNodeNumberWriteItem100 D6990 CHANNEL
ModbusNodeNumberWriteItem11 D6100 CHANNEL
ModbusNodeNumberWriteItem12 D6110 CHANNEL
ModbusNodeNumberWriteItem13 D6120 CHANNEL
ModbusNodeNumberWriteItem14 D6130 CHANNEL
ModbusNodeNumberWriteItem15 D6140 CHANNEL
ModbusNodeNumberWriteItem16 D6150 CHANNEL
ModbusNodeNumberWriteItem17 D6160 CHANNEL
ModbusNodeNumberWriteItem18 D6170 CHANNEL
ModbusNodeNumberWriteItem19 D6180 CHANNEL
ModbusNodeNumberWriteItem2 D6010 CHANNEL
ModbusNodeNumberWriteItem20 D6190 CHANNEL
ModbusNodeNumberWriteItem21 D6200 CHANNEL
ModbusNodeNumberWriteItem22 D6210 CHANNEL
ModbusNodeNumberWriteItem23 D6220 CHANNEL
ModbusNodeNumberWriteItem24 D6230 CHANNEL
ModbusNodeNumberWriteItem25 D6240 CHANNEL
ModbusNodeNumberWriteItem26 D6250 CHANNEL
ModbusNodeNumberWriteItem27 D6260 CHANNEL
ModbusNodeNumberWriteItem28 D6270 CHANNEL
ModbusNodeNumberWriteItem29 D6280 CHANNEL
ModbusNodeNumberWriteItem3 D6020 CHANNEL
ModbusNodeNumberWriteItem30 D6290 CHANNEL
ModbusNodeNumberWriteItem31 D6300 CHANNEL
ModbusNodeNumberWriteItem32 D6310 CHANNEL
ModbusNodeNumberWriteItem33 D6320 CHANNEL
ModbusNodeNumberWriteItem34 D6330 CHANNEL
ModbusNodeNumberWriteItem35 D6340 CHANNEL
ModbusNodeNumberWriteItem36 D6350 CHANNEL
ModbusNodeNumberWriteItem37 D6360 CHANNEL
ModbusNodeNumberWriteItem38 D6370 CHANNEL
ModbusNodeNumberWriteItem39 D6380 CHANNEL
ModbusNodeNumberWriteItem4 D6030 CHANNEL
ModbusNodeNumberWriteItem40 D6390 CHANNEL
ModbusNodeNumberWriteItem41 D6400 CHANNEL
ModbusNodeNumberWriteItem42 D6410 CHANNEL
ModbusNodeNumberWriteItem43 D6420 CHANNEL
ModbusNodeNumberWriteItem44 D6430 CHANNEL
ModbusNodeNumberWriteItem45 D6440 CHANNEL
ModbusNodeNumberWriteItem46 D6450 CHANNEL
ModbusNodeNumberWriteItem47 D6460 CHANNEL
ModbusNodeNumberWriteItem48 D6470 CHANNEL
ModbusNodeNumberWriteItem49 D6480 CHANNEL
ModbusNodeNumberWriteItem5 D6040 CHANNEL
ModbusNodeNumberWriteItem50 D6490 CHANNEL
ModbusNodeNumberWriteItem51 D6500 CHANNEL
ModbusNodeNumberWriteItem52 D6510 CHANNEL
ModbusNodeNumberWriteItem53 D6520 CHANNEL
ModbusNodeNumberWriteItem54 D6530 CHANNEL
ModbusNodeNumberWriteItem55 D6540 CHANNEL
ModbusNodeNumberWriteItem56 D6550 CHANNEL
ModbusNodeNumberWriteItem57 D6560 CHANNEL
ModbusNodeNumberWriteItem58 D6570 CHANNEL
ModbusNodeNumberWriteItem59 D6580 CHANNEL
ModbusNodeNumberWriteItem6 D6050 CHANNEL
ModbusNodeNumberWriteItem60 D6590 CHANNEL
ModbusNodeNumberWriteItem61 D6600 CHANNEL
ModbusNodeNumberWriteItem62 D6610 CHANNEL
ModbusNodeNumberWriteItem63 D6620 CHANNEL
ModbusNodeNumberWriteItem64 D6630 CHANNEL
ModbusNodeNumberWriteItem65 D6640 CHANNEL
ModbusNodeNumberWriteItem66 D6650 CHANNEL
ModbusNodeNumberWriteItem67 D6660 CHANNEL
ModbusNodeNumberWriteItem68 D6670 CHANNEL
ModbusNodeNumberWriteItem69 D6680 CHANNEL
ModbusNodeNumberWriteItem7 D6060 CHANNEL
ModbusNodeNumberWriteItem70 D6690 CHANNEL
ModbusNodeNumberWriteItem71 D6700 CHANNEL
ModbusNodeNumberWriteItem72 D6710 CHANNEL
ModbusNodeNumberWriteItem73 D6720 CHANNEL
ModbusNodeNumberWriteItem74 D6730 CHANNEL
ModbusNodeNumberWriteItem75 D6740 CHANNEL
ModbusNodeNumberWriteItem76 D6750 CHANNEL
ModbusNodeNumberWriteItem77 D6760 CHANNEL
ModbusNodeNumberWriteItem78 D6770 CHANNEL
ModbusNodeNumberWriteItem79 D6780 CHANNEL
ModbusNodeNumberWriteItem8 D6070 CHANNEL
ModbusNodeNumberWriteItem80 D6790 CHANNEL
ModbusNodeNumberWriteItem81 D6800 CHANNEL
ModbusNodeNumberWriteItem82 D6810 CHANNEL
ModbusNodeNumberWriteItem83 D6820 CHANNEL
ModbusNodeNumberWriteItem84 D6830 CHANNEL
ModbusNodeNumberWriteItem85 D6840 CHANNEL
ModbusNodeNumberWriteItem86 D6850 CHANNEL
ModbusNodeNumberWriteItem87 D6860 CHANNEL
ModbusNodeNumberWriteItem88 D6870 CHANNEL
ModbusNodeNumberWriteItem89 D6880 CHANNEL
ModbusNodeNumberWriteItem9 D6080 CHANNEL
ModbusNodeNumberWriteItem90 D6890 CHANNEL
ModbusNodeNumberWriteItem91 D6900 CHANNEL
ModbusNodeNumberWriteItem92 D6910 CHANNEL
ModbusNodeNumberWriteItem93 D6920 CHANNEL
ModbusNodeNumberWriteItem94 D6930 CHANNEL
ModbusNodeNumberWriteItem95 D6940 CHANNEL
ModbusNodeNumberWriteItem96 D6950 CHANNEL
ModbusNodeNumberWriteItem97 D6960 CHANNEL
ModbusNodeNumberWriteItem98 D6970 CHANNEL
ModbusNodeNumberWriteItem99 D6980 CHANNEL
NonResettingTimeoutCounter W209 CHANNEL
NotUsed1ReadItem1 D5006 CHANNEL
NotUsed1ReadItem10 D5096 CHANNEL
NotUsed1ReadItem100 D5996 CHANNEL
NotUsed1ReadItem11 D5106 CHANNEL
NotUsed1ReadItem12 D5116 CHANNEL
NotUsed1ReadItem13 D5126 CHANNEL
NotUsed1ReadItem14 D5136 CHANNEL
NotUsed1ReadItem15 D5146 CHANNEL
NotUsed1ReadItem16 D5156 CHANNEL
NotUsed1ReadItem17 D5166 CHANNEL
NotUsed1ReadItem18 D5176 CHANNEL
NotUsed1ReadItem19 D5186 CHANNEL
NotUsed1ReadItem2 D5016 CHANNEL
NotUsed1ReadItem20 D5196 CHANNEL
NotUsed1ReadItem21 D5206 CHANNEL
NotUsed1ReadItem22 D5216 CHANNEL
NotUsed1ReadItem23 D5226 CHANNEL
NotUsed1ReadItem24 D5236 CHANNEL
NotUsed1ReadItem25 D5246 CHANNEL
NotUsed1ReadItem26 D5256 CHANNEL
NotUsed1ReadItem27 D5266 CHANNEL
NotUsed1ReadItem28 D5276 CHANNEL
NotUsed1ReadItem29 D5286 CHANNEL
NotUsed1ReadItem3 D5026 CHANNEL
NotUsed1ReadItem30 D5296 CHANNEL
NotUsed1ReadItem31 D5306 CHANNEL
NotUsed1ReadItem32 D5316 CHANNEL
NotUsed1ReadItem33 D5326 CHANNEL
NotUsed1ReadItem34 D5336 CHANNEL
NotUsed1ReadItem35 D5346 CHANNEL
NotUsed1ReadItem36 D5356 CHANNEL
NotUsed1ReadItem37 D5366 CHANNEL
NotUsed1ReadItem38 D5376 CHANNEL
NotUsed1ReadItem39 D5386 CHANNEL
NotUsed1ReadItem4 D5036 CHANNEL
NotUsed1ReadItem40 D5396 CHANNEL
NotUsed1ReadItem41 D5406 CHANNEL
NotUsed1ReadItem42 D5416 CHANNEL
NotUsed1ReadItem43 D5426 CHANNEL
NotUsed1ReadItem44 D5436 CHANNEL
NotUsed1ReadItem45 D5446 CHANNEL
NotUsed1ReadItem46 D5456 CHANNEL
NotUsed1ReadItem47 D5466 CHANNEL
NotUsed1ReadItem48 D5476 CHANNEL
NotUsed1ReadItem49 D5486 CHANNEL
NotUsed1ReadItem5 D5046 CHANNEL
NotUsed1ReadItem50 D5496 CHANNEL
NotUsed1ReadItem51 D5506 CHANNEL
NotUsed1ReadItem52 D5516 CHANNEL
NotUsed1ReadItem53 D5526 CHANNEL
NotUsed1ReadItem54 D5536 CHANNEL
NotUsed1ReadItem55 D5546 CHANNEL
NotUsed1ReadItem56 D5556 CHANNEL
NotUsed1ReadItem57 D5566 CHANNEL
NotUsed1ReadItem58 D5576 CHANNEL
NotUsed1ReadItem59 D5586 CHANNEL
NotUsed1ReadItem6 D5056 CHANNEL
NotUsed1ReadItem60 D5596 CHANNEL
NotUsed1ReadItem61 D5606 CHANNEL
NotUsed1ReadItem62 D5616 CHANNEL
NotUsed1ReadItem63 D5626 CHANNEL
NotUsed1ReadItem64 D5636 CHANNEL
NotUsed1ReadItem65 D5646 CHANNEL
NotUsed1ReadItem66 D5656 CHANNEL
NotUsed1ReadItem67 D5666 CHANNEL
NotUsed1ReadItem68 D5676 CHANNEL
NotUsed1ReadItem69 D5686 CHANNEL
NotUsed1ReadItem7 D5066 CHANNEL
NotUsed1ReadItem70 D5696 CHANNEL
NotUsed1ReadItem71 D5706 CHANNEL
NotUsed1ReadItem72 D5716 CHANNEL
NotUsed1ReadItem73 D5726 CHANNEL
NotUsed1ReadItem74 D5736 CHANNEL
NotUsed1ReadItem75 D5746 CHANNEL
NotUsed1ReadItem76 D5756 CHANNEL
NotUsed1ReadItem77 D5766 CHANNEL
NotUsed1ReadItem78 D5776 CHANNEL
NotUsed1ReadItem79 D5786 CHANNEL
NotUsed1ReadItem8 D5076 CHANNEL
NotUsed1ReadItem80 D5796 CHANNEL
NotUsed1ReadItem81 D5806 CHANNEL
NotUsed1ReadItem82 D5816 CHANNEL
NotUsed1ReadItem83 D5826 CHANNEL
NotUsed1ReadItem84 D5836 CHANNEL
NotUsed1ReadItem85 D5846 CHANNEL
NotUsed1ReadItem86 D5856 CHANNEL
NotUsed1ReadItem87 D5866 CHANNEL
NotUsed1ReadItem88 D5876 CHANNEL
NotUsed1ReadItem89 D5886 CHANNEL
NotUsed1ReadItem9 D5086 CHANNEL
NotUsed1ReadItem90 D5896 CHANNEL
NotUsed1ReadItem91 D5906 CHANNEL
NotUsed1ReadItem92 D5916 CHANNEL
NotUsed1ReadItem93 D5926 CHANNEL
NotUsed1ReadItem94 D5936 CHANNEL
NotUsed1ReadItem95 D5946 CHANNEL
NotUsed1ReadItem96 D5956 CHANNEL
NotUsed1ReadItem97 D5966 CHANNEL
NotUsed1ReadItem98 D5976 CHANNEL
NotUsed1ReadItem99 D5986 CHANNEL
NotUsed2ReadItem1 D5007 CHANNEL
NotUsed2ReadItem10 D5097 CHANNEL
NotUsed2ReadItem100 D5997 CHANNEL
NotUsed2ReadItem11 D5107 CHANNEL
NotUsed2ReadItem12 D5117 CHANNEL
NotUsed2ReadItem13 D5127 CHANNEL
NotUsed2ReadItem14 D5137 CHANNEL
NotUsed2ReadItem15 D5147 CHANNEL
NotUsed2ReadItem16 D5157 CHANNEL
NotUsed2ReadItem17 D5167 CHANNEL
NotUsed2ReadItem18 D5177 CHANNEL
NotUsed2ReadItem19 D5187 CHANNEL
NotUsed2ReadItem2 D5017 CHANNEL
NotUsed2ReadItem20 D5197 CHANNEL
NotUsed2ReadItem21 D5207 CHANNEL
NotUsed2ReadItem22 D5217 CHANNEL
NotUsed2ReadItem23 D5227 CHANNEL
NotUsed2ReadItem24 D5237 CHANNEL
NotUsed2ReadItem25 D5247 CHANNEL
NotUsed2ReadItem26 D5257 CHANNEL
NotUsed2ReadItem27 D5267 CHANNEL
NotUsed2ReadItem28 D5277 CHANNEL
NotUsed2ReadItem29 D5287 CHANNEL
NotUsed2ReadItem3 D5027 CHANNEL
NotUsed2ReadItem30 D5297 CHANNEL
NotUsed2ReadItem31 D5307 CHANNEL
NotUsed2ReadItem32 D5317 CHANNEL
NotUsed2ReadItem33 D5327 CHANNEL
NotUsed2ReadItem34 D5337 CHANNEL
NotUsed2ReadItem35 D5347 CHANNEL
NotUsed2ReadItem36 D5357 CHANNEL
NotUsed2ReadItem37 D5367 CHANNEL
NotUsed2ReadItem38 D5377 CHANNEL
NotUsed2ReadItem39 D5387 CHANNEL
NotUsed2ReadItem4 D5037 CHANNEL
NotUsed2ReadItem40 D5397 CHANNEL
NotUsed2ReadItem41 D5407 CHANNEL
NotUsed2ReadItem42 D5417 CHANNEL
NotUsed2ReadItem43 D5427 CHANNEL
NotUsed2ReadItem44 D5437 CHANNEL
NotUsed2ReadItem45 D5447 CHANNEL
NotUsed2ReadItem46 D5457 CHANNEL
NotUsed2ReadItem47 D5467 CHANNEL
NotUsed2ReadItem48 D5477 CHANNEL
NotUsed2ReadItem49 D5487 CHANNEL
NotUsed2ReadItem5 D5047 CHANNEL
NotUsed2ReadItem50 D5497 CHANNEL
NotUsed2ReadItem51 D5507 CHANNEL
NotUsed2ReadItem52 D5517 CHANNEL
NotUsed2ReadItem53 D5527 CHANNEL
NotUsed2ReadItem54 D5537 CHANNEL
NotUsed2ReadItem55 D5547 CHANNEL
NotUsed2ReadItem56 D5557 CHANNEL
NotUsed2ReadItem57 D5567 CHANNEL
NotUsed2ReadItem58 D5577 CHANNEL
NotUsed2ReadItem59 D5587 CHANNEL
NotUsed2ReadItem6 D5057 CHANNEL
NotUsed2ReadItem60 D5597 CHANNEL
NotUsed2ReadItem61 D5607 CHANNEL
NotUsed2ReadItem62 D5617 CHANNEL
NotUsed2ReadItem63 D5627 CHANNEL
NotUsed2ReadItem64 D5637 CHANNEL
NotUsed2ReadItem65 D5647 CHANNEL
NotUsed2ReadItem66 D5657 CHANNEL
NotUsed2ReadItem67 D5667 CHANNEL
NotUsed2ReadItem68 D5677 CHANNEL
NotUsed2ReadItem69 D5687 CHANNEL
NotUsed2ReadItem7 D5067 CHANNEL
NotUsed2ReadItem70 D5697 CHANNEL
NotUsed2ReadItem71 D5707 CHANNEL
NotUsed2ReadItem72 D5717 CHANNEL
NotUsed2ReadItem73 D5727 CHANNEL
NotUsed2ReadItem74 D5737 CHANNEL
NotUsed2ReadItem75 D5747 CHANNEL
NotUsed2ReadItem76 D5757 CHANNEL
NotUsed2ReadItem77 D5767 CHANNEL
NotUsed2ReadItem78 D5777 CHANNEL
NotUsed2ReadItem79 D5787 CHANNEL
NotUsed2ReadItem8 D5077 CHANNEL
NotUsed2ReadItem80 D5797 CHANNEL
NotUsed2ReadItem81 D5807 CHANNEL
NotUsed2ReadItem82 D5817 CHANNEL
NotUsed2ReadItem83 D5827 CHANNEL
NotUsed2ReadItem84 D5837 CHANNEL
NotUsed2ReadItem85 D5847 CHANNEL
NotUsed2ReadItem86 D5857 CHANNEL
NotUsed2ReadItem87 D5867 CHANNEL
NotUsed2ReadItem88 D5877 CHANNEL
NotUsed2ReadItem89 D5887 CHANNEL
NotUsed2ReadItem9 D5087 CHANNEL
NotUsed2ReadItem90 D5897 CHANNEL
NotUsed2ReadItem91 D5907 CHANNEL
NotUsed2ReadItem92 D5917 CHANNEL
NotUsed2ReadItem93 D5927 CHANNEL
NotUsed2ReadItem94 D5937 CHANNEL
NotUsed2ReadItem95 D5947 CHANNEL
NotUsed2ReadItem96 D5957 CHANNEL
NotUsed2ReadItem97 D5967 CHANNEL
NotUsed2ReadItem98 D5977 CHANNEL
NotUsed2ReadItem99 D5987 CHANNEL
NumberOfItemsToReadReadItem1 D5003 CHANNEL
NumberOfItemsToReadReadItem10 D5093 CHANNEL
NumberOfItemsToReadReadItem100 D5993 CHANNEL
NumberOfItemsToReadReadItem11 D5103 CHANNEL
NumberOfItemsToReadReadItem12 D5113 CHANNEL
NumberOfItemsToReadReadItem13 D5123 CHANNEL
NumberOfItemsToReadReadItem14 D5133 CHANNEL
NumberOfItemsToReadReadItem15 D5143 CHANNEL
NumberOfItemsToReadReadItem16 D5153 CHANNEL
NumberOfItemsToReadReadItem17 D5163 CHANNEL
NumberOfItemsToReadReadItem18 D5173 CHANNEL
NumberOfItemsToReadReadItem19 D5183 CHANNEL
NumberOfItemsToReadReadItem2 D5013 CHANNEL
NumberOfItemsToReadReadItem20 D5193 CHANNEL
NumberOfItemsToReadReadItem21 D5203 CHANNEL
NumberOfItemsToReadReadItem22 D5213 CHANNEL
NumberOfItemsToReadReadItem23 D5223 CHANNEL
NumberOfItemsToReadReadItem24 D5233 CHANNEL
NumberOfItemsToReadReadItem25 D5243 CHANNEL
NumberOfItemsToReadReadItem26 D5253 CHANNEL
NumberOfItemsToReadReadItem27 D5263 CHANNEL
NumberOfItemsToReadReadItem28 D5273 CHANNEL
NumberOfItemsToReadReadItem29 D5283 CHANNEL
NumberOfItemsToReadReadItem3 D5023 CHANNEL
NumberOfItemsToReadReadItem30 D5293 CHANNEL
NumberOfItemsToReadReadItem31 D5303 CHANNEL
NumberOfItemsToReadReadItem32 D5313 CHANNEL
NumberOfItemsToReadReadItem33 D5323 CHANNEL
NumberOfItemsToReadReadItem34 D5333 CHANNEL
NumberOfItemsToReadReadItem35 D5343 CHANNEL
NumberOfItemsToReadReadItem36 D5353 CHANNEL
NumberOfItemsToReadReadItem37 D5363 CHANNEL
NumberOfItemsToReadReadItem38 D5373 CHANNEL
NumberOfItemsToReadReadItem39 D5383 CHANNEL
NumberOfItemsToReadReadItem4 D5033 CHANNEL
NumberOfItemsToReadReadItem40 D5393 CHANNEL
NumberOfItemsToReadReadItem41 D5403 CHANNEL
NumberOfItemsToReadReadItem42 D5413 CHANNEL
NumberOfItemsToReadReadItem43 D5423 CHANNEL
NumberOfItemsToReadReadItem44 D5433 CHANNEL
NumberOfItemsToReadReadItem45 D5443 CHANNEL
NumberOfItemsToReadReadItem46 D5453 CHANNEL
NumberOfItemsToReadReadItem47 D5463 CHANNEL
NumberOfItemsToReadReadItem48 D5473 CHANNEL
NumberOfItemsToReadReadItem49 D5483 CHANNEL
NumberOfItemsToReadReadItem5 D5043 CHANNEL
NumberOfItemsToReadReadItem50 D5493 CHANNEL
NumberOfItemsToReadReadItem51 D5503 CHANNEL
NumberOfItemsToReadReadItem52 D5513 CHANNEL
NumberOfItemsToReadReadItem53 D5523 CHANNEL
NumberOfItemsToReadReadItem54 D5533 CHANNEL
NumberOfItemsToReadReadItem55 D5543 CHANNEL
NumberOfItemsToReadReadItem56 D5553 CHANNEL
NumberOfItemsToReadReadItem57 D5563 CHANNEL
NumberOfItemsToReadReadItem58 D5573 CHANNEL
NumberOfItemsToReadReadItem59 D5583 CHANNEL
NumberOfItemsToReadReadItem6 D5053 CHANNEL
NumberOfItemsToReadReadItem60 D5593 CHANNEL
NumberOfItemsToReadReadItem61 D5603 CHANNEL
NumberOfItemsToReadReadItem62 D5613 CHANNEL
NumberOfItemsToReadReadItem63 D5623 CHANNEL
NumberOfItemsToReadReadItem64 D5633 CHANNEL
NumberOfItemsToReadReadItem65 D5643 CHANNEL
NumberOfItemsToReadReadItem66 D5653 CHANNEL
NumberOfItemsToReadReadItem67 D5663 CHANNEL
NumberOfItemsToReadReadItem68 D5673 CHANNEL
NumberOfItemsToReadReadItem69 D5683 CHANNEL
NumberOfItemsToReadReadItem7 D5063 CHANNEL
NumberOfItemsToReadReadItem70 D5693 CHANNEL
NumberOfItemsToReadReadItem71 D5703 CHANNEL
NumberOfItemsToReadReadItem72 D5713 CHANNEL
NumberOfItemsToReadReadItem73 D5723 CHANNEL
NumberOfItemsToReadReadItem74 D5733 CHANNEL
NumberOfItemsToReadReadItem75 D5743 CHANNEL
NumberOfItemsToReadReadItem76 D5753 CHANNEL
NumberOfItemsToReadReadItem77 D5763 CHANNEL
NumberOfItemsToReadReadItem78 D5773 CHANNEL
NumberOfItemsToReadReadItem79 D5783 CHANNEL
NumberOfItemsToReadReadItem8 D5073 CHANNEL
NumberOfItemsToReadReadItem80 D5793 CHANNEL
NumberOfItemsToReadReadItem81 D5803 CHANNEL
NumberOfItemsToReadReadItem82 D5813 CHANNEL
NumberOfItemsToReadReadItem83 D5823 CHANNEL
NumberOfItemsToReadReadItem84 D5833 CHANNEL
NumberOfItemsToReadReadItem85 D5843 CHANNEL
NumberOfItemsToReadReadItem86 D5853 CHANNEL
NumberOfItemsToReadReadItem87 D5863 CHANNEL
NumberOfItemsToReadReadItem88 D5873 CHANNEL
NumberOfItemsToReadReadItem89 D5883 CHANNEL
NumberOfItemsToReadReadItem9 D5083 CHANNEL
NumberOfItemsToReadReadItem90 D5893 CHANNEL
NumberOfItemsToReadReadItem91 D5903 CHANNEL
NumberOfItemsToReadReadItem92 D5913 CHANNEL
NumberOfItemsToReadReadItem93 D5923 CHANNEL
NumberOfItemsToReadReadItem94 D5933 CHANNEL
NumberOfItemsToReadReadItem95 D5943 CHANNEL
NumberOfItemsToReadReadItem96 D5953 CHANNEL
NumberOfItemsToReadReadItem97 D5963 CHANNEL
NumberOfItemsToReadReadItem98 D5973 CHANNEL
NumberOfItemsToReadReadItem99 D5983 CHANNEL
NumberOfItemsToWriteWriteItem1 D6003 CHANNEL
NumberOfItemsToWriteWriteItem10 D6093 CHANNEL
NumberOfItemsToWriteWriteItem100 D6993 CHANNEL
NumberOfItemsToWriteWriteItem11 D6103 CHANNEL
NumberOfItemsToWriteWriteItem12 D6113 CHANNEL
NumberOfItemsToWriteWriteItem13 D6123 CHANNEL
NumberOfItemsToWriteWriteItem14 D6133 CHANNEL
NumberOfItemsToWriteWriteItem15 D6143 CHANNEL
NumberOfItemsToWriteWriteItem16 D6153 CHANNEL
NumberOfItemsToWriteWriteItem17 D6163 CHANNEL
NumberOfItemsToWriteWriteItem18 D6173 CHANNEL
NumberOfItemsToWriteWriteItem19 D6183 CHANNEL
NumberOfItemsToWriteWriteItem2 D6013 CHANNEL
NumberOfItemsToWriteWriteItem20 D6193 CHANNEL
NumberOfItemsToWriteWriteItem21 D6203 CHANNEL
NumberOfItemsToWriteWriteItem22 D6213 CHANNEL
NumberOfItemsToWriteWriteItem23 D6223 CHANNEL
NumberOfItemsToWriteWriteItem24 D6233 CHANNEL
NumberOfItemsToWriteWriteItem25 D6243 CHANNEL
NumberOfItemsToWriteWriteItem26 D6253 CHANNEL
NumberOfItemsToWriteWriteItem27 D6263 CHANNEL
NumberOfItemsToWriteWriteItem28 D6273 CHANNEL
NumberOfItemsToWriteWriteItem29 D6283 CHANNEL
NumberOfItemsToWriteWriteItem3 D6023 CHANNEL
NumberOfItemsToWriteWriteItem30 D6293 CHANNEL
NumberOfItemsToWriteWriteItem31 D6303 CHANNEL
NumberOfItemsToWriteWriteItem32 D6313 CHANNEL
NumberOfItemsToWriteWriteItem33 D6323 CHANNEL
NumberOfItemsToWriteWriteItem34 D6333 CHANNEL
NumberOfItemsToWriteWriteItem35 D6343 CHANNEL
NumberOfItemsToWriteWriteItem36 D6353 CHANNEL
NumberOfItemsToWriteWriteItem37 D6363 CHANNEL
NumberOfItemsToWriteWriteItem38 D6373 CHANNEL
NumberOfItemsToWriteWriteItem39 D6383 CHANNEL
NumberOfItemsToWriteWriteItem4 D6033 CHANNEL
NumberOfItemsToWriteWriteItem40 D6393 CHANNEL
NumberOfItemsToWriteWriteItem41 D6403 CHANNEL
NumberOfItemsToWriteWriteItem42 D6413 CHANNEL
NumberOfItemsToWriteWriteItem43 D6423 CHANNEL
NumberOfItemsToWriteWriteItem44 D6433 CHANNEL
NumberOfItemsToWriteWriteItem45 D6443 CHANNEL
NumberOfItemsToWriteWriteItem46 D6453 CHANNEL
NumberOfItemsToWriteWriteItem47 D6463 CHANNEL
NumberOfItemsToWriteWriteItem48 D6473 CHANNEL
NumberOfItemsToWriteWriteItem49 D6483 CHANNEL
NumberOfItemsToWriteWriteItem5 D6043 CHANNEL
NumberOfItemsToWriteWriteItem50 D6493 CHANNEL
NumberOfItemsToWriteWriteItem51 D6503 CHANNEL
NumberOfItemsToWriteWriteItem52 D6513 CHANNEL
NumberOfItemsToWriteWriteItem53 D6523 CHANNEL
NumberOfItemsToWriteWriteItem54 D6533 CHANNEL
NumberOfItemsToWriteWriteItem55 D6543 CHANNEL
NumberOfItemsToWriteWriteItem56 D6553 CHANNEL
NumberOfItemsToWriteWriteItem57 D6563 CHANNEL
NumberOfItemsToWriteWriteItem58 D6573 CHANNEL
NumberOfItemsToWriteWriteItem59 D6583 CHANNEL
NumberOfItemsToWriteWriteItem6 D6053 CHANNEL
NumberOfItemsToWriteWriteItem60 D6593 CHANNEL
NumberOfItemsToWriteWriteItem61 D6603 CHANNEL
NumberOfItemsToWriteWriteItem62 D6613 CHANNEL
NumberOfItemsToWriteWriteItem63 D6623 CHANNEL
NumberOfItemsToWriteWriteItem64 D6633 CHANNEL
NumberOfItemsToWriteWriteItem65 D6643 CHANNEL
NumberOfItemsToWriteWriteItem66 D6653 CHANNEL
NumberOfItemsToWriteWriteItem67 D6663 CHANNEL
NumberOfItemsToWriteWriteItem68 D6673 CHANNEL
NumberOfItemsToWriteWriteItem69 D6683 CHANNEL
NumberOfItemsToWriteWriteItem7 D6063 CHANNEL
NumberOfItemsToWriteWriteItem70 D6693 CHANNEL
NumberOfItemsToWriteWriteItem71 D6703 CHANNEL
NumberOfItemsToWriteWriteItem72 D6713 CHANNEL
NumberOfItemsToWriteWriteItem73 D6723 CHANNEL
NumberOfItemsToWriteWriteItem74 D6733 CHANNEL
NumberOfItemsToWriteWriteItem75 D6743 CHANNEL
NumberOfItemsToWriteWriteItem76 D6753 CHANNEL
NumberOfItemsToWriteWriteItem77 D6763 CHANNEL
NumberOfItemsToWriteWriteItem78 D6773 CHANNEL
NumberOfItemsToWriteWriteItem79 D6783 CHANNEL
NumberOfItemsToWriteWriteItem8 D6073 CHANNEL
NumberOfItemsToWriteWriteItem80 D6793 CHANNEL
NumberOfItemsToWriteWriteItem81 D6803 CHANNEL
NumberOfItemsToWriteWriteItem82 D6813 CHANNEL
NumberOfItemsToWriteWriteItem83 D6823 CHANNEL
NumberOfItemsToWriteWriteItem84 D6833 CHANNEL
NumberOfItemsToWriteWriteItem85 D6843 CHANNEL
NumberOfItemsToWriteWriteItem86 D6853 CHANNEL
NumberOfItemsToWriteWriteItem87 D6863 CHANNEL
NumberOfItemsToWriteWriteItem88 D6873 CHANNEL
NumberOfItemsToWriteWriteItem89 D6883 CHANNEL
NumberOfItemsToWriteWriteItem9 D6083 CHANNEL
NumberOfItemsToWriteWriteItem90 D6893 CHANNEL
NumberOfItemsToWriteWriteItem91 D6903 CHANNEL
NumberOfItemsToWriteWriteItem92 D6913 CHANNEL
NumberOfItemsToWriteWriteItem93 D6923 CHANNEL
NumberOfItemsToWriteWriteItem94 D6933 CHANNEL
NumberOfItemsToWriteWriteItem95 D6943 CHANNEL
NumberOfItemsToWriteWriteItem96 D6953 CHANNEL
NumberOfItemsToWriteWriteItem97 D6963 CHANNEL
NumberOfItemsToWriteWriteItem98 D6973 CHANNEL
NumberOfItemsToWriteWriteItem99 D6983 CHANNEL
PMCR_Busy 1884.15 BOOL
PMCR_Complete_NG 1884.10 BOOL
PMCR_Complete_OK 1884.11 BOOL
Polling_Has_Occurred W215.02 BOOL
Port_1_Error A392.04 BOOL
Port_Needs_To_Be_Reset W205.02 BOOL  ; Waiting for Easy Modbus to finish current command
Port_Now_Resetting W205.03 BOOL
ReadValidOrInvalidReadItem1 D5008 CHANNEL
ReadValidOrInvalidReadItem10 D5098 CHANNEL
ReadValidOrInvalidReadItem100 D5998 CHANNEL
ReadValidOrInvalidReadItem11 D5108 CHANNEL
ReadValidOrInvalidReadItem12 D5118 CHANNEL
ReadValidOrInvalidReadItem13 D5128 CHANNEL
ReadValidOrInvalidReadItem14 D5138 CHANNEL
ReadValidOrInvalidReadItem15 D5148 CHANNEL
ReadValidOrInvalidReadItem16 D5158 CHANNEL
ReadValidOrInvalidReadItem17 D5168 CHANNEL
ReadValidOrInvalidReadItem18 D5178 CHANNEL
ReadValidOrInvalidReadItem19 D5188 CHANNEL
ReadValidOrInvalidReadItem2 D5018 CHANNEL
ReadValidOrInvalidReadItem20 D5198 CHANNEL
ReadValidOrInvalidReadItem21 D5208 CHANNEL
ReadValidOrInvalidReadItem22 D5218 CHANNEL
ReadValidOrInvalidReadItem23 D5228 CHANNEL
ReadValidOrInvalidReadItem24 D5238 CHANNEL
ReadValidOrInvalidReadItem25 D5248 CHANNEL
ReadValidOrInvalidReadItem26 D5258 CHANNEL
ReadValidOrInvalidReadItem27 D5268 CHANNEL
ReadValidOrInvalidReadItem28 D5278 CHANNEL
ReadValidOrInvalidReadItem29 D5288 CHANNEL
ReadValidOrInvalidReadItem3 D5028 CHANNEL
ReadValidOrInvalidReadItem30 D5298 CHANNEL
ReadValidOrInvalidReadItem31 D5308 CHANNEL
ReadValidOrInvalidReadItem32 D5318 CHANNEL
ReadValidOrInvalidReadItem33 D5328 CHANNEL
ReadValidOrInvalidReadItem34 D5338 CHANNEL
ReadValidOrInvalidReadItem35 D5348 CHANNEL
ReadValidOrInvalidReadItem36 D5358 CHANNEL
ReadValidOrInvalidReadItem37 D5368 CHANNEL
ReadValidOrInvalidReadItem38 D5378 CHANNEL
ReadValidOrInvalidReadItem39 D5388 CHANNEL
ReadValidOrInvalidReadItem4 D5038 CHANNEL
ReadValidOrInvalidReadItem40 D5398 CHANNEL
ReadValidOrInvalidReadItem41 D5408 CHANNEL
ReadValidOrInvalidReadItem42 D5418 CHANNEL
ReadValidOrInvalidReadItem43 D5428 CHANNEL
ReadValidOrInvalidReadItem44 D5438 CHANNEL
ReadValidOrInvalidReadItem45 D5448 CHANNEL
ReadValidOrInvalidReadItem46 D5458 CHANNEL
ReadValidOrInvalidReadItem47 D5468 CHANNEL
ReadValidOrInvalidReadItem48 D5478 CHANNEL
ReadValidOrInvalidReadItem49 D5488 CHANNEL
ReadValidOrInvalidReadItem5 D5048 CHANNEL
ReadValidOrInvalidReadItem50 D5498 CHANNEL
ReadValidOrInvalidReadItem51 D5508 CHANNEL
ReadValidOrInvalidReadItem52 D5518 CHANNEL
ReadValidOrInvalidReadItem53 D5528 CHANNEL
ReadValidOrInvalidReadItem54 D5538 CHANNEL
ReadValidOrInvalidReadItem55 D5548 CHANNEL
ReadValidOrInvalidReadItem56 D5558 CHANNEL
ReadValidOrInvalidReadItem57 D5568 CHANNEL
ReadValidOrInvalidReadItem58 D5578 CHANNEL
ReadValidOrInvalidReadItem59 D5588 CHANNEL
ReadValidOrInvalidReadItem6 D5058 CHANNEL
ReadValidOrInvalidReadItem60 D5598 CHANNEL
ReadValidOrInvalidReadItem61 D5608 CHANNEL
ReadValidOrInvalidReadItem62 D5618 CHANNEL
ReadValidOrInvalidReadItem63 D5628 CHANNEL
ReadValidOrInvalidReadItem64 D5638 CHANNEL
ReadValidOrInvalidReadItem65 D5648 CHANNEL
ReadValidOrInvalidReadItem66 D5658 CHANNEL
ReadValidOrInvalidReadItem67 D5668 CHANNEL
ReadValidOrInvalidReadItem68 D5678 CHANNEL
ReadValidOrInvalidReadItem69 D5688 CHANNEL
ReadValidOrInvalidReadItem7 D5068 CHANNEL
ReadValidOrInvalidReadItem70 D5698 CHANNEL
ReadValidOrInvalidReadItem71 D5708 CHANNEL
ReadValidOrInvalidReadItem72 D5718 CHANNEL
ReadValidOrInvalidReadItem73 D5728 CHANNEL
ReadValidOrInvalidReadItem74 D5738 CHANNEL
ReadValidOrInvalidReadItem75 D5748 CHANNEL
ReadValidOrInvalidReadItem76 D5758 CHANNEL
ReadValidOrInvalidReadItem77 D5768 CHANNEL
ReadValidOrInvalidReadItem78 D5778 CHANNEL
ReadValidOrInvalidReadItem79 D5788 CHANNEL
ReadValidOrInvalidReadItem8 D5078 CHANNEL
ReadValidOrInvalidReadItem80 D5798 CHANNEL
ReadValidOrInvalidReadItem81 D5808 CHANNEL
ReadValidOrInvalidReadItem82 D5818 CHANNEL
ReadValidOrInvalidReadItem83 D5828 CHANNEL
ReadValidOrInvalidReadItem84 D5838 CHANNEL
ReadValidOrInvalidReadItem85 D5848 CHANNEL
ReadValidOrInvalidReadItem86 D5858 CHANNEL
ReadValidOrInvalidReadItem87 D5868 CHANNEL
ReadValidOrInvalidReadItem88 D5878 CHANNEL
ReadValidOrInvalidReadItem89 D5888 CHANNEL
ReadValidOrInvalidReadItem9 D5088 CHANNEL
ReadValidOrInvalidReadItem90 D5898 CHANNEL
ReadValidOrInvalidReadItem91 D5908 CHANNEL
ReadValidOrInvalidReadItem92 D5918 CHANNEL
ReadValidOrInvalidReadItem93 D5928 CHANNEL
ReadValidOrInvalidReadItem94 D5938 CHANNEL
ReadValidOrInvalidReadItem95 D5948 CHANNEL
ReadValidOrInvalidReadItem96 D5958 CHANNEL
ReadValidOrInvalidReadItem97 D5968 CHANNEL
ReadValidOrInvalidReadItem98 D5978 CHANNEL
ReadValidOrInvalidReadItem99 D5988 CHANNEL
Retry_Send_Delay W205.01 BOOL
SecondWordResponseDataReadItem1 D5005 CHANNEL
SecondWordResponseDataReadItem10 D5095 CHANNEL
SecondWordResponseDataReadItem100 D5995 CHANNEL
SecondWordResponseDataReadItem11 D5105 CHANNEL
SecondWordResponseDataReadItem12 D5115 CHANNEL
SecondWordResponseDataReadItem13 D5125 CHANNEL
SecondWordResponseDataReadItem14 D5135 CHANNEL
SecondWordResponseDataReadItem15 D5145 CHANNEL
SecondWordResponseDataReadItem16 D5155 CHANNEL
SecondWordResponseDataReadItem17 D5165 CHANNEL
SecondWordResponseDataReadItem18 D5175 CHANNEL
SecondWordResponseDataReadItem19 D5185 CHANNEL
SecondWordResponseDataReadItem2 D5015 CHANNEL
SecondWordResponseDataReadItem20 D5195 CHANNEL
SecondWordResponseDataReadItem21 D5205 CHANNEL
SecondWordResponseDataReadItem22 D5215 CHANNEL
SecondWordResponseDataReadItem23 D5225 CHANNEL
SecondWordResponseDataReadItem24 D5235 CHANNEL
SecondWordResponseDataReadItem25 D5245 CHANNEL
SecondWordResponseDataReadItem26 D5255 CHANNEL
SecondWordResponseDataReadItem27 D5265 CHANNEL
SecondWordResponseDataReadItem28 D5275 CHANNEL
SecondWordResponseDataReadItem29 D5285 CHANNEL
SecondWordResponseDataReadItem3 D5025 CHANNEL
SecondWordResponseDataReadItem30 D5295 CHANNEL
SecondWordResponseDataReadItem31 D5305 CHANNEL
SecondWordResponseDataReadItem32 D5315 CHANNEL
SecondWordResponseDataReadItem33 D5325 CHANNEL
SecondWordResponseDataReadItem34 D5335 CHANNEL
SecondWordResponseDataReadItem35 D5345 CHANNEL
SecondWordResponseDataReadItem36 D5355 CHANNEL
SecondWordResponseDataReadItem37 D5365 CHANNEL
SecondWordResponseDataReadItem38 D5375 CHANNEL
SecondWordResponseDataReadItem39 D5385 CHANNEL
SecondWordResponseDataReadItem4 D5035 CHANNEL
SecondWordResponseDataReadItem40 D5395 CHANNEL
SecondWordResponseDataReadItem41 D5405 CHANNEL
SecondWordResponseDataReadItem42 D5415 CHANNEL
SecondWordResponseDataReadItem43 D5425 CHANNEL
SecondWordResponseDataReadItem44 D5435 CHANNEL
SecondWordResponseDataReadItem45 D5445 CHANNEL
SecondWordResponseDataReadItem46 D5455 CHANNEL
SecondWordResponseDataReadItem47 D5465 CHANNEL
SecondWordResponseDataReadItem48 D5475 CHANNEL
SecondWordResponseDataReadItem49 D5485 CHANNEL
SecondWordResponseDataReadItem5 D5045 CHANNEL
SecondWordResponseDataReadItem50 D5495 CHANNEL
SecondWordResponseDataReadItem51 D5505 CHANNEL
SecondWordResponseDataReadItem52 D5515 CHANNEL
SecondWordResponseDataReadItem53 D5525 CHANNEL
SecondWordResponseDataReadItem54 D5535 CHANNEL
SecondWordResponseDataReadItem55 D5545 CHANNEL
SecondWordResponseDataReadItem56 D5555 CHANNEL
SecondWordResponseDataReadItem57 D5565 CHANNEL
SecondWordResponseDataReadItem58 D5575 CHANNEL
SecondWordResponseDataReadItem59 D5585 CHANNEL
SecondWordResponseDataReadItem6 D5055 CHANNEL
SecondWordResponseDataReadItem60 D5595 CHANNEL
SecondWordResponseDataReadItem61 D5605 CHANNEL
SecondWordResponseDataReadItem62 D5615 CHANNEL
SecondWordResponseDataReadItem63 D5625 CHANNEL
SecondWordResponseDataReadItem64 D5635 CHANNEL
SecondWordResponseDataReadItem65 D5645 CHANNEL
SecondWordResponseDataReadItem66 D5655 CHANNEL
SecondWordResponseDataReadItem67 D5665 CHANNEL
SecondWordResponseDataReadItem68 D5675 CHANNEL
SecondWordResponseDataReadItem69 D5685 CHANNEL
SecondWordResponseDataReadItem7 D5065 CHANNEL
SecondWordResponseDataReadItem70 D5695 CHANNEL
SecondWordResponseDataReadItem71 D5705 CHANNEL
SecondWordResponseDataReadItem72 D5715 CHANNEL
SecondWordResponseDataReadItem73 D5725 CHANNEL
SecondWordResponseDataReadItem74 D5735 CHANNEL
SecondWordResponseDataReadItem75 D5745 CHANNEL
SecondWordResponseDataReadItem76 D5755 CHANNEL
SecondWordResponseDataReadItem77 D5765 CHANNEL
SecondWordResponseDataReadItem78 D5775 CHANNEL
SecondWordResponseDataReadItem79 D5785 CHANNEL
SecondWordResponseDataReadItem8 D5075 CHANNEL
SecondWordResponseDataReadItem80 D5795 CHANNEL
SecondWordResponseDataReadItem81 D5805 CHANNEL
SecondWordResponseDataReadItem82 D5815 CHANNEL
SecondWordResponseDataReadItem83 D5825 CHANNEL
SecondWordResponseDataReadItem84 D5835 CHANNEL
SecondWordResponseDataReadItem85 D5845 CHANNEL
SecondWordResponseDataReadItem86 D5855 CHANNEL
SecondWordResponseDataReadItem87 D5865 CHANNEL
SecondWordResponseDataReadItem88 D5875 CHANNEL
SecondWordResponseDataReadItem89 D5885 CHANNEL
SecondWordResponseDataReadItem9 D5085 CHANNEL
SecondWordResponseDataReadItem90 D5895 CHANNEL
SecondWordResponseDataReadItem91 D5905 CHANNEL
SecondWordResponseDataReadItem92 D5915 CHANNEL
SecondWordResponseDataReadItem93 D5925 CHANNEL
SecondWordResponseDataReadItem94 D5935 CHANNEL
SecondWordResponseDataReadItem95 D5945 CHANNEL
SecondWordResponseDataReadItem96 D5955 CHANNEL
SecondWordResponseDataReadItem97 D5965 CHANNEL
SecondWordResponseDataReadItem98 D5975 CHANNEL
SecondWordResponseDataReadItem99 D5985 CHANNEL
SecondWordWriteDataMirrorWriteItem1 D6007 CHANNEL
SecondWordWriteDataMirrorWriteItem10 D6097 CHANNEL
SecondWordWriteDataMirrorWriteItem100 D6997 CHANNEL
SecondWordWriteDataMirrorWriteItem11 D6107 CHANNEL
SecondWordWriteDataMirrorWriteItem12 D6117 CHANNEL
SecondWordWriteDataMirrorWriteItem13 D6127 CHANNEL
SecondWordWriteDataMirrorWriteItem14 D6137 CHANNEL
SecondWordWriteDataMirrorWriteItem15 D6147 CHANNEL
SecondWordWriteDataMirrorWriteItem16 D6157 CHANNEL
SecondWordWriteDataMirrorWriteItem17 D6167 CHANNEL
SecondWordWriteDataMirrorWriteItem18 D6177 CHANNEL
SecondWordWriteDataMirrorWriteItem19 D6187 CHANNEL
SecondWordWriteDataMirrorWriteItem2 D6017 CHANNEL
SecondWordWriteDataMirrorWriteItem20 D6197 CHANNEL
SecondWordWriteDataMirrorWriteItem21 D6207 CHANNEL
SecondWordWriteDataMirrorWriteItem22 D6217 CHANNEL
SecondWordWriteDataMirrorWriteItem23 D6227 CHANNEL
SecondWordWriteDataMirrorWriteItem24 D6237 CHANNEL
SecondWordWriteDataMirrorWriteItem25 D6247 CHANNEL
SecondWordWriteDataMirrorWriteItem26 D6257 CHANNEL
SecondWordWriteDataMirrorWriteItem27 D6267 CHANNEL
SecondWordWriteDataMirrorWriteItem28 D6277 CHANNEL
SecondWordWriteDataMirrorWriteItem29 D6287 CHANNEL
SecondWordWriteDataMirrorWriteItem3 D6027 CHANNEL
SecondWordWriteDataMirrorWriteItem30 D6297 CHANNEL
SecondWordWriteDataMirrorWriteItem31 D6307 CHANNEL
SecondWordWriteDataMirrorWriteItem32 D6317 CHANNEL
SecondWordWriteDataMirrorWriteItem33 D6327 CHANNEL
SecondWordWriteDataMirrorWriteItem34 D6337 CHANNEL
SecondWordWriteDataMirrorWriteItem35 D6347 CHANNEL
SecondWordWriteDataMirrorWriteItem36 D6357 CHANNEL
SecondWordWriteDataMirrorWriteItem37 D6367 CHANNEL
SecondWordWriteDataMirrorWriteItem38 D6377 CHANNEL
SecondWordWriteDataMirrorWriteItem39 D6387 CHANNEL
SecondWordWriteDataMirrorWriteItem4 D6037 CHANNEL
SecondWordWriteDataMirrorWriteItem40 D6397 CHANNEL
SecondWordWriteDataMirrorWriteItem41 D6407 CHANNEL
SecondWordWriteDataMirrorWriteItem42 D6417 CHANNEL
SecondWordWriteDataMirrorWriteItem43 D6427 CHANNEL
SecondWordWriteDataMirrorWriteItem44 D6437 CHANNEL
SecondWordWriteDataMirrorWriteItem45 D6447 CHANNEL
SecondWordWriteDataMirrorWriteItem46 D6457 CHANNEL
SecondWordWriteDataMirrorWriteItem47 D6467 CHANNEL
SecondWordWriteDataMirrorWriteItem48 D6477 CHANNEL
SecondWordWriteDataMirrorWriteItem49 D6487 CHANNEL
SecondWordWriteDataMirrorWriteItem5 D6047 CHANNEL
SecondWordWriteDataMirrorWriteItem50 D6497 CHANNEL
SecondWordWriteDataMirrorWriteItem51 D6507 CHANNEL
SecondWordWriteDataMirrorWriteItem52 D6517 CHANNEL
SecondWordWriteDataMirrorWriteItem53 D6527 CHANNEL
SecondWordWriteDataMirrorWriteItem54 D6537 CHANNEL
SecondWordWriteDataMirrorWriteItem55 D6547 CHANNEL
SecondWordWriteDataMirrorWriteItem56 D6557 CHANNEL
SecondWordWriteDataMirrorWriteItem57 D6567 CHANNEL
SecondWordWriteDataMirrorWriteItem58 D6577 CHANNEL
SecondWordWriteDataMirrorWriteItem59 D6587 CHANNEL
SecondWordWriteDataMirrorWriteItem6 D6057 CHANNEL
SecondWordWriteDataMirrorWriteItem60 D6597 CHANNEL
SecondWordWriteDataMirrorWriteItem61 D6607 CHANNEL
SecondWordWriteDataMirrorWriteItem62 D6617 CHANNEL
SecondWordWriteDataMirrorWriteItem63 D6627 CHANNEL
SecondWordWriteDataMirrorWriteItem64 D6637 CHANNEL
SecondWordWriteDataMirrorWriteItem65 D6647 CHANNEL
SecondWordWriteDataMirrorWriteItem66 D6657 CHANNEL
SecondWordWriteDataMirrorWriteItem67 D6667 CHANNEL
SecondWordWriteDataMirrorWriteItem68 D6677 CHANNEL
SecondWordWriteDataMirrorWriteItem69 D6687 CHANNEL
SecondWordWriteDataMirrorWriteItem7 D6067 CHANNEL
SecondWordWriteDataMirrorWriteItem70 D6697 CHANNEL
SecondWordWriteDataMirrorWriteItem71 D6707 CHANNEL
SecondWordWriteDataMirrorWriteItem72 D6717 CHANNEL
SecondWordWriteDataMirrorWriteItem73 D6727 CHANNEL
SecondWordWriteDataMirrorWriteItem74 D6737 CHANNEL
SecondWordWriteDataMirrorWriteItem75 D6747 CHANNEL
SecondWordWriteDataMirrorWriteItem76 D6757 CHANNEL
SecondWordWriteDataMirrorWriteItem77 D6767 CHANNEL
SecondWordWriteDataMirrorWriteItem78 D6777 CHANNEL
SecondWordWriteDataMirrorWriteItem79 D6787 CHANNEL
SecondWordWriteDataMirrorWriteItem8 D6077 CHANNEL
SecondWordWriteDataMirrorWriteItem80 D6797 CHANNEL
SecondWordWriteDataMirrorWriteItem81 D6807 CHANNEL
SecondWordWriteDataMirrorWriteItem82 D6817 CHANNEL
SecondWordWriteDataMirrorWriteItem83 D6827 CHANNEL
SecondWordWriteDataMirrorWriteItem84 D6837 CHANNEL
SecondWordWriteDataMirrorWriteItem85 D6847 CHANNEL
SecondWordWriteDataMirrorWriteItem86 D6857 CHANNEL
SecondWordWriteDataMirrorWriteItem87 D6867 CHANNEL
SecondWordWriteDataMirrorWriteItem88 D6877 CHANNEL
SecondWordWriteDataMirrorWriteItem89 D6887 CHANNEL
SecondWordWriteDataMirrorWriteItem9 D6087 CHANNEL
SecondWordWriteDataMirrorWriteItem90 D6897 CHANNEL
SecondWordWriteDataMirrorWriteItem91 D6907 CHANNEL
SecondWordWriteDataMirrorWriteItem92 D6917 CHANNEL
SecondWordWriteDataMirrorWriteItem93 D6927 CHANNEL
SecondWordWriteDataMirrorWriteItem94 D6937 CHANNEL
SecondWordWriteDataMirrorWriteItem95 D6947 CHANNEL
SecondWordWriteDataMirrorWriteItem96 D6957 CHANNEL
SecondWordWriteDataMirrorWriteItem97 D6967 CHANNEL
SecondWordWriteDataMirrorWriteItem98 D6977 CHANNEL
SecondWordWriteDataMirrorWriteItem99 D6987 CHANNEL
SecondWordWriteDataWriteItem1 D6005 CHANNEL
SecondWordWriteDataWriteItem10 D6095 CHANNEL
SecondWordWriteDataWriteItem100 D6995 CHANNEL
SecondWordWriteDataWriteItem11 D6105 CHANNEL
SecondWordWriteDataWriteItem12 D6115 CHANNEL
SecondWordWriteDataWriteItem13 D6125 CHANNEL
SecondWordWriteDataWriteItem14 D6135 CHANNEL
SecondWordWriteDataWriteItem15 D6145 CHANNEL
SecondWordWriteDataWriteItem16 D6155 CHANNEL
SecondWordWriteDataWriteItem17 D6165 CHANNEL
SecondWordWriteDataWriteItem18 D6175 CHANNEL
SecondWordWriteDataWriteItem19 D6185 CHANNEL
SecondWordWriteDataWriteItem2 D6015 CHANNEL
SecondWordWriteDataWriteItem20 D6195 CHANNEL
SecondWordWriteDataWriteItem21 D6205 CHANNEL
SecondWordWriteDataWriteItem22 D6215 CHANNEL
SecondWordWriteDataWriteItem23 D6225 CHANNEL
SecondWordWriteDataWriteItem24 D6235 CHANNEL
SecondWordWriteDataWriteItem25 D6245 CHANNEL
SecondWordWriteDataWriteItem26 D6255 CHANNEL
SecondWordWriteDataWriteItem27 D6265 CHANNEL
SecondWordWriteDataWriteItem28 D6275 CHANNEL
SecondWordWriteDataWriteItem29 D6285 CHANNEL
SecondWordWriteDataWriteItem3 D6025 CHANNEL
SecondWordWriteDataWriteItem30 D6295 CHANNEL
SecondWordWriteDataWriteItem31 D6305 CHANNEL
SecondWordWriteDataWriteItem32 D6315 CHANNEL
SecondWordWriteDataWriteItem33 D6325 CHANNEL
SecondWordWriteDataWriteItem34 D6335 CHANNEL
SecondWordWriteDataWriteItem35 D6345 CHANNEL
SecondWordWriteDataWriteItem36 D6355 CHANNEL
SecondWordWriteDataWriteItem37 D6365 CHANNEL
SecondWordWriteDataWriteItem38 D6375 CHANNEL
SecondWordWriteDataWriteItem39 D6385 CHANNEL
SecondWordWriteDataWriteItem4 D6035 CHANNEL
SecondWordWriteDataWriteItem40 D6395 CHANNEL
SecondWordWriteDataWriteItem41 D6405 CHANNEL
SecondWordWriteDataWriteItem42 D6415 CHANNEL
SecondWordWriteDataWriteItem43 D6425 CHANNEL
SecondWordWriteDataWriteItem44 D6435 CHANNEL
SecondWordWriteDataWriteItem45 D6445 CHANNEL
SecondWordWriteDataWriteItem46 D6455 CHANNEL
SecondWordWriteDataWriteItem47 D6465 CHANNEL
SecondWordWriteDataWriteItem48 D6475 CHANNEL
SecondWordWriteDataWriteItem49 D6485 CHANNEL
SecondWordWriteDataWriteItem5 D6045 CHANNEL
SecondWordWriteDataWriteItem50 D6495 CHANNEL
SecondWordWriteDataWriteItem51 D6505 CHANNEL
SecondWordWriteDataWriteItem52 D6515 CHANNEL
SecondWordWriteDataWriteItem53 D6525 CHANNEL
SecondWordWriteDataWriteItem54 D6535 CHANNEL
SecondWordWriteDataWriteItem55 D6545 CHANNEL
SecondWordWriteDataWriteItem56 D6555 CHANNEL
SecondWordWriteDataWriteItem57 D6565 CHANNEL
SecondWordWriteDataWriteItem58 D6575 CHANNEL
SecondWordWriteDataWriteItem59 D6585 CHANNEL
SecondWordWriteDataWriteItem6 D6055 CHANNEL
SecondWordWriteDataWriteItem60 D6595 CHANNEL
SecondWordWriteDataWriteItem61 D6605 CHANNEL
SecondWordWriteDataWriteItem62 D6615 CHANNEL
SecondWordWriteDataWriteItem63 D6625 CHANNEL
SecondWordWriteDataWriteItem64 D6635 CHANNEL
SecondWordWriteDataWriteItem65 D6645 CHANNEL
SecondWordWriteDataWriteItem66 D6655 CHANNEL
SecondWordWriteDataWriteItem67 D6665 CHANNEL
SecondWordWriteDataWriteItem68 D6675 CHANNEL
SecondWordWriteDataWriteItem69 D6685 CHANNEL
SecondWordWriteDataWriteItem7 D6065 CHANNEL
SecondWordWriteDataWriteItem70 D6695 CHANNEL
SecondWordWriteDataWriteItem71 D6705 CHANNEL
SecondWordWriteDataWriteItem72 D6715 CHANNEL
SecondWordWriteDataWriteItem73 D6725 CHANNEL
SecondWordWriteDataWriteItem74 D6735 CHANNEL
SecondWordWriteDataWriteItem75 D6745 CHANNEL
SecondWordWriteDataWriteItem76 D6755 CHANNEL
SecondWordWriteDataWriteItem77 D6765 CHANNEL
SecondWordWriteDataWriteItem78 D6775 CHANNEL
SecondWordWriteDataWriteItem79 D6785 CHANNEL
SecondWordWriteDataWriteItem8 D6075 CHANNEL
SecondWordWriteDataWriteItem80 D6795 CHANNEL
SecondWordWriteDataWriteItem81 D6805 CHANNEL
SecondWordWriteDataWriteItem82 D6815 CHANNEL
SecondWordWriteDataWriteItem83 D6825 CHANNEL
SecondWordWriteDataWriteItem84 D6835 CHANNEL
SecondWordWriteDataWriteItem85 D6845 CHANNEL
SecondWordWriteDataWriteItem86 D6855 CHANNEL
SecondWordWriteDataWriteItem87 D6865 CHANNEL
SecondWordWriteDataWriteItem88 D6875 CHANNEL
SecondWordWriteDataWriteItem89 D6885 CHANNEL
SecondWordWriteDataWriteItem9 D6085 CHANNEL
SecondWordWriteDataWriteItem90 D6895 CHANNEL
SecondWordWriteDataWriteItem91 D6905 CHANNEL
SecondWordWriteDataWriteItem92 D6915 CHANNEL
SecondWordWriteDataWriteItem93 D6925 CHANNEL
SecondWordWriteDataWriteItem94 D6935 CHANNEL
SecondWordWriteDataWriteItem95 D6945 CHANNEL
SecondWordWriteDataWriteItem96 D6955 CHANNEL
SecondWordWriteDataWriteItem97 D6965 CHANNEL
SecondWordWriteDataWriteItem98 D6975 CHANNEL
SecondWordWriteDataWriteItem99 D6985 CHANNEL
Send_PMCR W215.01 BOOL
SerialPortReset A526.00 BOOL
SerialPortResetCounter W207 INT
Stack_Empty W205.00 BOOL
Stack_Full_Diagnostic_Bit W215.04 BOOL
Stack_Start W0 DWORD
StartingModbusAddressReadItem1 D5002 CHANNEL
StartingModbusAddressReadItem10 D5092 CHANNEL
StartingModbusAddressReadItem100 D5992 CHANNEL
StartingModbusAddressReadItem11 D5102 CHANNEL
StartingModbusAddressReadItem12 D5112 CHANNEL
StartingModbusAddressReadItem13 D5122 CHANNEL
StartingModbusAddressReadItem14 D5132 CHANNEL
StartingModbusAddressReadItem15 D5142 CHANNEL
StartingModbusAddressReadItem16 D5152 CHANNEL
StartingModbusAddressReadItem17 D5162 CHANNEL
StartingModbusAddressReadItem18 D5172 CHANNEL
StartingModbusAddressReadItem19 D5182 CHANNEL
StartingModbusAddressReadItem2 D5012 CHANNEL
StartingModbusAddressReadItem20 D5192 CHANNEL
StartingModbusAddressReadItem21 D5202 CHANNEL
StartingModbusAddressReadItem22 D5212 CHANNEL
StartingModbusAddressReadItem23 D5222 CHANNEL
StartingModbusAddressReadItem24 D5232 CHANNEL
StartingModbusAddressReadItem25 D5242 CHANNEL
StartingModbusAddressReadItem26 D5252 CHANNEL
StartingModbusAddressReadItem27 D5262 CHANNEL
StartingModbusAddressReadItem28 D5272 CHANNEL
StartingModbusAddressReadItem29 D5282 CHANNEL
StartingModbusAddressReadItem3 D5022 CHANNEL
StartingModbusAddressReadItem30 D5292 CHANNEL
StartingModbusAddressReadItem31 D5302 CHANNEL
StartingModbusAddressReadItem32 D5312 CHANNEL
StartingModbusAddressReadItem33 D5322 CHANNEL
StartingModbusAddressReadItem34 D5332 CHANNEL
StartingModbusAddressReadItem35 D5342 CHANNEL
StartingModbusAddressReadItem36 D5352 CHANNEL
StartingModbusAddressReadItem37 D5362 CHANNEL
StartingModbusAddressReadItem38 D5372 CHANNEL
StartingModbusAddressReadItem39 D5382 CHANNEL
StartingModbusAddressReadItem4 D5032 CHANNEL
StartingModbusAddressReadItem40 D5392 CHANNEL
StartingModbusAddressReadItem41 D5402 CHANNEL
StartingModbusAddressReadItem42 D5412 CHANNEL
StartingModbusAddressReadItem43 D5422 CHANNEL
StartingModbusAddressReadItem44 D5432 CHANNEL
StartingModbusAddressReadItem45 D5442 CHANNEL
StartingModbusAddressReadItem46 D5452 CHANNEL
StartingModbusAddressReadItem47 D5462 CHANNEL
StartingModbusAddressReadItem48 D5472 CHANNEL
StartingModbusAddressReadItem49 D5482 CHANNEL
StartingModbusAddressReadItem5 D5042 CHANNEL
StartingModbusAddressReadItem50 D5492 CHANNEL
StartingModbusAddressReadItem51 D5502 CHANNEL
StartingModbusAddressReadItem52 D5512 CHANNEL
StartingModbusAddressReadItem53 D5522 CHANNEL
StartingModbusAddressReadItem54 D5532 CHANNEL
StartingModbusAddressReadItem55 D5542 CHANNEL
StartingModbusAddressReadItem56 D5552 CHANNEL
StartingModbusAddressReadItem57 D5562 CHANNEL
StartingModbusAddressReadItem58 D5572 CHANNEL
StartingModbusAddressReadItem59 D5582 CHANNEL
StartingModbusAddressReadItem6 D5052 CHANNEL
StartingModbusAddressReadItem60 D5592 CHANNEL
StartingModbusAddressReadItem61 D5602 CHANNEL
StartingModbusAddressReadItem62 D5612 CHANNEL
StartingModbusAddressReadItem63 D5622 CHANNEL
StartingModbusAddressReadItem64 D5632 CHANNEL
StartingModbusAddressReadItem65 D5642 CHANNEL
StartingModbusAddressReadItem66 D5652 CHANNEL
StartingModbusAddressReadItem67 D5662 CHANNEL
StartingModbusAddressReadItem68 D5672 CHANNEL
StartingModbusAddressReadItem69 D5682 CHANNEL
StartingModbusAddressReadItem7 D5062 CHANNEL
StartingModbusAddressReadItem70 D5692 CHANNEL
StartingModbusAddressReadItem71 D5702 CHANNEL
StartingModbusAddressReadItem72 D5712 CHANNEL
StartingModbusAddressReadItem73 D5722 CHANNEL
StartingModbusAddressReadItem74 D5732 CHANNEL
StartingModbusAddressReadItem75 D5742 CHANNEL
StartingModbusAddressReadItem76 D5752 CHANNEL
StartingModbusAddressReadItem77 D5762 CHANNEL
StartingModbusAddressReadItem78 D5772 CHANNEL
StartingModbusAddressReadItem79 D5782 CHANNEL
StartingModbusAddressReadItem8 D5072 CHANNEL
StartingModbusAddressReadItem80 D5792 CHANNEL
StartingModbusAddressReadItem81 D5802 CHANNEL
StartingModbusAddressReadItem82 D5812 CHANNEL
StartingModbusAddressReadItem83 D5822 CHANNEL
StartingModbusAddressReadItem84 D5832 CHANNEL
StartingModbusAddressReadItem85 D5842 CHANNEL
StartingModbusAddressReadItem86 D5852 CHANNEL
StartingModbusAddressReadItem87 D5862 CHANNEL
StartingModbusAddressReadItem88 D5872 CHANNEL
StartingModbusAddressReadItem89 D5882 CHANNEL
StartingModbusAddressReadItem9 D5082 CHANNEL
StartingModbusAddressReadItem90 D5892 CHANNEL
StartingModbusAddressReadItem91 D5902 CHANNEL
StartingModbusAddressReadItem92 D5912 CHANNEL
StartingModbusAddressReadItem93 D5922 CHANNEL
StartingModbusAddressReadItem94 D5932 CHANNEL
StartingModbusAddressReadItem95 D5942 CHANNEL
StartingModbusAddressReadItem96 D5952 CHANNEL
StartingModbusAddressReadItem97 D5962 CHANNEL
StartingModbusAddressReadItem98 D5972 CHANNEL
StartingModbusAddressReadItem99 D5982 CHANNEL
StartingModbusAddressWriteItem1 D6002 CHANNEL
StartingModbusAddressWriteItem10 D6092 CHANNEL
StartingModbusAddressWriteItem100 D6992 CHANNEL
StartingModbusAddressWriteItem11 D6102 CHANNEL
StartingModbusAddressWriteItem12 D6112 CHANNEL
StartingModbusAddressWriteItem13 D6122 CHANNEL
StartingModbusAddressWriteItem14 D6132 CHANNEL
StartingModbusAddressWriteItem15 D6142 CHANNEL
StartingModbusAddressWriteItem16 D6152 CHANNEL
StartingModbusAddressWriteItem17 D6162 CHANNEL
StartingModbusAddressWriteItem18 D6172 CHANNEL
StartingModbusAddressWriteItem19 D6182 CHANNEL
StartingModbusAddressWriteItem2 D6012 CHANNEL
StartingModbusAddressWriteItem20 D6192 CHANNEL
StartingModbusAddressWriteItem21 D6202 CHANNEL
StartingModbusAddressWriteItem22 D6212 CHANNEL
StartingModbusAddressWriteItem23 D6222 CHANNEL
StartingModbusAddressWriteItem24 D6232 CHANNEL
StartingModbusAddressWriteItem25 D6242 CHANNEL
StartingModbusAddressWriteItem26 D6252 CHANNEL
StartingModbusAddressWriteItem27 D6262 CHANNEL
StartingModbusAddressWriteItem28 D6272 CHANNEL
StartingModbusAddressWriteItem29 D6282 CHANNEL
StartingModbusAddressWriteItem3 D6022 CHANNEL
StartingModbusAddressWriteItem30 D6292 CHANNEL
StartingModbusAddressWriteItem31 D6302 CHANNEL
StartingModbusAddressWriteItem32 D6312 CHANNEL
StartingModbusAddressWriteItem33 D6322 CHANNEL
StartingModbusAddressWriteItem34 D6332 CHANNEL
StartingModbusAddressWriteItem35 D6342 CHANNEL
StartingModbusAddressWriteItem36 D6352 CHANNEL
StartingModbusAddressWriteItem37 D6362 CHANNEL
StartingModbusAddressWriteItem38 D6372 CHANNEL
StartingModbusAddressWriteItem39 D6382 CHANNEL
StartingModbusAddressWriteItem4 D6032 CHANNEL
StartingModbusAddressWriteItem40 D6392 CHANNEL
StartingModbusAddressWriteItem41 D6402 CHANNEL
StartingModbusAddressWriteItem42 D6412 CHANNEL
StartingModbusAddressWriteItem43 D6422 CHANNEL
StartingModbusAddressWriteItem44 D6432 CHANNEL
StartingModbusAddressWriteItem45 D6442 CHANNEL
StartingModbusAddressWriteItem46 D6452 CHANNEL
StartingModbusAddressWriteItem47 D6462 CHANNEL
StartingModbusAddressWriteItem48 D6472 CHANNEL
StartingModbusAddressWriteItem49 D6482 CHANNEL
StartingModbusAddressWriteItem5 D6042 CHANNEL
StartingModbusAddressWriteItem50 D6492 CHANNEL
StartingModbusAddressWriteItem51 D6502 CHANNEL
StartingModbusAddressWriteItem52 D6512 CHANNEL
StartingModbusAddressWriteItem53 D6522 CHANNEL
StartingModbusAddressWriteItem54 D6532 CHANNEL
StartingModbusAddressWriteItem55 D6542 CHANNEL
StartingModbusAddressWriteItem56 D6552 CHANNEL
StartingModbusAddressWriteItem57 D6562 CHANNEL
StartingModbusAddressWriteItem58 D6572 CHANNEL
StartingModbusAddressWriteItem59 D6582 CHANNEL
StartingModbusAddressWriteItem6 D6052 CHANNEL
StartingModbusAddressWriteItem60 D6592 CHANNEL
StartingModbusAddressWriteItem61 D6602 CHANNEL
StartingModbusAddressWriteItem62 D6612 CHANNEL
StartingModbusAddressWriteItem63 D6622 CHANNEL
StartingModbusAddressWriteItem64 D6632 CHANNEL
StartingModbusAddressWriteItem65 D6642 CHANNEL
StartingModbusAddressWriteItem66 D6652 CHANNEL
StartingModbusAddressWriteItem67 D6662 CHANNEL
StartingModbusAddressWriteItem68 D6672 CHANNEL
StartingModbusAddressWriteItem69 D6682 CHANNEL
StartingModbusAddressWriteItem7 D6062 CHANNEL
StartingModbusAddressWriteItem70 D6692 CHANNEL
StartingModbusAddressWriteItem71 D6702 CHANNEL
StartingModbusAddressWriteItem72 D6712 CHANNEL
StartingModbusAddressWriteItem73 D6722 CHANNEL
StartingModbusAddressWriteItem74 D6732 CHANNEL
StartingModbusAddressWriteItem75 D6742 CHANNEL
StartingModbusAddressWriteItem76 D6752 CHANNEL
StartingModbusAddressWriteItem77 D6762 CHANNEL
StartingModbusAddressWriteItem78 D6772 CHANNEL
StartingModbusAddressWriteItem79 D6782 CHANNEL
StartingModbusAddressWriteItem8 D6072 CHANNEL
StartingModbusAddressWriteItem80 D6792 CHANNEL
StartingModbusAddressWriteItem81 D6802 CHANNEL
StartingModbusAddressWriteItem82 D6812 CHANNEL
StartingModbusAddressWriteItem83 D6822 CHANNEL
StartingModbusAddressWriteItem84 D6832 CHANNEL
StartingModbusAddressWriteItem85 D6842 CHANNEL
StartingModbusAddressWriteItem86 D6852 CHANNEL
StartingModbusAddressWriteItem87 D6862 CHANNEL
StartingModbusAddressWriteItem88 D6872 CHANNEL
StartingModbusAddressWriteItem89 D6882 CHANNEL
StartingModbusAddressWriteItem9 D6082 CHANNEL
StartingModbusAddressWriteItem90 D6892 CHANNEL
StartingModbusAddressWriteItem91 D6902 CHANNEL
StartingModbusAddressWriteItem92 D6912 CHANNEL
StartingModbusAddressWriteItem93 D6922 CHANNEL
StartingModbusAddressWriteItem94 D6932 CHANNEL
StartingModbusAddressWriteItem95 D6942 CHANNEL
StartingModbusAddressWriteItem96 D6952 CHANNEL
StartingModbusAddressWriteItem97 D6962 CHANNEL
StartingModbusAddressWriteItem98 D6972 CHANNEL
StartingModbusAddressWriteItem99 D6982 CHANNEL
TemporaryCommDataBytes W212 CHANNEL
TemporaryFIFOArea W211 CHANNEL
TemporaryStartingDMErrorLocation W218 DWORD
Temporary_Pointer_For_Stack_Push W210 DWORD
TimeoutRetryCounter W208 CHANNEL
Top_Of_Stack W202 DWORD
WriteValidOrInvalidWriteItem1 D6008 CHANNEL
WriteValidOrInvalidWriteItem10 D6098 CHANNEL
WriteValidOrInvalidWriteItem100 D6998 CHANNEL
WriteValidOrInvalidWriteItem11 D6108 CHANNEL
WriteValidOrInvalidWriteItem12 D6118 CHANNEL
WriteValidOrInvalidWriteItem13 D6128 CHANNEL
WriteValidOrInvalidWriteItem14 D6138 CHANNEL
WriteValidOrInvalidWriteItem15 D6148 CHANNEL
WriteValidOrInvalidWriteItem16 D6158 CHANNEL
WriteValidOrInvalidWriteItem17 D6168 CHANNEL
WriteValidOrInvalidWriteItem18 D6178 CHANNEL
WriteValidOrInvalidWriteItem19 D6188 CHANNEL
WriteValidOrInvalidWriteItem2 D6018 CHANNEL
WriteValidOrInvalidWriteItem20 D6198 CHANNEL
WriteValidOrInvalidWriteItem21 D6208 CHANNEL
WriteValidOrInvalidWriteItem22 D6218 CHANNEL
WriteValidOrInvalidWriteItem23 D6228 CHANNEL
WriteValidOrInvalidWriteItem24 D6238 CHANNEL
WriteValidOrInvalidWriteItem25 D6248 CHANNEL
WriteValidOrInvalidWriteItem26 D6258 CHANNEL
WriteValidOrInvalidWriteItem27 D6268 CHANNEL
WriteValidOrInvalidWriteItem28 D6278 CHANNEL
WriteValidOrInvalidWriteItem29 D6288 CHANNEL
WriteValidOrInvalidWriteItem3 D6028 CHANNEL
WriteValidOrInvalidWriteItem30 D6298 CHANNEL
WriteValidOrInvalidWriteItem31 D6308 CHANNEL
WriteValidOrInvalidWriteItem32 D6318 CHANNEL
WriteValidOrInvalidWriteItem33 D6328 CHANNEL
WriteValidOrInvalidWriteItem34 D6338 CHANNEL
WriteValidOrInvalidWriteItem35 D6348 CHANNEL
WriteValidOrInvalidWriteItem36 D6358 CHANNEL
WriteValidOrInvalidWriteItem37 D6368 CHANNEL
WriteValidOrInvalidWriteItem38 D6378 CHANNEL
WriteValidOrInvalidWriteItem39 D6388 CHANNEL
WriteValidOrInvalidWriteItem4 D6038 CHANNEL
WriteValidOrInvalidWriteItem40 D6398 CHANNEL
WriteValidOrInvalidWriteItem41 D6408 CHANNEL
WriteValidOrInvalidWriteItem42 D6418 CHANNEL
WriteValidOrInvalidWriteItem43 D6428 CHANNEL
WriteValidOrInvalidWriteItem44 D6438 CHANNEL
WriteValidOrInvalidWriteItem45 D6448 CHANNEL
WriteValidOrInvalidWriteItem46 D6458 CHANNEL
WriteValidOrInvalidWriteItem47 D6468 CHANNEL
WriteValidOrInvalidWriteItem48 D6478 CHANNEL
WriteValidOrInvalidWriteItem49 D6488 CHANNEL
WriteValidOrInvalidWriteItem5 D6048 CHANNEL
WriteValidOrInvalidWriteItem50 D6498 CHANNEL
WriteValidOrInvalidWriteItem51 D6508 CHANNEL
WriteValidOrInvalidWriteItem52 D6518 CHANNEL
WriteValidOrInvalidWriteItem53 D6528 CHANNEL
WriteValidOrInvalidWriteItem54 D6538 CHANNEL
WriteValidOrInvalidWriteItem55 D6548 CHANNEL
WriteValidOrInvalidWriteItem56 D6558 CHANNEL
WriteValidOrInvalidWriteItem57 D6568 CHANNEL
WriteValidOrInvalidWriteItem58 D6578 CHANNEL
WriteValidOrInvalidWriteItem59 D6588 CHANNEL
WriteValidOrInvalidWriteItem6 D6058 CHANNEL
WriteValidOrInvalidWriteItem60 D6598 CHANNEL
WriteValidOrInvalidWriteItem61 D6608 CHANNEL
WriteValidOrInvalidWriteItem62 D6618 CHANNEL
WriteValidOrInvalidWriteItem63 D6628 CHANNEL
WriteValidOrInvalidWriteItem64 D6638 CHANNEL
WriteValidOrInvalidWriteItem65 D6648 CHANNEL
WriteValidOrInvalidWriteItem66 D6658 CHANNEL
WriteValidOrInvalidWriteItem67 D6668 CHANNEL
WriteValidOrInvalidWriteItem68 D6678 CHANNEL
WriteValidOrInvalidWriteItem69 D6688 CHANNEL
WriteValidOrInvalidWriteItem7 D6068 CHANNEL
WriteValidOrInvalidWriteItem70 D6698 CHANNEL
WriteValidOrInvalidWriteItem71 D6708 CHANNEL
WriteValidOrInvalidWriteItem72 D6718 CHANNEL
WriteValidOrInvalidWriteItem73 D6728 CHANNEL
WriteValidOrInvalidWriteItem74 D6738 CHANNEL
WriteValidOrInvalidWriteItem75 D6748 CHANNEL
WriteValidOrInvalidWriteItem76 D6758 CHANNEL
WriteValidOrInvalidWriteItem77 D6768 CHANNEL
WriteValidOrInvalidWriteItem78 D6778 CHANNEL
WriteValidOrInvalidWriteItem79 D6788 CHANNEL
WriteValidOrInvalidWriteItem8 D6078 CHANNEL
WriteValidOrInvalidWriteItem80 D6798 CHANNEL
WriteValidOrInvalidWriteItem81 D6808 CHANNEL
WriteValidOrInvalidWriteItem82 D6818 CHANNEL
WriteValidOrInvalidWriteItem83 D6828 CHANNEL
WriteValidOrInvalidWriteItem84 D6838 CHANNEL
WriteValidOrInvalidWriteItem85 D6848 CHANNEL
WriteValidOrInvalidWriteItem86 D6858 CHANNEL
WriteValidOrInvalidWriteItem87 D6868 CHANNEL
WriteValidOrInvalidWriteItem88 D6878 CHANNEL
WriteValidOrInvalidWriteItem89 D6888 CHANNEL
WriteValidOrInvalidWriteItem9 D6088 CHANNEL
WriteValidOrInvalidWriteItem90 D6898 CHANNEL
WriteValidOrInvalidWriteItem91 D6908 CHANNEL
WriteValidOrInvalidWriteItem92 D6918 CHANNEL
WriteValidOrInvalidWriteItem93 D6928 CHANNEL
WriteValidOrInvalidWriteItem94 D6938 CHANNEL
WriteValidOrInvalidWriteItem95 D6948 CHANNEL
WriteValidOrInvalidWriteItem96 D6958 CHANNEL
WriteValidOrInvalidWriteItem97 D6968 CHANNEL
WriteValidOrInvalidWriteItem98 D6978 CHANNEL
WriteValidOrInvalidWriteItem99 D6988 CHANNEL

## Program Port1 (cyclic task 10)

### Section Initilization

; rung 0: Load D5008 into the pointer word.  This is the first location of Response Valid information to be initialized
LD P_First_Cycle
MOVR(560) ReadValidOrInvalidReadItem1 IR15
; rung 1
LD P_First_Cycle
JMP(004) #FD
; rung 2: Loop 100 times
FOR(512) &100
; rung 3: Mark the validity check for read and write data points as invalid at startup
LD P_On
MOV(021) #F000 ,IR15  // Mark each Read Validity check as invalid
MOV(021) #F000 1000,IR15  // Mark each Write Validity check as invalid
MOVL(498) #0 -4,IR15  // Clear the 'Read Data' so that it is not stale
BSET(071) #FFFF 996,IR15 999,IR15  // Set the Write Data and 'Last Write Data' to FFFF.  This allows Zero to be accepted as new data on startup.
+L(401) IR15 &10 IR15  // Pointer increment
; rung 4
NEXT(513)
; rung 5
JME(005) #FD

; rung 6: Build a stack from W0 - W203
LD P_First_Cycle
SSET(630) Stack_Start &204
MOVR(560) ModbusNodeNumberReadItem1 IR14  // Load DM5000 into IR 14.  This is the pointer for walking through the list of items to poll
RSET Send_PMCR  // Turn off the Easy Modbus bit in case it was left on

### Section PortError

; rung 0: Inter message timer / Forces a 2 ms gap between messages. / Increases application stability
LDNOT Send_PMCR
TMHH(540) 0015 #2

### Section Stack_Population

; rung 0
LD P_On
MOVR(560) ModbusNodeNumberWriteItem1 IR12
; rung 1: Loop up to 100 times
FOR(512) &100

; rung 2: Check for changes in the data, and push to the stack
LD<>L(306) 4,IR12 6,IR12
AND<>L(306) Current_Stack_Pointer #DEC2  // If the stack pointer is not at the top.  This prevents data loss if the stack is full
PUSH(632) Stack_Start ,IR12  // Push the Node Number
PUSH(632) Stack_Start 1,IR12  // Push the Function code
PUSH(632) Stack_Start 2,IR12  // Push the Start Address
PUSH(632) Stack_Start 3,IR12  // Push the Number of Points to Write
PUSH(632) Stack_Start 4,IR12  // Push the first word of data
PUSH(632) Stack_Start 5,IR12  // Push the second word of data
MOVL(498) IR12 Temporary_Pointer_For_Stack_Push  // Copy the pointer out to a temporary area so it can be pushed onto a stack
PUSH(632) Stack_Start Temporary_Pointer_For_Stack_Push  // Push the low address of the return address
PUSH(632) Stack_Start TemporaryFIFOArea  // Push the High address of the return address
PUSH(632) Stack_Start #0  // Pad with 0 for consistancy
PUSH(632) Stack_Start #0  // Pad with 0 for consistancy
MOVL(498) 4,IR12 6,IR12  // Copy this data to the 'last data written'
LD=(300) 9,IR12 #F00A  // End of List with auto clearing option
OR=(300) 9,IR12 #A  // Auto Clearing Option
ANDLD
BSET(071) #FFFF 4,IR12 7,IR12  // Write the data and 'last data written' to FFFF

; rung 3: If this is marked as the end, break out of the loop
LD>=(325) 9,IR12 #F000
BREAK(514)
; rung 4: Increment to the next item
LD P_On
+L(401) IR12 &10 IR12
; rung 5
NEXT(513)
; rung 6: Diagnostic bit for Stack Full
LD=L(301) Current_Stack_Pointer #DEC2  // If the stack pointer is not at the top.  This prevents data loss if the stack is full
OUT Stack_Full_Diagnostic_Bit

### Section Stack_Empty_Check

; rung 0
LD=L(301) Current_Stack_Pointer #DE04  // If the stack pointer is at W4, then the stack is empty
OUT Stack_Empty

### Section Write

; rung 0
LD T0015
LD<=(315) Consecutive_Writes &5  // If 5 or fewer consecutve writes have occurred
OR=(300) EndOfListMarkerReadItem1 #E000  // or if there are no read items in this application
ANDLD
ANDNOT Stack_Empty
ANDNOT Send_PMCR
%ANDNOT Send_PMCR
JMP(004) #FE
; rung 1: Clear the Easy Modbus send and recieve areas.  This is mostly for better troubleshooting
LD P_On
BSET(071) #0 EasyModbusPort1Command1 D32349
BSET(071) #0 EasyModbusPort1Response1 D32399

; rung 2: For any function code, populate the 'Node Number',  ' Function Code', Omron 'Number of bytes to send', and Starting Modbus Address
LD P_On
OUT TR0
FIFO(633) Stack_Start EasyModbusPort1Command1  // FIFO the Node Number
FIFO(633) Stack_Start EasyModbusPort1Command2  // FIFO the Function Code
FIFO(633) Stack_Start EasyModbusPort1Command4  // FIFO the Starting Address
FIFO(633) Stack_Start TemporaryFIFOArea  // FIFO the Number of Items to Write
LD=(300) EasyModbusPort1Command2 #5  // If the function code is a 5
OR=(300) EasyModbusPort1Command2 #6  // or if the function code is a 6
ANDLD
MOV(021) #4 TemporaryCommDataBytes  // Move 2 BYTES of Data for the Omron Easy Modbus Function
LD TR0
AND=(300) EasyModbusPort1Command2 #10  // If the function code is a 10
OUT TR1
AND=(300) TemporaryFIFOArea #1
MOV(021) #7 TemporaryCommDataBytes
LD TR1
AND=(300) TemporaryFIFOArea #2
MOV(021) #9 TemporaryCommDataBytes
LD TR0
AND=(300) EasyModbusPort1Command2 #F  // If the function code is a 10
OUT TR1
AND<=(315) TemporaryFIFOArea #F  // If the number of COILS to be written is less than or equal to 16 (0F) then this would be 1 word of data
MOV(021) #7 TemporaryCommDataBytes
LD TR1
AND>(320) TemporaryFIFOArea #F  // If the number of COILS to be written is more than 16 (0F), then this is 2 words of data.  Up to 32 (20 HEX) coils are supported
MOV(021) #9 TemporaryCommDataBytes
LD TR0
MOV(021) TemporaryCommDataBytes EasyModbusPort1Command3  // Move the 'Omron Number of COMM Bytes'
; rung 3: If necessary, write the number of Modbus Bytes
LD=(300) EasyModbusPort1Command2 #F  // If the function code is 0F
OR=(300) EasyModbusPort1Command2 #10  // If the function code is 10
OUT TR0
AND=(300) EasyModbusPort1Command3 #7  // If the Omron Byte Count = 3, then this is 1 register
MOV(021) #200 EasyModbusPort1Command6  // Then 2 Bytes of Modbus data are to be sent
LD TR0
AND=(300) EasyModbusPort1Command3 #9  // If the Omron Byte Count = 3, then this is 1 register
MOV(021) #400 EasyModbusPort1Command6  // Then 4 Bytes of Modbus data are to be sent
LD TR0
MOV(021) TemporaryFIFOArea EasyModbusPort1Command5  // Write the number of Modbus Registers or Coils to Write

; rung 4: FIFO the Data to send
LD P_On
OUT TR0
FIFO(633) Stack_Start TemporaryFIFOArea  // FIFO the First Data Word
LD=(300) EasyModbusPort1Command2 #5  // If the function code is a 5
OR=(300) EasyModbusPort1Command2 #6  // or if the function code is a 6
ANDLD
MOV(021) TemporaryFIFOArea EasyModbusPort1Command5  // Move the First Word of Data
LD TR0
LD=(300) EasyModbusPort1Command2 #10  // If the function code is a 10
OR=(300) EasyModbusPort1Command2 #F  // If the function code is a 10
ANDLD
MOVD(083) TemporaryFIFOArea #12 EasyModbusPort1Command6
MOVD(083) TemporaryFIFOArea #210 EasyModbusPort1Command7
LD TR0
FIFO(633) Stack_Start TemporaryFIFOArea  // FIFO the First Data Word
LD=(300) EasyModbusPort1Command2 #5  // If the function code is a 5
OR=(300) EasyModbusPort1Command2 #6  // or if the function code is a 6
ANDLD
MOV(021) TemporaryFIFOArea EasyModbusPort1Command6  // Move the First Word of Data
LD TR0
LD=(300) EasyModbusPort1Command2 #10  // If the function code is a 10
OR=(300) EasyModbusPort1Command2 #F  // If the function code is a 10
ANDLD
MOVD(083) TemporaryFIFOArea #12 EasyModbusPort1Command7
MOVD(083) TemporaryFIFOArea #210 EasyModbusPort1Command8

; rung 5: FIFO the return address and pad the last 2 FIFOs
LD P_On
FIFO(633) Stack_Start Temporary_Pointer_For_Stack_Push
FIFO(633) Stack_Start TemporaryFIFOArea
MOVL(498) Temporary_Pointer_For_Stack_Push IR13  // Create the Return Address
FIFO(633) Stack_Start TemporaryFIFOArea  // FIFO for stack consistency
FIFO(633) Stack_Start TemporaryFIFOArea  // FIFO for stack consistency
; rung 6: As long as the function code is supported by this application, send the Modbus command
LD=(300) EasyModbusPort1Command2 #5  // If the function code is a 5
OR=(300) EasyModbusPort1Command2 #6  // or if the function code is a 6
OR=(300) EasyModbusPort1Command2 #10  // If the function code is a 10
OR=(300) EasyModbusPort1Command2 #F  // If the function code is a 10
SET Send_PMCR
; rung 7: If this is not a supported Modbus Function Code, log it.
LDNOT Send_PMCR
SET LogAnEasyModbusError
MOV(021) #FFFF 8,IR13  // Mark the Response OK with an FFFF for BAD DATA
; rung 8: Add 1 to the count of consecutive writes. / This is to allow polling, at a slower rate, when the writes try to overwhelm the comms
LD<>(305) EndOfListMarkerReadItem1 #E000  // If there are read items in this application
++(590) Consecutive_Writes
; rung 9
JME(005) #FE

### Section Polling

; rung 0
LD T0015
AND<>(305) EndOfListMarkerReadItem1 #E000  // If there are Read Items in this application
LD Stack_Empty  // If the stack is empty
OR>(320) Consecutive_Writes #5  // or waiting to perform a read after 5 consecutive writes
ANDLD
ANDNOT Send_PMCR
%ANDNOT Send_PMCR
JMP(004) #FF  // Run the code to send a request
; rung 1: Clear the Easy Modbus send and recieve areas.  This is mostly for better troubleshooting
LD P_On
BSET(071) #0 EasyModbusPort1Command1 D32349
BSET(071) #0 EasyModbusPort1Response1 D32399
; rung 2: Functions 01 (read coil status) ,02 (Read Input Status), 03 (Read Holding Registers), and 04 (Read Input Registers)
LD P_On
MOV(021) ,IR14 EasyModbusPort1Command1  // Move the node number
MOV(021) 1,IR14 EasyModbusPort1Command2  // Move the Function Code
MOV(021) &4 EasyModbusPort1Command3  // Set the number of BYTES of data FOR OMRON FUNCTION
MOV(021) 2,IR14 EasyModbusPort1Command4  // Move the starting address
MOV(021) 3,IR14 EasyModbusPort1Command5  // Move the number of pieces of data to read (either bits or words, depending on the Modbus function).
+L(401) IR14 &4 IR13  // Store the address where the response should be stored in IR13

; rung 3: Only Set the Easy Modbus bit if this is a supported function code
LD=(300) 1,IR14 #1  // If the Modbus code to be sent is a 1 (Read Coil Status)
OR=(300) 1,IR14 #2  // If the Modbus code to be sent is a 2 (Read Input Status)
OR=(300) 1,IR14 #3  // If the Modbus code to be sent is a 3 (Read Holding Registers)
OR=(300) 1,IR14 #4  // If the Modbus code to be sent is a 04 (read Input Registers)
SET Send_PMCR
; rung 4: If this is not a supported Modbus function code, log an error
LDNOT Send_PMCR
SET LogAnEasyModbusError
MOVL(498) #0 ,IR13  // Write 0000 as the data
MOV(021) #FFFF 4,IR13  // Mark the Response OK with an FFFF for BAD DATA
; rung 5: Increment the pointer, even if a valid code was not found.  This allows the app to jump over unknown codes.
LD P_On
OUT TR0
MOVL(498) IR14 IR12  // Capture the value of the pointer to prevent flip / flop in the same scan
AND<>(305) 9,IR12 #F000  // If the end of polling has been reached
+L(401) IR14 &10 IR14  // Add 10 channels to the pointer
AND>=L(326) IR14 #11766  // Of if the pointer reaches D5990
MOVR(560) ModbusNodeNumberReadItem1 IR14  // Load DM5000 into IR 14.  This is the pointer for walking through the list of items to poll
SET Polling_Has_Occurred  // For Poll Cycle Timing
LD TR0
AND=(300) 9,IR12 #F000  // If the end of polling has been reached
MOVR(560) ModbusNodeNumberReadItem1 IR14  // Load DM5000 into IR 14.  This is the pointer for walking through the list of items to poll
SET Polling_Has_Occurred  // For Poll Cycle Timing

; rung 6: Set the Consecutive Write counter back to 0
LD P_On
MOV(021) #0 Consecutive_Writes
; rung 7
JME(005) #FF
; rung 8: If the polling cycle has been reset to the beginning (D5000), then subtract the current timer value from the preset to / determine the interval between polling cycle starts.
LD Polling_Has_Occurred
-B(414) #9999 T13 W216  // post the interval between starting polling cycles in W216 as xx.xx seconds
; rung 9: If polling has not occurred this scan, run the timer
LDNOT Polling_Has_Occurred
TIMH(015) 0013 #9999
; rung 10: If polling has restarted, reset the flag.
LD Polling_Has_Occurred
RSET Polling_Has_Occurred

### Section Responses

; rung 0: Detect a timeout, and set a bit to wait 1 PLC scan to resend / Modify for PMCR
%LD Send_PMCR
AND PMCR_Complete_NG
SET LogAnEasyModbusError  // Add this node and function code to the error list
; rung 1: Read responses
%LD Send_PMCR
LD=(300) EasyModbusPort1Command2 #1  // If the Modbus code that was sent was a 1 (Read Coil Status)
OR=(300) EasyModbusPort1Command2 #2  // If the Modbus code that was sent was a 2 (Read Input Status)
OR=(300) EasyModbusPort1Command2 #3  // If the Modbus code that was sent was a 3 (Read Holding Registers)
OR=(300) EasyModbusPort1Command2 #4  // If the Modbus code that was sent was a 04 (read Input Registers)
ANDLD
OUT TR0
AND PMCR_Complete_OK
MOVD(083) EasyModbusPort1Response5 #210 ,IR13
MOVD(083) EasyModbusPort1Response6 #12 ,IR13
MOVD(083) EasyModbusPort1Response6 #210 1,IR13
MOVD(083) EasyModbusPort1Response7 #12 1,IR13
MOV(021) #0 4,IR13  // Mark the Response OK with a 0 for OK DATA
LD TR0
LD PMCR_Complete_NG
ORNOT PMCR_Complete_OK  // Added for PMCR version in case PMCR did not start correctly
ANDLD
MOVL(498) #0 ,IR13  // Write 00000000 as the data across both response registeres
MOV(021) #FFFF 4,IR13  // Mark the Response OK with an FFFF for BAD DATA
SET LogAnEasyModbusError  // Add this node and function code to the error list

; rung 2: Write reponses
%LD Send_PMCR
ANDNOT Retry_Send_Delay
LD=(300) EasyModbusPort1Command2 #5  // If the Modbus code that was sent was a 5 (Read Coil Status)
OR=(300) EasyModbusPort1Command2 #6  // If the Modbus code that was sent was a 6 (Read Input Status)
OR=(300) EasyModbusPort1Command2 #F  // If the Modbus code that was sent was a F(Read Holding Registers)
OR=(300) EasyModbusPort1Command2 #10  // If the Modbus code that was sent was a 10
ANDLD
OUT TR0
AND PMCR_Complete_OK
OUT TR1
AND=(300) EasyModbusPort1Response3 #0  // And the Modbus  Error Code was 0
MOV(021) #0 8,IR13  // Mark the Response OK with a 0 for OK DATA
LD TR1
AND<>(305) EasyModbusPort1Response3 #0  // And the Modbus  Error Code was NOT 0
MOV(021) #FFFF 8,IR13  // Mark the Response OK with an FFFF for BAD DATA
SET LogAnEasyModbusError  // Add this node and function code to the error list
LD TR0
LD PMCR_Complete_NG
ORNOT PMCR_Complete_OK  // Added for PMCR version in case PMCR did not start correctly
ANDLD
MOV(021) #FFFF 8,IR13  // Mark the Response OK with an FFFF for BAD DATA
SET LogAnEasyModbusError  // Add this node and function code to the error list
; rung 3: Maintain a list of the last 5 Modbus Node Numbers, Function Codes, and starting DM addresses that caused an error / This is from W220 - W229, with W220 and W221 being the most recent. / Ex.  Node 1, Function 3, DM6050 causing the error: / W220 = 0103 (HEX) / W221 = 17A2 (HEX).  This is the 6050 part of D6050.
LD LogAnEasyModbusError
OUT TR0
XFER(070) &8 ModbusErrorNodeFunction1 ModbusErrorNodeFunction2  // Shift the last 9 records
MOVD(083) EasyModbusPort1Command1 #210 ModbusErrorNodeFunction1  // Capture the Modbus Node Number
MOVD(083) EasyModbusPort1Command2 #10 ModbusErrorNodeFunction1  // Capture the Modbus Function Code
-L(411) IR13 #10000 TemporaryStartingDMErrorLocation
AND<(310) TemporaryStartingDMErrorLocation &6000
-(410) TemporaryStartingDMErrorLocation #4 TemporaryStartingDMErrorLocation  // Subtract 4 to compensate for the offset difference between the receive area for a Write command vs a Read command
LD TR0
MOV(021) TemporaryStartingDMErrorLocation ModbusErrorDMAddress1
RSET LogAnEasyModbusError

; rung 4: Clear the error log
LD Clear_Error_Log
BSET(071) #0 ModbusErrorNodeFunction1 LastModbusCommandReceived10

### Section PMCR

; rung 0: Control the "Send_PMCR" / This is done to match the Easy Modbus for CP1H CP1L
LD Send_PMCR
%AND PMCR_Busy  // when the PMCR finishes
RSET Send_PMCR
; rung 1: Added for PMCR version to cancel Send PMCR in case it ever got stuck on. / This should not happen
LD Send_PMCR  // If the PMCR Send is on
ANDNOT PMCR_Busy  // but the port has not been busy for 3 seconds
TIM 0014 #30
AND T0014
RSET Send_PMCR  // reset the PMCR Busy
; rung 2: PMCR for Function Codes 1 - 4 (reading)
LD Send_PMCR
AND Logical_Port_Ready
ANDNOT PMCR_Busy
OUT TR0
LD=(300) EasyModbusPort1Command2 #1
OR=(300) EasyModbusPort1Command2 #2
ANDLD
OUT TR1
AND>=(325) EasyModbusPort1Command5 #0  // If equal to or greater than 0 (0 would actually return an error)
AND<=(315) EasyModbusPort1Command5 &8  // If less than or equal to 8
PMCR(260) #711F &1 #0 #0
LD TR1
AND>=(325) EasyModbusPort1Command5 &9  // If equal to or greater than 9
AND<=(315) EasyModbusPort1Command5 &16  // If less than or equal to 16
PMCR(260) #711F &21 #0 #0
LD TR1
AND>=(325) EasyModbusPort1Command5 &17  // If equal to or greater than 17
AND<=(315) EasyModbusPort1Command5 &24  // less than or equal to 24
PMCR(260) #711F &22 #0 #0
LD TR1
AND>=(325) EasyModbusPort1Command5 &25  // If equal to or greater than 25
PMCR(260) #711F &23 #0 #0
LD TR0
LD=(300) EasyModbusPort1Command2 #3
OR=(300) EasyModbusPort1Command2 #4
ANDLD
OUT TR0
AND<(310) EasyModbusPort1Command5 #2  // If less than 2 words are to be read (0 would cause PMCR error)
PMCR(260) #711F &3 #0 #0
LD TR0
AND>(320) EasyModbusPort1Command5 #1  // If more than 1 register is to be read (more than 2 would cause PMCR error)
PMCR(260) #711F &4 #0 #0

; rung 3: PMCR for Function Codes 5,6,0F, 10 (writing)
LD Send_PMCR
AND Logical_Port_Ready
ANDNOT PMCR_Busy
OUT TR0
LD=(300) EasyModbusPort1Command2 #5
OR=(300) EasyModbusPort1Command2 #6
ANDLD
PMCR(260) #711F &5 #0 #0
LD TR0
LD=(300) EasyModbusPort1Command2 #10
OR=(300) EasyModbusPort1Command2 #F
ANDLD
AND>=(325) EasyModbusPort1Command6 #200  // Checking for #02 in high byte
AND<=(315) EasyModbusPort1Command6 #2FF  // Checking for #02 in high byte
PMCR(260) #711F &16 #0 #0
LD TR0
LD=(300) EasyModbusPort1Command2 #10
OR=(300) EasyModbusPort1Command2 #F
ANDLD
AND>=(325) EasyModbusPort1Command6 #400  // Checking for #04 in high byte
AND<=(315) EasyModbusPort1Command6 #4FF  // Checking for #04 in high byte
PMCR(260) #711F &17 #0 #0

### Section END
; rung 0
END(001)

## Program Port2 (cyclic task 11)
Local symbols
Port_2_Clear_Error_Log W465.03 BOOL
Port_2_Consecutive_Writes W467 INT
Port_2_Current_Stack_Pointer W252 DWORD
Port_2_EasyModbusCommand1 D32400 CHANNEL
Port_2_EasyModbusCommand10 D32409 CHANNEL
Port_2_EasyModbusCommand2 D32401 CHANNEL
Port_2_EasyModbusCommand3 D32402 CHANNEL
Port_2_EasyModbusCommand4 D32403 CHANNEL
Port_2_EasyModbusCommand5 D32404 CHANNEL
Port_2_EasyModbusCommand6 D32405 CHANNEL
Port_2_EasyModbusCommand7 D32406 CHANNEL
Port_2_EasyModbusCommand8 D32407 CHANNEL
Port_2_EasyModbusCommand9 D32408 CHANNEL
Port_2_EasyModbusResponse1 D32450 CHANNEL
Port_2_EasyModbusResponse10 D32459 CHANNEL
Port_2_EasyModbusResponse2 D32451 CHANNEL
Port_2_EasyModbusResponse3 D32452 CHANNEL
Port_2_EasyModbusResponse4 D32453 CHANNEL
Port_2_EasyModbusResponse5 D32454 CHANNEL
Port_2_EasyModbusResponse6 D32455 CHANNEL
Port_2_EasyModbusResponse7 D32456 CHANNEL
Port_2_EasyModbusResponse8 D32457 CHANNEL
Port_2_EasyModbusResponse9 D32458 CHANNEL
Port_2_EndOfListMarkerReadItem1 D7009 CHANNEL
Port_2_EndOfListMarkerReadItem10 D7099 CHANNEL
Port_2_EndOfListMarkerReadItem100 D7999 CHANNEL
Port_2_EndOfListMarkerReadItem11 D7109 CHANNEL
Port_2_EndOfListMarkerReadItem12 D7119 CHANNEL
Port_2_EndOfListMarkerReadItem13 D7129 CHANNEL
Port_2_EndOfListMarkerReadItem14 D7139 CHANNEL
Port_2_EndOfListMarkerReadItem15 D7149 CHANNEL
Port_2_EndOfListMarkerReadItem16 D7159 CHANNEL
Port_2_EndOfListMarkerReadItem17 D7169 CHANNEL
Port_2_EndOfListMarkerReadItem18 D7179 CHANNEL
Port_2_EndOfListMarkerReadItem19 D7189 CHANNEL
Port_2_EndOfListMarkerReadItem2 D7019 CHANNEL
Port_2_EndOfListMarkerReadItem20 D7199 CHANNEL
Port_2_EndOfListMarkerReadItem21 D7209 CHANNEL
Port_2_EndOfListMarkerReadItem22 D7219 CHANNEL
Port_2_EndOfListMarkerReadItem23 D7229 CHANNEL
Port_2_EndOfListMarkerReadItem24 D7239 CHANNEL
Port_2_EndOfListMarkerReadItem25 D7249 CHANNEL
Port_2_EndOfListMarkerReadItem26 D7259 CHANNEL
Port_2_EndOfListMarkerReadItem27 D7269 CHANNEL
Port_2_EndOfListMarkerReadItem28 D7279 CHANNEL
Port_2_EndOfListMarkerReadItem29 D7289 CHANNEL
Port_2_EndOfListMarkerReadItem3 D7029 CHANNEL
Port_2_EndOfListMarkerReadItem30 D7299 CHANNEL
Port_2_EndOfListMarkerReadItem31 D7309 CHANNEL
Port_2_EndOfListMarkerReadItem32 D7319 CHANNEL
Port_2_EndOfListMarkerReadItem33 D7329 CHANNEL
Port_2_EndOfListMarkerReadItem34 D7339 CHANNEL
Port_2_EndOfListMarkerReadItem35 D7349 CHANNEL
Port_2_EndOfListMarkerReadItem36 D7359 CHANNEL
Port_2_EndOfListMarkerReadItem37 D7369 CHANNEL
Port_2_EndOfListMarkerReadItem38 D7379 CHANNEL
Port_2_EndOfListMarkerReadItem39 D7389 CHANNEL
Port_2_EndOfListMarkerReadItem4 D7039 CHANNEL
Port_2_EndOfListMarkerReadItem40 D7399 CHANNEL
Port_2_EndOfListMarkerReadItem41 D7409 CHANNEL
Port_2_EndOfListMarkerReadItem42 D7419 CHANNEL
Port_2_EndOfListMarkerReadItem43 D7429 CHANNEL
Port_2_EndOfListMarkerReadItem44 D7439 CHANNEL
Port_2_EndOfListMarkerReadItem45 D7449 CHANNEL
Port_2_EndOfListMarkerReadItem46 D7459 CHANNEL
Port_2_EndOfListMarkerReadItem47 D7469 CHANNEL
Port_2_EndOfListMarkerReadItem48 D7479 CHANNEL
Port_2_EndOfListMarkerReadItem49 D7489 CHANNEL
Port_2_EndOfListMarkerReadItem5 D7049 CHANNEL
Port_2_EndOfListMarkerReadItem50 D7499 CHANNEL
Port_2_EndOfListMarkerReadItem51 D7509 CHANNEL
Port_2_EndOfListMarkerReadItem52 D7519 CHANNEL
Port_2_EndOfListMarkerReadItem53 D7529 CHANNEL
Port_2_EndOfListMarkerReadItem54 D7539 CHANNEL
Port_2_EndOfListMarkerReadItem55 D7549 CHANNEL
Port_2_EndOfListMarkerReadItem56 D7559 CHANNEL
Port_2_EndOfListMarkerReadItem57 D7569 CHANNEL
Port_2_EndOfListMarkerReadItem58 D7579 CHANNEL
Port_2_EndOfListMarkerReadItem59 D7589 CHANNEL
Port_2_EndOfListMarkerReadItem6 D7059 CHANNEL
Port_2_EndOfListMarkerReadItem60 D7599 CHANNEL
Port_2_EndOfListMarkerReadItem61 D7609 CHANNEL
Port_2_EndOfListMarkerReadItem62 D7619 CHANNEL
Port_2_EndOfListMarkerReadItem63 D7629 CHANNEL
Port_2_EndOfListMarkerReadItem64 D7639 CHANNEL
Port_2_EndOfListMarkerReadItem65 D7649 CHANNEL
Port_2_EndOfListMarkerReadItem66 D7659 CHANNEL
Port_2_EndOfListMarkerReadItem67 D7669 CHANNEL
Port_2_EndOfListMarkerReadItem68 D7679 CHANNEL
Port_2_EndOfListMarkerReadItem69 D7689 CHANNEL
Port_2_EndOfListMarkerReadItem7 D7069 CHANNEL
Port_2_EndOfListMarkerReadItem70 D7699 CHANNEL
Port_2_EndOfListMarkerReadItem71 D7709 CHANNEL
Port_2_EndOfListMarkerReadItem72 D7719 CHANNEL
Port_2_EndOfListMarkerReadItem73 D7729 CHANNEL
Port_2_EndOfListMarkerReadItem74 D7739 CHANNEL
Port_2_EndOfListMarkerReadItem75 D7749 CHANNEL
Port_2_EndOfListMarkerReadItem76 D7759 CHANNEL
Port_2_EndOfListMarkerReadItem77 D7769 CHANNEL
Port_2_EndOfListMarkerReadItem78 D7779 CHANNEL
Port_2_EndOfListMarkerReadItem79 D7789 CHANNEL
Port_2_EndOfListMarkerReadItem8 D7079 CHANNEL
Port_2_EndOfListMarkerReadItem80 D7799 CHANNEL
Port_2_EndOfListMarkerReadItem81 D7809 CHANNEL
Port_2_EndOfListMarkerReadItem82 D7819 CHANNEL
Port_2_EndOfListMarkerReadItem83 D7829 CHANNEL
Port_2_EndOfListMarkerReadItem84 D7839 CHANNEL
Port_2_EndOfListMarkerReadItem85 D7849 CHANNEL
Port_2_EndOfListMarkerReadItem86 D7859 CHANNEL
Port_2_EndOfListMarkerReadItem87 D7869 CHANNEL
Port_2_EndOfListMarkerReadItem88 D7879 CHANNEL
Port_2_EndOfListMarkerReadItem89 D7889 CHANNEL
Port_2_EndOfListMarkerReadItem9 D7089 CHANNEL
Port_2_EndOfListMarkerReadItem90 D7899 CHANNEL
Port_2_EndOfListMarkerReadItem91 D7909 CHANNEL
Port_2_EndOfListMarkerReadItem92 D7919 CHANNEL
Port_2_EndOfListMarkerReadItem93 D7929 CHANNEL
Port_2_EndOfListMarkerReadItem94 D7939 CHANNEL
Port_2_EndOfListMarkerReadItem95 D7949 CHANNEL
Port_2_EndOfListMarkerReadItem96 D7959 CHANNEL
Port_2_EndOfListMarkerReadItem97 D7969 CHANNEL
Port_2_EndOfListMarkerReadItem98 D7979 CHANNEL
Port_2_EndOfListMarkerReadItem99 D7989 CHANNEL
Port_2_EndOfListMarkerWriteItem1 D8009 CHANNEL
Port_2_EndOfListMarkerWriteItem10 D8099 CHANNEL
Port_2_EndOfListMarkerWriteItem100 D8999 CHANNEL
Port_2_EndOfListMarkerWriteItem11 D8109 CHANNEL
Port_2_EndOfListMarkerWriteItem12 D8119 CHANNEL
Port_2_EndOfListMarkerWriteItem13 D8129 CHANNEL
Port_2_EndOfListMarkerWriteItem14 D8139 CHANNEL
Port_2_EndOfListMarkerWriteItem15 D8149 CHANNEL
Port_2_EndOfListMarkerWriteItem16 D8159 CHANNEL
Port_2_EndOfListMarkerWriteItem17 D8169 CHANNEL
Port_2_EndOfListMarkerWriteItem18 D8179 CHANNEL
Port_2_EndOfListMarkerWriteItem19 D8189 CHANNEL
Port_2_EndOfListMarkerWriteItem2 D8019 CHANNEL
Port_2_EndOfListMarkerWriteItem20 D8199 CHANNEL
Port_2_EndOfListMarkerWriteItem21 D8209 CHANNEL
Port_2_EndOfListMarkerWriteItem22 D8219 CHANNEL
Port_2_EndOfListMarkerWriteItem23 D8229 CHANNEL
Port_2_EndOfListMarkerWriteItem24 D8239 CHANNEL
Port_2_EndOfListMarkerWriteItem25 D8249 CHANNEL
Port_2_EndOfListMarkerWriteItem26 D8259 CHANNEL
Port_2_EndOfListMarkerWriteItem27 D8269 CHANNEL
Port_2_EndOfListMarkerWriteItem28 D8279 CHANNEL
Port_2_EndOfListMarkerWriteItem29 D8289 CHANNEL
Port_2_EndOfListMarkerWriteItem3 D8029 CHANNEL
Port_2_EndOfListMarkerWriteItem30 D8299 CHANNEL
Port_2_EndOfListMarkerWriteItem31 D8309 CHANNEL
Port_2_EndOfListMarkerWriteItem32 D8319 CHANNEL
Port_2_EndOfListMarkerWriteItem33 D8329 CHANNEL
Port_2_EndOfListMarkerWriteItem34 D8339 CHANNEL
Port_2_EndOfListMarkerWriteItem35 D8349 CHANNEL
Port_2_EndOfListMarkerWriteItem36 D8359 CHANNEL
Port_2_EndOfListMarkerWriteItem37 D8369 CHANNEL
Port_2_EndOfListMarkerWriteItem38 D8379 CHANNEL
Port_2_EndOfListMarkerWriteItem39 D8389 CHANNEL
Port_2_EndOfListMarkerWriteItem4 D8039 CHANNEL
Port_2_EndOfListMarkerWriteItem40 D8399 CHANNEL
Port_2_EndOfListMarkerWriteItem41 D8409 CHANNEL
Port_2_EndOfListMarkerWriteItem42 D8419 CHANNEL
Port_2_EndOfListMarkerWriteItem43 D8429 CHANNEL
Port_2_EndOfListMarkerWriteItem44 D8439 CHANNEL
Port_2_EndOfListMarkerWriteItem45 D8449 CHANNEL
Port_2_EndOfListMarkerWriteItem46 D8459 CHANNEL
Port_2_EndOfListMarkerWriteItem47 D8469 CHANNEL
Port_2_EndOfListMarkerWriteItem48 D8479 CHANNEL
Port_2_EndOfListMarkerWriteItem49 D8489 CHANNEL
Port_2_EndOfListMarkerWriteItem5 D8049 CHANNEL
Port_2_EndOfListMarkerWriteItem50 D8499 CHANNEL
Port_2_EndOfListMarkerWriteItem51 D8509 CHANNEL
Port_2_EndOfListMarkerWriteItem52 D8519 CHANNEL
Port_2_EndOfListMarkerWriteItem53 D8529 CHANNEL
Port_2_EndOfListMarkerWriteItem54 D8539 CHANNEL
Port_2_EndOfListMarkerWriteItem55 D8549 CHANNEL
Port_2_EndOfListMarkerWriteItem56 D8559 CHANNEL
Port_2_EndOfListMarkerWriteItem57 D8569 CHANNEL
Port_2_EndOfListMarkerWriteItem58 D8579 CHANNEL
Port_2_EndOfListMarkerWriteItem59 D8589 CHANNEL
Port_2_EndOfListMarkerWriteItem6 D8059 CHANNEL
Port_2_EndOfListMarkerWriteItem60 D8599 CHANNEL
Port_2_EndOfListMarkerWriteItem61 D8609 CHANNEL
Port_2_EndOfListMarkerWriteItem62 D8619 CHANNEL
Port_2_EndOfListMarkerWriteItem63 D8629 CHANNEL
Port_2_EndOfListMarkerWriteItem64 D8639 CHANNEL
Port_2_EndOfListMarkerWriteItem65 D8649 CHANNEL
Port_2_EndOfListMarkerWriteItem66 D8659 CHANNEL
Port_2_EndOfListMarkerWriteItem67 D8669 CHANNEL
Port_2_EndOfListMarkerWriteItem68 D8679 CHANNEL
Port_2_EndOfListMarkerWriteItem69 D8689 CHANNEL
Port_2_EndOfListMarkerWriteItem7 D8069 CHANNEL
Port_2_EndOfListMarkerWriteItem70 D8699 CHANNEL
Port_2_EndOfListMarkerWriteItem71 D8709 CHANNEL
Port_2_EndOfListMarkerWriteItem72 D8719 CHANNEL
Port_2_EndOfListMarkerWriteItem73 D8729 CHANNEL
Port_2_EndOfListMarkerWriteItem74 D8739 CHANNEL
Port_2_EndOfListMarkerWriteItem75 D8749 CHANNEL
Port_2_EndOfListMarkerWriteItem76 D8759 CHANNEL
Port_2_EndOfListMarkerWriteItem77 D8769 CHANNEL
Port_2_EndOfListMarkerWriteItem78 D8779 CHANNEL
Port_2_EndOfListMarkerWriteItem79 D8789 CHANNEL
Port_2_EndOfListMarkerWriteItem8 D8079 CHANNEL
Port_2_EndOfListMarkerWriteItem80 D8799 CHANNEL
Port_2_EndOfListMarkerWriteItem81 D8809 CHANNEL
Port_2_EndOfListMarkerWriteItem82 D8819 CHANNEL
Port_2_EndOfListMarkerWriteItem83 D8829 CHANNEL
Port_2_EndOfListMarkerWriteItem84 D8839 CHANNEL
Port_2_EndOfListMarkerWriteItem85 D8849 CHANNEL
Port_2_EndOfListMarkerWriteItem86 D8859 CHANNEL
Port_2_EndOfListMarkerWriteItem87 D8869 CHANNEL
Port_2_EndOfListMarkerWriteItem88 D8879 CHANNEL
Port_2_EndOfListMarkerWriteItem89 D8889 CHANNEL
Port_2_EndOfListMarkerWriteItem9 D8089 CHANNEL
Port_2_EndOfListMarkerWriteItem90 D8899 CHANNEL
Port_2_EndOfListMarkerWriteItem91 D8909 CHANNEL
Port_2_EndOfListMarkerWriteItem92 D8919 CHANNEL
Port_2_EndOfListMarkerWriteItem93 D8929 CHANNEL
Port_2_EndOfListMarkerWriteItem94 D8939 CHANNEL
Port_2_EndOfListMarkerWriteItem95 D8949 CHANNEL
Port_2_EndOfListMarkerWriteItem96 D8959 CHANNEL
Port_2_EndOfListMarkerWriteItem97 D8969 CHANNEL
Port_2_EndOfListMarkerWriteItem98 D8979 CHANNEL
Port_2_EndOfListMarkerWriteItem99 D8989 CHANNEL
Port_2_FirstWordResponseDataReadItem1 D7004 CHANNEL
Port_2_FirstWordResponseDataReadItem10 D7094 CHANNEL
Port_2_FirstWordResponseDataReadItem100 D7994 CHANNEL
Port_2_FirstWordResponseDataReadItem11 D7104 CHANNEL
Port_2_FirstWordResponseDataReadItem12 D7114 CHANNEL
Port_2_FirstWordResponseDataReadItem13 D7124 CHANNEL
Port_2_FirstWordResponseDataReadItem14 D7134 CHANNEL
Port_2_FirstWordResponseDataReadItem15 D7144 CHANNEL
Port_2_FirstWordResponseDataReadItem16 D7154 CHANNEL
Port_2_FirstWordResponseDataReadItem17 D7164 CHANNEL
Port_2_FirstWordResponseDataReadItem18 D7174 CHANNEL
Port_2_FirstWordResponseDataReadItem19 D7184 CHANNEL
Port_2_FirstWordResponseDataReadItem2 D7014 CHANNEL
Port_2_FirstWordResponseDataReadItem20 D7194 CHANNEL
Port_2_FirstWordResponseDataReadItem21 D7204 CHANNEL
Port_2_FirstWordResponseDataReadItem22 D7214 CHANNEL
Port_2_FirstWordResponseDataReadItem23 D7224 CHANNEL
Port_2_FirstWordResponseDataReadItem24 D7234 CHANNEL
Port_2_FirstWordResponseDataReadItem25 D7244 CHANNEL
Port_2_FirstWordResponseDataReadItem26 D7254 CHANNEL
Port_2_FirstWordResponseDataReadItem27 D7264 CHANNEL
Port_2_FirstWordResponseDataReadItem28 D7274 CHANNEL
Port_2_FirstWordResponseDataReadItem29 D7284 CHANNEL
Port_2_FirstWordResponseDataReadItem3 D7024 CHANNEL
Port_2_FirstWordResponseDataReadItem30 D7294 CHANNEL
Port_2_FirstWordResponseDataReadItem31 D7304 CHANNEL
Port_2_FirstWordResponseDataReadItem32 D7314 CHANNEL
Port_2_FirstWordResponseDataReadItem33 D7324 CHANNEL
Port_2_FirstWordResponseDataReadItem34 D7334 CHANNEL
Port_2_FirstWordResponseDataReadItem35 D7344 CHANNEL
Port_2_FirstWordResponseDataReadItem36 D7354 CHANNEL
Port_2_FirstWordResponseDataReadItem37 D7364 CHANNEL
Port_2_FirstWordResponseDataReadItem38 D7374 CHANNEL
Port_2_FirstWordResponseDataReadItem39 D7384 CHANNEL
Port_2_FirstWordResponseDataReadItem4 D7034 CHANNEL
Port_2_FirstWordResponseDataReadItem40 D7394 CHANNEL
Port_2_FirstWordResponseDataReadItem41 D7404 CHANNEL
Port_2_FirstWordResponseDataReadItem42 D7414 CHANNEL
Port_2_FirstWordResponseDataReadItem43 D7424 CHANNEL
Port_2_FirstWordResponseDataReadItem44 D7434 CHANNEL
Port_2_FirstWordResponseDataReadItem45 D7444 CHANNEL
Port_2_FirstWordResponseDataReadItem46 D7454 CHANNEL
Port_2_FirstWordResponseDataReadItem47 D7464 CHANNEL
Port_2_FirstWordResponseDataReadItem48 D7474 CHANNEL
Port_2_FirstWordResponseDataReadItem49 D7484 CHANNEL
Port_2_FirstWordResponseDataReadItem5 D7044 CHANNEL
Port_2_FirstWordResponseDataReadItem50 D7494 CHANNEL
Port_2_FirstWordResponseDataReadItem51 D7504 CHANNEL
Port_2_FirstWordResponseDataReadItem52 D7514 CHANNEL
Port_2_FirstWordResponseDataReadItem53 D7524 CHANNEL
Port_2_FirstWordResponseDataReadItem54 D7534 CHANNEL
Port_2_FirstWordResponseDataReadItem55 D7544 CHANNEL
Port_2_FirstWordResponseDataReadItem56 D7554 CHANNEL
Port_2_FirstWordResponseDataReadItem57 D7564 CHANNEL
Port_2_FirstWordResponseDataReadItem58 D7574 CHANNEL
Port_2_FirstWordResponseDataReadItem59 D7584 CHANNEL
Port_2_FirstWordResponseDataReadItem6 D7054 CHANNEL
Port_2_FirstWordResponseDataReadItem60 D7594 CHANNEL
Port_2_FirstWordResponseDataReadItem61 D7604 CHANNEL
Port_2_FirstWordResponseDataReadItem62 D7614 CHANNEL
Port_2_FirstWordResponseDataReadItem63 D7624 CHANNEL
Port_2_FirstWordResponseDataReadItem64 D7634 CHANNEL
Port_2_FirstWordResponseDataReadItem65 D7644 CHANNEL
Port_2_FirstWordResponseDataReadItem66 D7654 CHANNEL
Port_2_FirstWordResponseDataReadItem67 D7664 CHANNEL
Port_2_FirstWordResponseDataReadItem68 D7674 CHANNEL
Port_2_FirstWordResponseDataReadItem69 D7684 CHANNEL
Port_2_FirstWordResponseDataReadItem7 D7064 CHANNEL
Port_2_FirstWordResponseDataReadItem70 D7694 CHANNEL
Port_2_FirstWordResponseDataReadItem71 D7704 CHANNEL
Port_2_FirstWordResponseDataReadItem72 D7714 CHANNEL
Port_2_FirstWordResponseDataReadItem73 D7724 CHANNEL
Port_2_FirstWordResponseDataReadItem74 D7734 CHANNEL
Port_2_FirstWordResponseDataReadItem75 D7744 CHANNEL
Port_2_FirstWordResponseDataReadItem76 D7754 CHANNEL
Port_2_FirstWordResponseDataReadItem77 D7764 CHANNEL
Port_2_FirstWordResponseDataReadItem78 D7774 CHANNEL
Port_2_FirstWordResponseDataReadItem79 D7784 CHANNEL
Port_2_FirstWordResponseDataReadItem8 D7074 CHANNEL
Port_2_FirstWordResponseDataReadItem80 D7794 CHANNEL
Port_2_FirstWordResponseDataReadItem81 D7804 CHANNEL
Port_2_FirstWordResponseDataReadItem82 D7814 CHANNEL
Port_2_FirstWordResponseDataReadItem83 D7824 CHANNEL
Port_2_FirstWordResponseDataReadItem84 D7834 CHANNEL
Port_2_FirstWordResponseDataReadItem85 D7844 CHANNEL
Port_2_FirstWordResponseDataReadItem86 D7854 CHANNEL
Port_2_FirstWordResponseDataReadItem87 D7864 CHANNEL
Port_2_FirstWordResponseDataReadItem88 D7874 CHANNEL
Port_2_FirstWordResponseDataReadItem89 D7884 CHANNEL
Port_2_FirstWordResponseDataReadItem9 D7084 CHANNEL
Port_2_FirstWordResponseDataReadItem90 D7894 CHANNEL
Port_2_FirstWordResponseDataReadItem91 D7904 CHANNEL
Port_2_FirstWordResponseDataReadItem92 D7914 CHANNEL
Port_2_FirstWordResponseDataReadItem93 D7924 CHANNEL
Port_2_FirstWordResponseDataReadItem94 D7934 CHANNEL
Port_2_FirstWordResponseDataReadItem95 D7944 CHANNEL
Port_2_FirstWordResponseDataReadItem96 D7954 CHANNEL
Port_2_FirstWordResponseDataReadItem97 D7964 CHANNEL
Port_2_FirstWordResponseDataReadItem98 D7974 CHANNEL
Port_2_FirstWordResponseDataReadItem99 D7984 CHANNEL
Port_2_FirstWordWriteDataMirrorWriteItem1 D8006 CHANNEL
Port_2_FirstWordWriteDataMirrorWriteItem10 D8096 CHANNEL
Port_2_FirstWordWriteDataMirrorWriteItem100 D8996 CHANNEL
Port_2_FirstWordWriteDataMirrorWriteItem11 D8106 CHANNEL
Port_2_FirstWordWriteDataMirrorWriteItem12 D8116 CHANNEL
Port_2_FirstWordWriteDataMirrorWriteItem13 D8126 CHANNEL
Port_2_FirstWordWriteDataMirrorWriteItem14 D8136 CHANNEL
Port_2_FirstWordWriteDataMirrorWriteItem15 D8146 CHANNEL
Port_2_FirstWordWriteDataMirrorWriteItem16 D8156 CHANNEL
Port_2_FirstWordWriteDataMirrorWriteItem17 D8166 CHANNEL
Port_2_FirstWordWriteDataMirrorWriteItem18 D8176 CHANNEL
Port_2_FirstWordWriteDataMirrorWriteItem19 D8186 CHANNEL
Port_2_FirstWordWriteDataMirrorWriteItem2 D8016 CHANNEL
Port_2_FirstWordWriteDataMirrorWriteItem20 D8196 CHANNEL
Port_2_FirstWordWriteDataMirrorWriteItem21 D8206 CHANNEL
Port_2_FirstWordWriteDataMirrorWriteItem22 D8216 CHANNEL
Port_2_FirstWordWriteDataMirrorWriteItem23 D8226 CHANNEL
Port_2_FirstWordWriteDataMirrorWriteItem24 D8236 CHANNEL
Port_2_FirstWordWriteDataMirrorWriteItem25 D8246 CHANNEL
Port_2_FirstWordWriteDataMirrorWriteItem26 D8256 CHANNEL
Port_2_FirstWordWriteDataMirrorWriteItem27 D8266 CHANNEL
Port_2_FirstWordWriteDataMirrorWriteItem28 D8276 CHANNEL
Port_2_FirstWordWriteDataMirrorWriteItem29 D8286 CHANNEL
Port_2_FirstWordWriteDataMirrorWriteItem3 D8026 CHANNEL
Port_2_FirstWordWriteDataMirrorWriteItem30 D8296 CHANNEL
Port_2_FirstWordWriteDataMirrorWriteItem31 D8306 CHANNEL
Port_2_FirstWordWriteDataMirrorWriteItem32 D8316 CHANNEL
Port_2_FirstWordWriteDataMirrorWriteItem33 D8326 CHANNEL
Port_2_FirstWordWriteDataMirrorWriteItem34 D8336 CHANNEL
Port_2_FirstWordWriteDataMirrorWriteItem35 D8346 CHANNEL
Port_2_FirstWordWriteDataMirrorWriteItem36 D8356 CHANNEL
Port_2_FirstWordWriteDataMirrorWriteItem37 D8366 CHANNEL
Port_2_FirstWordWriteDataMirrorWriteItem38 D8376 CHANNEL
Port_2_FirstWordWriteDataMirrorWriteItem39 D8386 CHANNEL
Port_2_FirstWordWriteDataMirrorWriteItem4 D8036 CHANNEL
Port_2_FirstWordWriteDataMirrorWriteItem40 D8396 CHANNEL
Port_2_FirstWordWriteDataMirrorWriteItem41 D8406 CHANNEL
Port_2_FirstWordWriteDataMirrorWriteItem42 D8416 CHANNEL
Port_2_FirstWordWriteDataMirrorWriteItem43 D8426 CHANNEL
Port_2_FirstWordWriteDataMirrorWriteItem44 D8436 CHANNEL
Port_2_FirstWordWriteDataMirrorWriteItem45 D8446 CHANNEL
Port_2_FirstWordWriteDataMirrorWriteItem46 D8456 CHANNEL
Port_2_FirstWordWriteDataMirrorWriteItem47 D8466 CHANNEL
Port_2_FirstWordWriteDataMirrorWriteItem48 D8476 CHANNEL
Port_2_FirstWordWriteDataMirrorWriteItem49 D8486 CHANNEL
Port_2_FirstWordWriteDataMirrorWriteItem5 D8046 CHANNEL
Port_2_FirstWordWriteDataMirrorWriteItem50 D8496 CHANNEL
Port_2_FirstWordWriteDataMirrorWriteItem51 D8506 CHANNEL
Port_2_FirstWordWriteDataMirrorWriteItem52 D8516 CHANNEL
Port_2_FirstWordWriteDataMirrorWriteItem53 D8526 CHANNEL
Port_2_FirstWordWriteDataMirrorWriteItem54 D8536 CHANNEL
Port_2_FirstWordWriteDataMirrorWriteItem55 D8546 CHANNEL
Port_2_FirstWordWriteDataMirrorWriteItem56 D8556 CHANNEL
Port_2_FirstWordWriteDataMirrorWriteItem57 D8566 CHANNEL
Port_2_FirstWordWriteDataMirrorWriteItem58 D8576 CHANNEL
Port_2_FirstWordWriteDataMirrorWriteItem59 D8586 CHANNEL
Port_2_FirstWordWriteDataMirrorWriteItem6 D8056 CHANNEL
Port_2_FirstWordWriteDataMirrorWriteItem60 D8596 CHANNEL
Port_2_FirstWordWriteDataMirrorWriteItem61 D8606 CHANNEL
Port_2_FirstWordWriteDataMirrorWriteItem62 D8616 CHANNEL
Port_2_FirstWordWriteDataMirrorWriteItem63 D8626 CHANNEL
Port_2_FirstWordWriteDataMirrorWriteItem64 D8636 CHANNEL
Port_2_FirstWordWriteDataMirrorWriteItem65 D8646 CHANNEL
Port_2_FirstWordWriteDataMirrorWriteItem66 D8656 CHANNEL
Port_2_FirstWordWriteDataMirrorWriteItem67 D8666 CHANNEL
Port_2_FirstWordWriteDataMirrorWriteItem68 D8676 CHANNEL
Port_2_FirstWordWriteDataMirrorWriteItem69 D8686 CHANNEL
Port_2_FirstWordWriteDataMirrorWriteItem7 D8066 CHANNEL
Port_2_FirstWordWriteDataMirrorWriteItem70 D8696 CHANNEL
Port_2_FirstWordWriteDataMirrorWriteItem71 D8706 CHANNEL
Port_2_FirstWordWriteDataMirrorWriteItem72 D8716 CHANNEL
Port_2_FirstWordWriteDataMirrorWriteItem73 D8726 CHANNEL
Port_2_FirstWordWriteDataMirrorWriteItem74 D8736 CHANNEL
Port_2_FirstWordWriteDataMirrorWriteItem75 D8746 CHANNEL
Port_2_FirstWordWriteDataMirrorWriteItem76 D8756 CHANNEL
Port_2_FirstWordWriteDataMirrorWriteItem77 D8766 CHANNEL
Port_2_FirstWordWriteDataMirrorWriteItem78 D8776 CHANNEL
Port_2_FirstWordWriteDataMirrorWriteItem79 D8786 CHANNEL
Port_2_FirstWordWriteDataMirrorWriteItem8 D8076 CHANNEL
Port_2_FirstWordWriteDataMirrorWriteItem80 D8796 CHANNEL
Port_2_FirstWordWriteDataMirrorWriteItem81 D8806 CHANNEL
Port_2_FirstWordWriteDataMirrorWriteItem82 D8816 CHANNEL
Port_2_FirstWordWriteDataMirrorWriteItem83 D8826 CHANNEL
Port_2_FirstWordWriteDataMirrorWriteItem84 D8836 CHANNEL
Port_2_FirstWordWriteDataMirrorWriteItem85 D8846 CHANNEL
Port_2_FirstWordWriteDataMirrorWriteItem86 D8856 CHANNEL
Port_2_FirstWordWriteDataMirrorWriteItem87 D8866 CHANNEL
Port_2_FirstWordWriteDataMirrorWriteItem88 D8876 CHANNEL
Port_2_FirstWordWriteDataMirrorWriteItem89 D8886 CHANNEL
Port_2_FirstWordWriteDataMirrorWriteItem9 D8086 CHANNEL
Port_2_FirstWordWriteDataMirrorWriteItem90 D8896 CHANNEL
Port_2_FirstWordWriteDataMirrorWriteItem91 D8906 CHANNEL
Port_2_FirstWordWriteDataMirrorWriteItem92 D8916 CHANNEL
Port_2_FirstWordWriteDataMirrorWriteItem93 D8926 CHANNEL
Port_2_FirstWordWriteDataMirrorWriteItem94 D8936 CHANNEL
Port_2_FirstWordWriteDataMirrorWriteItem95 D8946 CHANNEL
Port_2_FirstWordWriteDataMirrorWriteItem96 D8956 CHANNEL
Port_2_FirstWordWriteDataMirrorWriteItem97 D8966 CHANNEL
Port_2_FirstWordWriteDataMirrorWriteItem98 D8976 CHANNEL
Port_2_FirstWordWriteDataMirrorWriteItem99 D8986 CHANNEL
Port_2_FirstWordWriteDataWriteItem1 D8004 CHANNEL
Port_2_FirstWordWriteDataWriteItem10 D8094 CHANNEL
Port_2_FirstWordWriteDataWriteItem100 D8994 CHANNEL
Port_2_FirstWordWriteDataWriteItem11 D8104 CHANNEL
Port_2_FirstWordWriteDataWriteItem12 D8114 CHANNEL
Port_2_FirstWordWriteDataWriteItem13 D8124 CHANNEL
Port_2_FirstWordWriteDataWriteItem14 D8134 CHANNEL
Port_2_FirstWordWriteDataWriteItem15 D8144 CHANNEL
Port_2_FirstWordWriteDataWriteItem16 D8154 CHANNEL
Port_2_FirstWordWriteDataWriteItem17 D8164 CHANNEL
Port_2_FirstWordWriteDataWriteItem18 D8174 CHANNEL
Port_2_FirstWordWriteDataWriteItem19 D8184 CHANNEL
Port_2_FirstWordWriteDataWriteItem2 D8014 CHANNEL
Port_2_FirstWordWriteDataWriteItem20 D8194 CHANNEL
Port_2_FirstWordWriteDataWriteItem21 D8204 CHANNEL
Port_2_FirstWordWriteDataWriteItem22 D8214 CHANNEL
Port_2_FirstWordWriteDataWriteItem23 D8224 CHANNEL
Port_2_FirstWordWriteDataWriteItem24 D8234 CHANNEL
Port_2_FirstWordWriteDataWriteItem25 D8244 CHANNEL
Port_2_FirstWordWriteDataWriteItem26 D8254 CHANNEL
Port_2_FirstWordWriteDataWriteItem27 D8264 CHANNEL
Port_2_FirstWordWriteDataWriteItem28 D8274 CHANNEL
Port_2_FirstWordWriteDataWriteItem29 D8284 CHANNEL
Port_2_FirstWordWriteDataWriteItem3 D8024 CHANNEL
Port_2_FirstWordWriteDataWriteItem30 D8294 CHANNEL
Port_2_FirstWordWriteDataWriteItem31 D8304 CHANNEL
Port_2_FirstWordWriteDataWriteItem32 D8314 CHANNEL
Port_2_FirstWordWriteDataWriteItem33 D8324 CHANNEL
Port_2_FirstWordWriteDataWriteItem34 D8334 CHANNEL
Port_2_FirstWordWriteDataWriteItem35 D8344 CHANNEL
Port_2_FirstWordWriteDataWriteItem36 D8354 CHANNEL
Port_2_FirstWordWriteDataWriteItem37 D8364 CHANNEL
Port_2_FirstWordWriteDataWriteItem38 D8374 CHANNEL
Port_2_FirstWordWriteDataWriteItem39 D8384 CHANNEL
Port_2_FirstWordWriteDataWriteItem4 D8034 CHANNEL
Port_2_FirstWordWriteDataWriteItem40 D8394 CHANNEL
Port_2_FirstWordWriteDataWriteItem41 D8404 CHANNEL
Port_2_FirstWordWriteDataWriteItem42 D8414 CHANNEL
Port_2_FirstWordWriteDataWriteItem43 D8424 CHANNEL
Port_2_FirstWordWriteDataWriteItem44 D8434 CHANNEL
Port_2_FirstWordWriteDataWriteItem45 D8444 CHANNEL
Port_2_FirstWordWriteDataWriteItem46 D8454 CHANNEL
Port_2_FirstWordWriteDataWriteItem47 D8464 CHANNEL
Port_2_FirstWordWriteDataWriteItem48 D8474 CHANNEL
Port_2_FirstWordWriteDataWriteItem49 D8484 CHANNEL
Port_2_FirstWordWriteDataWriteItem5 D8044 CHANNEL
Port_2_FirstWordWriteDataWriteItem50 D8494 CHANNEL
Port_2_FirstWordWriteDataWriteItem51 D8504 CHANNEL
Port_2_FirstWordWriteDataWriteItem52 D8514 CHANNEL
Port_2_FirstWordWriteDataWriteItem53 D8524 CHANNEL
Port_2_FirstWordWriteDataWriteItem54 D8534 CHANNEL
Port_2_FirstWordWriteDataWriteItem55 D8544 CHANNEL
Port_2_FirstWordWriteDataWriteItem56 D8554 CHANNEL
Port_2_FirstWordWriteDataWriteItem57 D8564 CHANNEL
Port_2_FirstWordWriteDataWriteItem58 D8574 CHANNEL
Port_2_FirstWordWriteDataWriteItem59 D8584 CHANNEL
Port_2_FirstWordWriteDataWriteItem6 D8054 CHANNEL
Port_2_FirstWordWriteDataWriteItem60 D8594 CHANNEL
Port_2_FirstWordWriteDataWriteItem61 D8604 CHANNEL
Port_2_FirstWordWriteDataWriteItem62 D8614 CHANNEL
Port_2_FirstWordWriteDataWriteItem63 D8624 CHANNEL
Port_2_FirstWordWriteDataWriteItem64 D8634 CHANNEL
Port_2_FirstWordWriteDataWriteItem65 D8644 CHANNEL
Port_2_FirstWordWriteDataWriteItem66 D8654 CHANNEL
Port_2_FirstWordWriteDataWriteItem67 D8664 CHANNEL
Port_2_FirstWordWriteDataWriteItem68 D8674 CHANNEL
Port_2_FirstWordWriteDataWriteItem69 D8684 CHANNEL
Port_2_FirstWordWriteDataWriteItem7 D8064 CHANNEL
Port_2_FirstWordWriteDataWriteItem70 D8694 CHANNEL
Port_2_FirstWordWriteDataWriteItem71 D8704 CHANNEL
Port_2_FirstWordWriteDataWriteItem72 D8714 CHANNEL
Port_2_FirstWordWriteDataWriteItem73 D8724 CHANNEL
Port_2_FirstWordWriteDataWriteItem74 D8734 CHANNEL
Port_2_FirstWordWriteDataWriteItem75 D8744 CHANNEL
Port_2_FirstWordWriteDataWriteItem76 D8754 CHANNEL
Port_2_FirstWordWriteDataWriteItem77 D8764 CHANNEL
Port_2_FirstWordWriteDataWriteItem78 D8774 CHANNEL
Port_2_FirstWordWriteDataWriteItem79 D8784 CHANNEL
Port_2_FirstWordWriteDataWriteItem8 D8074 CHANNEL
Port_2_FirstWordWriteDataWriteItem80 D8794 CHANNEL
Port_2_FirstWordWriteDataWriteItem81 D8804 CHANNEL
Port_2_FirstWordWriteDataWriteItem82 D8814 CHANNEL
Port_2_FirstWordWriteDataWriteItem83 D8824 CHANNEL
Port_2_FirstWordWriteDataWriteItem84 D8834 CHANNEL
Port_2_FirstWordWriteDataWriteItem85 D8844 CHANNEL
Port_2_FirstWordWriteDataWriteItem86 D8854 CHANNEL
Port_2_FirstWordWriteDataWriteItem87 D8864 CHANNEL
Port_2_FirstWordWriteDataWriteItem88 D8874 CHANNEL
Port_2_FirstWordWriteDataWriteItem89 D8884 CHANNEL
Port_2_FirstWordWriteDataWriteItem9 D8084 CHANNEL
Port_2_FirstWordWriteDataWriteItem90 D8894 CHANNEL
Port_2_FirstWordWriteDataWriteItem91 D8904 CHANNEL
Port_2_FirstWordWriteDataWriteItem92 D8914 CHANNEL
Port_2_FirstWordWriteDataWriteItem93 D8924 CHANNEL
Port_2_FirstWordWriteDataWriteItem94 D8934 CHANNEL
Port_2_FirstWordWriteDataWriteItem95 D8944 CHANNEL
Port_2_FirstWordWriteDataWriteItem96 D8954 CHANNEL
Port_2_FirstWordWriteDataWriteItem97 D8964 CHANNEL
Port_2_FirstWordWriteDataWriteItem98 D8974 CHANNEL
Port_2_FirstWordWriteDataWriteItem99 D8984 CHANNEL
Port_2_LastModbusCommandReceived1 W490 CHANNEL
Port_2_LastModbusCommandReceived10 W499 CHANNEL
Port_2_LastModbusCommandReceived2 W491 CHANNEL
Port_2_LastModbusCommandReceived3 W492 CHANNEL
Port_2_LastModbusCommandReceived4 W493 CHANNEL
Port_2_LastModbusCommandReceived5 W494 CHANNEL
Port_2_LastModbusCommandReceived6 W495 CHANNEL
Port_2_LastModbusCommandReceived7 W496 CHANNEL
Port_2_LastModbusCommandReceived8 W497 CHANNEL
Port_2_LastModbusCommandReceived9 W498 CHANNEL
Port_2_LastModbusCommandSent1 W480 CHANNEL
Port_2_LastModbusCommandSent10 W489 CHANNEL
Port_2_LastModbusCommandSent2 W481 CHANNEL
Port_2_LastModbusCommandSent3 W482 CHANNEL
Port_2_LastModbusCommandSent4 W483 CHANNEL
Port_2_LastModbusCommandSent5 W484 CHANNEL
Port_2_LastModbusCommandSent6 W485 CHANNEL
Port_2_LastModbusCommandSent7 W486 CHANNEL
Port_2_LastModbusCommandSent8 W487 CHANNEL
Port_2_LastModbusCommandSent9 W488 CHANNEL
Port_2_LogAnEasyModbusError W465.00 BOOL
Port_2_Logical_Port_Ready A202.06 BOOL
Port_2_ModbusErrorDMAddress1 W471 CHANNEL
Port_2_ModbusErrorDMAddress2 W473 CHANNEL
Port_2_ModbusErrorDMAddress3 W475 CHANNEL
Port_2_ModbusErrorDMAddress4 W477 CHANNEL
Port_2_ModbusErrorDMAddress5 W479 CHANNEL
Port_2_ModbusErrorNodeFunction1 W470 CHANNEL
Port_2_ModbusErrorNodeFunction2 W472 CHANNEL
Port_2_ModbusErrorNodeFunction3 W474 CHANNEL
Port_2_ModbusErrorNodeFunction4 W476 CHANNEL
Port_2_ModbusErrorNodeFunction5 W478 CHANNEL
Port_2_ModbusFunctionCodeReadItem1 D7001 CHANNEL
Port_2_ModbusFunctionCodeReadItem10 D7091 CHANNEL
Port_2_ModbusFunctionCodeReadItem100 D7991 CHANNEL
Port_2_ModbusFunctionCodeReadItem11 D7101 CHANNEL
Port_2_ModbusFunctionCodeReadItem12 D7111 CHANNEL
Port_2_ModbusFunctionCodeReadItem13 D7121 CHANNEL
Port_2_ModbusFunctionCodeReadItem14 D7131 CHANNEL
Port_2_ModbusFunctionCodeReadItem15 D7141 CHANNEL
Port_2_ModbusFunctionCodeReadItem16 D7151 CHANNEL
Port_2_ModbusFunctionCodeReadItem17 D7161 CHANNEL
Port_2_ModbusFunctionCodeReadItem18 D7171 CHANNEL
Port_2_ModbusFunctionCodeReadItem19 D7181 CHANNEL
Port_2_ModbusFunctionCodeReadItem2 D7011 CHANNEL
Port_2_ModbusFunctionCodeReadItem20 D7191 CHANNEL
Port_2_ModbusFunctionCodeReadItem21 D7201 CHANNEL
Port_2_ModbusFunctionCodeReadItem22 D7211 CHANNEL
Port_2_ModbusFunctionCodeReadItem23 D7221 CHANNEL
Port_2_ModbusFunctionCodeReadItem24 D7231 CHANNEL
Port_2_ModbusFunctionCodeReadItem25 D7241 CHANNEL
Port_2_ModbusFunctionCodeReadItem26 D7251 CHANNEL
Port_2_ModbusFunctionCodeReadItem27 D7261 CHANNEL
Port_2_ModbusFunctionCodeReadItem28 D7271 CHANNEL
Port_2_ModbusFunctionCodeReadItem29 D7281 CHANNEL
Port_2_ModbusFunctionCodeReadItem3 D7021 CHANNEL
Port_2_ModbusFunctionCodeReadItem30 D7291 CHANNEL
Port_2_ModbusFunctionCodeReadItem31 D7301 CHANNEL
Port_2_ModbusFunctionCodeReadItem32 D7311 CHANNEL
Port_2_ModbusFunctionCodeReadItem33 D7321 CHANNEL
Port_2_ModbusFunctionCodeReadItem34 D7331 CHANNEL
Port_2_ModbusFunctionCodeReadItem35 D7341 CHANNEL
Port_2_ModbusFunctionCodeReadItem36 D7351 CHANNEL
Port_2_ModbusFunctionCodeReadItem37 D7361 CHANNEL
Port_2_ModbusFunctionCodeReadItem38 D7371 CHANNEL
Port_2_ModbusFunctionCodeReadItem39 D7381 CHANNEL
Port_2_ModbusFunctionCodeReadItem4 D7031 CHANNEL
Port_2_ModbusFunctionCodeReadItem40 D7391 CHANNEL
Port_2_ModbusFunctionCodeReadItem41 D7401 CHANNEL
Port_2_ModbusFunctionCodeReadItem42 D7411 CHANNEL
Port_2_ModbusFunctionCodeReadItem43 D7421 CHANNEL
Port_2_ModbusFunctionCodeReadItem44 D7431 CHANNEL
Port_2_ModbusFunctionCodeReadItem45 D7441 CHANNEL
Port_2_ModbusFunctionCodeReadItem46 D7451 CHANNEL
Port_2_ModbusFunctionCodeReadItem47 D7461 CHANNEL
Port_2_ModbusFunctionCodeReadItem48 D7471 CHANNEL
Port_2_ModbusFunctionCodeReadItem49 D7481 CHANNEL
Port_2_ModbusFunctionCodeReadItem5 D7041 CHANNEL
Port_2_ModbusFunctionCodeReadItem50 D7491 CHANNEL
Port_2_ModbusFunctionCodeReadItem51 D7501 CHANNEL
Port_2_ModbusFunctionCodeReadItem52 D7511 CHANNEL
Port_2_ModbusFunctionCodeReadItem53 D7521 CHANNEL
Port_2_ModbusFunctionCodeReadItem54 D7531 CHANNEL
Port_2_ModbusFunctionCodeReadItem55 D7541 CHANNEL
Port_2_ModbusFunctionCodeReadItem56 D7551 CHANNEL
Port_2_ModbusFunctionCodeReadItem57 D7561 CHANNEL
Port_2_ModbusFunctionCodeReadItem58 D7571 CHANNEL
Port_2_ModbusFunctionCodeReadItem59 D7581 CHANNEL
Port_2_ModbusFunctionCodeReadItem6 D7051 CHANNEL
Port_2_ModbusFunctionCodeReadItem60 D7591 CHANNEL
Port_2_ModbusFunctionCodeReadItem61 D7601 CHANNEL
Port_2_ModbusFunctionCodeReadItem62 D7611 CHANNEL
Port_2_ModbusFunctionCodeReadItem63 D7621 CHANNEL
Port_2_ModbusFunctionCodeReadItem64 D7631 CHANNEL
Port_2_ModbusFunctionCodeReadItem65 D7641 CHANNEL
Port_2_ModbusFunctionCodeReadItem66 D7651 CHANNEL
Port_2_ModbusFunctionCodeReadItem67 D7661 CHANNEL
Port_2_ModbusFunctionCodeReadItem68 D7671 CHANNEL
Port_2_ModbusFunctionCodeReadItem69 D7681 CHANNEL
Port_2_ModbusFunctionCodeReadItem7 D7061 CHANNEL
Port_2_ModbusFunctionCodeReadItem70 D7691 CHANNEL
Port_2_ModbusFunctionCodeReadItem71 D7701 CHANNEL
Port_2_ModbusFunctionCodeReadItem72 D7711 CHANNEL
Port_2_ModbusFunctionCodeReadItem73 D7721 CHANNEL
Port_2_ModbusFunctionCodeReadItem74 D7731 CHANNEL
Port_2_ModbusFunctionCodeReadItem75 D7741 CHANNEL
Port_2_ModbusFunctionCodeReadItem76 D7751 CHANNEL
Port_2_ModbusFunctionCodeReadItem77 D7761 CHANNEL
Port_2_ModbusFunctionCodeReadItem78 D7771 CHANNEL
Port_2_ModbusFunctionCodeReadItem79 D7781 CHANNEL
Port_2_ModbusFunctionCodeReadItem8 D7071 CHANNEL
Port_2_ModbusFunctionCodeReadItem80 D7791 CHANNEL
Port_2_ModbusFunctionCodeReadItem81 D7801 CHANNEL
Port_2_ModbusFunctionCodeReadItem82 D7811 CHANNEL
Port_2_ModbusFunctionCodeReadItem83 D7821 CHANNEL
Port_2_ModbusFunctionCodeReadItem84 D7831 CHANNEL
Port_2_ModbusFunctionCodeReadItem85 D7841 CHANNEL
Port_2_ModbusFunctionCodeReadItem86 D7851 CHANNEL
Port_2_ModbusFunctionCodeReadItem87 D7861 CHANNEL
Port_2_ModbusFunctionCodeReadItem88 D7871 CHANNEL
Port_2_ModbusFunctionCodeReadItem89 D7881 CHANNEL
Port_2_ModbusFunctionCodeReadItem9 D7081 CHANNEL
Port_2_ModbusFunctionCodeReadItem90 D7891 CHANNEL
Port_2_ModbusFunctionCodeReadItem91 D7901 CHANNEL
Port_2_ModbusFunctionCodeReadItem92 D7911 CHANNEL
Port_2_ModbusFunctionCodeReadItem93 D7921 CHANNEL
Port_2_ModbusFunctionCodeReadItem94 D7931 CHANNEL
Port_2_ModbusFunctionCodeReadItem95 D7941 CHANNEL
Port_2_ModbusFunctionCodeReadItem96 D7951 CHANNEL
Port_2_ModbusFunctionCodeReadItem97 D7961 CHANNEL
Port_2_ModbusFunctionCodeReadItem98 D7971 CHANNEL
Port_2_ModbusFunctionCodeReadItem99 D7981 CHANNEL
Port_2_ModbusFunctionCodeWriteItem1 D8001 CHANNEL
Port_2_ModbusFunctionCodeWriteItem10 D8091 CHANNEL
Port_2_ModbusFunctionCodeWriteItem100 D8991 CHANNEL
Port_2_ModbusFunctionCodeWriteItem11 D8101 CHANNEL
Port_2_ModbusFunctionCodeWriteItem12 D8111 CHANNEL
Port_2_ModbusFunctionCodeWriteItem13 D8121 CHANNEL
Port_2_ModbusFunctionCodeWriteItem14 D8131 CHANNEL
Port_2_ModbusFunctionCodeWriteItem15 D8141 CHANNEL
Port_2_ModbusFunctionCodeWriteItem16 D8151 CHANNEL
Port_2_ModbusFunctionCodeWriteItem17 D8161 CHANNEL
Port_2_ModbusFunctionCodeWriteItem18 D8171 CHANNEL
Port_2_ModbusFunctionCodeWriteItem19 D8181 CHANNEL
Port_2_ModbusFunctionCodeWriteItem2 D8011 CHANNEL
Port_2_ModbusFunctionCodeWriteItem20 D8191 CHANNEL
Port_2_ModbusFunctionCodeWriteItem21 D8201 CHANNEL
Port_2_ModbusFunctionCodeWriteItem22 D8211 CHANNEL
Port_2_ModbusFunctionCodeWriteItem23 D8221 CHANNEL
Port_2_ModbusFunctionCodeWriteItem24 D8231 CHANNEL
Port_2_ModbusFunctionCodeWriteItem25 D8241 CHANNEL
Port_2_ModbusFunctionCodeWriteItem26 D8251 CHANNEL
Port_2_ModbusFunctionCodeWriteItem27 D8261 CHANNEL
Port_2_ModbusFunctionCodeWriteItem28 D8271 CHANNEL
Port_2_ModbusFunctionCodeWriteItem29 D8281 CHANNEL
Port_2_ModbusFunctionCodeWriteItem3 D8021 CHANNEL
Port_2_ModbusFunctionCodeWriteItem30 D8291 CHANNEL
Port_2_ModbusFunctionCodeWriteItem31 D8301 CHANNEL
Port_2_ModbusFunctionCodeWriteItem32 D8311 CHANNEL
Port_2_ModbusFunctionCodeWriteItem33 D8321 CHANNEL
Port_2_ModbusFunctionCodeWriteItem34 D8331 CHANNEL
Port_2_ModbusFunctionCodeWriteItem35 D8341 CHANNEL
Port_2_ModbusFunctionCodeWriteItem36 D8351 CHANNEL
Port_2_ModbusFunctionCodeWriteItem37 D8361 CHANNEL
Port_2_ModbusFunctionCodeWriteItem38 D8371 CHANNEL
Port_2_ModbusFunctionCodeWriteItem39 D8381 CHANNEL
Port_2_ModbusFunctionCodeWriteItem4 D8031 CHANNEL
Port_2_ModbusFunctionCodeWriteItem40 D8391 CHANNEL
Port_2_ModbusFunctionCodeWriteItem41 D8401 CHANNEL
Port_2_ModbusFunctionCodeWriteItem42 D8411 CHANNEL
Port_2_ModbusFunctionCodeWriteItem43 D8421 CHANNEL
Port_2_ModbusFunctionCodeWriteItem44 D8431 CHANNEL
Port_2_ModbusFunctionCodeWriteItem45 D8441 CHANNEL
Port_2_ModbusFunctionCodeWriteItem46 D8451 CHANNEL
Port_2_ModbusFunctionCodeWriteItem47 D8461 CHANNEL
Port_2_ModbusFunctionCodeWriteItem48 D8471 CHANNEL
Port_2_ModbusFunctionCodeWriteItem49 D8481 CHANNEL
Port_2_ModbusFunctionCodeWriteItem5 D8041 CHANNEL
Port_2_ModbusFunctionCodeWriteItem50 D8491 CHANNEL
Port_2_ModbusFunctionCodeWriteItem51 D8501 CHANNEL
Port_2_ModbusFunctionCodeWriteItem52 D8511 CHANNEL
Port_2_ModbusFunctionCodeWriteItem53 D8521 CHANNEL
Port_2_ModbusFunctionCodeWriteItem54 D8531 CHANNEL
Port_2_ModbusFunctionCodeWriteItem55 D8541 CHANNEL
Port_2_ModbusFunctionCodeWriteItem56 D8551 CHANNEL
Port_2_ModbusFunctionCodeWriteItem57 D8561 CHANNEL
Port_2_ModbusFunctionCodeWriteItem58 D8571 CHANNEL
Port_2_ModbusFunctionCodeWriteItem59 D8581 CHANNEL
Port_2_ModbusFunctionCodeWriteItem6 D8051 CHANNEL
Port_2_ModbusFunctionCodeWriteItem60 D8591 CHANNEL
Port_2_ModbusFunctionCodeWriteItem61 D8601 CHANNEL
Port_2_ModbusFunctionCodeWriteItem62 D8611 CHANNEL
Port_2_ModbusFunctionCodeWriteItem63 D8621 CHANNEL
Port_2_ModbusFunctionCodeWriteItem64 D8631 CHANNEL
Port_2_ModbusFunctionCodeWriteItem65 D8641 CHANNEL
Port_2_ModbusFunctionCodeWriteItem66 D8651 CHANNEL
Port_2_ModbusFunctionCodeWriteItem67 D8661 CHANNEL
Port_2_ModbusFunctionCodeWriteItem68 D8671 CHANNEL
Port_2_ModbusFunctionCodeWriteItem69 D8681 CHANNEL
Port_2_ModbusFunctionCodeWriteItem7 D8061 CHANNEL
Port_2_ModbusFunctionCodeWriteItem70 D8691 CHANNEL
Port_2_ModbusFunctionCodeWriteItem71 D8701 CHANNEL
Port_2_ModbusFunctionCodeWriteItem72 D8711 CHANNEL
Port_2_ModbusFunctionCodeWriteItem73 D8721 CHANNEL
Port_2_ModbusFunctionCodeWriteItem74 D8731 CHANNEL
Port_2_ModbusFunctionCodeWriteItem75 D8741 CHANNEL
Port_2_ModbusFunctionCodeWriteItem76 D8751 CHANNEL
Port_2_ModbusFunctionCodeWriteItem77 D8761 CHANNEL
Port_2_ModbusFunctionCodeWriteItem78 D8771 CHANNEL
Port_2_ModbusFunctionCodeWriteItem79 D8781 CHANNEL
Port_2_ModbusFunctionCodeWriteItem8 D8071 CHANNEL
Port_2_ModbusFunctionCodeWriteItem80 D8791 CHANNEL
Port_2_ModbusFunctionCodeWriteItem81 D8801 CHANNEL
Port_2_ModbusFunctionCodeWriteItem82 D8811 CHANNEL
Port_2_ModbusFunctionCodeWriteItem83 D8821 CHANNEL
Port_2_ModbusFunctionCodeWriteItem84 D8831 CHANNEL
Port_2_ModbusFunctionCodeWriteItem85 D8841 CHANNEL
Port_2_ModbusFunctionCodeWriteItem86 D8851 CHANNEL
Port_2_ModbusFunctionCodeWriteItem87 D8861 CHANNEL
Port_2_ModbusFunctionCodeWriteItem88 D8871 CHANNEL
Port_2_ModbusFunctionCodeWriteItem89 D8881 CHANNEL
Port_2_ModbusFunctionCodeWriteItem9 D8081 CHANNEL
Port_2_ModbusFunctionCodeWriteItem90 D8891 CHANNEL
Port_2_ModbusFunctionCodeWriteItem91 D8901 CHANNEL
Port_2_ModbusFunctionCodeWriteItem92 D8911 CHANNEL
Port_2_ModbusFunctionCodeWriteItem93 D8921 CHANNEL
Port_2_ModbusFunctionCodeWriteItem94 D8931 CHANNEL
Port_2_ModbusFunctionCodeWriteItem95 D8941 CHANNEL
Port_2_ModbusFunctionCodeWriteItem96 D8951 CHANNEL
Port_2_ModbusFunctionCodeWriteItem97 D8961 CHANNEL
Port_2_ModbusFunctionCodeWriteItem98 D8971 CHANNEL
Port_2_ModbusFunctionCodeWriteItem99 D8981 CHANNEL
Port_2_ModbusNodeNumberReadItem1 D7000 CHANNEL
Port_2_ModbusNodeNumberReadItem10 D7090 CHANNEL
Port_2_ModbusNodeNumberReadItem100 D7990 CHANNEL
Port_2_ModbusNodeNumberReadItem11 D7100 CHANNEL
Port_2_ModbusNodeNumberReadItem12 D7110 CHANNEL
Port_2_ModbusNodeNumberReadItem13 D7120 CHANNEL
Port_2_ModbusNodeNumberReadItem14 D7130 CHANNEL
Port_2_ModbusNodeNumberReadItem15 D7140 CHANNEL
Port_2_ModbusNodeNumberReadItem16 D7150 CHANNEL
Port_2_ModbusNodeNumberReadItem17 D7160 CHANNEL
Port_2_ModbusNodeNumberReadItem18 D7170 CHANNEL
Port_2_ModbusNodeNumberReadItem19 D7180 CHANNEL
Port_2_ModbusNodeNumberReadItem2 D7010 CHANNEL
Port_2_ModbusNodeNumberReadItem20 D7190 CHANNEL
Port_2_ModbusNodeNumberReadItem21 D7200 CHANNEL
Port_2_ModbusNodeNumberReadItem22 D7210 CHANNEL
Port_2_ModbusNodeNumberReadItem23 D7220 CHANNEL
Port_2_ModbusNodeNumberReadItem24 D7230 CHANNEL
Port_2_ModbusNodeNumberReadItem25 D7240 CHANNEL
Port_2_ModbusNodeNumberReadItem26 D7250 CHANNEL
Port_2_ModbusNodeNumberReadItem27 D7260 CHANNEL
Port_2_ModbusNodeNumberReadItem28 D7270 CHANNEL
Port_2_ModbusNodeNumberReadItem29 D7280 CHANNEL
Port_2_ModbusNodeNumberReadItem3 D7020 CHANNEL
Port_2_ModbusNodeNumberReadItem30 D7290 CHANNEL
Port_2_ModbusNodeNumberReadItem31 D7300 CHANNEL
Port_2_ModbusNodeNumberReadItem32 D7310 CHANNEL
Port_2_ModbusNodeNumberReadItem33 D7320 CHANNEL
Port_2_ModbusNodeNumberReadItem34 D7330 CHANNEL
Port_2_ModbusNodeNumberReadItem35 D7340 CHANNEL
Port_2_ModbusNodeNumberReadItem36 D7350 CHANNEL
Port_2_ModbusNodeNumberReadItem37 D7360 CHANNEL
Port_2_ModbusNodeNumberReadItem38 D7370 CHANNEL
Port_2_ModbusNodeNumberReadItem39 D7380 CHANNEL
Port_2_ModbusNodeNumberReadItem4 D7030 CHANNEL
Port_2_ModbusNodeNumberReadItem40 D7390 CHANNEL
Port_2_ModbusNodeNumberReadItem41 D7400 CHANNEL
Port_2_ModbusNodeNumberReadItem42 D7410 CHANNEL
Port_2_ModbusNodeNumberReadItem43 D7420 CHANNEL
Port_2_ModbusNodeNumberReadItem44 D7430 CHANNEL
Port_2_ModbusNodeNumberReadItem45 D7440 CHANNEL
Port_2_ModbusNodeNumberReadItem46 D7450 CHANNEL
Port_2_ModbusNodeNumberReadItem47 D7460 CHANNEL
Port_2_ModbusNodeNumberReadItem48 D7470 CHANNEL
Port_2_ModbusNodeNumberReadItem49 D7480 CHANNEL
Port_2_ModbusNodeNumberReadItem5 D7040 CHANNEL
Port_2_ModbusNodeNumberReadItem50 D7490 CHANNEL
Port_2_ModbusNodeNumberReadItem51 D7500 CHANNEL
Port_2_ModbusNodeNumberReadItem52 D7510 CHANNEL
Port_2_ModbusNodeNumberReadItem53 D7520 CHANNEL
Port_2_ModbusNodeNumberReadItem54 D7530 CHANNEL
Port_2_ModbusNodeNumberReadItem55 D7540 CHANNEL
Port_2_ModbusNodeNumberReadItem56 D7550 CHANNEL
Port_2_ModbusNodeNumberReadItem57 D7560 CHANNEL
Port_2_ModbusNodeNumberReadItem58 D7570 CHANNEL
Port_2_ModbusNodeNumberReadItem59 D7580 CHANNEL
Port_2_ModbusNodeNumberReadItem6 D7050 CHANNEL
Port_2_ModbusNodeNumberReadItem60 D7590 CHANNEL
Port_2_ModbusNodeNumberReadItem61 D7600 CHANNEL
Port_2_ModbusNodeNumberReadItem62 D7610 CHANNEL
Port_2_ModbusNodeNumberReadItem63 D7620 CHANNEL
Port_2_ModbusNodeNumberReadItem64 D7630 CHANNEL
Port_2_ModbusNodeNumberReadItem65 D7640 CHANNEL
Port_2_ModbusNodeNumberReadItem66 D7650 CHANNEL
Port_2_ModbusNodeNumberReadItem67 D7660 CHANNEL
Port_2_ModbusNodeNumberReadItem68 D7670 CHANNEL
Port_2_ModbusNodeNumberReadItem69 D7680 CHANNEL
Port_2_ModbusNodeNumberReadItem7 D7060 CHANNEL
Port_2_ModbusNodeNumberReadItem70 D7690 CHANNEL
Port_2_ModbusNodeNumberReadItem71 D7700 CHANNEL
Port_2_ModbusNodeNumberReadItem72 D7710 CHANNEL
Port_2_ModbusNodeNumberReadItem73 D7720 CHANNEL
Port_2_ModbusNodeNumberReadItem74 D7730 CHANNEL
Port_2_ModbusNodeNumberReadItem75 D7740 CHANNEL
Port_2_ModbusNodeNumberReadItem76 D7750 CHANNEL
Port_2_ModbusNodeNumberReadItem77 D7760 CHANNEL
Port_2_ModbusNodeNumberReadItem78 D7770 CHANNEL
Port_2_ModbusNodeNumberReadItem79 D7780 CHANNEL
Port_2_ModbusNodeNumberReadItem8 D7070 CHANNEL
Port_2_ModbusNodeNumberReadItem80 D7790 CHANNEL
Port_2_ModbusNodeNumberReadItem81 D7800 CHANNEL
Port_2_ModbusNodeNumberReadItem82 D7810 CHANNEL
Port_2_ModbusNodeNumberReadItem83 D7820 CHANNEL
Port_2_ModbusNodeNumberReadItem84 D7830 CHANNEL
Port_2_ModbusNodeNumberReadItem85 D7840 CHANNEL
Port_2_ModbusNodeNumberReadItem86 D7850 CHANNEL
Port_2_ModbusNodeNumberReadItem87 D7860 CHANNEL
Port_2_ModbusNodeNumberReadItem88 D7870 CHANNEL
Port_2_ModbusNodeNumberReadItem89 D7880 CHANNEL
Port_2_ModbusNodeNumberReadItem9 D7080 CHANNEL
Port_2_ModbusNodeNumberReadItem90 D7890 CHANNEL
Port_2_ModbusNodeNumberReadItem91 D7900 CHANNEL
Port_2_ModbusNodeNumberReadItem92 D7910 CHANNEL
Port_2_ModbusNodeNumberReadItem93 D7920 CHANNEL
Port_2_ModbusNodeNumberReadItem94 D7930 CHANNEL
Port_2_ModbusNodeNumberReadItem95 D7940 CHANNEL
Port_2_ModbusNodeNumberReadItem96 D7950 CHANNEL
Port_2_ModbusNodeNumberReadItem97 D7960 CHANNEL
Port_2_ModbusNodeNumberReadItem98 D7970 CHANNEL
Port_2_ModbusNodeNumberReadItem99 D7980 CHANNEL
Port_2_ModbusNodeNumberWriteItem1 D8000 CHANNEL
Port_2_ModbusNodeNumberWriteItem10 D8090 CHANNEL
Port_2_ModbusNodeNumberWriteItem100 D8990 CHANNEL
Port_2_ModbusNodeNumberWriteItem11 D8100 CHANNEL
Port_2_ModbusNodeNumberWriteItem12 D8110 CHANNEL
Port_2_ModbusNodeNumberWriteItem13 D8120 CHANNEL
Port_2_ModbusNodeNumberWriteItem14 D8130 CHANNEL
Port_2_ModbusNodeNumberWriteItem15 D8140 CHANNEL
Port_2_ModbusNodeNumberWriteItem16 D8150 CHANNEL
Port_2_ModbusNodeNumberWriteItem17 D8160 CHANNEL
Port_2_ModbusNodeNumberWriteItem18 D8170 CHANNEL
Port_2_ModbusNodeNumberWriteItem19 D8180 CHANNEL
Port_2_ModbusNodeNumberWriteItem2 D8010 CHANNEL
Port_2_ModbusNodeNumberWriteItem20 D8190 CHANNEL
Port_2_ModbusNodeNumberWriteItem21 D8200 CHANNEL
Port_2_ModbusNodeNumberWriteItem22 D8210 CHANNEL
Port_2_ModbusNodeNumberWriteItem23 D8220 CHANNEL
Port_2_ModbusNodeNumberWriteItem24 D8230 CHANNEL
Port_2_ModbusNodeNumberWriteItem25 D8240 CHANNEL
Port_2_ModbusNodeNumberWriteItem26 D8250 CHANNEL
Port_2_ModbusNodeNumberWriteItem27 D8260 CHANNEL
Port_2_ModbusNodeNumberWriteItem28 D8270 CHANNEL
Port_2_ModbusNodeNumberWriteItem29 D8280 CHANNEL
Port_2_ModbusNodeNumberWriteItem3 D8020 CHANNEL
Port_2_ModbusNodeNumberWriteItem30 D8290 CHANNEL
Port_2_ModbusNodeNumberWriteItem31 D8300 CHANNEL
Port_2_ModbusNodeNumberWriteItem32 D8310 CHANNEL
Port_2_ModbusNodeNumberWriteItem33 D8320 CHANNEL
Port_2_ModbusNodeNumberWriteItem34 D8330 CHANNEL
Port_2_ModbusNodeNumberWriteItem35 D8340 CHANNEL
Port_2_ModbusNodeNumberWriteItem36 D8350 CHANNEL
Port_2_ModbusNodeNumberWriteItem37 D8360 CHANNEL
Port_2_ModbusNodeNumberWriteItem38 D8370 CHANNEL
Port_2_ModbusNodeNumberWriteItem39 D8380 CHANNEL
Port_2_ModbusNodeNumberWriteItem4 D8030 CHANNEL
Port_2_ModbusNodeNumberWriteItem40 D8390 CHANNEL
Port_2_ModbusNodeNumberWriteItem41 D8400 CHANNEL
Port_2_ModbusNodeNumberWriteItem42 D8410 CHANNEL
Port_2_ModbusNodeNumberWriteItem43 D8420 CHANNEL
Port_2_ModbusNodeNumberWriteItem44 D8430 CHANNEL
Port_2_ModbusNodeNumberWriteItem45 D8440 CHANNEL
Port_2_ModbusNodeNumberWriteItem46 D8450 CHANNEL
Port_2_ModbusNodeNumberWriteItem47 D8460 CHANNEL
Port_2_ModbusNodeNumberWriteItem48 D8470 CHANNEL
Port_2_ModbusNodeNumberWriteItem49 D8480 CHANNEL
Port_2_ModbusNodeNumberWriteItem5 D8040 CHANNEL
Port_2_ModbusNodeNumberWriteItem50 D8490 CHANNEL
Port_2_ModbusNodeNumberWriteItem51 D8500 CHANNEL
Port_2_ModbusNodeNumberWriteItem52 D8510 CHANNEL
Port_2_ModbusNodeNumberWriteItem53 D8520 CHANNEL
Port_2_ModbusNodeNumberWriteItem54 D8530 CHANNEL
Port_2_ModbusNodeNumberWriteItem55 D8540 CHANNEL
Port_2_ModbusNodeNumberWriteItem56 D8550 CHANNEL
Port_2_ModbusNodeNumberWriteItem57 D8560 CHANNEL
Port_2_ModbusNodeNumberWriteItem58 D8570 CHANNEL
Port_2_ModbusNodeNumberWriteItem59 D8580 CHANNEL
Port_2_ModbusNodeNumberWriteItem6 D8050 CHANNEL
Port_2_ModbusNodeNumberWriteItem60 D8590 CHANNEL
Port_2_ModbusNodeNumberWriteItem61 D8600 CHANNEL
Port_2_ModbusNodeNumberWriteItem62 D8610 CHANNEL
Port_2_ModbusNodeNumberWriteItem63 D8620 CHANNEL
Port_2_ModbusNodeNumberWriteItem64 D8630 CHANNEL
Port_2_ModbusNodeNumberWriteItem65 D8640 CHANNEL
Port_2_ModbusNodeNumberWriteItem66 D8650 CHANNEL
Port_2_ModbusNodeNumberWriteItem67 D8660 CHANNEL
Port_2_ModbusNodeNumberWriteItem68 D8670 CHANNEL
Port_2_ModbusNodeNumberWriteItem69 D8680 CHANNEL
Port_2_ModbusNodeNumberWriteItem7 D8060 CHANNEL
Port_2_ModbusNodeNumberWriteItem70 D8690 CHANNEL
Port_2_ModbusNodeNumberWriteItem71 D8700 CHANNEL
Port_2_ModbusNodeNumberWriteItem72 D8710 CHANNEL
Port_2_ModbusNodeNumberWriteItem73 D8720 CHANNEL
Port_2_ModbusNodeNumberWriteItem74 D8730 CHANNEL
Port_2_ModbusNodeNumberWriteItem75 D8740 CHANNEL
Port_2_ModbusNodeNumberWriteItem76 D8750 CHANNEL
Port_2_ModbusNodeNumberWriteItem77 D8760 CHANNEL
Port_2_ModbusNodeNumberWriteItem78 D8770 CHANNEL
Port_2_ModbusNodeNumberWriteItem79 D8780 CHANNEL
Port_2_ModbusNodeNumberWriteItem8 D8070 CHANNEL
Port_2_ModbusNodeNumberWriteItem80 D8790 CHANNEL
Port_2_ModbusNodeNumberWriteItem81 D8800 CHANNEL
Port_2_ModbusNodeNumberWriteItem82 D8810 CHANNEL
Port_2_ModbusNodeNumberWriteItem83 D8820 CHANNEL
Port_2_ModbusNodeNumberWriteItem84 D8830 CHANNEL
Port_2_ModbusNodeNumberWriteItem85 D8840 CHANNEL
Port_2_ModbusNodeNumberWriteItem86 D8850 CHANNEL
Port_2_ModbusNodeNumberWriteItem87 D8860 CHANNEL
Port_2_ModbusNodeNumberWriteItem88 D8870 CHANNEL
Port_2_ModbusNodeNumberWriteItem89 D8880 CHANNEL
Port_2_ModbusNodeNumberWriteItem9 D8080 CHANNEL
Port_2_ModbusNodeNumberWriteItem90 D8890 CHANNEL
Port_2_ModbusNodeNumberWriteItem91 D8900 CHANNEL
Port_2_ModbusNodeNumberWriteItem92 D8910 CHANNEL
Port_2_ModbusNodeNumberWriteItem93 D8920 CHANNEL
Port_2_ModbusNodeNumberWriteItem94 D8930 CHANNEL
Port_2_ModbusNodeNumberWriteItem95 D8940 CHANNEL
Port_2_ModbusNodeNumberWriteItem96 D8950 CHANNEL
Port_2_ModbusNodeNumberWriteItem97 D8960 CHANNEL
Port_2_ModbusNodeNumberWriteItem98 D8970 CHANNEL
Port_2_ModbusNodeNumberWriteItem99 D8980 CHANNEL
Port_2_NonResettingTimeoutCounter W459 CHANNEL
Port_2_NotUsed1ReadItem1 D7006 CHANNEL
Port_2_NotUsed1ReadItem10 D7096 CHANNEL
Port_2_NotUsed1ReadItem100 D7996 CHANNEL
Port_2_NotUsed1ReadItem11 D7106 CHANNEL
Port_2_NotUsed1ReadItem12 D7116 CHANNEL
Port_2_NotUsed1ReadItem13 D7126 CHANNEL
Port_2_NotUsed1ReadItem14 D7136 CHANNEL
Port_2_NotUsed1ReadItem15 D7146 CHANNEL
Port_2_NotUsed1ReadItem16 D7156 CHANNEL
Port_2_NotUsed1ReadItem17 D7166 CHANNEL
Port_2_NotUsed1ReadItem18 D7176 CHANNEL
Port_2_NotUsed1ReadItem19 D7186 CHANNEL
Port_2_NotUsed1ReadItem2 D7016 CHANNEL
Port_2_NotUsed1ReadItem20 D7196 CHANNEL
Port_2_NotUsed1ReadItem21 D7206 CHANNEL
Port_2_NotUsed1ReadItem22 D7216 CHANNEL
Port_2_NotUsed1ReadItem23 D7226 CHANNEL
Port_2_NotUsed1ReadItem24 D7236 CHANNEL
Port_2_NotUsed1ReadItem25 D7246 CHANNEL
Port_2_NotUsed1ReadItem26 D7256 CHANNEL
Port_2_NotUsed1ReadItem27 D7266 CHANNEL
Port_2_NotUsed1ReadItem28 D7276 CHANNEL
Port_2_NotUsed1ReadItem29 D7286 CHANNEL
Port_2_NotUsed1ReadItem3 D7026 CHANNEL
Port_2_NotUsed1ReadItem30 D7296 CHANNEL
Port_2_NotUsed1ReadItem31 D7306 CHANNEL
Port_2_NotUsed1ReadItem32 D7316 CHANNEL
Port_2_NotUsed1ReadItem33 D7326 CHANNEL
Port_2_NotUsed1ReadItem34 D7336 CHANNEL
Port_2_NotUsed1ReadItem35 D7346 CHANNEL
Port_2_NotUsed1ReadItem36 D7356 CHANNEL
Port_2_NotUsed1ReadItem37 D7366 CHANNEL
Port_2_NotUsed1ReadItem38 D7376 CHANNEL
Port_2_NotUsed1ReadItem39 D7386 CHANNEL
Port_2_NotUsed1ReadItem4 D7036 CHANNEL
Port_2_NotUsed1ReadItem40 D7396 CHANNEL
Port_2_NotUsed1ReadItem41 D7406 CHANNEL
Port_2_NotUsed1ReadItem42 D7416 CHANNEL
Port_2_NotUsed1ReadItem43 D7426 CHANNEL
Port_2_NotUsed1ReadItem44 D7436 CHANNEL
Port_2_NotUsed1ReadItem45 D7446 CHANNEL
Port_2_NotUsed1ReadItem46 D7456 CHANNEL
Port_2_NotUsed1ReadItem47 D7466 CHANNEL
Port_2_NotUsed1ReadItem48 D7476 CHANNEL
Port_2_NotUsed1ReadItem49 D7486 CHANNEL
Port_2_NotUsed1ReadItem5 D7046 CHANNEL
Port_2_NotUsed1ReadItem50 D7496 CHANNEL
Port_2_NotUsed1ReadItem51 D7506 CHANNEL
Port_2_NotUsed1ReadItem52 D7516 CHANNEL
Port_2_NotUsed1ReadItem53 D7526 CHANNEL
Port_2_NotUsed1ReadItem54 D7536 CHANNEL
Port_2_NotUsed1ReadItem55 D7546 CHANNEL
Port_2_NotUsed1ReadItem56 D7556 CHANNEL
Port_2_NotUsed1ReadItem57 D7566 CHANNEL
Port_2_NotUsed1ReadItem58 D7576 CHANNEL
Port_2_NotUsed1ReadItem59 D7586 CHANNEL
Port_2_NotUsed1ReadItem6 D7056 CHANNEL
Port_2_NotUsed1ReadItem60 D7596 CHANNEL
Port_2_NotUsed1ReadItem61 D7606 CHANNEL
Port_2_NotUsed1ReadItem62 D7616 CHANNEL
Port_2_NotUsed1ReadItem63 D7626 CHANNEL
Port_2_NotUsed1ReadItem64 D7636 CHANNEL
Port_2_NotUsed1ReadItem65 D7646 CHANNEL
Port_2_NotUsed1ReadItem66 D7656 CHANNEL
Port_2_NotUsed1ReadItem67 D7666 CHANNEL
Port_2_NotUsed1ReadItem68 D7676 CHANNEL
Port_2_NotUsed1ReadItem69 D7686 CHANNEL
Port_2_NotUsed1ReadItem7 D7066 CHANNEL
Port_2_NotUsed1ReadItem70 D7696 CHANNEL
Port_2_NotUsed1ReadItem71 D7706 CHANNEL
Port_2_NotUsed1ReadItem72 D7716 CHANNEL
Port_2_NotUsed1ReadItem73 D7726 CHANNEL
Port_2_NotUsed1ReadItem74 D7736 CHANNEL
Port_2_NotUsed1ReadItem75 D7746 CHANNEL
Port_2_NotUsed1ReadItem76 D7756 CHANNEL
Port_2_NotUsed1ReadItem77 D7766 CHANNEL
Port_2_NotUsed1ReadItem78 D7776 CHANNEL
Port_2_NotUsed1ReadItem79 D7786 CHANNEL
Port_2_NotUsed1ReadItem8 D7076 CHANNEL
Port_2_NotUsed1ReadItem80 D7796 CHANNEL
Port_2_NotUsed1ReadItem81 D7806 CHANNEL
Port_2_NotUsed1ReadItem82 D7816 CHANNEL
Port_2_NotUsed1ReadItem83 D7826 CHANNEL
Port_2_NotUsed1ReadItem84 D7836 CHANNEL
Port_2_NotUsed1ReadItem85 D7846 CHANNEL
Port_2_NotUsed1ReadItem86 D7856 CHANNEL
Port_2_NotUsed1ReadItem87 D7866 CHANNEL
Port_2_NotUsed1ReadItem88 D7876 CHANNEL
Port_2_NotUsed1ReadItem89 D7886 CHANNEL
Port_2_NotUsed1ReadItem9 D7086 CHANNEL
Port_2_NotUsed1ReadItem90 D7896 CHANNEL
Port_2_NotUsed1ReadItem91 D7906 CHANNEL
Port_2_NotUsed1ReadItem92 D7916 CHANNEL
Port_2_NotUsed1ReadItem93 D7926 CHANNEL
Port_2_NotUsed1ReadItem94 D7936 CHANNEL
Port_2_NotUsed1ReadItem95 D7946 CHANNEL
Port_2_NotUsed1ReadItem96 D7956 CHANNEL
Port_2_NotUsed1ReadItem97 D7966 CHANNEL
Port_2_NotUsed1ReadItem98 D7976 CHANNEL
Port_2_NotUsed1ReadItem99 D7986 CHANNEL
Port_2_NotUsed2ReadItem1 D7007 CHANNEL
Port_2_NotUsed2ReadItem10 D7097 CHANNEL
Port_2_NotUsed2ReadItem100 D7997 CHANNEL
Port_2_NotUsed2ReadItem11 D7107 CHANNEL
Port_2_NotUsed2ReadItem12 D7117 CHANNEL
Port_2_NotUsed2ReadItem13 D7127 CHANNEL
Port_2_NotUsed2ReadItem14 D7137 CHANNEL
Port_2_NotUsed2ReadItem15 D7147 CHANNEL
Port_2_NotUsed2ReadItem16 D7157 CHANNEL
Port_2_NotUsed2ReadItem17 D7167 CHANNEL
Port_2_NotUsed2ReadItem18 D7177 CHANNEL
Port_2_NotUsed2ReadItem19 D7187 CHANNEL
Port_2_NotUsed2ReadItem2 D7017 CHANNEL
Port_2_NotUsed2ReadItem20 D7197 CHANNEL
Port_2_NotUsed2ReadItem21 D7207 CHANNEL
Port_2_NotUsed2ReadItem22 D7217 CHANNEL
Port_2_NotUsed2ReadItem23 D7227 CHANNEL
Port_2_NotUsed2ReadItem24 D7237 CHANNEL
Port_2_NotUsed2ReadItem25 D7247 CHANNEL
Port_2_NotUsed2ReadItem26 D7257 CHANNEL
Port_2_NotUsed2ReadItem27 D7267 CHANNEL
Port_2_NotUsed2ReadItem28 D7277 CHANNEL
Port_2_NotUsed2ReadItem29 D7287 CHANNEL
Port_2_NotUsed2ReadItem3 D7027 CHANNEL
Port_2_NotUsed2ReadItem30 D7297 CHANNEL
Port_2_NotUsed2ReadItem31 D7307 CHANNEL
Port_2_NotUsed2ReadItem32 D7317 CHANNEL
Port_2_NotUsed2ReadItem33 D7327 CHANNEL
Port_2_NotUsed2ReadItem34 D7337 CHANNEL
Port_2_NotUsed2ReadItem35 D7347 CHANNEL
Port_2_NotUsed2ReadItem36 D7357 CHANNEL
Port_2_NotUsed2ReadItem37 D7367 CHANNEL
Port_2_NotUsed2ReadItem38 D7377 CHANNEL
Port_2_NotUsed2ReadItem39 D7387 CHANNEL
Port_2_NotUsed2ReadItem4 D7037 CHANNEL
Port_2_NotUsed2ReadItem40 D7397 CHANNEL
Port_2_NotUsed2ReadItem41 D7407 CHANNEL
Port_2_NotUsed2ReadItem42 D7417 CHANNEL
Port_2_NotUsed2ReadItem43 D7427 CHANNEL
Port_2_NotUsed2ReadItem44 D7437 CHANNEL
Port_2_NotUsed2ReadItem45 D7447 CHANNEL
Port_2_NotUsed2ReadItem46 D7457 CHANNEL
Port_2_NotUsed2ReadItem47 D7467 CHANNEL
Port_2_NotUsed2ReadItem48 D7477 CHANNEL
Port_2_NotUsed2ReadItem49 D7487 CHANNEL
Port_2_NotUsed2ReadItem5 D7047 CHANNEL
Port_2_NotUsed2ReadItem50 D7497 CHANNEL
Port_2_NotUsed2ReadItem51 D7507 CHANNEL
Port_2_NotUsed2ReadItem52 D7517 CHANNEL
Port_2_NotUsed2ReadItem53 D7527 CHANNEL
Port_2_NotUsed2ReadItem54 D7537 CHANNEL
Port_2_NotUsed2ReadItem55 D7547 CHANNEL
Port_2_NotUsed2ReadItem56 D7557 CHANNEL
Port_2_NotUsed2ReadItem57 D7567 CHANNEL
Port_2_NotUsed2ReadItem58 D7577 CHANNEL
Port_2_NotUsed2ReadItem59 D7587 CHANNEL
Port_2_NotUsed2ReadItem6 D7057 CHANNEL
Port_2_NotUsed2ReadItem60 D7597 CHANNEL
Port_2_NotUsed2ReadItem61 D7607 CHANNEL
Port_2_NotUsed2ReadItem62 D7617 CHANNEL
Port_2_NotUsed2ReadItem63 D7627 CHANNEL
Port_2_NotUsed2ReadItem64 D7637 CHANNEL
Port_2_NotUsed2ReadItem65 D7647 CHANNEL
Port_2_NotUsed2ReadItem66 D7657 CHANNEL
Port_2_NotUsed2ReadItem67 D7667 CHANNEL
Port_2_NotUsed2ReadItem68 D7677 CHANNEL
Port_2_NotUsed2ReadItem69 D7687 CHANNEL
Port_2_NotUsed2ReadItem7 D7067 CHANNEL
Port_2_NotUsed2ReadItem70 D7697 CHANNEL
Port_2_NotUsed2ReadItem71 D7707 CHANNEL
Port_2_NotUsed2ReadItem72 D7717 CHANNEL
Port_2_NotUsed2ReadItem73 D7727 CHANNEL
Port_2_NotUsed2ReadItem74 D7737 CHANNEL
Port_2_NotUsed2ReadItem75 D7747 CHANNEL
Port_2_NotUsed2ReadItem76 D7757 CHANNEL
Port_2_NotUsed2ReadItem77 D7767 CHANNEL
Port_2_NotUsed2ReadItem78 D7777 CHANNEL
Port_2_NotUsed2ReadItem79 D7787 CHANNEL
Port_2_NotUsed2ReadItem8 D7077 CHANNEL
Port_2_NotUsed2ReadItem80 D7797 CHANNEL
Port_2_NotUsed2ReadItem81 D7807 CHANNEL
Port_2_NotUsed2ReadItem82 D7817 CHANNEL
Port_2_NotUsed2ReadItem83 D7827 CHANNEL
Port_2_NotUsed2ReadItem84 D7837 CHANNEL
Port_2_NotUsed2ReadItem85 D7847 CHANNEL
Port_2_NotUsed2ReadItem86 D7857 CHANNEL
Port_2_NotUsed2ReadItem87 D7867 CHANNEL
Port_2_NotUsed2ReadItem88 D7877 CHANNEL
Port_2_NotUsed2ReadItem89 D7887 CHANNEL
Port_2_NotUsed2ReadItem9 D7087 CHANNEL
Port_2_NotUsed2ReadItem90 D7897 CHANNEL
Port_2_NotUsed2ReadItem91 D7907 CHANNEL
Port_2_NotUsed2ReadItem92 D7917 CHANNEL
Port_2_NotUsed2ReadItem93 D7927 CHANNEL
Port_2_NotUsed2ReadItem94 D7937 CHANNEL
Port_2_NotUsed2ReadItem95 D7947 CHANNEL
Port_2_NotUsed2ReadItem96 D7957 CHANNEL
Port_2_NotUsed2ReadItem97 D7967 CHANNEL
Port_2_NotUsed2ReadItem98 D7977 CHANNEL
Port_2_NotUsed2ReadItem99 D7987 CHANNEL
Port_2_NumberOfItemsToReadReadItem1 D7003 CHANNEL
Port_2_NumberOfItemsToReadReadItem10 D7093 CHANNEL
Port_2_NumberOfItemsToReadReadItem100 D7993 CHANNEL
Port_2_NumberOfItemsToReadReadItem11 D7103 CHANNEL
Port_2_NumberOfItemsToReadReadItem12 D7113 CHANNEL
Port_2_NumberOfItemsToReadReadItem13 D7123 CHANNEL
Port_2_NumberOfItemsToReadReadItem14 D7133 CHANNEL
Port_2_NumberOfItemsToReadReadItem15 D7143 CHANNEL
Port_2_NumberOfItemsToReadReadItem16 D7153 CHANNEL
Port_2_NumberOfItemsToReadReadItem17 D7163 CHANNEL
Port_2_NumberOfItemsToReadReadItem18 D7173 CHANNEL
Port_2_NumberOfItemsToReadReadItem19 D7183 CHANNEL
Port_2_NumberOfItemsToReadReadItem2 D7013 CHANNEL
Port_2_NumberOfItemsToReadReadItem20 D7193 CHANNEL
Port_2_NumberOfItemsToReadReadItem21 D7203 CHANNEL
Port_2_NumberOfItemsToReadReadItem22 D7213 CHANNEL
Port_2_NumberOfItemsToReadReadItem23 D7223 CHANNEL
Port_2_NumberOfItemsToReadReadItem24 D7233 CHANNEL
Port_2_NumberOfItemsToReadReadItem25 D7243 CHANNEL
Port_2_NumberOfItemsToReadReadItem26 D7253 CHANNEL
Port_2_NumberOfItemsToReadReadItem27 D7263 CHANNEL
Port_2_NumberOfItemsToReadReadItem28 D7273 CHANNEL
Port_2_NumberOfItemsToReadReadItem29 D7283 CHANNEL
Port_2_NumberOfItemsToReadReadItem3 D7023 CHANNEL
Port_2_NumberOfItemsToReadReadItem30 D7293 CHANNEL
Port_2_NumberOfItemsToReadReadItem31 D7303 CHANNEL
Port_2_NumberOfItemsToReadReadItem32 D7313 CHANNEL
Port_2_NumberOfItemsToReadReadItem33 D7323 CHANNEL
Port_2_NumberOfItemsToReadReadItem34 D7333 CHANNEL
Port_2_NumberOfItemsToReadReadItem35 D7343 CHANNEL
Port_2_NumberOfItemsToReadReadItem36 D7353 CHANNEL
Port_2_NumberOfItemsToReadReadItem37 D7363 CHANNEL
Port_2_NumberOfItemsToReadReadItem38 D7373 CHANNEL
Port_2_NumberOfItemsToReadReadItem39 D7383 CHANNEL
Port_2_NumberOfItemsToReadReadItem4 D7033 CHANNEL
Port_2_NumberOfItemsToReadReadItem40 D7393 CHANNEL
Port_2_NumberOfItemsToReadReadItem41 D7403 CHANNEL
Port_2_NumberOfItemsToReadReadItem42 D7413 CHANNEL
Port_2_NumberOfItemsToReadReadItem43 D7423 CHANNEL
Port_2_NumberOfItemsToReadReadItem44 D7433 CHANNEL
Port_2_NumberOfItemsToReadReadItem45 D7443 CHANNEL
Port_2_NumberOfItemsToReadReadItem46 D7453 CHANNEL
Port_2_NumberOfItemsToReadReadItem47 D7463 CHANNEL
Port_2_NumberOfItemsToReadReadItem48 D7473 CHANNEL
Port_2_NumberOfItemsToReadReadItem49 D7483 CHANNEL
Port_2_NumberOfItemsToReadReadItem5 D7043 CHANNEL
Port_2_NumberOfItemsToReadReadItem50 D7493 CHANNEL
Port_2_NumberOfItemsToReadReadItem51 D7503 CHANNEL
Port_2_NumberOfItemsToReadReadItem52 D7513 CHANNEL
Port_2_NumberOfItemsToReadReadItem53 D7523 CHANNEL
Port_2_NumberOfItemsToReadReadItem54 D7533 CHANNEL
Port_2_NumberOfItemsToReadReadItem55 D7543 CHANNEL
Port_2_NumberOfItemsToReadReadItem56 D7553 CHANNEL
Port_2_NumberOfItemsToReadReadItem57 D7563 CHANNEL
Port_2_NumberOfItemsToReadReadItem58 D7573 CHANNEL
Port_2_NumberOfItemsToReadReadItem59 D7583 CHANNEL
Port_2_NumberOfItemsToReadReadItem6 D7053 CHANNEL
Port_2_NumberOfItemsToReadReadItem60 D7593 CHANNEL
Port_2_NumberOfItemsToReadReadItem61 D7603 CHANNEL
Port_2_NumberOfItemsToReadReadItem62 D7613 CHANNEL
Port_2_NumberOfItemsToReadReadItem63 D7623 CHANNEL
Port_2_NumberOfItemsToReadReadItem64 D7633 CHANNEL
Port_2_NumberOfItemsToReadReadItem65 D7643 CHANNEL
Port_2_NumberOfItemsToReadReadItem66 D7653 CHANNEL
Port_2_NumberOfItemsToReadReadItem67 D7663 CHANNEL
Port_2_NumberOfItemsToReadReadItem68 D7673 CHANNEL
Port_2_NumberOfItemsToReadReadItem69 D7683 CHANNEL
Port_2_NumberOfItemsToReadReadItem7 D7063 CHANNEL
Port_2_NumberOfItemsToReadReadItem70 D7693 CHANNEL
Port_2_NumberOfItemsToReadReadItem71 D7703 CHANNEL
Port_2_NumberOfItemsToReadReadItem72 D7713 CHANNEL
Port_2_NumberOfItemsToReadReadItem73 D7723 CHANNEL
Port_2_NumberOfItemsToReadReadItem74 D7733 CHANNEL
Port_2_NumberOfItemsToReadReadItem75 D7743 CHANNEL
Port_2_NumberOfItemsToReadReadItem76 D7753 CHANNEL
Port_2_NumberOfItemsToReadReadItem77 D7763 CHANNEL
Port_2_NumberOfItemsToReadReadItem78 D7773 CHANNEL
Port_2_NumberOfItemsToReadReadItem79 D7783 CHANNEL
Port_2_NumberOfItemsToReadReadItem8 D7073 CHANNEL
Port_2_NumberOfItemsToReadReadItem80 D7793 CHANNEL
Port_2_NumberOfItemsToReadReadItem81 D7803 CHANNEL
Port_2_NumberOfItemsToReadReadItem82 D7813 CHANNEL
Port_2_NumberOfItemsToReadReadItem83 D7823 CHANNEL
Port_2_NumberOfItemsToReadReadItem84 D7833 CHANNEL
Port_2_NumberOfItemsToReadReadItem85 D7843 CHANNEL
Port_2_NumberOfItemsToReadReadItem86 D7853 CHANNEL
Port_2_NumberOfItemsToReadReadItem87 D7863 CHANNEL
Port_2_NumberOfItemsToReadReadItem88 D7873 CHANNEL
Port_2_NumberOfItemsToReadReadItem89 D7883 CHANNEL
Port_2_NumberOfItemsToReadReadItem9 D7083 CHANNEL
Port_2_NumberOfItemsToReadReadItem90 D7893 CHANNEL
Port_2_NumberOfItemsToReadReadItem91 D7903 CHANNEL
Port_2_NumberOfItemsToReadReadItem92 D7913 CHANNEL
Port_2_NumberOfItemsToReadReadItem93 D7923 CHANNEL
Port_2_NumberOfItemsToReadReadItem94 D7933 CHANNEL
Port_2_NumberOfItemsToReadReadItem95 D7943 CHANNEL
Port_2_NumberOfItemsToReadReadItem96 D7953 CHANNEL
Port_2_NumberOfItemsToReadReadItem97 D7963 CHANNEL
Port_2_NumberOfItemsToReadReadItem98 D7973 CHANNEL
Port_2_NumberOfItemsToReadReadItem99 D7983 CHANNEL
Port_2_NumberOfItemsToWriteWriteItem1 D8003 CHANNEL
Port_2_NumberOfItemsToWriteWriteItem10 D8093 CHANNEL
Port_2_NumberOfItemsToWriteWriteItem100 D8993 CHANNEL
Port_2_NumberOfItemsToWriteWriteItem11 D8103 CHANNEL
Port_2_NumberOfItemsToWriteWriteItem12 D8113 CHANNEL
Port_2_NumberOfItemsToWriteWriteItem13 D8123 CHANNEL
Port_2_NumberOfItemsToWriteWriteItem14 D8133 CHANNEL
Port_2_NumberOfItemsToWriteWriteItem15 D8143 CHANNEL
Port_2_NumberOfItemsToWriteWriteItem16 D8153 CHANNEL
Port_2_NumberOfItemsToWriteWriteItem17 D8163 CHANNEL
Port_2_NumberOfItemsToWriteWriteItem18 D8173 CHANNEL
Port_2_NumberOfItemsToWriteWriteItem19 D8183 CHANNEL
Port_2_NumberOfItemsToWriteWriteItem2 D8013 CHANNEL
Port_2_NumberOfItemsToWriteWriteItem20 D8193 CHANNEL
Port_2_NumberOfItemsToWriteWriteItem21 D8203 CHANNEL
Port_2_NumberOfItemsToWriteWriteItem22 D8213 CHANNEL
Port_2_NumberOfItemsToWriteWriteItem23 D8223 CHANNEL
Port_2_NumberOfItemsToWriteWriteItem24 D8233 CHANNEL
Port_2_NumberOfItemsToWriteWriteItem25 D8243 CHANNEL
Port_2_NumberOfItemsToWriteWriteItem26 D8253 CHANNEL
Port_2_NumberOfItemsToWriteWriteItem27 D8263 CHANNEL
Port_2_NumberOfItemsToWriteWriteItem28 D8273 CHANNEL
Port_2_NumberOfItemsToWriteWriteItem29 D8283 CHANNEL
Port_2_NumberOfItemsToWriteWriteItem3 D8023 CHANNEL
Port_2_NumberOfItemsToWriteWriteItem30 D8293 CHANNEL
Port_2_NumberOfItemsToWriteWriteItem31 D8303 CHANNEL
Port_2_NumberOfItemsToWriteWriteItem32 D8313 CHANNEL
Port_2_NumberOfItemsToWriteWriteItem33 D8323 CHANNEL
Port_2_NumberOfItemsToWriteWriteItem34 D8333 CHANNEL
Port_2_NumberOfItemsToWriteWriteItem35 D8343 CHANNEL
Port_2_NumberOfItemsToWriteWriteItem36 D8353 CHANNEL
Port_2_NumberOfItemsToWriteWriteItem37 D8363 CHANNEL
Port_2_NumberOfItemsToWriteWriteItem38 D8373 CHANNEL
Port_2_NumberOfItemsToWriteWriteItem39 D8383 CHANNEL
Port_2_NumberOfItemsToWriteWriteItem4 D8033 CHANNEL
Port_2_NumberOfItemsToWriteWriteItem40 D8393 CHANNEL
Port_2_NumberOfItemsToWriteWriteItem41 D8403 CHANNEL
Port_2_NumberOfItemsToWriteWriteItem42 D8413 CHANNEL
Port_2_NumberOfItemsToWriteWriteItem43 D8423 CHANNEL
Port_2_NumberOfItemsToWriteWriteItem44 D8433 CHANNEL
Port_2_NumberOfItemsToWriteWriteItem45 D8443 CHANNEL
Port_2_NumberOfItemsToWriteWriteItem46 D8453 CHANNEL
Port_2_NumberOfItemsToWriteWriteItem47 D8463 CHANNEL
Port_2_NumberOfItemsToWriteWriteItem48 D8473 CHANNEL
Port_2_NumberOfItemsToWriteWriteItem49 D8483 CHANNEL
Port_2_NumberOfItemsToWriteWriteItem5 D8043 CHANNEL
Port_2_NumberOfItemsToWriteWriteItem50 D8493 CHANNEL
Port_2_NumberOfItemsToWriteWriteItem51 D8503 CHANNEL
Port_2_NumberOfItemsToWriteWriteItem52 D8513 CHANNEL
Port_2_NumberOfItemsToWriteWriteItem53 D8523 CHANNEL
Port_2_NumberOfItemsToWriteWriteItem54 D8533 CHANNEL
Port_2_NumberOfItemsToWriteWriteItem55 D8543 CHANNEL
Port_2_NumberOfItemsToWriteWriteItem56 D8553 CHANNEL
Port_2_NumberOfItemsToWriteWriteItem57 D8563 CHANNEL
Port_2_NumberOfItemsToWriteWriteItem58 D8573 CHANNEL
Port_2_NumberOfItemsToWriteWriteItem59 D8583 CHANNEL
Port_2_NumberOfItemsToWriteWriteItem6 D8053 CHANNEL
Port_2_NumberOfItemsToWriteWriteItem60 D8593 CHANNEL
Port_2_NumberOfItemsToWriteWriteItem61 D8603 CHANNEL
Port_2_NumberOfItemsToWriteWriteItem62 D8613 CHANNEL
Port_2_NumberOfItemsToWriteWriteItem63 D8623 CHANNEL
Port_2_NumberOfItemsToWriteWriteItem64 D8633 CHANNEL
Port_2_NumberOfItemsToWriteWriteItem65 D8643 CHANNEL
Port_2_NumberOfItemsToWriteWriteItem66 D8653 CHANNEL
Port_2_NumberOfItemsToWriteWriteItem67 D8663 CHANNEL
Port_2_NumberOfItemsToWriteWriteItem68 D8673 CHANNEL
Port_2_NumberOfItemsToWriteWriteItem69 D8683 CHANNEL
Port_2_NumberOfItemsToWriteWriteItem7 D8063 CHANNEL
Port_2_NumberOfItemsToWriteWriteItem70 D8693 CHANNEL
Port_2_NumberOfItemsToWriteWriteItem71 D8703 CHANNEL
Port_2_NumberOfItemsToWriteWriteItem72 D8713 CHANNEL
Port_2_NumberOfItemsToWriteWriteItem73 D8723 CHANNEL
Port_2_NumberOfItemsToWriteWriteItem74 D8733 CHANNEL
Port_2_NumberOfItemsToWriteWriteItem75 D8743 CHANNEL
Port_2_NumberOfItemsToWriteWriteItem76 D8753 CHANNEL
Port_2_NumberOfItemsToWriteWriteItem77 D8763 CHANNEL
Port_2_NumberOfItemsToWriteWriteItem78 D8773 CHANNEL
Port_2_NumberOfItemsToWriteWriteItem79 D8783 CHANNEL
Port_2_NumberOfItemsToWriteWriteItem8 D8073 CHANNEL
Port_2_NumberOfItemsToWriteWriteItem80 D8793 CHANNEL
Port_2_NumberOfItemsToWriteWriteItem81 D8803 CHANNEL
Port_2_NumberOfItemsToWriteWriteItem82 D8813 CHANNEL
Port_2_NumberOfItemsToWriteWriteItem83 D8823 CHANNEL
Port_2_NumberOfItemsToWriteWriteItem84 D8833 CHANNEL
Port_2_NumberOfItemsToWriteWriteItem85 D8843 CHANNEL
Port_2_NumberOfItemsToWriteWriteItem86 D8853 CHANNEL
Port_2_NumberOfItemsToWriteWriteItem87 D8863 CHANNEL
Port_2_NumberOfItemsToWriteWriteItem88 D8873 CHANNEL
Port_2_NumberOfItemsToWriteWriteItem89 D8883 CHANNEL
Port_2_NumberOfItemsToWriteWriteItem9 D8083 CHANNEL
Port_2_NumberOfItemsToWriteWriteItem90 D8893 CHANNEL
Port_2_NumberOfItemsToWriteWriteItem91 D8903 CHANNEL
Port_2_NumberOfItemsToWriteWriteItem92 D8913 CHANNEL
Port_2_NumberOfItemsToWriteWriteItem93 D8923 CHANNEL
Port_2_NumberOfItemsToWriteWriteItem94 D8933 CHANNEL
Port_2_NumberOfItemsToWriteWriteItem95 D8943 CHANNEL
Port_2_NumberOfItemsToWriteWriteItem96 D8953 CHANNEL
Port_2_NumberOfItemsToWriteWriteItem97 D8963 CHANNEL
Port_2_NumberOfItemsToWriteWriteItem98 D8973 CHANNEL
Port_2_NumberOfItemsToWriteWriteItem99 D8983 CHANNEL
Port_2_PMCR_Busy 1894.15 BOOL
Port_2_PMCR_Complete_NG 1894.10 BOOL
Port_2_PMCR_Complete_OK 1894.11 BOOL
Port_2_Polling_Has_Occurred W465.02 BOOL
Port_2_Port_Needs_To_Be_Reset W455.02 BOOL
Port_2_Port_Now_Resetting W455.03 BOOL
Port_2_ReadValidOrInvalidReadItem1 D7008 CHANNEL
Port_2_ReadValidOrInvalidReadItem10 D7098 CHANNEL
Port_2_ReadValidOrInvalidReadItem100 D7998 CHANNEL
Port_2_ReadValidOrInvalidReadItem11 D7108 CHANNEL
Port_2_ReadValidOrInvalidReadItem12 D7118 CHANNEL
Port_2_ReadValidOrInvalidReadItem13 D7128 CHANNEL
Port_2_ReadValidOrInvalidReadItem14 D7138 CHANNEL
Port_2_ReadValidOrInvalidReadItem15 D7148 CHANNEL
Port_2_ReadValidOrInvalidReadItem16 D7158 CHANNEL
Port_2_ReadValidOrInvalidReadItem17 D7168 CHANNEL
Port_2_ReadValidOrInvalidReadItem18 D7178 CHANNEL
Port_2_ReadValidOrInvalidReadItem19 D7188 CHANNEL
Port_2_ReadValidOrInvalidReadItem2 D7018 CHANNEL
Port_2_ReadValidOrInvalidReadItem20 D7198 CHANNEL
Port_2_ReadValidOrInvalidReadItem21 D7208 CHANNEL
Port_2_ReadValidOrInvalidReadItem22 D7218 CHANNEL
Port_2_ReadValidOrInvalidReadItem23 D7228 CHANNEL
Port_2_ReadValidOrInvalidReadItem24 D7238 CHANNEL
Port_2_ReadValidOrInvalidReadItem25 D7248 CHANNEL
Port_2_ReadValidOrInvalidReadItem26 D7258 CHANNEL
Port_2_ReadValidOrInvalidReadItem27 D7268 CHANNEL
Port_2_ReadValidOrInvalidReadItem28 D7278 CHANNEL
Port_2_ReadValidOrInvalidReadItem29 D7288 CHANNEL
Port_2_ReadValidOrInvalidReadItem3 D7028 CHANNEL
Port_2_ReadValidOrInvalidReadItem30 D7298 CHANNEL
Port_2_ReadValidOrInvalidReadItem31 D7308 CHANNEL
Port_2_ReadValidOrInvalidReadItem32 D7318 CHANNEL
Port_2_ReadValidOrInvalidReadItem33 D7328 CHANNEL
Port_2_ReadValidOrInvalidReadItem34 D7338 CHANNEL
Port_2_ReadValidOrInvalidReadItem35 D7348 CHANNEL
Port_2_ReadValidOrInvalidReadItem36 D7358 CHANNEL
Port_2_ReadValidOrInvalidReadItem37 D7368 CHANNEL
Port_2_ReadValidOrInvalidReadItem38 D7378 CHANNEL
Port_2_ReadValidOrInvalidReadItem39 D7388 CHANNEL
Port_2_ReadValidOrInvalidReadItem4 D7038 CHANNEL
Port_2_ReadValidOrInvalidReadItem40 D7398 CHANNEL
Port_2_ReadValidOrInvalidReadItem41 D7408 CHANNEL
Port_2_ReadValidOrInvalidReadItem42 D7418 CHANNEL
Port_2_ReadValidOrInvalidReadItem43 D7428 CHANNEL
Port_2_ReadValidOrInvalidReadItem44 D7438 CHANNEL
Port_2_ReadValidOrInvalidReadItem45 D7448 CHANNEL
Port_2_ReadValidOrInvalidReadItem46 D7458 CHANNEL
Port_2_ReadValidOrInvalidReadItem47 D7468 CHANNEL
Port_2_ReadValidOrInvalidReadItem48 D7478 CHANNEL
Port_2_ReadValidOrInvalidReadItem49 D7488 CHANNEL
Port_2_ReadValidOrInvalidReadItem5 D7048 CHANNEL
Port_2_ReadValidOrInvalidReadItem50 D7498 CHANNEL
Port_2_ReadValidOrInvalidReadItem51 D7508 CHANNEL
Port_2_ReadValidOrInvalidReadItem52 D7518 CHANNEL
Port_2_ReadValidOrInvalidReadItem53 D7528 CHANNEL
Port_2_ReadValidOrInvalidReadItem54 D7538 CHANNEL
Port_2_ReadValidOrInvalidReadItem55 D7548 CHANNEL
Port_2_ReadValidOrInvalidReadItem56 D7558 CHANNEL
Port_2_ReadValidOrInvalidReadItem57 D7568 CHANNEL
Port_2_ReadValidOrInvalidReadItem58 D7578 CHANNEL
Port_2_ReadValidOrInvalidReadItem59 D7588 CHANNEL
Port_2_ReadValidOrInvalidReadItem6 D7058 CHANNEL
Port_2_ReadValidOrInvalidReadItem60 D7598 CHANNEL
Port_2_ReadValidOrInvalidReadItem61 D7608 CHANNEL
Port_2_ReadValidOrInvalidReadItem62 D7618 CHANNEL
Port_2_ReadValidOrInvalidReadItem63 D7628 CHANNEL
Port_2_ReadValidOrInvalidReadItem64 D7638 CHANNEL
Port_2_ReadValidOrInvalidReadItem65 D7648 CHANNEL
Port_2_ReadValidOrInvalidReadItem66 D7658 CHANNEL
Port_2_ReadValidOrInvalidReadItem67 D7668 CHANNEL
Port_2_ReadValidOrInvalidReadItem68 D7678 CHANNEL
Port_2_ReadValidOrInvalidReadItem69 D7688 CHANNEL
Port_2_ReadValidOrInvalidReadItem7 D7068 CHANNEL
Port_2_ReadValidOrInvalidReadItem70 D7698 CHANNEL
Port_2_ReadValidOrInvalidReadItem71 D7708 CHANNEL
Port_2_ReadValidOrInvalidReadItem72 D7718 CHANNEL
Port_2_ReadValidOrInvalidReadItem73 D7728 CHANNEL
Port_2_ReadValidOrInvalidReadItem74 D7738 CHANNEL
Port_2_ReadValidOrInvalidReadItem75 D7748 CHANNEL
Port_2_ReadValidOrInvalidReadItem76 D7758 CHANNEL
Port_2_ReadValidOrInvalidReadItem77 D7768 CHANNEL
Port_2_ReadValidOrInvalidReadItem78 D7778 CHANNEL
Port_2_ReadValidOrInvalidReadItem79 D7788 CHANNEL
Port_2_ReadValidOrInvalidReadItem8 D7078 CHANNEL
Port_2_ReadValidOrInvalidReadItem80 D7798 CHANNEL
Port_2_ReadValidOrInvalidReadItem81 D7808 CHANNEL
Port_2_ReadValidOrInvalidReadItem82 D7818 CHANNEL
Port_2_ReadValidOrInvalidReadItem83 D7828 CHANNEL
Port_2_ReadValidOrInvalidReadItem84 D7838 CHANNEL
Port_2_ReadValidOrInvalidReadItem85 D7848 CHANNEL
Port_2_ReadValidOrInvalidReadItem86 D7858 CHANNEL
Port_2_ReadValidOrInvalidReadItem87 D7868 CHANNEL
Port_2_ReadValidOrInvalidReadItem88 D7878 CHANNEL
Port_2_ReadValidOrInvalidReadItem89 D7888 CHANNEL
Port_2_ReadValidOrInvalidReadItem9 D7088 CHANNEL
Port_2_ReadValidOrInvalidReadItem90 D7898 CHANNEL
Port_2_ReadValidOrInvalidReadItem91 D7908 CHANNEL
Port_2_ReadValidOrInvalidReadItem92 D7918 CHANNEL
Port_2_ReadValidOrInvalidReadItem93 D7928 CHANNEL
Port_2_ReadValidOrInvalidReadItem94 D7938 CHANNEL
Port_2_ReadValidOrInvalidReadItem95 D7948 CHANNEL
Port_2_ReadValidOrInvalidReadItem96 D7958 CHANNEL
Port_2_ReadValidOrInvalidReadItem97 D7968 CHANNEL
Port_2_ReadValidOrInvalidReadItem98 D7978 CHANNEL
Port_2_ReadValidOrInvalidReadItem99 D7988 CHANNEL
Port_2_Retry_Send_Delay W455.01 BOOL
Port_2_SecondWordResponseDataReadItem1 D7005 CHANNEL
Port_2_SecondWordResponseDataReadItem10 D7095 CHANNEL
Port_2_SecondWordResponseDataReadItem100 D7995 CHANNEL
Port_2_SecondWordResponseDataReadItem11 D7105 CHANNEL
Port_2_SecondWordResponseDataReadItem12 D7115 CHANNEL
Port_2_SecondWordResponseDataReadItem13 D7125 CHANNEL
Port_2_SecondWordResponseDataReadItem14 D7135 CHANNEL
Port_2_SecondWordResponseDataReadItem15 D7145 CHANNEL
Port_2_SecondWordResponseDataReadItem16 D7155 CHANNEL
Port_2_SecondWordResponseDataReadItem17 D7165 CHANNEL
Port_2_SecondWordResponseDataReadItem18 D7175 CHANNEL
Port_2_SecondWordResponseDataReadItem19 D7185 CHANNEL
Port_2_SecondWordResponseDataReadItem2 D7015 CHANNEL
Port_2_SecondWordResponseDataReadItem20 D7195 CHANNEL
Port_2_SecondWordResponseDataReadItem21 D7205 CHANNEL
Port_2_SecondWordResponseDataReadItem22 D7215 CHANNEL
Port_2_SecondWordResponseDataReadItem23 D7225 CHANNEL
Port_2_SecondWordResponseDataReadItem24 D7235 CHANNEL
Port_2_SecondWordResponseDataReadItem25 D7245 CHANNEL
Port_2_SecondWordResponseDataReadItem26 D7255 CHANNEL
Port_2_SecondWordResponseDataReadItem27 D7265 CHANNEL
Port_2_SecondWordResponseDataReadItem28 D7275 CHANNEL
Port_2_SecondWordResponseDataReadItem29 D7285 CHANNEL
Port_2_SecondWordResponseDataReadItem3 D7025 CHANNEL
Port_2_SecondWordResponseDataReadItem30 D7295 CHANNEL
Port_2_SecondWordResponseDataReadItem31 D7305 CHANNEL
Port_2_SecondWordResponseDataReadItem32 D7315 CHANNEL
Port_2_SecondWordResponseDataReadItem33 D7325 CHANNEL
Port_2_SecondWordResponseDataReadItem34 D7335 CHANNEL
Port_2_SecondWordResponseDataReadItem35 D7345 CHANNEL
Port_2_SecondWordResponseDataReadItem36 D7355 CHANNEL
Port_2_SecondWordResponseDataReadItem37 D7365 CHANNEL
Port_2_SecondWordResponseDataReadItem38 D7375 CHANNEL
Port_2_SecondWordResponseDataReadItem39 D7385 CHANNEL
Port_2_SecondWordResponseDataReadItem4 D7035 CHANNEL
Port_2_SecondWordResponseDataReadItem40 D7395 CHANNEL
Port_2_SecondWordResponseDataReadItem41 D7405 CHANNEL
Port_2_SecondWordResponseDataReadItem42 D7415 CHANNEL
Port_2_SecondWordResponseDataReadItem43 D7425 CHANNEL
Port_2_SecondWordResponseDataReadItem44 D7435 CHANNEL
Port_2_SecondWordResponseDataReadItem45 D7445 CHANNEL
Port_2_SecondWordResponseDataReadItem46 D7455 CHANNEL
Port_2_SecondWordResponseDataReadItem47 D7465 CHANNEL
Port_2_SecondWordResponseDataReadItem48 D7475 CHANNEL
Port_2_SecondWordResponseDataReadItem49 D7485 CHANNEL
Port_2_SecondWordResponseDataReadItem5 D7045 CHANNEL
Port_2_SecondWordResponseDataReadItem50 D7495 CHANNEL
Port_2_SecondWordResponseDataReadItem51 D750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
